VERSION 5.8 ;
BUSBITCHARS "[]" ;
DIVIDERCHAR "/" ;
UNITS
    DATABASE MICRONS 1000 ;
END UNITS

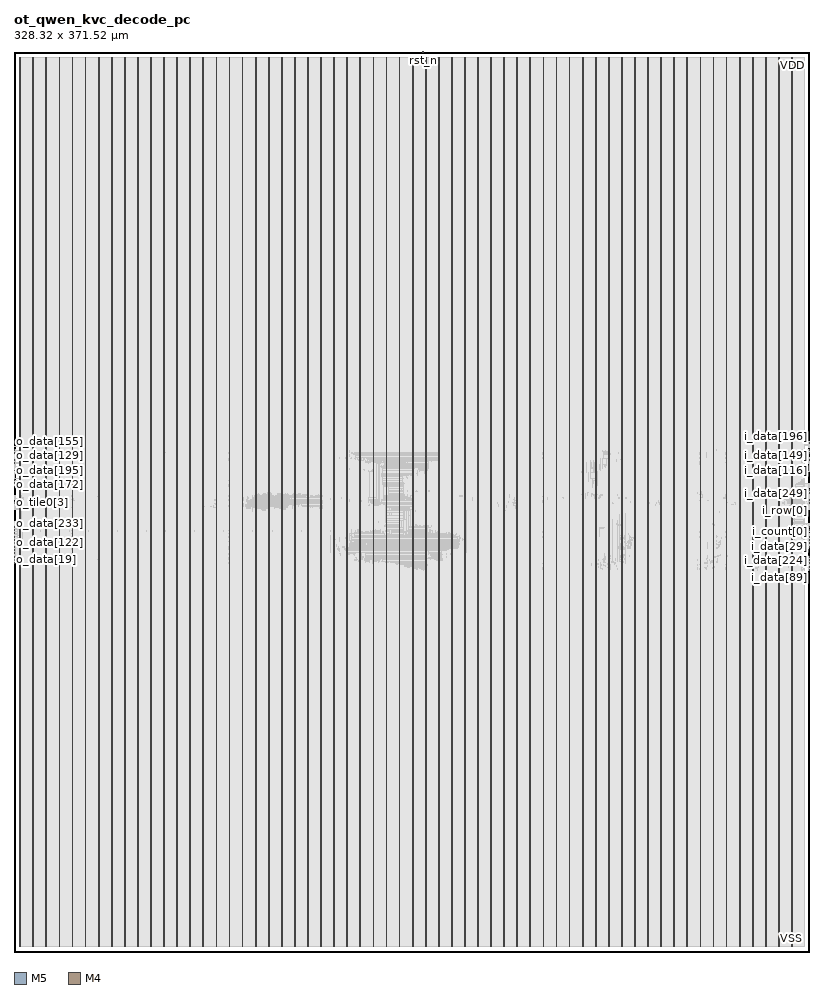
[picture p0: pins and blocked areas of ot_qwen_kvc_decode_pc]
MACRO ot_qwen_kvc_decode_pc
  FOREIGN ot_qwen_kvc_decode_pc 0 0 ;
  CLASS BLOCK ;
  SIZE 328.32 BY 371.52 ;
  PIN clk
    DIRECTION INPUT ;
    USE SIGNAL ;
    PORT
      LAYER M5 ;
        RECT  168.72 371.436 168.744 371.52 ;
    END
  END clk
  PIN fault
    DIRECTION OUTPUT ;
    USE SIGNAL ;
    PORT
      LAYER M5 ;
        RECT  168.816 371.436 168.84 371.52 ;
    END
  END fault
  PIN i_active
    DIRECTION INPUT ;
    USE SIGNAL ;
    PORT
      LAYER M4 ;
        RECT  328.236 173.52 328.32 173.544 ;
    END
  END i_active
  PIN i_count[0]
    DIRECTION INPUT ;
    USE SIGNAL ;
    PORT
      LAYER M4 ;
        RECT  328.236 173.616 328.32 173.64 ;
    END
  END i_count[0]
  PIN i_count[10]
    DIRECTION INPUT ;
    USE SIGNAL ;
    PORT
      LAYER M4 ;
        RECT  328.236 174.576 328.32 174.6 ;
    END
  END i_count[10]
  PIN i_count[1]
    DIRECTION INPUT ;
    USE SIGNAL ;
    PORT
      LAYER M4 ;
        RECT  328.236 173.712 328.32 173.736 ;
    END
  END i_count[1]
  PIN i_count[2]
    DIRECTION INPUT ;
    USE SIGNAL ;
    PORT
      LAYER M4 ;
        RECT  328.236 173.808 328.32 173.832 ;
    END
  END i_count[2]
  PIN i_count[3]
    DIRECTION INPUT ;
    USE SIGNAL ;
    PORT
      LAYER M4 ;
        RECT  328.236 173.904 328.32 173.928 ;
    END
  END i_count[3]
  PIN i_count[4]
    DIRECTION INPUT ;
    USE SIGNAL ;
    PORT
      LAYER M4 ;
        RECT  328.236 174 328.32 174.024 ;
    END
  END i_count[4]
  PIN i_count[5]
    DIRECTION INPUT ;
    USE SIGNAL ;
    PORT
      LAYER M4 ;
        RECT  328.236 174.096 328.32 174.12 ;
    END
  END i_count[5]
  PIN i_count[6]
    DIRECTION INPUT ;
    USE SIGNAL ;
    PORT
      LAYER M4 ;
        RECT  328.236 174.192 328.32 174.216 ;
    END
  END i_count[6]
  PIN i_count[7]
    DIRECTION INPUT ;
    USE SIGNAL ;
    PORT
      LAYER M4 ;
        RECT  328.236 174.288 328.32 174.312 ;
    END
  END i_count[7]
  PIN i_count[8]
    DIRECTION INPUT ;
    USE SIGNAL ;
    PORT
      LAYER M4 ;
        RECT  328.236 174.384 328.32 174.408 ;
    END
  END i_count[8]
  PIN i_count[9]
    DIRECTION INPUT ;
    USE SIGNAL ;
    PORT
      LAYER M4 ;
        RECT  328.236 174.48 328.32 174.504 ;
    END
  END i_count[9]
  PIN i_cr
    DIRECTION OUTPUT ;
    USE SIGNAL ;
    PORT
      LAYER M5 ;
        RECT  168.912 371.436 168.936 371.52 ;
    END
  END i_cr
  PIN i_data[0]
    DIRECTION INPUT ;
    USE SIGNAL ;
    PORT
      LAYER M4 ;
        RECT  328.236 174.672 328.32 174.696 ;
    END
  END i_data[0]
  PIN i_data[100]
    DIRECTION INPUT ;
    USE SIGNAL ;
    PORT
      LAYER M4 ;
        RECT  328.236 158.928 328.32 158.952 ;
    END
  END i_data[100]
  PIN i_data[101]
    DIRECTION INPUT ;
    USE SIGNAL ;
    PORT
      LAYER M4 ;
        RECT  328.236 159.024 328.32 159.048 ;
    END
  END i_data[101]
  PIN i_data[102]
    DIRECTION INPUT ;
    USE SIGNAL ;
    PORT
      LAYER M4 ;
        RECT  328.236 159.12 328.32 159.144 ;
    END
  END i_data[102]
  PIN i_data[103]
    DIRECTION INPUT ;
    USE SIGNAL ;
    PORT
      LAYER M4 ;
        RECT  328.236 159.216 328.32 159.24 ;
    END
  END i_data[103]
  PIN i_data[104]
    DIRECTION INPUT ;
    USE SIGNAL ;
    PORT
      LAYER M4 ;
        RECT  328.236 159.312 328.32 159.336 ;
    END
  END i_data[104]
  PIN i_data[105]
    DIRECTION INPUT ;
    USE SIGNAL ;
    PORT
      LAYER M4 ;
        RECT  328.236 159.408 328.32 159.432 ;
    END
  END i_data[105]
  PIN i_data[106]
    DIRECTION INPUT ;
    USE SIGNAL ;
    PORT
      LAYER M4 ;
        RECT  328.236 159.504 328.32 159.528 ;
    END
  END i_data[106]
  PIN i_data[107]
    DIRECTION INPUT ;
    USE SIGNAL ;
    PORT
      LAYER M4 ;
        RECT  328.236 159.6 328.32 159.624 ;
    END
  END i_data[107]
  PIN i_data[108]
    DIRECTION INPUT ;
    USE SIGNAL ;
    PORT
      LAYER M4 ;
        RECT  328.236 159.696 328.32 159.72 ;
    END
  END i_data[108]
  PIN i_data[109]
    DIRECTION INPUT ;
    USE SIGNAL ;
    PORT
      LAYER M4 ;
        RECT  328.236 159.792 328.32 159.816 ;
    END
  END i_data[109]
  PIN i_data[10]
    DIRECTION INPUT ;
    USE SIGNAL ;
    PORT
      LAYER M4 ;
        RECT  328.236 175.632 328.32 175.656 ;
    END
  END i_data[10]
  PIN i_data[110]
    DIRECTION INPUT ;
    USE SIGNAL ;
    PORT
      LAYER M4 ;
        RECT  328.236 159.888 328.32 159.912 ;
    END
  END i_data[110]
  PIN i_data[111]
    DIRECTION INPUT ;
    USE SIGNAL ;
    PORT
      LAYER M4 ;
        RECT  328.236 159.984 328.32 160.008 ;
    END
  END i_data[111]
  PIN i_data[112]
    DIRECTION INPUT ;
    USE SIGNAL ;
    PORT
      LAYER M4 ;
        RECT  328.236 160.08 328.32 160.104 ;
    END
  END i_data[112]
  PIN i_data[113]
    DIRECTION INPUT ;
    USE SIGNAL ;
    PORT
      LAYER M4 ;
        RECT  328.236 160.176 328.32 160.2 ;
    END
  END i_data[113]
  PIN i_data[114]
    DIRECTION INPUT ;
    USE SIGNAL ;
    PORT
      LAYER M4 ;
        RECT  328.236 160.272 328.32 160.296 ;
    END
  END i_data[114]
  PIN i_data[115]
    DIRECTION INPUT ;
    USE SIGNAL ;
    PORT
      LAYER M4 ;
        RECT  328.236 160.368 328.32 160.392 ;
    END
  END i_data[115]
  PIN i_data[116]
    DIRECTION INPUT ;
    USE SIGNAL ;
    PORT
      LAYER M4 ;
        RECT  328.236 201.936 328.32 201.96 ;
    END
  END i_data[116]
  PIN i_data[117]
    DIRECTION INPUT ;
    USE SIGNAL ;
    PORT
      LAYER M4 ;
        RECT  328.236 202.032 328.32 202.056 ;
    END
  END i_data[117]
  PIN i_data[118]
    DIRECTION INPUT ;
    USE SIGNAL ;
    PORT
      LAYER M4 ;
        RECT  328.236 202.128 328.32 202.152 ;
    END
  END i_data[118]
  PIN i_data[119]
    DIRECTION INPUT ;
    USE SIGNAL ;
    PORT
      LAYER M4 ;
        RECT  328.236 202.224 328.32 202.248 ;
    END
  END i_data[119]
  PIN i_data[11]
    DIRECTION INPUT ;
    USE SIGNAL ;
    PORT
      LAYER M4 ;
        RECT  328.236 175.728 328.32 175.752 ;
    END
  END i_data[11]
  PIN i_data[120]
    DIRECTION INPUT ;
    USE SIGNAL ;
    PORT
      LAYER M4 ;
        RECT  328.236 202.32 328.32 202.344 ;
    END
  END i_data[120]
  PIN i_data[121]
    DIRECTION INPUT ;
    USE SIGNAL ;
    PORT
      LAYER M4 ;
        RECT  328.236 202.416 328.32 202.44 ;
    END
  END i_data[121]
  PIN i_data[122]
    DIRECTION INPUT ;
    USE SIGNAL ;
    PORT
      LAYER M4 ;
        RECT  328.236 202.512 328.32 202.536 ;
    END
  END i_data[122]
  PIN i_data[123]
    DIRECTION INPUT ;
    USE SIGNAL ;
    PORT
      LAYER M4 ;
        RECT  328.236 202.608 328.32 202.632 ;
    END
  END i_data[123]
  PIN i_data[124]
    DIRECTION INPUT ;
    USE SIGNAL ;
    PORT
      LAYER M4 ;
        RECT  328.236 202.704 328.32 202.728 ;
    END
  END i_data[124]
  PIN i_data[125]
    DIRECTION INPUT ;
    USE SIGNAL ;
    PORT
      LAYER M4 ;
        RECT  328.236 202.8 328.32 202.824 ;
    END
  END i_data[125]
  PIN i_data[126]
    DIRECTION INPUT ;
    USE SIGNAL ;
    PORT
      LAYER M4 ;
        RECT  328.236 202.896 328.32 202.92 ;
    END
  END i_data[126]
  PIN i_data[127]
    DIRECTION INPUT ;
    USE SIGNAL ;
    PORT
      LAYER M4 ;
        RECT  328.236 202.992 328.32 203.016 ;
    END
  END i_data[127]
  PIN i_data[128]
    DIRECTION INPUT ;
    USE SIGNAL ;
    PORT
      LAYER M4 ;
        RECT  328.236 203.088 328.32 203.112 ;
    END
  END i_data[128]
  PIN i_data[129]
    DIRECTION INPUT ;
    USE SIGNAL ;
    PORT
      LAYER M4 ;
        RECT  328.236 203.184 328.32 203.208 ;
    END
  END i_data[129]
  PIN i_data[12]
    DIRECTION INPUT ;
    USE SIGNAL ;
    PORT
      LAYER M4 ;
        RECT  328.236 175.824 328.32 175.848 ;
    END
  END i_data[12]
  PIN i_data[130]
    DIRECTION INPUT ;
    USE SIGNAL ;
    PORT
      LAYER M4 ;
        RECT  328.236 203.28 328.32 203.304 ;
    END
  END i_data[130]
  PIN i_data[131]
    DIRECTION INPUT ;
    USE SIGNAL ;
    PORT
      LAYER M4 ;
        RECT  328.236 203.376 328.32 203.4 ;
    END
  END i_data[131]
  PIN i_data[132]
    DIRECTION INPUT ;
    USE SIGNAL ;
    PORT
      LAYER M4 ;
        RECT  328.236 203.472 328.32 203.496 ;
    END
  END i_data[132]
  PIN i_data[133]
    DIRECTION INPUT ;
    USE SIGNAL ;
    PORT
      LAYER M4 ;
        RECT  328.236 203.568 328.32 203.592 ;
    END
  END i_data[133]
  PIN i_data[134]
    DIRECTION INPUT ;
    USE SIGNAL ;
    PORT
      LAYER M4 ;
        RECT  328.236 203.664 328.32 203.688 ;
    END
  END i_data[134]
  PIN i_data[135]
    DIRECTION INPUT ;
    USE SIGNAL ;
    PORT
      LAYER M4 ;
        RECT  328.236 203.76 328.32 203.784 ;
    END
  END i_data[135]
  PIN i_data[136]
    DIRECTION INPUT ;
    USE SIGNAL ;
    PORT
      LAYER M4 ;
        RECT  328.236 203.856 328.32 203.88 ;
    END
  END i_data[136]
  PIN i_data[137]
    DIRECTION INPUT ;
    USE SIGNAL ;
    PORT
      LAYER M4 ;
        RECT  328.236 203.952 328.32 203.976 ;
    END
  END i_data[137]
  PIN i_data[138]
    DIRECTION INPUT ;
    USE SIGNAL ;
    PORT
      LAYER M4 ;
        RECT  328.236 204.048 328.32 204.072 ;
    END
  END i_data[138]
  PIN i_data[139]
    DIRECTION INPUT ;
    USE SIGNAL ;
    PORT
      LAYER M4 ;
        RECT  328.236 204.144 328.32 204.168 ;
    END
  END i_data[139]
  PIN i_data[13]
    DIRECTION INPUT ;
    USE SIGNAL ;
    PORT
      LAYER M4 ;
        RECT  328.236 175.92 328.32 175.944 ;
    END
  END i_data[13]
  PIN i_data[140]
    DIRECTION INPUT ;
    USE SIGNAL ;
    PORT
      LAYER M4 ;
        RECT  328.236 204.24 328.32 204.264 ;
    END
  END i_data[140]
  PIN i_data[141]
    DIRECTION INPUT ;
    USE SIGNAL ;
    PORT
      LAYER M4 ;
        RECT  328.236 204.336 328.32 204.36 ;
    END
  END i_data[141]
  PIN i_data[142]
    DIRECTION INPUT ;
    USE SIGNAL ;
    PORT
      LAYER M4 ;
        RECT  328.236 204.432 328.32 204.456 ;
    END
  END i_data[142]
  PIN i_data[143]
    DIRECTION INPUT ;
    USE SIGNAL ;
    PORT
      LAYER M4 ;
        RECT  328.236 204.528 328.32 204.552 ;
    END
  END i_data[143]
  PIN i_data[144]
    DIRECTION INPUT ;
    USE SIGNAL ;
    PORT
      LAYER M4 ;
        RECT  328.236 204.624 328.32 204.648 ;
    END
  END i_data[144]
  PIN i_data[145]
    DIRECTION INPUT ;
    USE SIGNAL ;
    PORT
      LAYER M4 ;
        RECT  328.236 204.72 328.32 204.744 ;
    END
  END i_data[145]
  PIN i_data[146]
    DIRECTION INPUT ;
    USE SIGNAL ;
    PORT
      LAYER M4 ;
        RECT  328.236 204.816 328.32 204.84 ;
    END
  END i_data[146]
  PIN i_data[147]
    DIRECTION INPUT ;
    USE SIGNAL ;
    PORT
      LAYER M4 ;
        RECT  328.236 204.912 328.32 204.936 ;
    END
  END i_data[147]
  PIN i_data[148]
    DIRECTION INPUT ;
    USE SIGNAL ;
    PORT
      LAYER M4 ;
        RECT  328.236 205.008 328.32 205.032 ;
    END
  END i_data[148]
  PIN i_data[149]
    DIRECTION INPUT ;
    USE SIGNAL ;
    PORT
      LAYER M4 ;
        RECT  328.236 205.104 328.32 205.128 ;
    END
  END i_data[149]
  PIN i_data[14]
    DIRECTION INPUT ;
    USE SIGNAL ;
    PORT
      LAYER M4 ;
        RECT  328.236 176.016 328.32 176.04 ;
    END
  END i_data[14]
  PIN i_data[150]
    DIRECTION INPUT ;
    USE SIGNAL ;
    PORT
      LAYER M4 ;
        RECT  328.236 205.2 328.32 205.224 ;
    END
  END i_data[150]
  PIN i_data[151]
    DIRECTION INPUT ;
    USE SIGNAL ;
    PORT
      LAYER M4 ;
        RECT  328.236 205.296 328.32 205.32 ;
    END
  END i_data[151]
  PIN i_data[152]
    DIRECTION INPUT ;
    USE SIGNAL ;
    PORT
      LAYER M4 ;
        RECT  328.236 205.392 328.32 205.416 ;
    END
  END i_data[152]
  PIN i_data[153]
    DIRECTION INPUT ;
    USE SIGNAL ;
    PORT
      LAYER M4 ;
        RECT  328.236 205.488 328.32 205.512 ;
    END
  END i_data[153]
  PIN i_data[154]
    DIRECTION INPUT ;
    USE SIGNAL ;
    PORT
      LAYER M4 ;
        RECT  328.236 205.584 328.32 205.608 ;
    END
  END i_data[154]
  PIN i_data[155]
    DIRECTION INPUT ;
    USE SIGNAL ;
    PORT
      LAYER M4 ;
        RECT  328.236 205.68 328.32 205.704 ;
    END
  END i_data[155]
  PIN i_data[156]
    DIRECTION INPUT ;
    USE SIGNAL ;
    PORT
      LAYER M4 ;
        RECT  328.236 205.776 328.32 205.8 ;
    END
  END i_data[156]
  PIN i_data[157]
    DIRECTION INPUT ;
    USE SIGNAL ;
    PORT
      LAYER M4 ;
        RECT  328.236 205.872 328.32 205.896 ;
    END
  END i_data[157]
  PIN i_data[158]
    DIRECTION INPUT ;
    USE SIGNAL ;
    PORT
      LAYER M4 ;
        RECT  328.236 205.968 328.32 205.992 ;
    END
  END i_data[158]
  PIN i_data[159]
    DIRECTION INPUT ;
    USE SIGNAL ;
    PORT
      LAYER M4 ;
        RECT  328.236 206.064 328.32 206.088 ;
    END
  END i_data[159]
  PIN i_data[15]
    DIRECTION INPUT ;
    USE SIGNAL ;
    PORT
      LAYER M4 ;
        RECT  328.236 176.112 328.32 176.136 ;
    END
  END i_data[15]
  PIN i_data[160]
    DIRECTION INPUT ;
    USE SIGNAL ;
    PORT
      LAYER M4 ;
        RECT  328.236 206.16 328.32 206.184 ;
    END
  END i_data[160]
  PIN i_data[161]
    DIRECTION INPUT ;
    USE SIGNAL ;
    PORT
      LAYER M4 ;
        RECT  328.236 206.256 328.32 206.28 ;
    END
  END i_data[161]
  PIN i_data[162]
    DIRECTION INPUT ;
    USE SIGNAL ;
    PORT
      LAYER M4 ;
        RECT  328.236 206.352 328.32 206.376 ;
    END
  END i_data[162]
  PIN i_data[163]
    DIRECTION INPUT ;
    USE SIGNAL ;
    PORT
      LAYER M4 ;
        RECT  328.236 206.448 328.32 206.472 ;
    END
  END i_data[163]
  PIN i_data[164]
    DIRECTION INPUT ;
    USE SIGNAL ;
    PORT
      LAYER M4 ;
        RECT  328.236 206.544 328.32 206.568 ;
    END
  END i_data[164]
  PIN i_data[165]
    DIRECTION INPUT ;
    USE SIGNAL ;
    PORT
      LAYER M4 ;
        RECT  328.236 206.64 328.32 206.664 ;
    END
  END i_data[165]
  PIN i_data[166]
    DIRECTION INPUT ;
    USE SIGNAL ;
    PORT
      LAYER M4 ;
        RECT  328.236 206.736 328.32 206.76 ;
    END
  END i_data[166]
  PIN i_data[167]
    DIRECTION INPUT ;
    USE SIGNAL ;
    PORT
      LAYER M4 ;
        RECT  328.236 206.832 328.32 206.856 ;
    END
  END i_data[167]
  PIN i_data[168]
    DIRECTION INPUT ;
    USE SIGNAL ;
    PORT
      LAYER M4 ;
        RECT  328.236 206.928 328.32 206.952 ;
    END
  END i_data[168]
  PIN i_data[169]
    DIRECTION INPUT ;
    USE SIGNAL ;
    PORT
      LAYER M4 ;
        RECT  328.236 207.024 328.32 207.048 ;
    END
  END i_data[169]
  PIN i_data[16]
    DIRECTION INPUT ;
    USE SIGNAL ;
    PORT
      LAYER M4 ;
        RECT  328.236 176.208 328.32 176.232 ;
    END
  END i_data[16]
  PIN i_data[170]
    DIRECTION INPUT ;
    USE SIGNAL ;
    PORT
      LAYER M4 ;
        RECT  328.236 207.12 328.32 207.144 ;
    END
  END i_data[170]
  PIN i_data[171]
    DIRECTION INPUT ;
    USE SIGNAL ;
    PORT
      LAYER M4 ;
        RECT  328.236 207.216 328.32 207.24 ;
    END
  END i_data[171]
  PIN i_data[172]
    DIRECTION INPUT ;
    USE SIGNAL ;
    PORT
      LAYER M4 ;
        RECT  328.236 207.312 328.32 207.336 ;
    END
  END i_data[172]
  PIN i_data[173]
    DIRECTION INPUT ;
    USE SIGNAL ;
    PORT
      LAYER M4 ;
        RECT  328.236 207.408 328.32 207.432 ;
    END
  END i_data[173]
  PIN i_data[174]
    DIRECTION INPUT ;
    USE SIGNAL ;
    PORT
      LAYER M4 ;
        RECT  328.236 207.504 328.32 207.528 ;
    END
  END i_data[174]
  PIN i_data[175]
    DIRECTION INPUT ;
    USE SIGNAL ;
    PORT
      LAYER M4 ;
        RECT  328.236 207.6 328.32 207.624 ;
    END
  END i_data[175]
  PIN i_data[176]
    DIRECTION INPUT ;
    USE SIGNAL ;
    PORT
      LAYER M4 ;
        RECT  328.236 207.696 328.32 207.72 ;
    END
  END i_data[176]
  PIN i_data[177]
    DIRECTION INPUT ;
    USE SIGNAL ;
    PORT
      LAYER M4 ;
        RECT  328.236 207.792 328.32 207.816 ;
    END
  END i_data[177]
  PIN i_data[178]
    DIRECTION INPUT ;
    USE SIGNAL ;
    PORT
      LAYER M4 ;
        RECT  328.236 207.888 328.32 207.912 ;
    END
  END i_data[178]
  PIN i_data[179]
    DIRECTION INPUT ;
    USE SIGNAL ;
    PORT
      LAYER M4 ;
        RECT  328.236 207.984 328.32 208.008 ;
    END
  END i_data[179]
  PIN i_data[17]
    DIRECTION INPUT ;
    USE SIGNAL ;
    PORT
      LAYER M4 ;
        RECT  328.236 176.304 328.32 176.328 ;
    END
  END i_data[17]
  PIN i_data[180]
    DIRECTION INPUT ;
    USE SIGNAL ;
    PORT
      LAYER M4 ;
        RECT  328.236 208.08 328.32 208.104 ;
    END
  END i_data[180]
  PIN i_data[181]
    DIRECTION INPUT ;
    USE SIGNAL ;
    PORT
      LAYER M4 ;
        RECT  328.236 208.176 328.32 208.2 ;
    END
  END i_data[181]
  PIN i_data[182]
    DIRECTION INPUT ;
    USE SIGNAL ;
    PORT
      LAYER M4 ;
        RECT  328.236 208.272 328.32 208.296 ;
    END
  END i_data[182]
  PIN i_data[183]
    DIRECTION INPUT ;
    USE SIGNAL ;
    PORT
      LAYER M4 ;
        RECT  328.236 208.368 328.32 208.392 ;
    END
  END i_data[183]
  PIN i_data[184]
    DIRECTION INPUT ;
    USE SIGNAL ;
    PORT
      LAYER M4 ;
        RECT  328.236 208.464 328.32 208.488 ;
    END
  END i_data[184]
  PIN i_data[185]
    DIRECTION INPUT ;
    USE SIGNAL ;
    PORT
      LAYER M4 ;
        RECT  328.236 208.56 328.32 208.584 ;
    END
  END i_data[185]
  PIN i_data[186]
    DIRECTION INPUT ;
    USE SIGNAL ;
    PORT
      LAYER M4 ;
        RECT  328.236 208.656 328.32 208.68 ;
    END
  END i_data[186]
  PIN i_data[187]
    DIRECTION INPUT ;
    USE SIGNAL ;
    PORT
      LAYER M4 ;
        RECT  328.236 208.752 328.32 208.776 ;
    END
  END i_data[187]
  PIN i_data[188]
    DIRECTION INPUT ;
    USE SIGNAL ;
    PORT
      LAYER M4 ;
        RECT  328.236 208.848 328.32 208.872 ;
    END
  END i_data[188]
  PIN i_data[189]
    DIRECTION INPUT ;
    USE SIGNAL ;
    PORT
      LAYER M4 ;
        RECT  328.236 208.944 328.32 208.968 ;
    END
  END i_data[189]
  PIN i_data[18]
    DIRECTION INPUT ;
    USE SIGNAL ;
    PORT
      LAYER M4 ;
        RECT  328.236 176.4 328.32 176.424 ;
    END
  END i_data[18]
  PIN i_data[190]
    DIRECTION INPUT ;
    USE SIGNAL ;
    PORT
      LAYER M4 ;
        RECT  328.236 209.04 328.32 209.064 ;
    END
  END i_data[190]
  PIN i_data[191]
    DIRECTION INPUT ;
    USE SIGNAL ;
    PORT
      LAYER M4 ;
        RECT  328.236 209.136 328.32 209.16 ;
    END
  END i_data[191]
  PIN i_data[192]
    DIRECTION INPUT ;
    USE SIGNAL ;
    PORT
      LAYER M4 ;
        RECT  328.236 209.232 328.32 209.256 ;
    END
  END i_data[192]
  PIN i_data[193]
    DIRECTION INPUT ;
    USE SIGNAL ;
    PORT
      LAYER M4 ;
        RECT  328.236 209.328 328.32 209.352 ;
    END
  END i_data[193]
  PIN i_data[194]
    DIRECTION INPUT ;
    USE SIGNAL ;
    PORT
      LAYER M4 ;
        RECT  328.236 209.424 328.32 209.448 ;
    END
  END i_data[194]
  PIN i_data[195]
    DIRECTION INPUT ;
    USE SIGNAL ;
    PORT
      LAYER M4 ;
        RECT  328.236 209.52 328.32 209.544 ;
    END
  END i_data[195]
  PIN i_data[196]
    DIRECTION INPUT ;
    USE SIGNAL ;
    PORT
      LAYER M4 ;
        RECT  328.236 209.616 328.32 209.64 ;
    END
  END i_data[196]
  PIN i_data[197]
    DIRECTION INPUT ;
    USE SIGNAL ;
    PORT
      LAYER M4 ;
        RECT  328.236 209.712 328.32 209.736 ;
    END
  END i_data[197]
  PIN i_data[198]
    DIRECTION INPUT ;
    USE SIGNAL ;
    PORT
      LAYER M4 ;
        RECT  328.236 209.808 328.32 209.832 ;
    END
  END i_data[198]
  PIN i_data[199]
    DIRECTION INPUT ;
    USE SIGNAL ;
    PORT
      LAYER M4 ;
        RECT  328.236 209.904 328.32 209.928 ;
    END
  END i_data[199]
  PIN i_data[19]
    DIRECTION INPUT ;
    USE SIGNAL ;
    PORT
      LAYER M4 ;
        RECT  328.236 176.496 328.32 176.52 ;
    END
  END i_data[19]
  PIN i_data[1]
    DIRECTION INPUT ;
    USE SIGNAL ;
    PORT
      LAYER M4 ;
        RECT  328.236 174.768 328.32 174.792 ;
    END
  END i_data[1]
  PIN i_data[200]
    DIRECTION INPUT ;
    USE SIGNAL ;
    PORT
      LAYER M4 ;
        RECT  328.236 210 328.32 210.024 ;
    END
  END i_data[200]
  PIN i_data[201]
    DIRECTION INPUT ;
    USE SIGNAL ;
    PORT
      LAYER M4 ;
        RECT  328.236 210.096 328.32 210.12 ;
    END
  END i_data[201]
  PIN i_data[202]
    DIRECTION INPUT ;
    USE SIGNAL ;
    PORT
      LAYER M4 ;
        RECT  328.236 210.192 328.32 210.216 ;
    END
  END i_data[202]
  PIN i_data[203]
    DIRECTION INPUT ;
    USE SIGNAL ;
    PORT
      LAYER M4 ;
        RECT  328.236 210.288 328.32 210.312 ;
    END
  END i_data[203]
  PIN i_data[204]
    DIRECTION INPUT ;
    USE SIGNAL ;
    PORT
      LAYER M4 ;
        RECT  328.236 210.384 328.32 210.408 ;
    END
  END i_data[204]
  PIN i_data[205]
    DIRECTION INPUT ;
    USE SIGNAL ;
    PORT
      LAYER M4 ;
        RECT  328.236 210.48 328.32 210.504 ;
    END
  END i_data[205]
  PIN i_data[206]
    DIRECTION INPUT ;
    USE SIGNAL ;
    PORT
      LAYER M4 ;
        RECT  328.236 210.576 328.32 210.6 ;
    END
  END i_data[206]
  PIN i_data[207]
    DIRECTION INPUT ;
    USE SIGNAL ;
    PORT
      LAYER M4 ;
        RECT  328.236 210.672 328.32 210.696 ;
    END
  END i_data[207]
  PIN i_data[208]
    DIRECTION INPUT ;
    USE SIGNAL ;
    PORT
      LAYER M4 ;
        RECT  328.236 210.768 328.32 210.792 ;
    END
  END i_data[208]
  PIN i_data[209]
    DIRECTION INPUT ;
    USE SIGNAL ;
    PORT
      LAYER M4 ;
        RECT  328.236 210.864 328.32 210.888 ;
    END
  END i_data[209]
  PIN i_data[20]
    DIRECTION INPUT ;
    USE SIGNAL ;
    PORT
      LAYER M4 ;
        RECT  328.236 166.608 328.32 166.632 ;
    END
  END i_data[20]
  PIN i_data[210]
    DIRECTION INPUT ;
    USE SIGNAL ;
    PORT
      LAYER M4 ;
        RECT  328.236 210.96 328.32 210.984 ;
    END
  END i_data[210]
  PIN i_data[211]
    DIRECTION INPUT ;
    USE SIGNAL ;
    PORT
      LAYER M4 ;
        RECT  328.236 211.056 328.32 211.08 ;
    END
  END i_data[211]
  PIN i_data[212]
    DIRECTION INPUT ;
    USE SIGNAL ;
    PORT
      LAYER M4 ;
        RECT  328.236 160.464 328.32 160.488 ;
    END
  END i_data[212]
  PIN i_data[213]
    DIRECTION INPUT ;
    USE SIGNAL ;
    PORT
      LAYER M4 ;
        RECT  328.236 160.56 328.32 160.584 ;
    END
  END i_data[213]
  PIN i_data[214]
    DIRECTION INPUT ;
    USE SIGNAL ;
    PORT
      LAYER M4 ;
        RECT  328.236 160.656 328.32 160.68 ;
    END
  END i_data[214]
  PIN i_data[215]
    DIRECTION INPUT ;
    USE SIGNAL ;
    PORT
      LAYER M4 ;
        RECT  328.236 160.752 328.32 160.776 ;
    END
  END i_data[215]
  PIN i_data[216]
    DIRECTION INPUT ;
    USE SIGNAL ;
    PORT
      LAYER M4 ;
        RECT  328.236 160.848 328.32 160.872 ;
    END
  END i_data[216]
  PIN i_data[217]
    DIRECTION INPUT ;
    USE SIGNAL ;
    PORT
      LAYER M4 ;
        RECT  328.236 160.944 328.32 160.968 ;
    END
  END i_data[217]
  PIN i_data[218]
    DIRECTION INPUT ;
    USE SIGNAL ;
    PORT
      LAYER M4 ;
        RECT  328.236 161.04 328.32 161.064 ;
    END
  END i_data[218]
  PIN i_data[219]
    DIRECTION INPUT ;
    USE SIGNAL ;
    PORT
      LAYER M4 ;
        RECT  328.236 161.136 328.32 161.16 ;
    END
  END i_data[219]
  PIN i_data[21]
    DIRECTION INPUT ;
    USE SIGNAL ;
    PORT
      LAYER M4 ;
        RECT  328.236 166.704 328.32 166.728 ;
    END
  END i_data[21]
  PIN i_data[220]
    DIRECTION INPUT ;
    USE SIGNAL ;
    PORT
      LAYER M4 ;
        RECT  328.236 161.232 328.32 161.256 ;
    END
  END i_data[220]
  PIN i_data[221]
    DIRECTION INPUT ;
    USE SIGNAL ;
    PORT
      LAYER M4 ;
        RECT  328.236 161.328 328.32 161.352 ;
    END
  END i_data[221]
  PIN i_data[222]
    DIRECTION INPUT ;
    USE SIGNAL ;
    PORT
      LAYER M4 ;
        RECT  328.236 161.424 328.32 161.448 ;
    END
  END i_data[222]
  PIN i_data[223]
    DIRECTION INPUT ;
    USE SIGNAL ;
    PORT
      LAYER M4 ;
        RECT  328.236 161.52 328.32 161.544 ;
    END
  END i_data[223]
  PIN i_data[224]
    DIRECTION INPUT ;
    USE SIGNAL ;
    PORT
      LAYER M4 ;
        RECT  328.236 161.616 328.32 161.64 ;
    END
  END i_data[224]
  PIN i_data[225]
    DIRECTION INPUT ;
    USE SIGNAL ;
    PORT
      LAYER M4 ;
        RECT  328.236 161.712 328.32 161.736 ;
    END
  END i_data[225]
  PIN i_data[226]
    DIRECTION INPUT ;
    USE SIGNAL ;
    PORT
      LAYER M4 ;
        RECT  328.236 161.808 328.32 161.832 ;
    END
  END i_data[226]
  PIN i_data[227]
    DIRECTION INPUT ;
    USE SIGNAL ;
    PORT
      LAYER M4 ;
        RECT  328.236 161.904 328.32 161.928 ;
    END
  END i_data[227]
  PIN i_data[228]
    DIRECTION INPUT ;
    USE SIGNAL ;
    PORT
      LAYER M4 ;
        RECT  328.236 162 328.32 162.024 ;
    END
  END i_data[228]
  PIN i_data[229]
    DIRECTION INPUT ;
    USE SIGNAL ;
    PORT
      LAYER M4 ;
        RECT  328.236 162.096 328.32 162.12 ;
    END
  END i_data[229]
  PIN i_data[22]
    DIRECTION INPUT ;
    USE SIGNAL ;
    PORT
      LAYER M4 ;
        RECT  328.236 166.8 328.32 166.824 ;
    END
  END i_data[22]
  PIN i_data[230]
    DIRECTION INPUT ;
    USE SIGNAL ;
    PORT
      LAYER M4 ;
        RECT  328.236 162.192 328.32 162.216 ;
    END
  END i_data[230]
  PIN i_data[231]
    DIRECTION INPUT ;
    USE SIGNAL ;
    PORT
      LAYER M4 ;
        RECT  328.236 162.288 328.32 162.312 ;
    END
  END i_data[231]
  PIN i_data[232]
    DIRECTION INPUT ;
    USE SIGNAL ;
    PORT
      LAYER M4 ;
        RECT  328.236 162.384 328.32 162.408 ;
    END
  END i_data[232]
  PIN i_data[233]
    DIRECTION INPUT ;
    USE SIGNAL ;
    PORT
      LAYER M4 ;
        RECT  328.236 162.48 328.32 162.504 ;
    END
  END i_data[233]
  PIN i_data[234]
    DIRECTION INPUT ;
    USE SIGNAL ;
    PORT
      LAYER M4 ;
        RECT  328.236 162.576 328.32 162.6 ;
    END
  END i_data[234]
  PIN i_data[235]
    DIRECTION INPUT ;
    USE SIGNAL ;
    PORT
      LAYER M4 ;
        RECT  328.236 162.672 328.32 162.696 ;
    END
  END i_data[235]
  PIN i_data[236]
    DIRECTION INPUT ;
    USE SIGNAL ;
    PORT
      LAYER M4 ;
        RECT  328.236 162.768 328.32 162.792 ;
    END
  END i_data[236]
  PIN i_data[237]
    DIRECTION INPUT ;
    USE SIGNAL ;
    PORT
      LAYER M4 ;
        RECT  328.236 162.864 328.32 162.888 ;
    END
  END i_data[237]
  PIN i_data[238]
    DIRECTION INPUT ;
    USE SIGNAL ;
    PORT
      LAYER M4 ;
        RECT  328.236 162.96 328.32 162.984 ;
    END
  END i_data[238]
  PIN i_data[239]
    DIRECTION INPUT ;
    USE SIGNAL ;
    PORT
      LAYER M4 ;
        RECT  328.236 163.056 328.32 163.08 ;
    END
  END i_data[239]
  PIN i_data[23]
    DIRECTION INPUT ;
    USE SIGNAL ;
    PORT
      LAYER M4 ;
        RECT  328.236 166.896 328.32 166.92 ;
    END
  END i_data[23]
  PIN i_data[240]
    DIRECTION INPUT ;
    USE SIGNAL ;
    PORT
      LAYER M4 ;
        RECT  328.236 163.152 328.32 163.176 ;
    END
  END i_data[240]
  PIN i_data[241]
    DIRECTION INPUT ;
    USE SIGNAL ;
    PORT
      LAYER M4 ;
        RECT  328.236 163.248 328.32 163.272 ;
    END
  END i_data[241]
  PIN i_data[242]
    DIRECTION INPUT ;
    USE SIGNAL ;
    PORT
      LAYER M4 ;
        RECT  328.236 163.344 328.32 163.368 ;
    END
  END i_data[242]
  PIN i_data[243]
    DIRECTION INPUT ;
    USE SIGNAL ;
    PORT
      LAYER M4 ;
        RECT  328.236 163.44 328.32 163.464 ;
    END
  END i_data[243]
  PIN i_data[244]
    DIRECTION INPUT ;
    USE SIGNAL ;
    PORT
      LAYER M4 ;
        RECT  328.236 188.88 328.32 188.904 ;
    END
  END i_data[244]
  PIN i_data[245]
    DIRECTION INPUT ;
    USE SIGNAL ;
    PORT
      LAYER M4 ;
        RECT  328.236 188.976 328.32 189 ;
    END
  END i_data[245]
  PIN i_data[246]
    DIRECTION INPUT ;
    USE SIGNAL ;
    PORT
      LAYER M4 ;
        RECT  328.236 189.072 328.32 189.096 ;
    END
  END i_data[246]
  PIN i_data[247]
    DIRECTION INPUT ;
    USE SIGNAL ;
    PORT
      LAYER M4 ;
        RECT  328.236 189.168 328.32 189.192 ;
    END
  END i_data[247]
  PIN i_data[248]
    DIRECTION INPUT ;
    USE SIGNAL ;
    PORT
      LAYER M4 ;
        RECT  328.236 189.264 328.32 189.288 ;
    END
  END i_data[248]
  PIN i_data[249]
    DIRECTION INPUT ;
    USE SIGNAL ;
    PORT
      LAYER M4 ;
        RECT  328.236 189.36 328.32 189.384 ;
    END
  END i_data[249]
  PIN i_data[24]
    DIRECTION INPUT ;
    USE SIGNAL ;
    PORT
      LAYER M4 ;
        RECT  328.236 166.992 328.32 167.016 ;
    END
  END i_data[24]
  PIN i_data[250]
    DIRECTION INPUT ;
    USE SIGNAL ;
    PORT
      LAYER M4 ;
        RECT  328.236 189.456 328.32 189.48 ;
    END
  END i_data[250]
  PIN i_data[251]
    DIRECTION INPUT ;
    USE SIGNAL ;
    PORT
      LAYER M4 ;
        RECT  328.236 189.552 328.32 189.576 ;
    END
  END i_data[251]
  PIN i_data[252]
    DIRECTION INPUT ;
    USE SIGNAL ;
    PORT
      LAYER M4 ;
        RECT  328.236 189.648 328.32 189.672 ;
    END
  END i_data[252]
  PIN i_data[253]
    DIRECTION INPUT ;
    USE SIGNAL ;
    PORT
      LAYER M4 ;
        RECT  328.236 189.744 328.32 189.768 ;
    END
  END i_data[253]
  PIN i_data[254]
    DIRECTION INPUT ;
    USE SIGNAL ;
    PORT
      LAYER M4 ;
        RECT  328.236 189.84 328.32 189.864 ;
    END
  END i_data[254]
  PIN i_data[255]
    DIRECTION INPUT ;
    USE SIGNAL ;
    PORT
      LAYER M4 ;
        RECT  328.236 189.936 328.32 189.96 ;
    END
  END i_data[255]
  PIN i_data[25]
    DIRECTION INPUT ;
    USE SIGNAL ;
    PORT
      LAYER M4 ;
        RECT  328.236 167.088 328.32 167.112 ;
    END
  END i_data[25]
  PIN i_data[26]
    DIRECTION INPUT ;
    USE SIGNAL ;
    PORT
      LAYER M4 ;
        RECT  328.236 167.184 328.32 167.208 ;
    END
  END i_data[26]
  PIN i_data[27]
    DIRECTION INPUT ;
    USE SIGNAL ;
    PORT
      LAYER M4 ;
        RECT  328.236 167.28 328.32 167.304 ;
    END
  END i_data[27]
  PIN i_data[28]
    DIRECTION INPUT ;
    USE SIGNAL ;
    PORT
      LAYER M4 ;
        RECT  328.236 167.376 328.32 167.4 ;
    END
  END i_data[28]
  PIN i_data[29]
    DIRECTION INPUT ;
    USE SIGNAL ;
    PORT
      LAYER M4 ;
        RECT  328.236 167.472 328.32 167.496 ;
    END
  END i_data[29]
  PIN i_data[2]
    DIRECTION INPUT ;
    USE SIGNAL ;
    PORT
      LAYER M4 ;
        RECT  328.236 174.864 328.32 174.888 ;
    END
  END i_data[2]
  PIN i_data[30]
    DIRECTION INPUT ;
    USE SIGNAL ;
    PORT
      LAYER M4 ;
        RECT  328.236 167.568 328.32 167.592 ;
    END
  END i_data[30]
  PIN i_data[31]
    DIRECTION INPUT ;
    USE SIGNAL ;
    PORT
      LAYER M4 ;
        RECT  328.236 167.664 328.32 167.688 ;
    END
  END i_data[31]
  PIN i_data[32]
    DIRECTION INPUT ;
    USE SIGNAL ;
    PORT
      LAYER M4 ;
        RECT  328.236 167.76 328.32 167.784 ;
    END
  END i_data[32]
  PIN i_data[33]
    DIRECTION INPUT ;
    USE SIGNAL ;
    PORT
      LAYER M4 ;
        RECT  328.236 167.856 328.32 167.88 ;
    END
  END i_data[33]
  PIN i_data[34]
    DIRECTION INPUT ;
    USE SIGNAL ;
    PORT
      LAYER M4 ;
        RECT  328.236 167.952 328.32 167.976 ;
    END
  END i_data[34]
  PIN i_data[35]
    DIRECTION INPUT ;
    USE SIGNAL ;
    PORT
      LAYER M4 ;
        RECT  328.236 168.048 328.32 168.072 ;
    END
  END i_data[35]
  PIN i_data[36]
    DIRECTION INPUT ;
    USE SIGNAL ;
    PORT
      LAYER M4 ;
        RECT  328.236 168.144 328.32 168.168 ;
    END
  END i_data[36]
  PIN i_data[37]
    DIRECTION INPUT ;
    USE SIGNAL ;
    PORT
      LAYER M4 ;
        RECT  328.236 168.24 328.32 168.264 ;
    END
  END i_data[37]
  PIN i_data[38]
    DIRECTION INPUT ;
    USE SIGNAL ;
    PORT
      LAYER M4 ;
        RECT  328.236 168.336 328.32 168.36 ;
    END
  END i_data[38]
  PIN i_data[39]
    DIRECTION INPUT ;
    USE SIGNAL ;
    PORT
      LAYER M4 ;
        RECT  328.236 168.432 328.32 168.456 ;
    END
  END i_data[39]
  PIN i_data[3]
    DIRECTION INPUT ;
    USE SIGNAL ;
    PORT
      LAYER M4 ;
        RECT  328.236 174.96 328.32 174.984 ;
    END
  END i_data[3]
  PIN i_data[40]
    DIRECTION INPUT ;
    USE SIGNAL ;
    PORT
      LAYER M4 ;
        RECT  328.236 168.528 328.32 168.552 ;
    END
  END i_data[40]
  PIN i_data[41]
    DIRECTION INPUT ;
    USE SIGNAL ;
    PORT
      LAYER M4 ;
        RECT  328.236 168.624 328.32 168.648 ;
    END
  END i_data[41]
  PIN i_data[42]
    DIRECTION INPUT ;
    USE SIGNAL ;
    PORT
      LAYER M4 ;
        RECT  328.236 168.72 328.32 168.744 ;
    END
  END i_data[42]
  PIN i_data[43]
    DIRECTION INPUT ;
    USE SIGNAL ;
    PORT
      LAYER M4 ;
        RECT  328.236 168.816 328.32 168.84 ;
    END
  END i_data[43]
  PIN i_data[44]
    DIRECTION INPUT ;
    USE SIGNAL ;
    PORT
      LAYER M4 ;
        RECT  328.236 168.912 328.32 168.936 ;
    END
  END i_data[44]
  PIN i_data[45]
    DIRECTION INPUT ;
    USE SIGNAL ;
    PORT
      LAYER M4 ;
        RECT  328.236 169.008 328.32 169.032 ;
    END
  END i_data[45]
  PIN i_data[46]
    DIRECTION INPUT ;
    USE SIGNAL ;
    PORT
      LAYER M4 ;
        RECT  328.236 169.104 328.32 169.128 ;
    END
  END i_data[46]
  PIN i_data[47]
    DIRECTION INPUT ;
    USE SIGNAL ;
    PORT
      LAYER M4 ;
        RECT  328.236 169.2 328.32 169.224 ;
    END
  END i_data[47]
  PIN i_data[48]
    DIRECTION INPUT ;
    USE SIGNAL ;
    PORT
      LAYER M4 ;
        RECT  328.236 169.296 328.32 169.32 ;
    END
  END i_data[48]
  PIN i_data[49]
    DIRECTION INPUT ;
    USE SIGNAL ;
    PORT
      LAYER M4 ;
        RECT  328.236 169.392 328.32 169.416 ;
    END
  END i_data[49]
  PIN i_data[4]
    DIRECTION INPUT ;
    USE SIGNAL ;
    PORT
      LAYER M4 ;
        RECT  328.236 175.056 328.32 175.08 ;
    END
  END i_data[4]
  PIN i_data[50]
    DIRECTION INPUT ;
    USE SIGNAL ;
    PORT
      LAYER M4 ;
        RECT  328.236 169.488 328.32 169.512 ;
    END
  END i_data[50]
  PIN i_data[51]
    DIRECTION INPUT ;
    USE SIGNAL ;
    PORT
      LAYER M4 ;
        RECT  328.236 169.584 328.32 169.608 ;
    END
  END i_data[51]
  PIN i_data[52]
    DIRECTION INPUT ;
    USE SIGNAL ;
    PORT
      LAYER M4 ;
        RECT  328.236 169.68 328.32 169.704 ;
    END
  END i_data[52]
  PIN i_data[53]
    DIRECTION INPUT ;
    USE SIGNAL ;
    PORT
      LAYER M4 ;
        RECT  328.236 169.776 328.32 169.8 ;
    END
  END i_data[53]
  PIN i_data[54]
    DIRECTION INPUT ;
    USE SIGNAL ;
    PORT
      LAYER M4 ;
        RECT  328.236 169.872 328.32 169.896 ;
    END
  END i_data[54]
  PIN i_data[55]
    DIRECTION INPUT ;
    USE SIGNAL ;
    PORT
      LAYER M4 ;
        RECT  328.236 169.968 328.32 169.992 ;
    END
  END i_data[55]
  PIN i_data[56]
    DIRECTION INPUT ;
    USE SIGNAL ;
    PORT
      LAYER M4 ;
        RECT  328.236 170.064 328.32 170.088 ;
    END
  END i_data[56]
  PIN i_data[57]
    DIRECTION INPUT ;
    USE SIGNAL ;
    PORT
      LAYER M4 ;
        RECT  328.236 170.16 328.32 170.184 ;
    END
  END i_data[57]
  PIN i_data[58]
    DIRECTION INPUT ;
    USE SIGNAL ;
    PORT
      LAYER M4 ;
        RECT  328.236 170.256 328.32 170.28 ;
    END
  END i_data[58]
  PIN i_data[59]
    DIRECTION INPUT ;
    USE SIGNAL ;
    PORT
      LAYER M4 ;
        RECT  328.236 170.352 328.32 170.376 ;
    END
  END i_data[59]
  PIN i_data[5]
    DIRECTION INPUT ;
    USE SIGNAL ;
    PORT
      LAYER M4 ;
        RECT  328.236 175.152 328.32 175.176 ;
    END
  END i_data[5]
  PIN i_data[60]
    DIRECTION INPUT ;
    USE SIGNAL ;
    PORT
      LAYER M4 ;
        RECT  328.236 170.448 328.32 170.472 ;
    END
  END i_data[60]
  PIN i_data[61]
    DIRECTION INPUT ;
    USE SIGNAL ;
    PORT
      LAYER M4 ;
        RECT  328.236 170.544 328.32 170.568 ;
    END
  END i_data[61]
  PIN i_data[62]
    DIRECTION INPUT ;
    USE SIGNAL ;
    PORT
      LAYER M4 ;
        RECT  328.236 170.64 328.32 170.664 ;
    END
  END i_data[62]
  PIN i_data[63]
    DIRECTION INPUT ;
    USE SIGNAL ;
    PORT
      LAYER M4 ;
        RECT  328.236 170.736 328.32 170.76 ;
    END
  END i_data[63]
  PIN i_data[64]
    DIRECTION INPUT ;
    USE SIGNAL ;
    PORT
      LAYER M4 ;
        RECT  328.236 170.832 328.32 170.856 ;
    END
  END i_data[64]
  PIN i_data[65]
    DIRECTION INPUT ;
    USE SIGNAL ;
    PORT
      LAYER M4 ;
        RECT  328.236 170.928 328.32 170.952 ;
    END
  END i_data[65]
  PIN i_data[66]
    DIRECTION INPUT ;
    USE SIGNAL ;
    PORT
      LAYER M4 ;
        RECT  328.236 171.024 328.32 171.048 ;
    END
  END i_data[66]
  PIN i_data[67]
    DIRECTION INPUT ;
    USE SIGNAL ;
    PORT
      LAYER M4 ;
        RECT  328.236 171.12 328.32 171.144 ;
    END
  END i_data[67]
  PIN i_data[68]
    DIRECTION INPUT ;
    USE SIGNAL ;
    PORT
      LAYER M4 ;
        RECT  328.236 171.216 328.32 171.24 ;
    END
  END i_data[68]
  PIN i_data[69]
    DIRECTION INPUT ;
    USE SIGNAL ;
    PORT
      LAYER M4 ;
        RECT  328.236 171.312 328.32 171.336 ;
    END
  END i_data[69]
  PIN i_data[6]
    DIRECTION INPUT ;
    USE SIGNAL ;
    PORT
      LAYER M4 ;
        RECT  328.236 175.248 328.32 175.272 ;
    END
  END i_data[6]
  PIN i_data[70]
    DIRECTION INPUT ;
    USE SIGNAL ;
    PORT
      LAYER M4 ;
        RECT  328.236 171.408 328.32 171.432 ;
    END
  END i_data[70]
  PIN i_data[71]
    DIRECTION INPUT ;
    USE SIGNAL ;
    PORT
      LAYER M4 ;
        RECT  328.236 171.504 328.32 171.528 ;
    END
  END i_data[71]
  PIN i_data[72]
    DIRECTION INPUT ;
    USE SIGNAL ;
    PORT
      LAYER M4 ;
        RECT  328.236 171.6 328.32 171.624 ;
    END
  END i_data[72]
  PIN i_data[73]
    DIRECTION INPUT ;
    USE SIGNAL ;
    PORT
      LAYER M4 ;
        RECT  328.236 171.696 328.32 171.72 ;
    END
  END i_data[73]
  PIN i_data[74]
    DIRECTION INPUT ;
    USE SIGNAL ;
    PORT
      LAYER M4 ;
        RECT  328.236 171.792 328.32 171.816 ;
    END
  END i_data[74]
  PIN i_data[75]
    DIRECTION INPUT ;
    USE SIGNAL ;
    PORT
      LAYER M4 ;
        RECT  328.236 171.888 328.32 171.912 ;
    END
  END i_data[75]
  PIN i_data[76]
    DIRECTION INPUT ;
    USE SIGNAL ;
    PORT
      LAYER M4 ;
        RECT  328.236 171.984 328.32 172.008 ;
    END
  END i_data[76]
  PIN i_data[77]
    DIRECTION INPUT ;
    USE SIGNAL ;
    PORT
      LAYER M4 ;
        RECT  328.236 172.08 328.32 172.104 ;
    END
  END i_data[77]
  PIN i_data[78]
    DIRECTION INPUT ;
    USE SIGNAL ;
    PORT
      LAYER M4 ;
        RECT  328.236 172.176 328.32 172.2 ;
    END
  END i_data[78]
  PIN i_data[79]
    DIRECTION INPUT ;
    USE SIGNAL ;
    PORT
      LAYER M4 ;
        RECT  328.236 172.272 328.32 172.296 ;
    END
  END i_data[79]
  PIN i_data[7]
    DIRECTION INPUT ;
    USE SIGNAL ;
    PORT
      LAYER M4 ;
        RECT  328.236 175.344 328.32 175.368 ;
    END
  END i_data[7]
  PIN i_data[80]
    DIRECTION INPUT ;
    USE SIGNAL ;
    PORT
      LAYER M4 ;
        RECT  328.236 172.368 328.32 172.392 ;
    END
  END i_data[80]
  PIN i_data[81]
    DIRECTION INPUT ;
    USE SIGNAL ;
    PORT
      LAYER M4 ;
        RECT  328.236 172.464 328.32 172.488 ;
    END
  END i_data[81]
  PIN i_data[82]
    DIRECTION INPUT ;
    USE SIGNAL ;
    PORT
      LAYER M4 ;
        RECT  328.236 172.56 328.32 172.584 ;
    END
  END i_data[82]
  PIN i_data[83]
    DIRECTION INPUT ;
    USE SIGNAL ;
    PORT
      LAYER M4 ;
        RECT  328.236 172.656 328.32 172.68 ;
    END
  END i_data[83]
  PIN i_data[84]
    DIRECTION INPUT ;
    USE SIGNAL ;
    PORT
      LAYER M4 ;
        RECT  328.236 157.392 328.32 157.416 ;
    END
  END i_data[84]
  PIN i_data[85]
    DIRECTION INPUT ;
    USE SIGNAL ;
    PORT
      LAYER M4 ;
        RECT  328.236 157.488 328.32 157.512 ;
    END
  END i_data[85]
  PIN i_data[86]
    DIRECTION INPUT ;
    USE SIGNAL ;
    PORT
      LAYER M4 ;
        RECT  328.236 157.584 328.32 157.608 ;
    END
  END i_data[86]
  PIN i_data[87]
    DIRECTION INPUT ;
    USE SIGNAL ;
    PORT
      LAYER M4 ;
        RECT  328.236 157.68 328.32 157.704 ;
    END
  END i_data[87]
  PIN i_data[88]
    DIRECTION INPUT ;
    USE SIGNAL ;
    PORT
      LAYER M4 ;
        RECT  328.236 157.776 328.32 157.8 ;
    END
  END i_data[88]
  PIN i_data[89]
    DIRECTION INPUT ;
    USE SIGNAL ;
    PORT
      LAYER M4 ;
        RECT  328.236 157.872 328.32 157.896 ;
    END
  END i_data[89]
  PIN i_data[8]
    DIRECTION INPUT ;
    USE SIGNAL ;
    PORT
      LAYER M4 ;
        RECT  328.236 175.44 328.32 175.464 ;
    END
  END i_data[8]
  PIN i_data[90]
    DIRECTION INPUT ;
    USE SIGNAL ;
    PORT
      LAYER M4 ;
        RECT  328.236 157.968 328.32 157.992 ;
    END
  END i_data[90]
  PIN i_data[91]
    DIRECTION INPUT ;
    USE SIGNAL ;
    PORT
      LAYER M4 ;
        RECT  328.236 158.064 328.32 158.088 ;
    END
  END i_data[91]
  PIN i_data[92]
    DIRECTION INPUT ;
    USE SIGNAL ;
    PORT
      LAYER M4 ;
        RECT  328.236 158.16 328.32 158.184 ;
    END
  END i_data[92]
  PIN i_data[93]
    DIRECTION INPUT ;
    USE SIGNAL ;
    PORT
      LAYER M4 ;
        RECT  328.236 158.256 328.32 158.28 ;
    END
  END i_data[93]
  PIN i_data[94]
    DIRECTION INPUT ;
    USE SIGNAL ;
    PORT
      LAYER M4 ;
        RECT  328.236 158.352 328.32 158.376 ;
    END
  END i_data[94]
  PIN i_data[95]
    DIRECTION INPUT ;
    USE SIGNAL ;
    PORT
      LAYER M4 ;
        RECT  328.236 158.448 328.32 158.472 ;
    END
  END i_data[95]
  PIN i_data[96]
    DIRECTION INPUT ;
    USE SIGNAL ;
    PORT
      LAYER M4 ;
        RECT  328.236 158.544 328.32 158.568 ;
    END
  END i_data[96]
  PIN i_data[97]
    DIRECTION INPUT ;
    USE SIGNAL ;
    PORT
      LAYER M4 ;
        RECT  328.236 158.64 328.32 158.664 ;
    END
  END i_data[97]
  PIN i_data[98]
    DIRECTION INPUT ;
    USE SIGNAL ;
    PORT
      LAYER M4 ;
        RECT  328.236 158.736 328.32 158.76 ;
    END
  END i_data[98]
  PIN i_data[99]
    DIRECTION INPUT ;
    USE SIGNAL ;
    PORT
      LAYER M4 ;
        RECT  328.236 158.832 328.32 158.856 ;
    END
  END i_data[99]
  PIN i_data[9]
    DIRECTION INPUT ;
    USE SIGNAL ;
    PORT
      LAYER M4 ;
        RECT  328.236 175.536 328.32 175.56 ;
    END
  END i_data[9]
  PIN i_done
    DIRECTION INPUT ;
    USE SIGNAL ;
    PORT
      LAYER M4 ;
        RECT  328.236 190.032 328.32 190.056 ;
    END
  END i_done
  PIN i_expected[0]
    DIRECTION INPUT ;
    USE SIGNAL ;
    PORT
      LAYER M4 ;
        RECT  328.236 190.128 328.32 190.152 ;
    END
  END i_expected[0]
  PIN i_expected[10]
    DIRECTION INPUT ;
    USE SIGNAL ;
    PORT
      LAYER M4 ;
        RECT  328.236 191.088 328.32 191.112 ;
    END
  END i_expected[10]
  PIN i_expected[11]
    DIRECTION INPUT ;
    USE SIGNAL ;
    PORT
      LAYER M4 ;
        RECT  328.236 191.184 328.32 191.208 ;
    END
  END i_expected[11]
  PIN i_expected[12]
    DIRECTION INPUT ;
    USE SIGNAL ;
    PORT
      LAYER M4 ;
        RECT  328.236 191.28 328.32 191.304 ;
    END
  END i_expected[12]
  PIN i_expected[13]
    DIRECTION INPUT ;
    USE SIGNAL ;
    PORT
      LAYER M4 ;
        RECT  328.236 191.376 328.32 191.4 ;
    END
  END i_expected[13]
  PIN i_expected[14]
    DIRECTION INPUT ;
    USE SIGNAL ;
    PORT
      LAYER M4 ;
        RECT  328.236 191.472 328.32 191.496 ;
    END
  END i_expected[14]
  PIN i_expected[15]
    DIRECTION INPUT ;
    USE SIGNAL ;
    PORT
      LAYER M4 ;
        RECT  328.236 191.568 328.32 191.592 ;
    END
  END i_expected[15]
  PIN i_expected[16]
    DIRECTION INPUT ;
    USE SIGNAL ;
    PORT
      LAYER M4 ;
        RECT  328.236 191.664 328.32 191.688 ;
    END
  END i_expected[16]
  PIN i_expected[1]
    DIRECTION INPUT ;
    USE SIGNAL ;
    PORT
      LAYER M4 ;
        RECT  328.236 190.224 328.32 190.248 ;
    END
  END i_expected[1]
  PIN i_expected[2]
    DIRECTION INPUT ;
    USE SIGNAL ;
    PORT
      LAYER M4 ;
        RECT  328.236 190.32 328.32 190.344 ;
    END
  END i_expected[2]
  PIN i_expected[3]
    DIRECTION INPUT ;
    USE SIGNAL ;
    PORT
      LAYER M4 ;
        RECT  328.236 190.416 328.32 190.44 ;
    END
  END i_expected[3]
  PIN i_expected[4]
    DIRECTION INPUT ;
    USE SIGNAL ;
    PORT
      LAYER M4 ;
        RECT  328.236 190.512 328.32 190.536 ;
    END
  END i_expected[4]
  PIN i_expected[5]
    DIRECTION INPUT ;
    USE SIGNAL ;
    PORT
      LAYER M4 ;
        RECT  328.236 190.608 328.32 190.632 ;
    END
  END i_expected[5]
  PIN i_expected[6]
    DIRECTION INPUT ;
    USE SIGNAL ;
    PORT
      LAYER M4 ;
        RECT  328.236 190.704 328.32 190.728 ;
    END
  END i_expected[6]
  PIN i_expected[7]
    DIRECTION INPUT ;
    USE SIGNAL ;
    PORT
      LAYER M4 ;
        RECT  328.236 190.8 328.32 190.824 ;
    END
  END i_expected[7]
  PIN i_expected[8]
    DIRECTION INPUT ;
    USE SIGNAL ;
    PORT
      LAYER M4 ;
        RECT  328.236 190.896 328.32 190.92 ;
    END
  END i_expected[8]
  PIN i_expected[9]
    DIRECTION INPUT ;
    USE SIGNAL ;
    PORT
      LAYER M4 ;
        RECT  328.236 190.992 328.32 191.016 ;
    END
  END i_expected[9]
  PIN i_layer[0]
    DIRECTION INPUT ;
    USE SIGNAL ;
    PORT
      LAYER M4 ;
        RECT  328.236 191.76 328.32 191.784 ;
    END
  END i_layer[0]
  PIN i_layer[1]
    DIRECTION INPUT ;
    USE SIGNAL ;
    PORT
      LAYER M4 ;
        RECT  328.236 191.856 328.32 191.88 ;
    END
  END i_layer[1]
  PIN i_layer[2]
    DIRECTION INPUT ;
    USE SIGNAL ;
    PORT
      LAYER M4 ;
        RECT  328.236 182.736 328.32 182.76 ;
    END
  END i_layer[2]
  PIN i_layer[3]
    DIRECTION INPUT ;
    USE SIGNAL ;
    PORT
      LAYER M4 ;
        RECT  328.236 182.832 328.32 182.856 ;
    END
  END i_layer[3]
  PIN i_layer[4]
    DIRECTION INPUT ;
    USE SIGNAL ;
    PORT
      LAYER M4 ;
        RECT  328.236 182.928 328.32 182.952 ;
    END
  END i_layer[4]
  PIN i_layer[5]
    DIRECTION INPUT ;
    USE SIGNAL ;
    PORT
      LAYER M4 ;
        RECT  328.236 183.024 328.32 183.048 ;
    END
  END i_layer[5]
  PIN i_layer[6]
    DIRECTION INPUT ;
    USE SIGNAL ;
    PORT
      LAYER M4 ;
        RECT  328.236 183.12 328.32 183.144 ;
    END
  END i_layer[6]
  PIN i_layer[7]
    DIRECTION INPUT ;
    USE SIGNAL ;
    PORT
      LAYER M4 ;
        RECT  328.236 183.216 328.32 183.24 ;
    END
  END i_layer[7]
  PIN i_limit[0]
    DIRECTION INPUT ;
    USE SIGNAL ;
    PORT
      LAYER M4 ;
        RECT  328.236 183.312 328.32 183.336 ;
    END
  END i_limit[0]
  PIN i_limit[10]
    DIRECTION INPUT ;
    USE SIGNAL ;
    PORT
      LAYER M4 ;
        RECT  328.236 184.272 328.32 184.296 ;
    END
  END i_limit[10]
  PIN i_limit[1]
    DIRECTION INPUT ;
    USE SIGNAL ;
    PORT
      LAYER M4 ;
        RECT  328.236 183.408 328.32 183.432 ;
    END
  END i_limit[1]
  PIN i_limit[2]
    DIRECTION INPUT ;
    USE SIGNAL ;
    PORT
      LAYER M4 ;
        RECT  328.236 183.504 328.32 183.528 ;
    END
  END i_limit[2]
  PIN i_limit[3]
    DIRECTION INPUT ;
    USE SIGNAL ;
    PORT
      LAYER M4 ;
        RECT  328.236 183.6 328.32 183.624 ;
    END
  END i_limit[3]
  PIN i_limit[4]
    DIRECTION INPUT ;
    USE SIGNAL ;
    PORT
      LAYER M4 ;
        RECT  328.236 183.696 328.32 183.72 ;
    END
  END i_limit[4]
  PIN i_limit[5]
    DIRECTION INPUT ;
    USE SIGNAL ;
    PORT
      LAYER M4 ;
        RECT  328.236 183.792 328.32 183.816 ;
    END
  END i_limit[5]
  PIN i_limit[6]
    DIRECTION INPUT ;
    USE SIGNAL ;
    PORT
      LAYER M4 ;
        RECT  328.236 183.888 328.32 183.912 ;
    END
  END i_limit[6]
  PIN i_limit[7]
    DIRECTION INPUT ;
    USE SIGNAL ;
    PORT
      LAYER M4 ;
        RECT  328.236 183.984 328.32 184.008 ;
    END
  END i_limit[7]
  PIN i_limit[8]
    DIRECTION INPUT ;
    USE SIGNAL ;
    PORT
      LAYER M4 ;
        RECT  328.236 184.08 328.32 184.104 ;
    END
  END i_limit[8]
  PIN i_limit[9]
    DIRECTION INPUT ;
    USE SIGNAL ;
    PORT
      LAYER M4 ;
        RECT  328.236 184.176 328.32 184.2 ;
    END
  END i_limit[9]
  PIN i_pos[0]
    DIRECTION INPUT ;
    USE SIGNAL ;
    PORT
      LAYER M4 ;
        RECT  328.236 184.368 328.32 184.392 ;
    END
  END i_pos[0]
  PIN i_pos[10]
    DIRECTION INPUT ;
    USE SIGNAL ;
    PORT
      LAYER M4 ;
        RECT  328.236 185.328 328.32 185.352 ;
    END
  END i_pos[10]
  PIN i_pos[11]
    DIRECTION INPUT ;
    USE SIGNAL ;
    PORT
      LAYER M4 ;
        RECT  328.236 185.424 328.32 185.448 ;
    END
  END i_pos[11]
  PIN i_pos[12]
    DIRECTION INPUT ;
    USE SIGNAL ;
    PORT
      LAYER M4 ;
        RECT  328.236 185.52 328.32 185.544 ;
    END
  END i_pos[12]
  PIN i_pos[1]
    DIRECTION INPUT ;
    USE SIGNAL ;
    PORT
      LAYER M4 ;
        RECT  328.236 184.464 328.32 184.488 ;
    END
  END i_pos[1]
  PIN i_pos[2]
    DIRECTION INPUT ;
    USE SIGNAL ;
    PORT
      LAYER M4 ;
        RECT  328.236 184.56 328.32 184.584 ;
    END
  END i_pos[2]
  PIN i_pos[3]
    DIRECTION INPUT ;
    USE SIGNAL ;
    PORT
      LAYER M4 ;
        RECT  328.236 184.656 328.32 184.68 ;
    END
  END i_pos[3]
  PIN i_pos[4]
    DIRECTION INPUT ;
    USE SIGNAL ;
    PORT
      LAYER M4 ;
        RECT  328.236 184.752 328.32 184.776 ;
    END
  END i_pos[4]
  PIN i_pos[5]
    DIRECTION INPUT ;
    USE SIGNAL ;
    PORT
      LAYER M4 ;
        RECT  328.236 184.848 328.32 184.872 ;
    END
  END i_pos[5]
  PIN i_pos[6]
    DIRECTION INPUT ;
    USE SIGNAL ;
    PORT
      LAYER M4 ;
        RECT  328.236 184.944 328.32 184.968 ;
    END
  END i_pos[6]
  PIN i_pos[7]
    DIRECTION INPUT ;
    USE SIGNAL ;
    PORT
      LAYER M4 ;
        RECT  328.236 185.04 328.32 185.064 ;
    END
  END i_pos[7]
  PIN i_pos[8]
    DIRECTION INPUT ;
    USE SIGNAL ;
    PORT
      LAYER M4 ;
        RECT  328.236 185.136 328.32 185.16 ;
    END
  END i_pos[8]
  PIN i_pos[9]
    DIRECTION INPUT ;
    USE SIGNAL ;
    PORT
      LAYER M4 ;
        RECT  328.236 185.232 328.32 185.256 ;
    END
  END i_pos[9]
  PIN i_row[0]
    DIRECTION INPUT ;
    USE SIGNAL ;
    PORT
      LAYER M4 ;
        RECT  328.236 185.616 328.32 185.64 ;
    END
  END i_row[0]
  PIN i_row[1]
    DIRECTION INPUT ;
    USE SIGNAL ;
    PORT
      LAYER M4 ;
        RECT  328.236 185.712 328.32 185.736 ;
    END
  END i_row[1]
  PIN i_row[2]
    DIRECTION INPUT ;
    USE SIGNAL ;
    PORT
      LAYER M4 ;
        RECT  328.236 185.808 328.32 185.832 ;
    END
  END i_row[2]
  PIN i_row[3]
    DIRECTION INPUT ;
    USE SIGNAL ;
    PORT
      LAYER M4 ;
        RECT  328.236 185.904 328.32 185.928 ;
    END
  END i_row[3]
  PIN i_row[4]
    DIRECTION INPUT ;
    USE SIGNAL ;
    PORT
      LAYER M4 ;
        RECT  328.236 186 328.32 186.024 ;
    END
  END i_row[4]
  PIN i_row[5]
    DIRECTION INPUT ;
    USE SIGNAL ;
    PORT
      LAYER M4 ;
        RECT  328.236 186.096 328.32 186.12 ;
    END
  END i_row[5]
  PIN i_row[6]
    DIRECTION INPUT ;
    USE SIGNAL ;
    PORT
      LAYER M4 ;
        RECT  328.236 186.192 328.32 186.216 ;
    END
  END i_row[6]
  PIN i_row[7]
    DIRECTION INPUT ;
    USE SIGNAL ;
    PORT
      LAYER M4 ;
        RECT  328.236 186.288 328.32 186.312 ;
    END
  END i_row[7]
  PIN i_sec[0]
    DIRECTION INPUT ;
    USE SIGNAL ;
    PORT
      LAYER M4 ;
        RECT  328.236 186.384 328.32 186.408 ;
    END
  END i_sec[0]
  PIN i_sec[10]
    DIRECTION INPUT ;
    USE SIGNAL ;
    PORT
      LAYER M4 ;
        RECT  328.236 187.344 328.32 187.368 ;
    END
  END i_sec[10]
  PIN i_sec[11]
    DIRECTION INPUT ;
    USE SIGNAL ;
    PORT
      LAYER M4 ;
        RECT  328.236 187.44 328.32 187.464 ;
    END
  END i_sec[11]
  PIN i_sec[12]
    DIRECTION INPUT ;
    USE SIGNAL ;
    PORT
      LAYER M4 ;
        RECT  328.236 187.536 328.32 187.56 ;
    END
  END i_sec[12]
  PIN i_sec[13]
    DIRECTION INPUT ;
    USE SIGNAL ;
    PORT
      LAYER M4 ;
        RECT  328.236 187.632 328.32 187.656 ;
    END
  END i_sec[13]
  PIN i_sec[14]
    DIRECTION INPUT ;
    USE SIGNAL ;
    PORT
      LAYER M4 ;
        RECT  328.236 187.728 328.32 187.752 ;
    END
  END i_sec[14]
  PIN i_sec[15]
    DIRECTION INPUT ;
    USE SIGNAL ;
    PORT
      LAYER M4 ;
        RECT  328.236 187.824 328.32 187.848 ;
    END
  END i_sec[15]
  PIN i_sec[16]
    DIRECTION INPUT ;
    USE SIGNAL ;
    PORT
      LAYER M4 ;
        RECT  328.236 187.92 328.32 187.944 ;
    END
  END i_sec[16]
  PIN i_sec[1]
    DIRECTION INPUT ;
    USE SIGNAL ;
    PORT
      LAYER M4 ;
        RECT  328.236 186.48 328.32 186.504 ;
    END
  END i_sec[1]
  PIN i_sec[2]
    DIRECTION INPUT ;
    USE SIGNAL ;
    PORT
      LAYER M4 ;
        RECT  328.236 186.576 328.32 186.6 ;
    END
  END i_sec[2]
  PIN i_sec[3]
    DIRECTION INPUT ;
    USE SIGNAL ;
    PORT
      LAYER M4 ;
        RECT  328.236 186.672 328.32 186.696 ;
    END
  END i_sec[3]
  PIN i_sec[4]
    DIRECTION INPUT ;
    USE SIGNAL ;
    PORT
      LAYER M4 ;
        RECT  328.236 186.768 328.32 186.792 ;
    END
  END i_sec[4]
  PIN i_sec[5]
    DIRECTION INPUT ;
    USE SIGNAL ;
    PORT
      LAYER M4 ;
        RECT  328.236 186.864 328.32 186.888 ;
    END
  END i_sec[5]
  PIN i_sec[6]
    DIRECTION INPUT ;
    USE SIGNAL ;
    PORT
      LAYER M4 ;
        RECT  328.236 186.96 328.32 186.984 ;
    END
  END i_sec[6]
  PIN i_sec[7]
    DIRECTION INPUT ;
    USE SIGNAL ;
    PORT
      LAYER M4 ;
        RECT  328.236 187.056 328.32 187.08 ;
    END
  END i_sec[7]
  PIN i_sec[8]
    DIRECTION INPUT ;
    USE SIGNAL ;
    PORT
      LAYER M4 ;
        RECT  328.236 187.152 328.32 187.176 ;
    END
  END i_sec[8]
  PIN i_sec[9]
    DIRECTION INPUT ;
    USE SIGNAL ;
    PORT
      LAYER M4 ;
        RECT  328.236 187.248 328.32 187.272 ;
    END
  END i_sec[9]
  PIN i_v
    DIRECTION INPUT ;
    USE SIGNAL ;
    PORT
      LAYER M4 ;
        RECT  328.236 188.016 328.32 188.04 ;
    END
  END i_v
  PIN o_bad
    DIRECTION OUTPUT ;
    USE SIGNAL ;
    PORT
      LAYER M4 ;
        RECT  0 163.44 0.084 163.464 ;
    END
  END o_bad
  PIN o_cr
    DIRECTION INPUT ;
    USE SIGNAL ;
    PORT
      LAYER M5 ;
        RECT  169.008 371.436 169.032 371.52 ;
    END
  END o_cr
  PIN o_data[0]
    DIRECTION OUTPUT ;
    USE SIGNAL ;
    PORT
      LAYER M4 ;
        RECT  0 163.536 0.084 163.56 ;
    END
  END o_data[0]
  PIN o_data[100]
    DIRECTION OUTPUT ;
    USE SIGNAL ;
    PORT
      LAYER M4 ;
        RECT  0 166.992 0.084 167.016 ;
    END
  END o_data[100]
  PIN o_data[101]
    DIRECTION OUTPUT ;
    USE SIGNAL ;
    PORT
      LAYER M4 ;
        RECT  0 167.088 0.084 167.112 ;
    END
  END o_data[101]
  PIN o_data[102]
    DIRECTION OUTPUT ;
    USE SIGNAL ;
    PORT
      LAYER M4 ;
        RECT  0 167.184 0.084 167.208 ;
    END
  END o_data[102]
  PIN o_data[103]
    DIRECTION OUTPUT ;
    USE SIGNAL ;
    PORT
      LAYER M4 ;
        RECT  0 167.28 0.084 167.304 ;
    END
  END o_data[103]
  PIN o_data[104]
    DIRECTION OUTPUT ;
    USE SIGNAL ;
    PORT
      LAYER M4 ;
        RECT  0 167.376 0.084 167.4 ;
    END
  END o_data[104]
  PIN o_data[105]
    DIRECTION OUTPUT ;
    USE SIGNAL ;
    PORT
      LAYER M4 ;
        RECT  0 167.472 0.084 167.496 ;
    END
  END o_data[105]
  PIN o_data[106]
    DIRECTION OUTPUT ;
    USE SIGNAL ;
    PORT
      LAYER M4 ;
        RECT  0 167.568 0.084 167.592 ;
    END
  END o_data[106]
  PIN o_data[107]
    DIRECTION OUTPUT ;
    USE SIGNAL ;
    PORT
      LAYER M4 ;
        RECT  0 167.664 0.084 167.688 ;
    END
  END o_data[107]
  PIN o_data[108]
    DIRECTION OUTPUT ;
    USE SIGNAL ;
    PORT
      LAYER M4 ;
        RECT  0 167.76 0.084 167.784 ;
    END
  END o_data[108]
  PIN o_data[109]
    DIRECTION OUTPUT ;
    USE SIGNAL ;
    PORT
      LAYER M4 ;
        RECT  0 167.856 0.084 167.88 ;
    END
  END o_data[109]
  PIN o_data[10]
    DIRECTION OUTPUT ;
    USE SIGNAL ;
    PORT
      LAYER M4 ;
        RECT  0 164.496 0.084 164.52 ;
    END
  END o_data[10]
  PIN o_data[110]
    DIRECTION OUTPUT ;
    USE SIGNAL ;
    PORT
      LAYER M4 ;
        RECT  0 167.952 0.084 167.976 ;
    END
  END o_data[110]
  PIN o_data[111]
    DIRECTION OUTPUT ;
    USE SIGNAL ;
    PORT
      LAYER M4 ;
        RECT  0 168.048 0.084 168.072 ;
    END
  END o_data[111]
  PIN o_data[112]
    DIRECTION OUTPUT ;
    USE SIGNAL ;
    PORT
      LAYER M4 ;
        RECT  0 168.144 0.084 168.168 ;
    END
  END o_data[112]
  PIN o_data[113]
    DIRECTION OUTPUT ;
    USE SIGNAL ;
    PORT
      LAYER M4 ;
        RECT  0 168.24 0.084 168.264 ;
    END
  END o_data[113]
  PIN o_data[114]
    DIRECTION OUTPUT ;
    USE SIGNAL ;
    PORT
      LAYER M4 ;
        RECT  0 168.336 0.084 168.36 ;
    END
  END o_data[114]
  PIN o_data[115]
    DIRECTION OUTPUT ;
    USE SIGNAL ;
    PORT
      LAYER M4 ;
        RECT  0 168.432 0.084 168.456 ;
    END
  END o_data[115]
  PIN o_data[116]
    DIRECTION OUTPUT ;
    USE SIGNAL ;
    PORT
      LAYER M4 ;
        RECT  0 168.528 0.084 168.552 ;
    END
  END o_data[116]
  PIN o_data[117]
    DIRECTION OUTPUT ;
    USE SIGNAL ;
    PORT
      LAYER M4 ;
        RECT  0 168.624 0.084 168.648 ;
    END
  END o_data[117]
  PIN o_data[118]
    DIRECTION OUTPUT ;
    USE SIGNAL ;
    PORT
      LAYER M4 ;
        RECT  0 168.72 0.084 168.744 ;
    END
  END o_data[118]
  PIN o_data[119]
    DIRECTION OUTPUT ;
    USE SIGNAL ;
    PORT
      LAYER M4 ;
        RECT  0 168.816 0.084 168.84 ;
    END
  END o_data[119]
  PIN o_data[11]
    DIRECTION OUTPUT ;
    USE SIGNAL ;
    PORT
      LAYER M4 ;
        RECT  0 164.592 0.084 164.616 ;
    END
  END o_data[11]
  PIN o_data[120]
    DIRECTION OUTPUT ;
    USE SIGNAL ;
    PORT
      LAYER M4 ;
        RECT  0 168.912 0.084 168.936 ;
    END
  END o_data[120]
  PIN o_data[121]
    DIRECTION OUTPUT ;
    USE SIGNAL ;
    PORT
      LAYER M4 ;
        RECT  0 169.008 0.084 169.032 ;
    END
  END o_data[121]
  PIN o_data[122]
    DIRECTION OUTPUT ;
    USE SIGNAL ;
    PORT
      LAYER M4 ;
        RECT  0 169.104 0.084 169.128 ;
    END
  END o_data[122]
  PIN o_data[123]
    DIRECTION OUTPUT ;
    USE SIGNAL ;
    PORT
      LAYER M4 ;
        RECT  0 169.2 0.084 169.224 ;
    END
  END o_data[123]
  PIN o_data[124]
    DIRECTION OUTPUT ;
    USE SIGNAL ;
    PORT
      LAYER M4 ;
        RECT  0 169.296 0.084 169.32 ;
    END
  END o_data[124]
  PIN o_data[125]
    DIRECTION OUTPUT ;
    USE SIGNAL ;
    PORT
      LAYER M4 ;
        RECT  0 169.392 0.084 169.416 ;
    END
  END o_data[125]
  PIN o_data[126]
    DIRECTION OUTPUT ;
    USE SIGNAL ;
    PORT
      LAYER M4 ;
        RECT  0 169.488 0.084 169.512 ;
    END
  END o_data[126]
  PIN o_data[127]
    DIRECTION OUTPUT ;
    USE SIGNAL ;
    PORT
      LAYER M4 ;
        RECT  0 204.912 0.084 204.936 ;
    END
  END o_data[127]
  PIN o_data[128]
    DIRECTION OUTPUT ;
    USE SIGNAL ;
    PORT
      LAYER M4 ;
        RECT  0 205.008 0.084 205.032 ;
    END
  END o_data[128]
  PIN o_data[129]
    DIRECTION OUTPUT ;
    USE SIGNAL ;
    PORT
      LAYER M4 ;
        RECT  0 205.104 0.084 205.128 ;
    END
  END o_data[129]
  PIN o_data[12]
    DIRECTION OUTPUT ;
    USE SIGNAL ;
    PORT
      LAYER M4 ;
        RECT  0 164.688 0.084 164.712 ;
    END
  END o_data[12]
  PIN o_data[130]
    DIRECTION OUTPUT ;
    USE SIGNAL ;
    PORT
      LAYER M4 ;
        RECT  0 205.2 0.084 205.224 ;
    END
  END o_data[130]
  PIN o_data[131]
    DIRECTION OUTPUT ;
    USE SIGNAL ;
    PORT
      LAYER M4 ;
        RECT  0 205.296 0.084 205.32 ;
    END
  END o_data[131]
  PIN o_data[132]
    DIRECTION OUTPUT ;
    USE SIGNAL ;
    PORT
      LAYER M4 ;
        RECT  0 205.392 0.084 205.416 ;
    END
  END o_data[132]
  PIN o_data[133]
    DIRECTION OUTPUT ;
    USE SIGNAL ;
    PORT
      LAYER M4 ;
        RECT  0 205.488 0.084 205.512 ;
    END
  END o_data[133]
  PIN o_data[134]
    DIRECTION OUTPUT ;
    USE SIGNAL ;
    PORT
      LAYER M4 ;
        RECT  0 205.584 0.084 205.608 ;
    END
  END o_data[134]
  PIN o_data[135]
    DIRECTION OUTPUT ;
    USE SIGNAL ;
    PORT
      LAYER M4 ;
        RECT  0 205.68 0.084 205.704 ;
    END
  END o_data[135]
  PIN o_data[136]
    DIRECTION OUTPUT ;
    USE SIGNAL ;
    PORT
      LAYER M4 ;
        RECT  0 205.776 0.084 205.8 ;
    END
  END o_data[136]
  PIN o_data[137]
    DIRECTION OUTPUT ;
    USE SIGNAL ;
    PORT
      LAYER M4 ;
        RECT  0 205.872 0.084 205.896 ;
    END
  END o_data[137]
  PIN o_data[138]
    DIRECTION OUTPUT ;
    USE SIGNAL ;
    PORT
      LAYER M4 ;
        RECT  0 205.968 0.084 205.992 ;
    END
  END o_data[138]
  PIN o_data[139]
    DIRECTION OUTPUT ;
    USE SIGNAL ;
    PORT
      LAYER M4 ;
        RECT  0 206.064 0.084 206.088 ;
    END
  END o_data[139]
  PIN o_data[13]
    DIRECTION OUTPUT ;
    USE SIGNAL ;
    PORT
      LAYER M4 ;
        RECT  0 164.784 0.084 164.808 ;
    END
  END o_data[13]
  PIN o_data[140]
    DIRECTION OUTPUT ;
    USE SIGNAL ;
    PORT
      LAYER M4 ;
        RECT  0 206.16 0.084 206.184 ;
    END
  END o_data[140]
  PIN o_data[141]
    DIRECTION OUTPUT ;
    USE SIGNAL ;
    PORT
      LAYER M4 ;
        RECT  0 206.256 0.084 206.28 ;
    END
  END o_data[141]
  PIN o_data[142]
    DIRECTION OUTPUT ;
    USE SIGNAL ;
    PORT
      LAYER M4 ;
        RECT  0 206.352 0.084 206.376 ;
    END
  END o_data[142]
  PIN o_data[143]
    DIRECTION OUTPUT ;
    USE SIGNAL ;
    PORT
      LAYER M4 ;
        RECT  0 206.448 0.084 206.472 ;
    END
  END o_data[143]
  PIN o_data[144]
    DIRECTION OUTPUT ;
    USE SIGNAL ;
    PORT
      LAYER M4 ;
        RECT  0 206.544 0.084 206.568 ;
    END
  END o_data[144]
  PIN o_data[145]
    DIRECTION OUTPUT ;
    USE SIGNAL ;
    PORT
      LAYER M4 ;
        RECT  0 206.64 0.084 206.664 ;
    END
  END o_data[145]
  PIN o_data[146]
    DIRECTION OUTPUT ;
    USE SIGNAL ;
    PORT
      LAYER M4 ;
        RECT  0 206.736 0.084 206.76 ;
    END
  END o_data[146]
  PIN o_data[147]
    DIRECTION OUTPUT ;
    USE SIGNAL ;
    PORT
      LAYER M4 ;
        RECT  0 206.832 0.084 206.856 ;
    END
  END o_data[147]
  PIN o_data[148]
    DIRECTION OUTPUT ;
    USE SIGNAL ;
    PORT
      LAYER M4 ;
        RECT  0 206.928 0.084 206.952 ;
    END
  END o_data[148]
  PIN o_data[149]
    DIRECTION OUTPUT ;
    USE SIGNAL ;
    PORT
      LAYER M4 ;
        RECT  0 207.024 0.084 207.048 ;
    END
  END o_data[149]
  PIN o_data[14]
    DIRECTION OUTPUT ;
    USE SIGNAL ;
    PORT
      LAYER M4 ;
        RECT  0 164.88 0.084 164.904 ;
    END
  END o_data[14]
  PIN o_data[150]
    DIRECTION OUTPUT ;
    USE SIGNAL ;
    PORT
      LAYER M4 ;
        RECT  0 207.12 0.084 207.144 ;
    END
  END o_data[150]
  PIN o_data[151]
    DIRECTION OUTPUT ;
    USE SIGNAL ;
    PORT
      LAYER M4 ;
        RECT  0 207.216 0.084 207.24 ;
    END
  END o_data[151]
  PIN o_data[152]
    DIRECTION OUTPUT ;
    USE SIGNAL ;
    PORT
      LAYER M4 ;
        RECT  0 207.312 0.084 207.336 ;
    END
  END o_data[152]
  PIN o_data[153]
    DIRECTION OUTPUT ;
    USE SIGNAL ;
    PORT
      LAYER M4 ;
        RECT  0 207.408 0.084 207.432 ;
    END
  END o_data[153]
  PIN o_data[154]
    DIRECTION OUTPUT ;
    USE SIGNAL ;
    PORT
      LAYER M4 ;
        RECT  0 207.504 0.084 207.528 ;
    END
  END o_data[154]
  PIN o_data[155]
    DIRECTION OUTPUT ;
    USE SIGNAL ;
    PORT
      LAYER M4 ;
        RECT  0 207.6 0.084 207.624 ;
    END
  END o_data[155]
  PIN o_data[156]
    DIRECTION OUTPUT ;
    USE SIGNAL ;
    PORT
      LAYER M4 ;
        RECT  0 207.696 0.084 207.72 ;
    END
  END o_data[156]
  PIN o_data[157]
    DIRECTION OUTPUT ;
    USE SIGNAL ;
    PORT
      LAYER M4 ;
        RECT  0 207.792 0.084 207.816 ;
    END
  END o_data[157]
  PIN o_data[158]
    DIRECTION OUTPUT ;
    USE SIGNAL ;
    PORT
      LAYER M4 ;
        RECT  0 207.888 0.084 207.912 ;
    END
  END o_data[158]
  PIN o_data[159]
    DIRECTION OUTPUT ;
    USE SIGNAL ;
    PORT
      LAYER M4 ;
        RECT  0 191.856 0.084 191.88 ;
    END
  END o_data[159]
  PIN o_data[15]
    DIRECTION OUTPUT ;
    USE SIGNAL ;
    PORT
      LAYER M4 ;
        RECT  0 164.976 0.084 165 ;
    END
  END o_data[15]
  PIN o_data[160]
    DIRECTION OUTPUT ;
    USE SIGNAL ;
    PORT
      LAYER M4 ;
        RECT  0 191.952 0.084 191.976 ;
    END
  END o_data[160]
  PIN o_data[161]
    DIRECTION OUTPUT ;
    USE SIGNAL ;
    PORT
      LAYER M4 ;
        RECT  0 192.048 0.084 192.072 ;
    END
  END o_data[161]
  PIN o_data[162]
    DIRECTION OUTPUT ;
    USE SIGNAL ;
    PORT
      LAYER M4 ;
        RECT  0 192.144 0.084 192.168 ;
    END
  END o_data[162]
  PIN o_data[163]
    DIRECTION OUTPUT ;
    USE SIGNAL ;
    PORT
      LAYER M4 ;
        RECT  0 192.24 0.084 192.264 ;
    END
  END o_data[163]
  PIN o_data[164]
    DIRECTION OUTPUT ;
    USE SIGNAL ;
    PORT
      LAYER M4 ;
        RECT  0 192.336 0.084 192.36 ;
    END
  END o_data[164]
  PIN o_data[165]
    DIRECTION OUTPUT ;
    USE SIGNAL ;
    PORT
      LAYER M4 ;
        RECT  0 192.432 0.084 192.456 ;
    END
  END o_data[165]
  PIN o_data[166]
    DIRECTION OUTPUT ;
    USE SIGNAL ;
    PORT
      LAYER M4 ;
        RECT  0 192.528 0.084 192.552 ;
    END
  END o_data[166]
  PIN o_data[167]
    DIRECTION OUTPUT ;
    USE SIGNAL ;
    PORT
      LAYER M4 ;
        RECT  0 192.624 0.084 192.648 ;
    END
  END o_data[167]
  PIN o_data[168]
    DIRECTION OUTPUT ;
    USE SIGNAL ;
    PORT
      LAYER M4 ;
        RECT  0 192.72 0.084 192.744 ;
    END
  END o_data[168]
  PIN o_data[169]
    DIRECTION OUTPUT ;
    USE SIGNAL ;
    PORT
      LAYER M4 ;
        RECT  0 192.816 0.084 192.84 ;
    END
  END o_data[169]
  PIN o_data[16]
    DIRECTION OUTPUT ;
    USE SIGNAL ;
    PORT
      LAYER M4 ;
        RECT  0 165.072 0.084 165.096 ;
    END
  END o_data[16]
  PIN o_data[170]
    DIRECTION OUTPUT ;
    USE SIGNAL ;
    PORT
      LAYER M4 ;
        RECT  0 192.912 0.084 192.936 ;
    END
  END o_data[170]
  PIN o_data[171]
    DIRECTION OUTPUT ;
    USE SIGNAL ;
    PORT
      LAYER M4 ;
        RECT  0 193.008 0.084 193.032 ;
    END
  END o_data[171]
  PIN o_data[172]
    DIRECTION OUTPUT ;
    USE SIGNAL ;
    PORT
      LAYER M4 ;
        RECT  0 193.104 0.084 193.128 ;
    END
  END o_data[172]
  PIN o_data[173]
    DIRECTION OUTPUT ;
    USE SIGNAL ;
    PORT
      LAYER M4 ;
        RECT  0 193.2 0.084 193.224 ;
    END
  END o_data[173]
  PIN o_data[174]
    DIRECTION OUTPUT ;
    USE SIGNAL ;
    PORT
      LAYER M4 ;
        RECT  0 193.296 0.084 193.32 ;
    END
  END o_data[174]
  PIN o_data[175]
    DIRECTION OUTPUT ;
    USE SIGNAL ;
    PORT
      LAYER M4 ;
        RECT  0 193.392 0.084 193.416 ;
    END
  END o_data[175]
  PIN o_data[176]
    DIRECTION OUTPUT ;
    USE SIGNAL ;
    PORT
      LAYER M4 ;
        RECT  0 193.488 0.084 193.512 ;
    END
  END o_data[176]
  PIN o_data[177]
    DIRECTION OUTPUT ;
    USE SIGNAL ;
    PORT
      LAYER M4 ;
        RECT  0 193.584 0.084 193.608 ;
    END
  END o_data[177]
  PIN o_data[178]
    DIRECTION OUTPUT ;
    USE SIGNAL ;
    PORT
      LAYER M4 ;
        RECT  0 193.68 0.084 193.704 ;
    END
  END o_data[178]
  PIN o_data[179]
    DIRECTION OUTPUT ;
    USE SIGNAL ;
    PORT
      LAYER M4 ;
        RECT  0 193.776 0.084 193.8 ;
    END
  END o_data[179]
  PIN o_data[17]
    DIRECTION OUTPUT ;
    USE SIGNAL ;
    PORT
      LAYER M4 ;
        RECT  0 165.168 0.084 165.192 ;
    END
  END o_data[17]
  PIN o_data[180]
    DIRECTION OUTPUT ;
    USE SIGNAL ;
    PORT
      LAYER M4 ;
        RECT  0 193.872 0.084 193.896 ;
    END
  END o_data[180]
  PIN o_data[181]
    DIRECTION OUTPUT ;
    USE SIGNAL ;
    PORT
      LAYER M4 ;
        RECT  0 193.968 0.084 193.992 ;
    END
  END o_data[181]
  PIN o_data[182]
    DIRECTION OUTPUT ;
    USE SIGNAL ;
    PORT
      LAYER M4 ;
        RECT  0 194.064 0.084 194.088 ;
    END
  END o_data[182]
  PIN o_data[183]
    DIRECTION OUTPUT ;
    USE SIGNAL ;
    PORT
      LAYER M4 ;
        RECT  0 194.16 0.084 194.184 ;
    END
  END o_data[183]
  PIN o_data[184]
    DIRECTION OUTPUT ;
    USE SIGNAL ;
    PORT
      LAYER M4 ;
        RECT  0 194.256 0.084 194.28 ;
    END
  END o_data[184]
  PIN o_data[185]
    DIRECTION OUTPUT ;
    USE SIGNAL ;
    PORT
      LAYER M4 ;
        RECT  0 194.352 0.084 194.376 ;
    END
  END o_data[185]
  PIN o_data[186]
    DIRECTION OUTPUT ;
    USE SIGNAL ;
    PORT
      LAYER M4 ;
        RECT  0 194.448 0.084 194.472 ;
    END
  END o_data[186]
  PIN o_data[187]
    DIRECTION OUTPUT ;
    USE SIGNAL ;
    PORT
      LAYER M4 ;
        RECT  0 194.544 0.084 194.568 ;
    END
  END o_data[187]
  PIN o_data[188]
    DIRECTION OUTPUT ;
    USE SIGNAL ;
    PORT
      LAYER M4 ;
        RECT  0 194.64 0.084 194.664 ;
    END
  END o_data[188]
  PIN o_data[189]
    DIRECTION OUTPUT ;
    USE SIGNAL ;
    PORT
      LAYER M4 ;
        RECT  0 194.736 0.084 194.76 ;
    END
  END o_data[189]
  PIN o_data[18]
    DIRECTION OUTPUT ;
    USE SIGNAL ;
    PORT
      LAYER M4 ;
        RECT  0 165.264 0.084 165.288 ;
    END
  END o_data[18]
  PIN o_data[190]
    DIRECTION OUTPUT ;
    USE SIGNAL ;
    PORT
      LAYER M4 ;
        RECT  0 194.832 0.084 194.856 ;
    END
  END o_data[190]
  PIN o_data[191]
    DIRECTION OUTPUT ;
    USE SIGNAL ;
    PORT
      LAYER M4 ;
        RECT  0 201.84 0.084 201.864 ;
    END
  END o_data[191]
  PIN o_data[192]
    DIRECTION OUTPUT ;
    USE SIGNAL ;
    PORT
      LAYER M4 ;
        RECT  0 201.936 0.084 201.96 ;
    END
  END o_data[192]
  PIN o_data[193]
    DIRECTION OUTPUT ;
    USE SIGNAL ;
    PORT
      LAYER M4 ;
        RECT  0 202.032 0.084 202.056 ;
    END
  END o_data[193]
  PIN o_data[194]
    DIRECTION OUTPUT ;
    USE SIGNAL ;
    PORT
      LAYER M4 ;
        RECT  0 202.128 0.084 202.152 ;
    END
  END o_data[194]
  PIN o_data[195]
    DIRECTION OUTPUT ;
    USE SIGNAL ;
    PORT
      LAYER M4 ;
        RECT  0 202.224 0.084 202.248 ;
    END
  END o_data[195]
  PIN o_data[196]
    DIRECTION OUTPUT ;
    USE SIGNAL ;
    PORT
      LAYER M4 ;
        RECT  0 202.32 0.084 202.344 ;
    END
  END o_data[196]
  PIN o_data[197]
    DIRECTION OUTPUT ;
    USE SIGNAL ;
    PORT
      LAYER M4 ;
        RECT  0 202.416 0.084 202.44 ;
    END
  END o_data[197]
  PIN o_data[198]
    DIRECTION OUTPUT ;
    USE SIGNAL ;
    PORT
      LAYER M4 ;
        RECT  0 202.512 0.084 202.536 ;
    END
  END o_data[198]
  PIN o_data[199]
    DIRECTION OUTPUT ;
    USE SIGNAL ;
    PORT
      LAYER M4 ;
        RECT  0 202.608 0.084 202.632 ;
    END
  END o_data[199]
  PIN o_data[19]
    DIRECTION OUTPUT ;
    USE SIGNAL ;
    PORT
      LAYER M4 ;
        RECT  0 165.36 0.084 165.384 ;
    END
  END o_data[19]
  PIN o_data[1]
    DIRECTION OUTPUT ;
    USE SIGNAL ;
    PORT
      LAYER M4 ;
        RECT  0 163.632 0.084 163.656 ;
    END
  END o_data[1]
  PIN o_data[200]
    DIRECTION OUTPUT ;
    USE SIGNAL ;
    PORT
      LAYER M4 ;
        RECT  0 202.704 0.084 202.728 ;
    END
  END o_data[200]
  PIN o_data[201]
    DIRECTION OUTPUT ;
    USE SIGNAL ;
    PORT
      LAYER M4 ;
        RECT  0 202.8 0.084 202.824 ;
    END
  END o_data[201]
  PIN o_data[202]
    DIRECTION OUTPUT ;
    USE SIGNAL ;
    PORT
      LAYER M4 ;
        RECT  0 202.896 0.084 202.92 ;
    END
  END o_data[202]
  PIN o_data[203]
    DIRECTION OUTPUT ;
    USE SIGNAL ;
    PORT
      LAYER M4 ;
        RECT  0 202.992 0.084 203.016 ;
    END
  END o_data[203]
  PIN o_data[204]
    DIRECTION OUTPUT ;
    USE SIGNAL ;
    PORT
      LAYER M4 ;
        RECT  0 203.088 0.084 203.112 ;
    END
  END o_data[204]
  PIN o_data[205]
    DIRECTION OUTPUT ;
    USE SIGNAL ;
    PORT
      LAYER M4 ;
        RECT  0 203.184 0.084 203.208 ;
    END
  END o_data[205]
  PIN o_data[206]
    DIRECTION OUTPUT ;
    USE SIGNAL ;
    PORT
      LAYER M4 ;
        RECT  0 203.28 0.084 203.304 ;
    END
  END o_data[206]
  PIN o_data[207]
    DIRECTION OUTPUT ;
    USE SIGNAL ;
    PORT
      LAYER M4 ;
        RECT  0 203.376 0.084 203.4 ;
    END
  END o_data[207]
  PIN o_data[208]
    DIRECTION OUTPUT ;
    USE SIGNAL ;
    PORT
      LAYER M4 ;
        RECT  0 203.472 0.084 203.496 ;
    END
  END o_data[208]
  PIN o_data[209]
    DIRECTION OUTPUT ;
    USE SIGNAL ;
    PORT
      LAYER M4 ;
        RECT  0 203.568 0.084 203.592 ;
    END
  END o_data[209]
  PIN o_data[20]
    DIRECTION OUTPUT ;
    USE SIGNAL ;
    PORT
      LAYER M4 ;
        RECT  0 165.456 0.084 165.48 ;
    END
  END o_data[20]
  PIN o_data[210]
    DIRECTION OUTPUT ;
    USE SIGNAL ;
    PORT
      LAYER M4 ;
        RECT  0 203.664 0.084 203.688 ;
    END
  END o_data[210]
  PIN o_data[211]
    DIRECTION OUTPUT ;
    USE SIGNAL ;
    PORT
      LAYER M4 ;
        RECT  0 203.76 0.084 203.784 ;
    END
  END o_data[211]
  PIN o_data[212]
    DIRECTION OUTPUT ;
    USE SIGNAL ;
    PORT
      LAYER M4 ;
        RECT  0 203.856 0.084 203.88 ;
    END
  END o_data[212]
  PIN o_data[213]
    DIRECTION OUTPUT ;
    USE SIGNAL ;
    PORT
      LAYER M4 ;
        RECT  0 203.952 0.084 203.976 ;
    END
  END o_data[213]
  PIN o_data[214]
    DIRECTION OUTPUT ;
    USE SIGNAL ;
    PORT
      LAYER M4 ;
        RECT  0 204.048 0.084 204.072 ;
    END
  END o_data[214]
  PIN o_data[215]
    DIRECTION OUTPUT ;
    USE SIGNAL ;
    PORT
      LAYER M4 ;
        RECT  0 204.144 0.084 204.168 ;
    END
  END o_data[215]
  PIN o_data[216]
    DIRECTION OUTPUT ;
    USE SIGNAL ;
    PORT
      LAYER M4 ;
        RECT  0 204.24 0.084 204.264 ;
    END
  END o_data[216]
  PIN o_data[217]
    DIRECTION OUTPUT ;
    USE SIGNAL ;
    PORT
      LAYER M4 ;
        RECT  0 204.336 0.084 204.36 ;
    END
  END o_data[217]
  PIN o_data[218]
    DIRECTION OUTPUT ;
    USE SIGNAL ;
    PORT
      LAYER M4 ;
        RECT  0 204.432 0.084 204.456 ;
    END
  END o_data[218]
  PIN o_data[219]
    DIRECTION OUTPUT ;
    USE SIGNAL ;
    PORT
      LAYER M4 ;
        RECT  0 204.528 0.084 204.552 ;
    END
  END o_data[219]
  PIN o_data[21]
    DIRECTION OUTPUT ;
    USE SIGNAL ;
    PORT
      LAYER M4 ;
        RECT  0 165.552 0.084 165.576 ;
    END
  END o_data[21]
  PIN o_data[220]
    DIRECTION OUTPUT ;
    USE SIGNAL ;
    PORT
      LAYER M4 ;
        RECT  0 204.624 0.084 204.648 ;
    END
  END o_data[220]
  PIN o_data[221]
    DIRECTION OUTPUT ;
    USE SIGNAL ;
    PORT
      LAYER M4 ;
        RECT  0 204.72 0.084 204.744 ;
    END
  END o_data[221]
  PIN o_data[222]
    DIRECTION OUTPUT ;
    USE SIGNAL ;
    PORT
      LAYER M4 ;
        RECT  0 204.816 0.084 204.84 ;
    END
  END o_data[222]
  PIN o_data[223]
    DIRECTION OUTPUT ;
    USE SIGNAL ;
    PORT
      LAYER M4 ;
        RECT  0 172.656 0.084 172.68 ;
    END
  END o_data[223]
  PIN o_data[224]
    DIRECTION OUTPUT ;
    USE SIGNAL ;
    PORT
      LAYER M4 ;
        RECT  0 172.752 0.084 172.776 ;
    END
  END o_data[224]
  PIN o_data[225]
    DIRECTION OUTPUT ;
    USE SIGNAL ;
    PORT
      LAYER M4 ;
        RECT  0 172.848 0.084 172.872 ;
    END
  END o_data[225]
  PIN o_data[226]
    DIRECTION OUTPUT ;
    USE SIGNAL ;
    PORT
      LAYER M4 ;
        RECT  0 172.944 0.084 172.968 ;
    END
  END o_data[226]
  PIN o_data[227]
    DIRECTION OUTPUT ;
    USE SIGNAL ;
    PORT
      LAYER M4 ;
        RECT  0 173.04 0.084 173.064 ;
    END
  END o_data[227]
  PIN o_data[228]
    DIRECTION OUTPUT ;
    USE SIGNAL ;
    PORT
      LAYER M4 ;
        RECT  0 173.136 0.084 173.16 ;
    END
  END o_data[228]
  PIN o_data[229]
    DIRECTION OUTPUT ;
    USE SIGNAL ;
    PORT
      LAYER M4 ;
        RECT  0 173.232 0.084 173.256 ;
    END
  END o_data[229]
  PIN o_data[22]
    DIRECTION OUTPUT ;
    USE SIGNAL ;
    PORT
      LAYER M4 ;
        RECT  0 165.648 0.084 165.672 ;
    END
  END o_data[22]
  PIN o_data[230]
    DIRECTION OUTPUT ;
    USE SIGNAL ;
    PORT
      LAYER M4 ;
        RECT  0 173.328 0.084 173.352 ;
    END
  END o_data[230]
  PIN o_data[231]
    DIRECTION OUTPUT ;
    USE SIGNAL ;
    PORT
      LAYER M4 ;
        RECT  0 173.424 0.084 173.448 ;
    END
  END o_data[231]
  PIN o_data[232]
    DIRECTION OUTPUT ;
    USE SIGNAL ;
    PORT
      LAYER M4 ;
        RECT  0 173.52 0.084 173.544 ;
    END
  END o_data[232]
  PIN o_data[233]
    DIRECTION OUTPUT ;
    USE SIGNAL ;
    PORT
      LAYER M4 ;
        RECT  0 173.616 0.084 173.64 ;
    END
  END o_data[233]
  PIN o_data[234]
    DIRECTION OUTPUT ;
    USE SIGNAL ;
    PORT
      LAYER M4 ;
        RECT  0 173.712 0.084 173.736 ;
    END
  END o_data[234]
  PIN o_data[235]
    DIRECTION OUTPUT ;
    USE SIGNAL ;
    PORT
      LAYER M4 ;
        RECT  0 173.808 0.084 173.832 ;
    END
  END o_data[235]
  PIN o_data[236]
    DIRECTION OUTPUT ;
    USE SIGNAL ;
    PORT
      LAYER M4 ;
        RECT  0 173.904 0.084 173.928 ;
    END
  END o_data[236]
  PIN o_data[237]
    DIRECTION OUTPUT ;
    USE SIGNAL ;
    PORT
      LAYER M4 ;
        RECT  0 174 0.084 174.024 ;
    END
  END o_data[237]
  PIN o_data[238]
    DIRECTION OUTPUT ;
    USE SIGNAL ;
    PORT
      LAYER M4 ;
        RECT  0 174.096 0.084 174.12 ;
    END
  END o_data[238]
  PIN o_data[239]
    DIRECTION OUTPUT ;
    USE SIGNAL ;
    PORT
      LAYER M4 ;
        RECT  0 174.192 0.084 174.216 ;
    END
  END o_data[239]
  PIN o_data[23]
    DIRECTION OUTPUT ;
    USE SIGNAL ;
    PORT
      LAYER M4 ;
        RECT  0 165.744 0.084 165.768 ;
    END
  END o_data[23]
  PIN o_data[240]
    DIRECTION OUTPUT ;
    USE SIGNAL ;
    PORT
      LAYER M4 ;
        RECT  0 174.288 0.084 174.312 ;
    END
  END o_data[240]
  PIN o_data[241]
    DIRECTION OUTPUT ;
    USE SIGNAL ;
    PORT
      LAYER M4 ;
        RECT  0 174.384 0.084 174.408 ;
    END
  END o_data[241]
  PIN o_data[242]
    DIRECTION OUTPUT ;
    USE SIGNAL ;
    PORT
      LAYER M4 ;
        RECT  0 174.48 0.084 174.504 ;
    END
  END o_data[242]
  PIN o_data[243]
    DIRECTION OUTPUT ;
    USE SIGNAL ;
    PORT
      LAYER M4 ;
        RECT  0 174.576 0.084 174.6 ;
    END
  END o_data[243]
  PIN o_data[244]
    DIRECTION OUTPUT ;
    USE SIGNAL ;
    PORT
      LAYER M4 ;
        RECT  0 174.672 0.084 174.696 ;
    END
  END o_data[244]
  PIN o_data[245]
    DIRECTION OUTPUT ;
    USE SIGNAL ;
    PORT
      LAYER M4 ;
        RECT  0 174.768 0.084 174.792 ;
    END
  END o_data[245]
  PIN o_data[246]
    DIRECTION OUTPUT ;
    USE SIGNAL ;
    PORT
      LAYER M4 ;
        RECT  0 174.864 0.084 174.888 ;
    END
  END o_data[246]
  PIN o_data[247]
    DIRECTION OUTPUT ;
    USE SIGNAL ;
    PORT
      LAYER M4 ;
        RECT  0 174.96 0.084 174.984 ;
    END
  END o_data[247]
  PIN o_data[248]
    DIRECTION OUTPUT ;
    USE SIGNAL ;
    PORT
      LAYER M4 ;
        RECT  0 175.056 0.084 175.08 ;
    END
  END o_data[248]
  PIN o_data[249]
    DIRECTION OUTPUT ;
    USE SIGNAL ;
    PORT
      LAYER M4 ;
        RECT  0 175.152 0.084 175.176 ;
    END
  END o_data[249]
  PIN o_data[24]
    DIRECTION OUTPUT ;
    USE SIGNAL ;
    PORT
      LAYER M4 ;
        RECT  0 165.84 0.084 165.864 ;
    END
  END o_data[24]
  PIN o_data[250]
    DIRECTION OUTPUT ;
    USE SIGNAL ;
    PORT
      LAYER M4 ;
        RECT  0 175.248 0.084 175.272 ;
    END
  END o_data[250]
  PIN o_data[251]
    DIRECTION OUTPUT ;
    USE SIGNAL ;
    PORT
      LAYER M4 ;
        RECT  0 175.344 0.084 175.368 ;
    END
  END o_data[251]
  PIN o_data[252]
    DIRECTION OUTPUT ;
    USE SIGNAL ;
    PORT
      LAYER M4 ;
        RECT  0 175.44 0.084 175.464 ;
    END
  END o_data[252]
  PIN o_data[253]
    DIRECTION OUTPUT ;
    USE SIGNAL ;
    PORT
      LAYER M4 ;
        RECT  0 175.536 0.084 175.56 ;
    END
  END o_data[253]
  PIN o_data[254]
    DIRECTION OUTPUT ;
    USE SIGNAL ;
    PORT
      LAYER M4 ;
        RECT  0 175.632 0.084 175.656 ;
    END
  END o_data[254]
  PIN o_data[255]
    DIRECTION OUTPUT ;
    USE SIGNAL ;
    PORT
      LAYER M4 ;
        RECT  0 182.64 0.084 182.664 ;
    END
  END o_data[255]
  PIN o_data[25]
    DIRECTION OUTPUT ;
    USE SIGNAL ;
    PORT
      LAYER M4 ;
        RECT  0 165.936 0.084 165.96 ;
    END
  END o_data[25]
  PIN o_data[26]
    DIRECTION OUTPUT ;
    USE SIGNAL ;
    PORT
      LAYER M4 ;
        RECT  0 166.032 0.084 166.056 ;
    END
  END o_data[26]
  PIN o_data[27]
    DIRECTION OUTPUT ;
    USE SIGNAL ;
    PORT
      LAYER M4 ;
        RECT  0 166.128 0.084 166.152 ;
    END
  END o_data[27]
  PIN o_data[28]
    DIRECTION OUTPUT ;
    USE SIGNAL ;
    PORT
      LAYER M4 ;
        RECT  0 166.224 0.084 166.248 ;
    END
  END o_data[28]
  PIN o_data[29]
    DIRECTION OUTPUT ;
    USE SIGNAL ;
    PORT
      LAYER M4 ;
        RECT  0 166.32 0.084 166.344 ;
    END
  END o_data[29]
  PIN o_data[2]
    DIRECTION OUTPUT ;
    USE SIGNAL ;
    PORT
      LAYER M4 ;
        RECT  0 163.728 0.084 163.752 ;
    END
  END o_data[2]
  PIN o_data[30]
    DIRECTION OUTPUT ;
    USE SIGNAL ;
    PORT
      LAYER M4 ;
        RECT  0 166.416 0.084 166.44 ;
    END
  END o_data[30]
  PIN o_data[31]
    DIRECTION OUTPUT ;
    USE SIGNAL ;
    PORT
      LAYER M4 ;
        RECT  0 169.584 0.084 169.608 ;
    END
  END o_data[31]
  PIN o_data[32]
    DIRECTION OUTPUT ;
    USE SIGNAL ;
    PORT
      LAYER M4 ;
        RECT  0 169.68 0.084 169.704 ;
    END
  END o_data[32]
  PIN o_data[33]
    DIRECTION OUTPUT ;
    USE SIGNAL ;
    PORT
      LAYER M4 ;
        RECT  0 169.776 0.084 169.8 ;
    END
  END o_data[33]
  PIN o_data[34]
    DIRECTION OUTPUT ;
    USE SIGNAL ;
    PORT
      LAYER M4 ;
        RECT  0 169.872 0.084 169.896 ;
    END
  END o_data[34]
  PIN o_data[35]
    DIRECTION OUTPUT ;
    USE SIGNAL ;
    PORT
      LAYER M4 ;
        RECT  0 169.968 0.084 169.992 ;
    END
  END o_data[35]
  PIN o_data[36]
    DIRECTION OUTPUT ;
    USE SIGNAL ;
    PORT
      LAYER M4 ;
        RECT  0 170.064 0.084 170.088 ;
    END
  END o_data[36]
  PIN o_data[37]
    DIRECTION OUTPUT ;
    USE SIGNAL ;
    PORT
      LAYER M4 ;
        RECT  0 170.16 0.084 170.184 ;
    END
  END o_data[37]
  PIN o_data[38]
    DIRECTION OUTPUT ;
    USE SIGNAL ;
    PORT
      LAYER M4 ;
        RECT  0 170.256 0.084 170.28 ;
    END
  END o_data[38]
  PIN o_data[39]
    DIRECTION OUTPUT ;
    USE SIGNAL ;
    PORT
      LAYER M4 ;
        RECT  0 170.352 0.084 170.376 ;
    END
  END o_data[39]
  PIN o_data[3]
    DIRECTION OUTPUT ;
    USE SIGNAL ;
    PORT
      LAYER M4 ;
        RECT  0 163.824 0.084 163.848 ;
    END
  END o_data[3]
  PIN o_data[40]
    DIRECTION OUTPUT ;
    USE SIGNAL ;
    PORT
      LAYER M4 ;
        RECT  0 170.448 0.084 170.472 ;
    END
  END o_data[40]
  PIN o_data[41]
    DIRECTION OUTPUT ;
    USE SIGNAL ;
    PORT
      LAYER M4 ;
        RECT  0 170.544 0.084 170.568 ;
    END
  END o_data[41]
  PIN o_data[42]
    DIRECTION OUTPUT ;
    USE SIGNAL ;
    PORT
      LAYER M4 ;
        RECT  0 170.64 0.084 170.664 ;
    END
  END o_data[42]
  PIN o_data[43]
    DIRECTION OUTPUT ;
    USE SIGNAL ;
    PORT
      LAYER M4 ;
        RECT  0 170.736 0.084 170.76 ;
    END
  END o_data[43]
  PIN o_data[44]
    DIRECTION OUTPUT ;
    USE SIGNAL ;
    PORT
      LAYER M4 ;
        RECT  0 170.832 0.084 170.856 ;
    END
  END o_data[44]
  PIN o_data[45]
    DIRECTION OUTPUT ;
    USE SIGNAL ;
    PORT
      LAYER M4 ;
        RECT  0 170.928 0.084 170.952 ;
    END
  END o_data[45]
  PIN o_data[46]
    DIRECTION OUTPUT ;
    USE SIGNAL ;
    PORT
      LAYER M4 ;
        RECT  0 171.024 0.084 171.048 ;
    END
  END o_data[46]
  PIN o_data[47]
    DIRECTION OUTPUT ;
    USE SIGNAL ;
    PORT
      LAYER M4 ;
        RECT  0 171.12 0.084 171.144 ;
    END
  END o_data[47]
  PIN o_data[48]
    DIRECTION OUTPUT ;
    USE SIGNAL ;
    PORT
      LAYER M4 ;
        RECT  0 171.216 0.084 171.24 ;
    END
  END o_data[48]
  PIN o_data[49]
    DIRECTION OUTPUT ;
    USE SIGNAL ;
    PORT
      LAYER M4 ;
        RECT  0 171.312 0.084 171.336 ;
    END
  END o_data[49]
  PIN o_data[4]
    DIRECTION OUTPUT ;
    USE SIGNAL ;
    PORT
      LAYER M4 ;
        RECT  0 163.92 0.084 163.944 ;
    END
  END o_data[4]
  PIN o_data[50]
    DIRECTION OUTPUT ;
    USE SIGNAL ;
    PORT
      LAYER M4 ;
        RECT  0 171.408 0.084 171.432 ;
    END
  END o_data[50]
  PIN o_data[51]
    DIRECTION OUTPUT ;
    USE SIGNAL ;
    PORT
      LAYER M4 ;
        RECT  0 171.504 0.084 171.528 ;
    END
  END o_data[51]
  PIN o_data[52]
    DIRECTION OUTPUT ;
    USE SIGNAL ;
    PORT
      LAYER M4 ;
        RECT  0 171.6 0.084 171.624 ;
    END
  END o_data[52]
  PIN o_data[53]
    DIRECTION OUTPUT ;
    USE SIGNAL ;
    PORT
      LAYER M4 ;
        RECT  0 171.696 0.084 171.72 ;
    END
  END o_data[53]
  PIN o_data[54]
    DIRECTION OUTPUT ;
    USE SIGNAL ;
    PORT
      LAYER M4 ;
        RECT  0 171.792 0.084 171.816 ;
    END
  END o_data[54]
  PIN o_data[55]
    DIRECTION OUTPUT ;
    USE SIGNAL ;
    PORT
      LAYER M4 ;
        RECT  0 171.888 0.084 171.912 ;
    END
  END o_data[55]
  PIN o_data[56]
    DIRECTION OUTPUT ;
    USE SIGNAL ;
    PORT
      LAYER M4 ;
        RECT  0 171.984 0.084 172.008 ;
    END
  END o_data[56]
  PIN o_data[57]
    DIRECTION OUTPUT ;
    USE SIGNAL ;
    PORT
      LAYER M4 ;
        RECT  0 172.08 0.084 172.104 ;
    END
  END o_data[57]
  PIN o_data[58]
    DIRECTION OUTPUT ;
    USE SIGNAL ;
    PORT
      LAYER M4 ;
        RECT  0 172.176 0.084 172.2 ;
    END
  END o_data[58]
  PIN o_data[59]
    DIRECTION OUTPUT ;
    USE SIGNAL ;
    PORT
      LAYER M4 ;
        RECT  0 172.272 0.084 172.296 ;
    END
  END o_data[59]
  PIN o_data[5]
    DIRECTION OUTPUT ;
    USE SIGNAL ;
    PORT
      LAYER M4 ;
        RECT  0 164.016 0.084 164.04 ;
    END
  END o_data[5]
  PIN o_data[60]
    DIRECTION OUTPUT ;
    USE SIGNAL ;
    PORT
      LAYER M4 ;
        RECT  0 172.368 0.084 172.392 ;
    END
  END o_data[60]
  PIN o_data[61]
    DIRECTION OUTPUT ;
    USE SIGNAL ;
    PORT
      LAYER M4 ;
        RECT  0 172.464 0.084 172.488 ;
    END
  END o_data[61]
  PIN o_data[62]
    DIRECTION OUTPUT ;
    USE SIGNAL ;
    PORT
      LAYER M4 ;
        RECT  0 172.56 0.084 172.584 ;
    END
  END o_data[62]
  PIN o_data[63]
    DIRECTION OUTPUT ;
    USE SIGNAL ;
    PORT
      LAYER M4 ;
        RECT  0 160.368 0.084 160.392 ;
    END
  END o_data[63]
  PIN o_data[64]
    DIRECTION OUTPUT ;
    USE SIGNAL ;
    PORT
      LAYER M4 ;
        RECT  0 160.464 0.084 160.488 ;
    END
  END o_data[64]
  PIN o_data[65]
    DIRECTION OUTPUT ;
    USE SIGNAL ;
    PORT
      LAYER M4 ;
        RECT  0 160.56 0.084 160.584 ;
    END
  END o_data[65]
  PIN o_data[66]
    DIRECTION OUTPUT ;
    USE SIGNAL ;
    PORT
      LAYER M4 ;
        RECT  0 160.656 0.084 160.68 ;
    END
  END o_data[66]
  PIN o_data[67]
    DIRECTION OUTPUT ;
    USE SIGNAL ;
    PORT
      LAYER M4 ;
        RECT  0 160.752 0.084 160.776 ;
    END
  END o_data[67]
  PIN o_data[68]
    DIRECTION OUTPUT ;
    USE SIGNAL ;
    PORT
      LAYER M4 ;
        RECT  0 160.848 0.084 160.872 ;
    END
  END o_data[68]
  PIN o_data[69]
    DIRECTION OUTPUT ;
    USE SIGNAL ;
    PORT
      LAYER M4 ;
        RECT  0 160.944 0.084 160.968 ;
    END
  END o_data[69]
  PIN o_data[6]
    DIRECTION OUTPUT ;
    USE SIGNAL ;
    PORT
      LAYER M4 ;
        RECT  0 164.112 0.084 164.136 ;
    END
  END o_data[6]
  PIN o_data[70]
    DIRECTION OUTPUT ;
    USE SIGNAL ;
    PORT
      LAYER M4 ;
        RECT  0 161.04 0.084 161.064 ;
    END
  END o_data[70]
  PIN o_data[71]
    DIRECTION OUTPUT ;
    USE SIGNAL ;
    PORT
      LAYER M4 ;
        RECT  0 161.136 0.084 161.16 ;
    END
  END o_data[71]
  PIN o_data[72]
    DIRECTION OUTPUT ;
    USE SIGNAL ;
    PORT
      LAYER M4 ;
        RECT  0 161.232 0.084 161.256 ;
    END
  END o_data[72]
  PIN o_data[73]
    DIRECTION OUTPUT ;
    USE SIGNAL ;
    PORT
      LAYER M4 ;
        RECT  0 161.328 0.084 161.352 ;
    END
  END o_data[73]
  PIN o_data[74]
    DIRECTION OUTPUT ;
    USE SIGNAL ;
    PORT
      LAYER M4 ;
        RECT  0 161.424 0.084 161.448 ;
    END
  END o_data[74]
  PIN o_data[75]
    DIRECTION OUTPUT ;
    USE SIGNAL ;
    PORT
      LAYER M4 ;
        RECT  0 161.52 0.084 161.544 ;
    END
  END o_data[75]
  PIN o_data[76]
    DIRECTION OUTPUT ;
    USE SIGNAL ;
    PORT
      LAYER M4 ;
        RECT  0 161.616 0.084 161.64 ;
    END
  END o_data[76]
  PIN o_data[77]
    DIRECTION OUTPUT ;
    USE SIGNAL ;
    PORT
      LAYER M4 ;
        RECT  0 161.712 0.084 161.736 ;
    END
  END o_data[77]
  PIN o_data[78]
    DIRECTION OUTPUT ;
    USE SIGNAL ;
    PORT
      LAYER M4 ;
        RECT  0 161.808 0.084 161.832 ;
    END
  END o_data[78]
  PIN o_data[79]
    DIRECTION OUTPUT ;
    USE SIGNAL ;
    PORT
      LAYER M4 ;
        RECT  0 161.904 0.084 161.928 ;
    END
  END o_data[79]
  PIN o_data[7]
    DIRECTION OUTPUT ;
    USE SIGNAL ;
    PORT
      LAYER M4 ;
        RECT  0 164.208 0.084 164.232 ;
    END
  END o_data[7]
  PIN o_data[80]
    DIRECTION OUTPUT ;
    USE SIGNAL ;
    PORT
      LAYER M4 ;
        RECT  0 162 0.084 162.024 ;
    END
  END o_data[80]
  PIN o_data[81]
    DIRECTION OUTPUT ;
    USE SIGNAL ;
    PORT
      LAYER M4 ;
        RECT  0 162.096 0.084 162.12 ;
    END
  END o_data[81]
  PIN o_data[82]
    DIRECTION OUTPUT ;
    USE SIGNAL ;
    PORT
      LAYER M4 ;
        RECT  0 162.192 0.084 162.216 ;
    END
  END o_data[82]
  PIN o_data[83]
    DIRECTION OUTPUT ;
    USE SIGNAL ;
    PORT
      LAYER M4 ;
        RECT  0 162.288 0.084 162.312 ;
    END
  END o_data[83]
  PIN o_data[84]
    DIRECTION OUTPUT ;
    USE SIGNAL ;
    PORT
      LAYER M4 ;
        RECT  0 162.384 0.084 162.408 ;
    END
  END o_data[84]
  PIN o_data[85]
    DIRECTION OUTPUT ;
    USE SIGNAL ;
    PORT
      LAYER M4 ;
        RECT  0 162.48 0.084 162.504 ;
    END
  END o_data[85]
  PIN o_data[86]
    DIRECTION OUTPUT ;
    USE SIGNAL ;
    PORT
      LAYER M4 ;
        RECT  0 162.576 0.084 162.6 ;
    END
  END o_data[86]
  PIN o_data[87]
    DIRECTION OUTPUT ;
    USE SIGNAL ;
    PORT
      LAYER M4 ;
        RECT  0 162.672 0.084 162.696 ;
    END
  END o_data[87]
  PIN o_data[88]
    DIRECTION OUTPUT ;
    USE SIGNAL ;
    PORT
      LAYER M4 ;
        RECT  0 162.768 0.084 162.792 ;
    END
  END o_data[88]
  PIN o_data[89]
    DIRECTION OUTPUT ;
    USE SIGNAL ;
    PORT
      LAYER M4 ;
        RECT  0 162.864 0.084 162.888 ;
    END
  END o_data[89]
  PIN o_data[8]
    DIRECTION OUTPUT ;
    USE SIGNAL ;
    PORT
      LAYER M4 ;
        RECT  0 164.304 0.084 164.328 ;
    END
  END o_data[8]
  PIN o_data[90]
    DIRECTION OUTPUT ;
    USE SIGNAL ;
    PORT
      LAYER M4 ;
        RECT  0 162.96 0.084 162.984 ;
    END
  END o_data[90]
  PIN o_data[91]
    DIRECTION OUTPUT ;
    USE SIGNAL ;
    PORT
      LAYER M4 ;
        RECT  0 163.056 0.084 163.08 ;
    END
  END o_data[91]
  PIN o_data[92]
    DIRECTION OUTPUT ;
    USE SIGNAL ;
    PORT
      LAYER M4 ;
        RECT  0 163.152 0.084 163.176 ;
    END
  END o_data[92]
  PIN o_data[93]
    DIRECTION OUTPUT ;
    USE SIGNAL ;
    PORT
      LAYER M4 ;
        RECT  0 163.248 0.084 163.272 ;
    END
  END o_data[93]
  PIN o_data[94]
    DIRECTION OUTPUT ;
    USE SIGNAL ;
    PORT
      LAYER M4 ;
        RECT  0 163.344 0.084 163.368 ;
    END
  END o_data[94]
  PIN o_data[95]
    DIRECTION OUTPUT ;
    USE SIGNAL ;
    PORT
      LAYER M4 ;
        RECT  0 166.512 0.084 166.536 ;
    END
  END o_data[95]
  PIN o_data[96]
    DIRECTION OUTPUT ;
    USE SIGNAL ;
    PORT
      LAYER M4 ;
        RECT  0 166.608 0.084 166.632 ;
    END
  END o_data[96]
  PIN o_data[97]
    DIRECTION OUTPUT ;
    USE SIGNAL ;
    PORT
      LAYER M4 ;
        RECT  0 166.704 0.084 166.728 ;
    END
  END o_data[97]
  PIN o_data[98]
    DIRECTION OUTPUT ;
    USE SIGNAL ;
    PORT
      LAYER M4 ;
        RECT  0 166.8 0.084 166.824 ;
    END
  END o_data[98]
  PIN o_data[99]
    DIRECTION OUTPUT ;
    USE SIGNAL ;
    PORT
      LAYER M4 ;
        RECT  0 166.896 0.084 166.92 ;
    END
  END o_data[99]
  PIN o_data[9]
    DIRECTION OUTPUT ;
    USE SIGNAL ;
    PORT
      LAYER M4 ;
        RECT  0 164.4 0.084 164.424 ;
    END
  END o_data[9]
  PIN o_drop
    DIRECTION OUTPUT ;
    USE SIGNAL ;
    PORT
      LAYER M4 ;
        RECT  0 182.736 0.084 182.76 ;
    END
  END o_drop
  PIN o_isk
    DIRECTION OUTPUT ;
    USE SIGNAL ;
    PORT
      LAYER M4 ;
        RECT  0 182.832 0.084 182.856 ;
    END
  END o_isk
  PIN o_loc0[0]
    DIRECTION OUTPUT ;
    USE SIGNAL ;
    PORT
      LAYER M4 ;
        RECT  0 182.928 0.084 182.952 ;
    END
  END o_loc0[0]
  PIN o_loc0[1]
    DIRECTION OUTPUT ;
    USE SIGNAL ;
    PORT
      LAYER M4 ;
        RECT  0 183.024 0.084 183.048 ;
    END
  END o_loc0[1]
  PIN o_loc0[2]
    DIRECTION OUTPUT ;
    USE SIGNAL ;
    PORT
      LAYER M4 ;
        RECT  0 183.12 0.084 183.144 ;
    END
  END o_loc0[2]
  PIN o_loc0[3]
    DIRECTION OUTPUT ;
    USE SIGNAL ;
    PORT
      LAYER M4 ;
        RECT  0 183.216 0.084 183.24 ;
    END
  END o_loc0[3]
  PIN o_loc0[4]
    DIRECTION OUTPUT ;
    USE SIGNAL ;
    PORT
      LAYER M4 ;
        RECT  0 183.312 0.084 183.336 ;
    END
  END o_loc0[4]
  PIN o_loc0[5]
    DIRECTION OUTPUT ;
    USE SIGNAL ;
    PORT
      LAYER M4 ;
        RECT  0 183.408 0.084 183.432 ;
    END
  END o_loc0[5]
  PIN o_loc0[6]
    DIRECTION OUTPUT ;
    USE SIGNAL ;
    PORT
      LAYER M4 ;
        RECT  0 183.504 0.084 183.528 ;
    END
  END o_loc0[6]
  PIN o_loc1[0]
    DIRECTION OUTPUT ;
    USE SIGNAL ;
    PORT
      LAYER M4 ;
        RECT  0 183.6 0.084 183.624 ;
    END
  END o_loc1[0]
  PIN o_loc1[1]
    DIRECTION OUTPUT ;
    USE SIGNAL ;
    PORT
      LAYER M4 ;
        RECT  0 183.696 0.084 183.72 ;
    END
  END o_loc1[1]
  PIN o_loc1[2]
    DIRECTION OUTPUT ;
    USE SIGNAL ;
    PORT
      LAYER M4 ;
        RECT  0 183.792 0.084 183.816 ;
    END
  END o_loc1[2]
  PIN o_loc1[3]
    DIRECTION OUTPUT ;
    USE SIGNAL ;
    PORT
      LAYER M4 ;
        RECT  0 183.888 0.084 183.912 ;
    END
  END o_loc1[3]
  PIN o_loc1[4]
    DIRECTION OUTPUT ;
    USE SIGNAL ;
    PORT
      LAYER M4 ;
        RECT  0 183.984 0.084 184.008 ;
    END
  END o_loc1[4]
  PIN o_loc1[5]
    DIRECTION OUTPUT ;
    USE SIGNAL ;
    PORT
      LAYER M4 ;
        RECT  0 184.08 0.084 184.104 ;
    END
  END o_loc1[5]
  PIN o_loc1[6]
    DIRECTION OUTPUT ;
    USE SIGNAL ;
    PORT
      LAYER M4 ;
        RECT  0 184.176 0.084 184.2 ;
    END
  END o_loc1[6]
  PIN o_n[0]
    DIRECTION OUTPUT ;
    USE SIGNAL ;
    PORT
      LAYER M4 ;
        RECT  0 184.272 0.084 184.296 ;
    END
  END o_n[0]
  PIN o_n[1]
    DIRECTION OUTPUT ;
    USE SIGNAL ;
    PORT
      LAYER M4 ;
        RECT  0 184.368 0.084 184.392 ;
    END
  END o_n[1]
  PIN o_sel0[0]
    DIRECTION OUTPUT ;
    USE SIGNAL ;
    PORT
      LAYER M4 ;
        RECT  0 184.464 0.084 184.488 ;
    END
  END o_sel0[0]
  PIN o_sel0[1]
    DIRECTION OUTPUT ;
    USE SIGNAL ;
    PORT
      LAYER M4 ;
        RECT  0 184.56 0.084 184.584 ;
    END
  END o_sel0[1]
  PIN o_sel1[0]
    DIRECTION OUTPUT ;
    USE SIGNAL ;
    PORT
      LAYER M4 ;
        RECT  0 184.656 0.084 184.68 ;
    END
  END o_sel1[0]
  PIN o_sel1[1]
    DIRECTION OUTPUT ;
    USE SIGNAL ;
    PORT
      LAYER M4 ;
        RECT  0 184.752 0.084 184.776 ;
    END
  END o_sel1[1]
  PIN o_tail
    DIRECTION OUTPUT ;
    USE SIGNAL ;
    PORT
      LAYER M4 ;
        RECT  0 184.848 0.084 184.872 ;
    END
  END o_tail
  PIN o_tail_lanes[0]
    DIRECTION OUTPUT ;
    USE SIGNAL ;
    PORT
      LAYER M4 ;
        RECT  0 184.944 0.084 184.968 ;
    END
  END o_tail_lanes[0]
  PIN o_tail_lanes[1]
    DIRECTION OUTPUT ;
    USE SIGNAL ;
    PORT
      LAYER M4 ;
        RECT  0 185.04 0.084 185.064 ;
    END
  END o_tail_lanes[1]
  PIN o_tail_lanes[2]
    DIRECTION OUTPUT ;
    USE SIGNAL ;
    PORT
      LAYER M4 ;
        RECT  0 185.136 0.084 185.16 ;
    END
  END o_tail_lanes[2]
  PIN o_tail_lanes[3]
    DIRECTION OUTPUT ;
    USE SIGNAL ;
    PORT
      LAYER M4 ;
        RECT  0 185.232 0.084 185.256 ;
    END
  END o_tail_lanes[3]
  PIN o_tile0[0]
    DIRECTION OUTPUT ;
    USE SIGNAL ;
    PORT
      LAYER M4 ;
        RECT  0 185.328 0.084 185.352 ;
    END
  END o_tile0[0]
  PIN o_tile0[10]
    DIRECTION OUTPUT ;
    USE SIGNAL ;
    PORT
      LAYER M4 ;
        RECT  0 187.536 0.084 187.56 ;
    END
  END o_tile0[10]
  PIN o_tile0[1]
    DIRECTION OUTPUT ;
    USE SIGNAL ;
    PORT
      LAYER M4 ;
        RECT  0 185.424 0.084 185.448 ;
    END
  END o_tile0[1]
  PIN o_tile0[2]
    DIRECTION OUTPUT ;
    USE SIGNAL ;
    PORT
      LAYER M4 ;
        RECT  0 185.52 0.084 185.544 ;
    END
  END o_tile0[2]
  PIN o_tile0[3]
    DIRECTION OUTPUT ;
    USE SIGNAL ;
    PORT
      LAYER M4 ;
        RECT  0 185.616 0.084 185.64 ;
    END
  END o_tile0[3]
  PIN o_tile0[4]
    DIRECTION OUTPUT ;
    USE SIGNAL ;
    PORT
      LAYER M4 ;
        RECT  0 186.96 0.084 186.984 ;
    END
  END o_tile0[4]
  PIN o_tile0[5]
    DIRECTION OUTPUT ;
    USE SIGNAL ;
    PORT
      LAYER M4 ;
        RECT  0 187.056 0.084 187.08 ;
    END
  END o_tile0[5]
  PIN o_tile0[6]
    DIRECTION OUTPUT ;
    USE SIGNAL ;
    PORT
      LAYER M4 ;
        RECT  0 187.152 0.084 187.176 ;
    END
  END o_tile0[6]
  PIN o_tile0[7]
    DIRECTION OUTPUT ;
    USE SIGNAL ;
    PORT
      LAYER M4 ;
        RECT  0 187.248 0.084 187.272 ;
    END
  END o_tile0[7]
  PIN o_tile0[8]
    DIRECTION OUTPUT ;
    USE SIGNAL ;
    PORT
      LAYER M4 ;
        RECT  0 187.344 0.084 187.368 ;
    END
  END o_tile0[8]
  PIN o_tile0[9]
    DIRECTION OUTPUT ;
    USE SIGNAL ;
    PORT
      LAYER M4 ;
        RECT  0 187.44 0.084 187.464 ;
    END
  END o_tile0[9]
  PIN o_tile1[0]
    DIRECTION OUTPUT ;
    USE SIGNAL ;
    PORT
      LAYER M4 ;
        RECT  0 187.632 0.084 187.656 ;
    END
  END o_tile1[0]
  PIN o_tile1[10]
    DIRECTION OUTPUT ;
    USE SIGNAL ;
    PORT
      LAYER M4 ;
        RECT  0 188.592 0.084 188.616 ;
    END
  END o_tile1[10]
  PIN o_tile1[1]
    DIRECTION OUTPUT ;
    USE SIGNAL ;
    PORT
      LAYER M4 ;
        RECT  0 187.728 0.084 187.752 ;
    END
  END o_tile1[1]
  PIN o_tile1[2]
    DIRECTION OUTPUT ;
    USE SIGNAL ;
    PORT
      LAYER M4 ;
        RECT  0 187.824 0.084 187.848 ;
    END
  END o_tile1[2]
  PIN o_tile1[3]
    DIRECTION OUTPUT ;
    USE SIGNAL ;
    PORT
      LAYER M4 ;
        RECT  0 187.92 0.084 187.944 ;
    END
  END o_tile1[3]
  PIN o_tile1[4]
    DIRECTION OUTPUT ;
    USE SIGNAL ;
    PORT
      LAYER M4 ;
        RECT  0 188.016 0.084 188.04 ;
    END
  END o_tile1[4]
  PIN o_tile1[5]
    DIRECTION OUTPUT ;
    USE SIGNAL ;
    PORT
      LAYER M4 ;
        RECT  0 188.112 0.084 188.136 ;
    END
  END o_tile1[5]
  PIN o_tile1[6]
    DIRECTION OUTPUT ;
    USE SIGNAL ;
    PORT
      LAYER M4 ;
        RECT  0 188.208 0.084 188.232 ;
    END
  END o_tile1[6]
  PIN o_tile1[7]
    DIRECTION OUTPUT ;
    USE SIGNAL ;
    PORT
      LAYER M4 ;
        RECT  0 188.304 0.084 188.328 ;
    END
  END o_tile1[7]
  PIN o_tile1[8]
    DIRECTION OUTPUT ;
    USE SIGNAL ;
    PORT
      LAYER M4 ;
        RECT  0 188.4 0.084 188.424 ;
    END
  END o_tile1[8]
  PIN o_tile1[9]
    DIRECTION OUTPUT ;
    USE SIGNAL ;
    PORT
      LAYER M4 ;
        RECT  0 188.496 0.084 188.52 ;
    END
  END o_tile1[9]
  PIN o_v
    DIRECTION OUTPUT ;
    USE SIGNAL ;
    PORT
      LAYER M4 ;
        RECT  0 188.688 0.084 188.712 ;
    END
  END o_v
  PIN rst_n
    DIRECTION INPUT ;
    USE SIGNAL ;
    PORT
      LAYER M5 ;
        RECT  169.104 371.436 169.128 371.52 ;
    END
  END rst_n
  PIN VDD
    DIRECTION INOUT ;
    USE POWER ;
    PORT
      LAYER M5 ;
        RECT  321.192 2.151 321.312 369.369 ;
        RECT  315.792 2.151 315.912 369.369 ;
        RECT  310.392 2.151 310.512 369.369 ;
        RECT  304.992 2.151 305.112 369.369 ;
        RECT  299.592 2.151 299.712 369.369 ;
        RECT  294.192 2.151 294.312 369.369 ;
        RECT  288.792 2.151 288.912 369.369 ;
        RECT  283.392 2.151 283.512 369.369 ;
        RECT  277.992 2.151 278.112 369.369 ;
        RECT  272.592 2.151 272.712 369.369 ;
        RECT  267.192 2.151 267.312 369.369 ;
        RECT  261.792 2.151 261.912 369.369 ;
        RECT  256.392 2.151 256.512 369.369 ;
        RECT  250.992 2.151 251.112 369.369 ;
        RECT  245.592 2.151 245.712 369.369 ;
        RECT  240.192 2.151 240.312 369.369 ;
        RECT  234.792 2.151 234.912 369.369 ;
        RECT  229.392 2.151 229.512 369.369 ;
        RECT  223.992 2.151 224.112 369.369 ;
        RECT  218.592 2.151 218.712 369.369 ;
        RECT  213.192 2.151 213.312 369.369 ;
        RECT  207.792 2.151 207.912 369.369 ;
        RECT  202.392 2.151 202.512 369.369 ;
        RECT  196.992 2.151 197.112 369.369 ;
        RECT  191.592 2.151 191.712 369.369 ;
        RECT  186.192 2.151 186.312 369.369 ;
        RECT  180.792 2.151 180.912 369.369 ;
        RECT  175.392 2.151 175.512 369.369 ;
        RECT  169.992 2.151 170.112 369.369 ;
        RECT  164.592 2.151 164.712 369.369 ;
        RECT  159.192 2.151 159.312 369.369 ;
        RECT  153.792 2.151 153.912 369.369 ;
        RECT  148.392 2.151 148.512 369.369 ;
        RECT  142.992 2.151 143.112 369.369 ;
        RECT  137.592 2.151 137.712 369.369 ;
        RECT  132.192 2.151 132.312 369.369 ;
        RECT  126.792 2.151 126.912 369.369 ;
        RECT  121.392 2.151 121.512 369.369 ;
        RECT  115.992 2.151 116.112 369.369 ;
        RECT  110.592 2.151 110.712 369.369 ;
        RECT  105.192 2.151 105.312 369.369 ;
        RECT  99.792 2.151 99.912 369.369 ;
        RECT  94.392 2.151 94.512 369.369 ;
        RECT  88.992 2.151 89.112 369.369 ;
        RECT  83.592 2.151 83.712 369.369 ;
        RECT  78.192 2.151 78.312 369.369 ;
        RECT  72.792 2.151 72.912 369.369 ;
        RECT  67.392 2.151 67.512 369.369 ;
        RECT  61.992 2.151 62.112 369.369 ;
        RECT  56.592 2.151 56.712 369.369 ;
        RECT  51.192 2.151 51.312 369.369 ;
        RECT  45.792 2.151 45.912 369.369 ;
        RECT  40.392 2.151 40.512 369.369 ;
        RECT  34.992 2.151 35.112 369.369 ;
        RECT  29.592 2.151 29.712 369.369 ;
        RECT  24.192 2.151 24.312 369.369 ;
        RECT  18.792 2.151 18.912 369.369 ;
        RECT  13.392 2.151 13.512 369.369 ;
        RECT  7.992 2.151 8.112 369.369 ;
        RECT  2.592 2.151 2.712 369.369 ;
    END
  END VDD
  PIN VSS
    DIRECTION INOUT ;
    USE GROUND ;
    PORT
      LAYER M5 ;
        RECT  321 2.137 321.12 369.383 ;
        RECT  315.6 2.137 315.72 369.383 ;
        RECT  310.2 2.137 310.32 369.383 ;
        RECT  304.8 2.137 304.92 369.383 ;
        RECT  299.4 2.137 299.52 369.383 ;
        RECT  294 2.137 294.12 369.383 ;
        RECT  288.6 2.137 288.72 369.383 ;
        RECT  283.2 2.137 283.32 369.383 ;
        RECT  277.8 2.137 277.92 369.383 ;
        RECT  272.4 2.137 272.52 369.383 ;
        RECT  267 2.137 267.12 369.383 ;
        RECT  261.6 2.137 261.72 369.383 ;
        RECT  256.2 2.137 256.32 369.383 ;
        RECT  250.8 2.137 250.92 369.383 ;
        RECT  245.4 2.137 245.52 369.383 ;
        RECT  240 2.137 240.12 369.383 ;
        RECT  234.6 2.137 234.72 369.383 ;
        RECT  229.2 2.137 229.32 369.383 ;
        RECT  223.8 2.137 223.92 369.383 ;
        RECT  218.4 2.137 218.52 369.383 ;
        RECT  213 2.137 213.12 369.383 ;
        RECT  207.6 2.137 207.72 369.383 ;
        RECT  202.2 2.137 202.32 369.383 ;
        RECT  196.8 2.137 196.92 369.383 ;
        RECT  191.4 2.137 191.52 369.383 ;
        RECT  186 2.137 186.12 369.383 ;
        RECT  180.6 2.137 180.72 369.383 ;
        RECT  175.2 2.137 175.32 369.383 ;
        RECT  169.8 2.137 169.92 369.383 ;
        RECT  164.4 2.137 164.52 369.383 ;
        RECT  159 2.137 159.12 369.383 ;
        RECT  153.6 2.137 153.72 369.383 ;
        RECT  148.2 2.137 148.32 369.383 ;
        RECT  142.8 2.137 142.92 369.383 ;
        RECT  137.4 2.137 137.52 369.383 ;
        RECT  132 2.137 132.12 369.383 ;
        RECT  126.6 2.137 126.72 369.383 ;
        RECT  121.2 2.137 121.32 369.383 ;
        RECT  115.8 2.137 115.92 369.383 ;
        RECT  110.4 2.137 110.52 369.383 ;
        RECT  105 2.137 105.12 369.383 ;
        RECT  99.6 2.137 99.72 369.383 ;
        RECT  94.2 2.137 94.32 369.383 ;
        RECT  88.8 2.137 88.92 369.383 ;
        RECT  83.4 2.137 83.52 369.383 ;
        RECT  78 2.137 78.12 369.383 ;
        RECT  72.6 2.137 72.72 369.383 ;
        RECT  67.2 2.137 67.32 369.383 ;
        RECT  61.8 2.137 61.92 369.383 ;
        RECT  56.4 2.137 56.52 369.383 ;
        RECT  51 2.137 51.12 369.383 ;
        RECT  45.6 2.137 45.72 369.383 ;
        RECT  40.2 2.137 40.32 369.383 ;
        RECT  34.8 2.137 34.92 369.383 ;
        RECT  29.4 2.137 29.52 369.383 ;
        RECT  24 2.137 24.12 369.383 ;
        RECT  18.6 2.137 18.72 369.383 ;
        RECT  13.2 2.137 13.32 369.383 ;
        RECT  7.8 2.137 7.92 369.383 ;
        RECT  2.4 2.137 2.52 369.383 ;
    END
  END VSS
  OBS
    LAYER RVTN ;
     RECT  2.16 2.16 326.16 2.295 ;
     RECT  2.16 2.565 326.16 2.835 ;
     RECT  2.16 3.105 326.16 3.375 ;
     RECT  2.16 3.645 326.16 3.915 ;
     RECT  2.16 4.185 326.16 4.455 ;
     RECT  2.16 4.725 326.16 4.995 ;
     RECT  2.16 5.265 326.16 5.535 ;
     RECT  2.16 5.805 326.16 6.075 ;
     RECT  2.16 6.345 326.16 6.615 ;
     RECT  2.16 6.885 326.16 7.155 ;
     RECT  2.16 7.425 326.16 7.695 ;
     RECT  2.16 7.965 326.16 8.235 ;
     RECT  2.16 8.505 326.16 8.775 ;
     RECT  2.16 9.045 326.16 9.315 ;
     RECT  2.16 9.585 326.16 9.855 ;
     RECT  2.16 10.125 326.16 10.395 ;
     RECT  2.16 10.665 326.16 10.935 ;
     RECT  2.16 11.205 326.16 11.475 ;
     RECT  2.16 11.745 326.16 12.015 ;
     RECT  2.16 12.285 326.16 12.555 ;
     RECT  2.16 12.825 326.16 13.095 ;
     RECT  2.16 13.365 326.16 13.635 ;
     RECT  2.16 13.905 326.16 14.175 ;
     RECT  2.16 14.445 326.16 14.715 ;
     RECT  2.16 14.985 326.16 15.255 ;
     RECT  2.16 15.525 326.16 15.795 ;
     RECT  2.16 16.065 326.16 16.335 ;
     RECT  2.16 16.605 326.16 16.875 ;
     RECT  2.16 17.145 326.16 17.415 ;
     RECT  2.16 17.685 326.16 17.955 ;
     RECT  2.16 18.225 326.16 18.495 ;
     RECT  2.16 18.765 326.16 19.035 ;
     RECT  2.16 19.305 326.16 19.575 ;
     RECT  2.16 19.845 326.16 20.115 ;
     RECT  2.16 20.385 326.16 20.655 ;
     RECT  2.16 20.925 326.16 21.195 ;
     RECT  2.16 21.465 326.16 21.735 ;
     RECT  2.16 22.005 326.16 22.275 ;
     RECT  2.16 22.545 326.16 22.815 ;
     RECT  2.16 23.085 326.16 23.355 ;
     RECT  2.16 23.625 326.16 23.895 ;
     RECT  2.16 24.165 326.16 24.435 ;
     RECT  2.16 24.705 326.16 24.975 ;
     RECT  2.16 25.245 326.16 25.515 ;
     RECT  2.16 25.785 326.16 26.055 ;
     RECT  2.16 26.325 326.16 26.595 ;
     RECT  2.16 26.865 326.16 27.135 ;
     RECT  2.16 27.405 326.16 27.675 ;
     RECT  2.16 27.945 326.16 28.215 ;
     RECT  2.16 28.485 326.16 28.755 ;
     RECT  2.16 29.025 326.16 29.295 ;
     RECT  2.16 29.565 326.16 29.835 ;
     RECT  2.16 30.105 326.16 30.375 ;
     RECT  2.16 30.645 326.16 30.915 ;
     RECT  2.16 31.185 326.16 31.455 ;
     RECT  2.16 31.725 326.16 31.995 ;
     RECT  2.16 32.265 326.16 32.535 ;
     RECT  2.16 32.805 326.16 33.075 ;
     RECT  2.16 33.345 326.16 33.615 ;
     RECT  2.16 33.885 326.16 34.155 ;
     RECT  2.16 34.425 326.16 34.695 ;
     RECT  2.16 34.965 326.16 35.235 ;
     RECT  2.16 35.505 326.16 35.775 ;
     RECT  2.16 36.045 326.16 36.315 ;
     RECT  2.16 36.585 326.16 36.855 ;
     RECT  2.16 37.125 326.16 37.395 ;
     RECT  2.16 37.665 326.16 37.935 ;
     RECT  2.16 38.205 326.16 38.475 ;
     RECT  2.16 38.745 326.16 39.015 ;
     RECT  2.16 39.285 326.16 39.555 ;
     RECT  2.16 39.825 326.16 40.095 ;
     RECT  2.16 40.365 326.16 40.635 ;
     RECT  2.16 40.905 326.16 41.175 ;
     RECT  2.16 41.445 326.16 41.715 ;
     RECT  2.16 41.985 326.16 42.255 ;
     RECT  2.16 42.525 326.16 42.795 ;
     RECT  2.16 43.065 326.16 43.335 ;
     RECT  2.16 43.605 326.16 43.875 ;
     RECT  2.16 44.145 326.16 44.415 ;
     RECT  2.16 44.685 326.16 44.955 ;
     RECT  2.16 45.225 326.16 45.495 ;
     RECT  2.16 45.765 326.16 46.035 ;
     RECT  2.16 46.305 326.16 46.575 ;
     RECT  2.16 46.845 326.16 47.115 ;
     RECT  2.16 47.385 326.16 47.655 ;
     RECT  2.16 47.925 326.16 48.195 ;
     RECT  2.16 48.465 326.16 48.735 ;
     RECT  2.16 49.005 326.16 49.275 ;
     RECT  2.16 49.545 326.16 49.815 ;
     RECT  2.16 50.085 326.16 50.355 ;
     RECT  2.16 50.625 326.16 50.895 ;
     RECT  2.16 51.165 326.16 51.435 ;
     RECT  2.16 51.705 326.16 51.975 ;
     RECT  2.16 52.245 326.16 52.515 ;
     RECT  2.16 52.785 326.16 53.055 ;
     RECT  2.16 53.325 326.16 53.595 ;
     RECT  2.16 53.865 326.16 54.135 ;
     RECT  2.16 54.405 326.16 54.675 ;
     RECT  2.16 54.945 326.16 55.215 ;
     RECT  2.16 55.485 326.16 55.755 ;
     RECT  2.16 56.025 326.16 56.295 ;
     RECT  2.16 56.565 326.16 56.835 ;
     RECT  2.16 57.105 326.16 57.375 ;
     RECT  2.16 57.645 326.16 57.915 ;
     RECT  2.16 58.185 326.16 58.455 ;
     RECT  2.16 58.725 326.16 58.995 ;
     RECT  2.16 59.265 326.16 59.535 ;
     RECT  2.16 59.805 326.16 60.075 ;
     RECT  2.16 60.345 326.16 60.615 ;
     RECT  2.16 60.885 326.16 61.155 ;
     RECT  2.16 61.425 326.16 61.695 ;
     RECT  2.16 61.965 326.16 62.235 ;
     RECT  2.16 62.505 326.16 62.775 ;
     RECT  2.16 63.045 326.16 63.315 ;
     RECT  2.16 63.585 326.16 63.855 ;
     RECT  2.16 64.125 326.16 64.395 ;
     RECT  2.16 64.665 326.16 64.935 ;
     RECT  2.16 65.205 326.16 65.475 ;
     RECT  2.16 65.745 326.16 66.015 ;
     RECT  2.16 66.285 326.16 66.555 ;
     RECT  2.16 66.825 326.16 67.095 ;
     RECT  2.16 67.365 326.16 67.635 ;
     RECT  2.16 67.905 326.16 68.175 ;
     RECT  2.16 68.445 326.16 68.715 ;
     RECT  2.16 68.985 326.16 69.255 ;
     RECT  2.16 69.525 326.16 69.795 ;
     RECT  2.16 70.065 326.16 70.335 ;
     RECT  2.16 70.605 326.16 70.875 ;
     RECT  2.16 71.145 326.16 71.415 ;
     RECT  2.16 71.685 326.16 71.955 ;
     RECT  2.16 72.225 326.16 72.495 ;
     RECT  2.16 72.765 326.16 73.035 ;
     RECT  2.16 73.305 326.16 73.575 ;
     RECT  2.16 73.845 326.16 74.115 ;
     RECT  2.16 74.385 326.16 74.655 ;
     RECT  2.16 74.925 326.16 75.195 ;
     RECT  2.16 75.465 326.16 75.735 ;
     RECT  2.16 76.005 326.16 76.275 ;
     RECT  2.16 76.545 326.16 76.815 ;
     RECT  2.16 77.085 326.16 77.355 ;
     RECT  2.16 77.625 326.16 77.895 ;
     RECT  2.16 78.165 326.16 78.435 ;
     RECT  2.16 78.705 326.16 78.975 ;
     RECT  2.16 79.245 326.16 79.515 ;
     RECT  2.16 79.785 326.16 80.055 ;
     RECT  2.16 80.325 326.16 80.595 ;
     RECT  2.16 80.865 326.16 81.135 ;
     RECT  2.16 81.405 326.16 81.675 ;
     RECT  2.16 81.945 326.16 82.215 ;
     RECT  2.16 82.485 326.16 82.755 ;
     RECT  2.16 83.025 326.16 83.295 ;
     RECT  2.16 83.565 326.16 83.835 ;
     RECT  2.16 84.105 326.16 84.375 ;
     RECT  2.16 84.645 326.16 84.915 ;
     RECT  2.16 85.185 326.16 85.455 ;
     RECT  2.16 85.725 326.16 85.995 ;
     RECT  2.16 86.265 326.16 86.535 ;
     RECT  2.16 86.805 326.16 87.075 ;
     RECT  2.16 87.345 326.16 87.615 ;
     RECT  2.16 87.885 326.16 88.155 ;
     RECT  2.16 88.425 326.16 88.695 ;
     RECT  2.16 88.965 326.16 89.235 ;
     RECT  2.16 89.505 326.16 89.775 ;
     RECT  2.16 90.045 326.16 90.315 ;
     RECT  2.16 90.585 326.16 90.855 ;
     RECT  2.16 91.125 326.16 91.395 ;
     RECT  2.16 91.665 326.16 91.935 ;
     RECT  2.16 92.205 326.16 92.475 ;
     RECT  2.16 92.745 326.16 93.015 ;
     RECT  2.16 93.285 326.16 93.555 ;
     RECT  2.16 93.825 326.16 94.095 ;
     RECT  2.16 94.365 326.16 94.635 ;
     RECT  2.16 94.905 326.16 95.175 ;
     RECT  2.16 95.445 326.16 95.715 ;
     RECT  2.16 95.985 326.16 96.255 ;
     RECT  2.16 96.525 326.16 96.795 ;
     RECT  2.16 97.065 326.16 97.335 ;
     RECT  2.16 97.605 326.16 97.875 ;
     RECT  2.16 98.145 326.16 98.415 ;
     RECT  2.16 98.685 326.16 98.955 ;
     RECT  2.16 99.225 326.16 99.495 ;
     RECT  2.16 99.765 326.16 100.035 ;
     RECT  2.16 100.305 326.16 100.575 ;
     RECT  2.16 100.845 326.16 101.115 ;
     RECT  2.16 101.385 326.16 101.655 ;
     RECT  2.16 101.925 326.16 102.195 ;
     RECT  2.16 102.465 326.16 102.735 ;
     RECT  2.16 103.005 326.16 103.275 ;
     RECT  2.16 103.545 326.16 103.815 ;
     RECT  2.16 104.085 326.16 104.355 ;
     RECT  2.16 104.625 326.16 104.895 ;
     RECT  2.16 105.165 326.16 105.435 ;
     RECT  2.16 105.705 326.16 105.975 ;
     RECT  2.16 106.245 326.16 106.515 ;
     RECT  2.16 106.785 326.16 107.055 ;
     RECT  2.16 107.325 326.16 107.595 ;
     RECT  2.16 107.865 326.16 108.135 ;
     RECT  2.16 108.405 326.16 108.675 ;
     RECT  2.16 108.945 326.16 109.215 ;
     RECT  2.16 109.485 326.16 109.755 ;
     RECT  2.16 110.025 326.16 110.295 ;
     RECT  2.16 110.565 326.16 110.835 ;
     RECT  2.16 111.105 326.16 111.375 ;
     RECT  2.16 111.645 326.16 111.915 ;
     RECT  2.16 112.185 326.16 112.455 ;
     RECT  2.16 112.725 326.16 112.995 ;
     RECT  2.16 113.265 326.16 113.535 ;
     RECT  2.16 113.805 326.16 114.075 ;
     RECT  2.16 114.345 326.16 114.615 ;
     RECT  2.16 114.885 326.16 115.155 ;
     RECT  2.16 115.425 326.16 115.695 ;
     RECT  2.16 115.965 326.16 116.235 ;
     RECT  2.16 116.505 326.16 116.775 ;
     RECT  2.16 117.045 326.16 117.315 ;
     RECT  2.16 117.585 326.16 117.855 ;
     RECT  2.16 118.125 326.16 118.395 ;
     RECT  2.16 118.665 326.16 118.935 ;
     RECT  2.16 119.205 326.16 119.475 ;
     RECT  2.16 119.745 326.16 120.015 ;
     RECT  2.16 120.285 326.16 120.555 ;
     RECT  2.16 120.825 326.16 121.095 ;
     RECT  2.16 121.365 326.16 121.635 ;
     RECT  2.16 121.905 326.16 122.175 ;
     RECT  2.16 122.445 326.16 122.715 ;
     RECT  2.16 122.985 326.16 123.255 ;
     RECT  2.16 123.525 326.16 123.795 ;
     RECT  2.16 124.065 326.16 124.335 ;
     RECT  2.16 124.605 326.16 124.875 ;
     RECT  2.16 125.145 326.16 125.415 ;
     RECT  2.16 125.685 326.16 125.955 ;
     RECT  2.16 126.225 326.16 126.495 ;
     RECT  2.16 126.765 326.16 127.035 ;
     RECT  2.16 127.305 326.16 127.575 ;
     RECT  2.16 127.845 326.16 128.115 ;
     RECT  2.16 128.385 326.16 128.655 ;
     RECT  2.16 128.925 326.16 129.195 ;
     RECT  2.16 129.465 326.16 129.735 ;
     RECT  2.16 130.005 326.16 130.275 ;
     RECT  2.16 130.545 326.16 130.815 ;
     RECT  2.16 131.085 326.16 131.355 ;
     RECT  2.16 131.625 326.16 131.895 ;
     RECT  2.16 132.165 326.16 132.435 ;
     RECT  2.16 132.705 326.16 132.975 ;
     RECT  2.16 133.245 326.16 133.515 ;
     RECT  2.16 133.785 326.16 134.055 ;
     RECT  2.16 134.325 326.16 134.595 ;
     RECT  2.16 134.865 326.16 135.135 ;
     RECT  2.16 135.405 326.16 135.675 ;
     RECT  2.16 135.945 326.16 136.215 ;
     RECT  2.16 136.485 326.16 136.755 ;
     RECT  2.16 137.025 326.16 137.295 ;
     RECT  2.16 137.565 326.16 137.835 ;
     RECT  2.16 138.105 326.16 138.375 ;
     RECT  2.16 138.645 326.16 138.915 ;
     RECT  2.16 139.185 326.16 139.455 ;
     RECT  2.16 139.725 326.16 139.995 ;
     RECT  2.16 140.265 326.16 140.535 ;
     RECT  2.16 140.805 326.16 141.075 ;
     RECT  2.16 141.345 326.16 141.615 ;
     RECT  2.16 141.885 326.16 142.155 ;
     RECT  2.16 142.425 326.16 142.695 ;
     RECT  2.16 142.965 326.16 143.235 ;
     RECT  2.16 143.505 326.16 143.775 ;
     RECT  2.16 144.045 326.16 144.315 ;
     RECT  2.16 144.585 326.16 144.855 ;
     RECT  2.16 145.125 326.16 145.395 ;
     RECT  2.16 145.665 326.16 145.935 ;
     RECT  2.16 146.205 326.16 146.475 ;
     RECT  2.16 146.745 326.16 147.015 ;
     RECT  2.16 147.285 326.16 147.555 ;
     RECT  2.16 147.825 326.16 148.095 ;
     RECT  2.16 148.365 326.16 148.635 ;
     RECT  2.16 148.905 326.16 149.175 ;
     RECT  2.16 149.445 326.16 149.715 ;
     RECT  2.16 149.985 326.16 150.255 ;
     RECT  2.16 150.525 326.16 150.795 ;
     RECT  2.16 151.065 326.16 151.335 ;
     RECT  2.16 151.605 326.16 151.875 ;
     RECT  2.16 152.145 326.16 152.415 ;
     RECT  2.16 152.685 326.16 152.955 ;
     RECT  2.16 153.225 326.16 153.495 ;
     RECT  2.16 153.765 326.16 154.035 ;
     RECT  2.16 154.305 326.16 154.575 ;
     RECT  2.16 154.845 326.16 155.115 ;
     RECT  2.16 155.385 326.16 155.655 ;
     RECT  2.16 155.925 326.16 156.195 ;
     RECT  2.16 156.465 326.16 156.735 ;
     RECT  2.16 157.005 326.16 157.275 ;
     RECT  2.16 157.545 326.16 157.815 ;
     RECT  2.16 158.085 326.16 158.355 ;
     RECT  2.16 158.625 326.16 158.895 ;
     RECT  2.16 159.165 326.16 159.435 ;
     RECT  2.16 159.705 326.16 159.975 ;
     RECT  2.16 160.245 326.16 160.515 ;
     RECT  2.16 160.785 326.16 161.055 ;
     RECT  2.16 161.325 326.16 161.595 ;
     RECT  2.16 161.865 326.16 162.135 ;
     RECT  2.16 162.405 326.16 162.675 ;
     RECT  2.16 162.945 326.16 163.215 ;
     RECT  2.16 163.485 326.16 163.755 ;
     RECT  2.16 164.025 326.16 164.295 ;
     RECT  2.16 164.565 326.16 164.835 ;
     RECT  2.16 165.105 326.16 165.375 ;
     RECT  2.16 165.645 326.16 165.915 ;
     RECT  2.16 166.185 326.16 166.455 ;
     RECT  2.16 166.725 326.16 166.995 ;
     RECT  2.16 167.265 326.16 167.535 ;
     RECT  2.16 167.805 326.16 168.075 ;
     RECT  2.16 168.345 326.16 168.615 ;
     RECT  2.16 168.885 326.16 169.155 ;
     RECT  2.16 169.425 326.16 169.695 ;
     RECT  2.16 169.965 326.16 170.235 ;
     RECT  2.16 170.505 326.16 170.775 ;
     RECT  2.16 171.045 326.16 171.315 ;
     RECT  2.16 171.585 326.16 171.855 ;
     RECT  2.16 172.125 326.16 172.395 ;
     RECT  2.16 172.665 326.16 172.935 ;
     RECT  2.16 173.205 326.16 173.475 ;
     RECT  2.16 173.745 326.16 174.015 ;
     RECT  2.16 174.285 326.16 174.555 ;
     RECT  2.16 174.825 326.16 175.095 ;
     RECT  2.16 175.365 326.16 175.635 ;
     RECT  2.16 175.905 326.16 176.175 ;
     RECT  2.16 176.445 326.16 176.715 ;
     RECT  2.16 176.985 326.16 177.255 ;
     RECT  2.16 177.525 326.16 177.795 ;
     RECT  2.16 178.065 326.16 178.335 ;
     RECT  2.16 178.605 326.16 178.875 ;
     RECT  2.16 179.145 326.16 179.415 ;
     RECT  2.16 179.685 326.16 179.955 ;
     RECT  2.16 180.225 326.16 180.495 ;
     RECT  2.16 180.765 326.16 181.035 ;
     RECT  2.16 181.305 326.16 181.575 ;
     RECT  2.16 181.845 326.16 182.115 ;
     RECT  2.16 182.385 326.16 182.655 ;
     RECT  2.16 182.925 326.16 183.195 ;
     RECT  2.16 183.465 326.16 183.735 ;
     RECT  2.16 184.005 326.16 184.275 ;
     RECT  2.16 184.545 326.16 184.815 ;
     RECT  2.16 185.085 326.16 185.355 ;
     RECT  2.16 185.625 326.16 185.895 ;
     RECT  2.16 186.165 326.16 186.435 ;
     RECT  2.16 186.705 326.16 186.975 ;
     RECT  2.16 187.245 326.16 187.515 ;
     RECT  2.16 187.785 326.16 188.055 ;
     RECT  2.16 188.325 326.16 188.595 ;
     RECT  2.16 188.865 326.16 189.135 ;
     RECT  2.16 189.405 326.16 189.675 ;
     RECT  2.16 189.945 326.16 190.215 ;
     RECT  2.16 190.485 326.16 190.755 ;
     RECT  2.16 191.025 326.16 191.295 ;
     RECT  2.16 191.565 326.16 191.835 ;
     RECT  2.16 192.105 326.16 192.375 ;
     RECT  2.16 192.645 326.16 192.915 ;
     RECT  2.16 193.185 326.16 193.455 ;
     RECT  2.16 193.725 326.16 193.995 ;
     RECT  2.16 194.265 326.16 194.535 ;
     RECT  2.16 194.805 326.16 195.075 ;
     RECT  2.16 195.345 326.16 195.615 ;
     RECT  2.16 195.885 326.16 196.155 ;
     RECT  2.16 196.425 326.16 196.695 ;
     RECT  2.16 196.965 326.16 197.235 ;
     RECT  2.16 197.505 326.16 197.775 ;
     RECT  2.16 198.045 326.16 198.315 ;
     RECT  2.16 198.585 326.16 198.855 ;
     RECT  2.16 199.125 326.16 199.395 ;
     RECT  2.16 199.665 326.16 199.935 ;
     RECT  2.16 200.205 326.16 200.475 ;
     RECT  2.16 200.745 326.16 201.015 ;
     RECT  2.16 201.285 326.16 201.555 ;
     RECT  2.16 201.825 326.16 202.095 ;
     RECT  2.16 202.365 326.16 202.635 ;
     RECT  2.16 202.905 326.16 203.175 ;
     RECT  2.16 203.445 326.16 203.715 ;
     RECT  2.16 203.985 326.16 204.255 ;
     RECT  2.16 204.525 326.16 204.795 ;
     RECT  2.16 205.065 326.16 205.335 ;
     RECT  2.16 205.605 326.16 205.875 ;
     RECT  2.16 206.145 326.16 206.415 ;
     RECT  2.16 206.685 326.16 206.955 ;
     RECT  2.16 207.225 326.16 207.495 ;
     RECT  2.16 207.765 326.16 208.035 ;
     RECT  2.16 208.305 326.16 208.575 ;
     RECT  2.16 208.845 326.16 209.115 ;
     RECT  2.16 209.385 326.16 209.655 ;
     RECT  2.16 209.925 326.16 210.195 ;
     RECT  2.16 210.465 326.16 210.735 ;
     RECT  2.16 211.005 326.16 211.275 ;
     RECT  2.16 211.545 326.16 211.815 ;
     RECT  2.16 212.085 326.16 212.355 ;
     RECT  2.16 212.625 326.16 212.895 ;
     RECT  2.16 213.165 326.16 213.435 ;
     RECT  2.16 213.705 326.16 213.975 ;
     RECT  2.16 214.245 326.16 214.515 ;
     RECT  2.16 214.785 326.16 215.055 ;
     RECT  2.16 215.325 326.16 215.595 ;
     RECT  2.16 215.865 326.16 216.135 ;
     RECT  2.16 216.405 326.16 216.675 ;
     RECT  2.16 216.945 326.16 217.215 ;
     RECT  2.16 217.485 326.16 217.755 ;
     RECT  2.16 218.025 326.16 218.295 ;
     RECT  2.16 218.565 326.16 218.835 ;
     RECT  2.16 219.105 326.16 219.375 ;
     RECT  2.16 219.645 326.16 219.915 ;
     RECT  2.16 220.185 326.16 220.455 ;
     RECT  2.16 220.725 326.16 220.995 ;
     RECT  2.16 221.265 326.16 221.535 ;
     RECT  2.16 221.805 326.16 222.075 ;
     RECT  2.16 222.345 326.16 222.615 ;
     RECT  2.16 222.885 326.16 223.155 ;
     RECT  2.16 223.425 326.16 223.695 ;
     RECT  2.16 223.965 326.16 224.235 ;
     RECT  2.16 224.505 326.16 224.775 ;
     RECT  2.16 225.045 326.16 225.315 ;
     RECT  2.16 225.585 326.16 225.855 ;
     RECT  2.16 226.125 326.16 226.395 ;
     RECT  2.16 226.665 326.16 226.935 ;
     RECT  2.16 227.205 326.16 227.475 ;
     RECT  2.16 227.745 326.16 228.015 ;
     RECT  2.16 228.285 326.16 228.555 ;
     RECT  2.16 228.825 326.16 229.095 ;
     RECT  2.16 229.365 326.16 229.635 ;
     RECT  2.16 229.905 326.16 230.175 ;
     RECT  2.16 230.445 326.16 230.715 ;
     RECT  2.16 230.985 326.16 231.255 ;
     RECT  2.16 231.525 326.16 231.795 ;
     RECT  2.16 232.065 326.16 232.335 ;
     RECT  2.16 232.605 326.16 232.875 ;
     RECT  2.16 233.145 326.16 233.415 ;
     RECT  2.16 233.685 326.16 233.955 ;
     RECT  2.16 234.225 326.16 234.495 ;
     RECT  2.16 234.765 326.16 235.035 ;
     RECT  2.16 235.305 326.16 235.575 ;
     RECT  2.16 235.845 326.16 236.115 ;
     RECT  2.16 236.385 326.16 236.655 ;
     RECT  2.16 236.925 326.16 237.195 ;
     RECT  2.16 237.465 326.16 237.735 ;
     RECT  2.16 238.005 326.16 238.275 ;
     RECT  2.16 238.545 326.16 238.815 ;
     RECT  2.16 239.085 326.16 239.355 ;
     RECT  2.16 239.625 326.16 239.895 ;
     RECT  2.16 240.165 326.16 240.435 ;
     RECT  2.16 240.705 326.16 240.975 ;
     RECT  2.16 241.245 326.16 241.515 ;
     RECT  2.16 241.785 326.16 242.055 ;
     RECT  2.16 242.325 326.16 242.595 ;
     RECT  2.16 242.865 326.16 243.135 ;
     RECT  2.16 243.405 326.16 243.675 ;
     RECT  2.16 243.945 326.16 244.215 ;
     RECT  2.16 244.485 326.16 244.755 ;
     RECT  2.16 245.025 326.16 245.295 ;
     RECT  2.16 245.565 326.16 245.835 ;
     RECT  2.16 246.105 326.16 246.375 ;
     RECT  2.16 246.645 326.16 246.915 ;
     RECT  2.16 247.185 326.16 247.455 ;
     RECT  2.16 247.725 326.16 247.995 ;
     RECT  2.16 248.265 326.16 248.535 ;
     RECT  2.16 248.805 326.16 249.075 ;
     RECT  2.16 249.345 326.16 249.615 ;
     RECT  2.16 249.885 326.16 250.155 ;
     RECT  2.16 250.425 326.16 250.695 ;
     RECT  2.16 250.965 326.16 251.235 ;
     RECT  2.16 251.505 326.16 251.775 ;
     RECT  2.16 252.045 326.16 252.315 ;
     RECT  2.16 252.585 326.16 252.855 ;
     RECT  2.16 253.125 326.16 253.395 ;
     RECT  2.16 253.665 326.16 253.935 ;
     RECT  2.16 254.205 326.16 254.475 ;
     RECT  2.16 254.745 326.16 255.015 ;
     RECT  2.16 255.285 326.16 255.555 ;
     RECT  2.16 255.825 326.16 256.095 ;
     RECT  2.16 256.365 326.16 256.635 ;
     RECT  2.16 256.905 326.16 257.175 ;
     RECT  2.16 257.445 326.16 257.715 ;
     RECT  2.16 257.985 326.16 258.255 ;
     RECT  2.16 258.525 326.16 258.795 ;
     RECT  2.16 259.065 326.16 259.335 ;
     RECT  2.16 259.605 326.16 259.875 ;
     RECT  2.16 260.145 326.16 260.415 ;
     RECT  2.16 260.685 326.16 260.955 ;
     RECT  2.16 261.225 326.16 261.495 ;
     RECT  2.16 261.765 326.16 262.035 ;
     RECT  2.16 262.305 326.16 262.575 ;
     RECT  2.16 262.845 326.16 263.115 ;
     RECT  2.16 263.385 326.16 263.655 ;
     RECT  2.16 263.925 326.16 264.195 ;
     RECT  2.16 264.465 326.16 264.735 ;
     RECT  2.16 265.005 326.16 265.275 ;
     RECT  2.16 265.545 326.16 265.815 ;
     RECT  2.16 266.085 326.16 266.355 ;
     RECT  2.16 266.625 326.16 266.895 ;
     RECT  2.16 267.165 326.16 267.435 ;
     RECT  2.16 267.705 326.16 267.975 ;
     RECT  2.16 268.245 326.16 268.515 ;
     RECT  2.16 268.785 326.16 269.055 ;
     RECT  2.16 269.325 326.16 269.595 ;
     RECT  2.16 269.865 326.16 270.135 ;
     RECT  2.16 270.405 326.16 270.675 ;
     RECT  2.16 270.945 326.16 271.215 ;
     RECT  2.16 271.485 326.16 271.755 ;
     RECT  2.16 272.025 326.16 272.295 ;
     RECT  2.16 272.565 326.16 272.835 ;
     RECT  2.16 273.105 326.16 273.375 ;
     RECT  2.16 273.645 326.16 273.915 ;
     RECT  2.16 274.185 326.16 274.455 ;
     RECT  2.16 274.725 326.16 274.995 ;
     RECT  2.16 275.265 326.16 275.535 ;
     RECT  2.16 275.805 326.16 276.075 ;
     RECT  2.16 276.345 326.16 276.615 ;
     RECT  2.16 276.885 326.16 277.155 ;
     RECT  2.16 277.425 326.16 277.695 ;
     RECT  2.16 277.965 326.16 278.235 ;
     RECT  2.16 278.505 326.16 278.775 ;
     RECT  2.16 279.045 326.16 279.315 ;
     RECT  2.16 279.585 326.16 279.855 ;
     RECT  2.16 280.125 326.16 280.395 ;
     RECT  2.16 280.665 326.16 280.935 ;
     RECT  2.16 281.205 326.16 281.475 ;
     RECT  2.16 281.745 326.16 282.015 ;
     RECT  2.16 282.285 326.16 282.555 ;
     RECT  2.16 282.825 326.16 283.095 ;
     RECT  2.16 283.365 326.16 283.635 ;
     RECT  2.16 283.905 326.16 284.175 ;
     RECT  2.16 284.445 326.16 284.715 ;
     RECT  2.16 284.985 326.16 285.255 ;
     RECT  2.16 285.525 326.16 285.795 ;
     RECT  2.16 286.065 326.16 286.335 ;
     RECT  2.16 286.605 326.16 286.875 ;
     RECT  2.16 287.145 326.16 287.415 ;
     RECT  2.16 287.685 326.16 287.955 ;
     RECT  2.16 288.225 326.16 288.495 ;
     RECT  2.16 288.765 326.16 289.035 ;
     RECT  2.16 289.305 326.16 289.575 ;
     RECT  2.16 289.845 326.16 290.115 ;
     RECT  2.16 290.385 326.16 290.655 ;
     RECT  2.16 290.925 326.16 291.195 ;
     RECT  2.16 291.465 326.16 291.735 ;
     RECT  2.16 292.005 326.16 292.275 ;
     RECT  2.16 292.545 326.16 292.815 ;
     RECT  2.16 293.085 326.16 293.355 ;
     RECT  2.16 293.625 326.16 293.895 ;
     RECT  2.16 294.165 326.16 294.435 ;
     RECT  2.16 294.705 326.16 294.975 ;
     RECT  2.16 295.245 326.16 295.515 ;
     RECT  2.16 295.785 326.16 296.055 ;
     RECT  2.16 296.325 326.16 296.595 ;
     RECT  2.16 296.865 326.16 297.135 ;
     RECT  2.16 297.405 326.16 297.675 ;
     RECT  2.16 297.945 326.16 298.215 ;
     RECT  2.16 298.485 326.16 298.755 ;
     RECT  2.16 299.025 326.16 299.295 ;
     RECT  2.16 299.565 326.16 299.835 ;
     RECT  2.16 300.105 326.16 300.375 ;
     RECT  2.16 300.645 326.16 300.915 ;
     RECT  2.16 301.185 326.16 301.455 ;
     RECT  2.16 301.725 326.16 301.995 ;
     RECT  2.16 302.265 326.16 302.535 ;
     RECT  2.16 302.805 326.16 303.075 ;
     RECT  2.16 303.345 326.16 303.615 ;
     RECT  2.16 303.885 326.16 304.155 ;
     RECT  2.16 304.425 326.16 304.695 ;
     RECT  2.16 304.965 326.16 305.235 ;
     RECT  2.16 305.505 326.16 305.775 ;
     RECT  2.16 306.045 326.16 306.315 ;
     RECT  2.16 306.585 326.16 306.855 ;
     RECT  2.16 307.125 326.16 307.395 ;
     RECT  2.16 307.665 326.16 307.935 ;
     RECT  2.16 308.205 326.16 308.475 ;
     RECT  2.16 308.745 326.16 309.015 ;
     RECT  2.16 309.285 326.16 309.555 ;
     RECT  2.16 309.825 326.16 310.095 ;
     RECT  2.16 310.365 326.16 310.635 ;
     RECT  2.16 310.905 326.16 311.175 ;
     RECT  2.16 311.445 326.16 311.715 ;
     RECT  2.16 311.985 326.16 312.255 ;
     RECT  2.16 312.525 326.16 312.795 ;
     RECT  2.16 313.065 326.16 313.335 ;
     RECT  2.16 313.605 326.16 313.875 ;
     RECT  2.16 314.145 326.16 314.415 ;
     RECT  2.16 314.685 326.16 314.955 ;
     RECT  2.16 315.225 326.16 315.495 ;
     RECT  2.16 315.765 326.16 316.035 ;
     RECT  2.16 316.305 326.16 316.575 ;
     RECT  2.16 316.845 326.16 317.115 ;
     RECT  2.16 317.385 326.16 317.655 ;
     RECT  2.16 317.925 326.16 318.195 ;
     RECT  2.16 318.465 326.16 318.735 ;
     RECT  2.16 319.005 326.16 319.275 ;
     RECT  2.16 319.545 326.16 319.815 ;
     RECT  2.16 320.085 326.16 320.355 ;
     RECT  2.16 320.625 326.16 320.895 ;
     RECT  2.16 321.165 326.16 321.435 ;
     RECT  2.16 321.705 326.16 321.975 ;
     RECT  2.16 322.245 326.16 322.515 ;
     RECT  2.16 322.785 326.16 323.055 ;
     RECT  2.16 323.325 326.16 323.595 ;
     RECT  2.16 323.865 326.16 324.135 ;
     RECT  2.16 324.405 326.16 324.675 ;
     RECT  2.16 324.945 326.16 325.215 ;
     RECT  2.16 325.485 326.16 325.755 ;
     RECT  2.16 326.025 326.16 326.295 ;
     RECT  2.16 326.565 326.16 326.835 ;
     RECT  2.16 327.105 326.16 327.375 ;
     RECT  2.16 327.645 326.16 327.915 ;
     RECT  2.16 328.185 326.16 328.455 ;
     RECT  2.16 328.725 326.16 328.995 ;
     RECT  2.16 329.265 326.16 329.535 ;
     RECT  2.16 329.805 326.16 330.075 ;
     RECT  2.16 330.345 326.16 330.615 ;
     RECT  2.16 330.885 326.16 331.155 ;
     RECT  2.16 331.425 326.16 331.695 ;
     RECT  2.16 331.965 326.16 332.235 ;
     RECT  2.16 332.505 326.16 332.775 ;
     RECT  2.16 333.045 326.16 333.315 ;
     RECT  2.16 333.585 326.16 333.855 ;
     RECT  2.16 334.125 326.16 334.395 ;
     RECT  2.16 334.665 326.16 334.935 ;
     RECT  2.16 335.205 326.16 335.475 ;
     RECT  2.16 335.745 326.16 336.015 ;
     RECT  2.16 336.285 326.16 336.555 ;
     RECT  2.16 336.825 326.16 337.095 ;
     RECT  2.16 337.365 326.16 337.635 ;
     RECT  2.16 337.905 326.16 338.175 ;
     RECT  2.16 338.445 326.16 338.715 ;
     RECT  2.16 338.985 326.16 339.255 ;
     RECT  2.16 339.525 326.16 339.795 ;
     RECT  2.16 340.065 326.16 340.335 ;
     RECT  2.16 340.605 326.16 340.875 ;
     RECT  2.16 341.145 326.16 341.415 ;
     RECT  2.16 341.685 326.16 341.955 ;
     RECT  2.16 342.225 326.16 342.495 ;
     RECT  2.16 342.765 326.16 343.035 ;
     RECT  2.16 343.305 326.16 343.575 ;
     RECT  2.16 343.845 326.16 344.115 ;
     RECT  2.16 344.385 326.16 344.655 ;
     RECT  2.16 344.925 326.16 345.195 ;
     RECT  2.16 345.465 326.16 345.735 ;
     RECT  2.16 346.005 326.16 346.275 ;
     RECT  2.16 346.545 326.16 346.815 ;
     RECT  2.16 347.085 326.16 347.355 ;
     RECT  2.16 347.625 326.16 347.895 ;
     RECT  2.16 348.165 326.16 348.435 ;
     RECT  2.16 348.705 326.16 348.975 ;
     RECT  2.16 349.245 326.16 349.515 ;
     RECT  2.16 349.785 326.16 350.055 ;
     RECT  2.16 350.325 326.16 350.595 ;
     RECT  2.16 350.865 326.16 351.135 ;
     RECT  2.16 351.405 326.16 351.675 ;
     RECT  2.16 351.945 326.16 352.215 ;
     RECT  2.16 352.485 326.16 352.755 ;
     RECT  2.16 353.025 326.16 353.295 ;
     RECT  2.16 353.565 326.16 353.835 ;
     RECT  2.16 354.105 326.16 354.375 ;
     RECT  2.16 354.645 326.16 354.915 ;
     RECT  2.16 355.185 326.16 355.455 ;
     RECT  2.16 355.725 326.16 355.995 ;
     RECT  2.16 356.265 326.16 356.535 ;
     RECT  2.16 356.805 326.16 357.075 ;
     RECT  2.16 357.345 326.16 357.615 ;
     RECT  2.16 357.885 326.16 358.155 ;
     RECT  2.16 358.425 326.16 358.695 ;
     RECT  2.16 358.965 326.16 359.235 ;
     RECT  2.16 359.505 326.16 359.775 ;
     RECT  2.16 360.045 326.16 360.315 ;
     RECT  2.16 360.585 326.16 360.855 ;
     RECT  2.16 361.125 326.16 361.395 ;
     RECT  2.16 361.665 326.16 361.935 ;
     RECT  2.16 362.205 326.16 362.475 ;
     RECT  2.16 362.745 326.16 363.015 ;
     RECT  2.16 363.285 326.16 363.555 ;
     RECT  2.16 363.825 326.16 364.095 ;
     RECT  2.16 364.365 326.16 364.635 ;
     RECT  2.16 364.905 326.16 365.175 ;
     RECT  2.16 365.445 326.16 365.715 ;
     RECT  2.16 365.985 326.16 366.255 ;
     RECT  2.16 366.525 326.16 366.795 ;
     RECT  2.16 367.065 326.16 367.335 ;
     RECT  2.16 367.605 326.16 367.875 ;
     RECT  2.16 368.145 326.16 368.415 ;
     RECT  2.16 368.685 326.16 368.955 ;
     RECT  2.16 369.225 326.16 369.36 ;
    LAYER RVTP ;
     RECT  2.16 2.295 326.16 2.565 ;
     RECT  2.16 2.835 326.16 3.105 ;
     RECT  2.16 3.375 326.16 3.645 ;
     RECT  2.16 3.915 326.16 4.185 ;
     RECT  2.16 4.455 326.16 4.725 ;
     RECT  2.16 4.995 326.16 5.265 ;
     RECT  2.16 5.535 326.16 5.805 ;
     RECT  2.16 6.075 326.16 6.345 ;
     RECT  2.16 6.615 326.16 6.885 ;
     RECT  2.16 7.155 326.16 7.425 ;
     RECT  2.16 7.695 326.16 7.965 ;
     RECT  2.16 8.235 326.16 8.505 ;
     RECT  2.16 8.775 326.16 9.045 ;
     RECT  2.16 9.315 326.16 9.585 ;
     RECT  2.16 9.855 326.16 10.125 ;
     RECT  2.16 10.395 326.16 10.665 ;
     RECT  2.16 10.935 326.16 11.205 ;
     RECT  2.16 11.475 326.16 11.745 ;
     RECT  2.16 12.015 326.16 12.285 ;
     RECT  2.16 12.555 326.16 12.825 ;
     RECT  2.16 13.095 326.16 13.365 ;
     RECT  2.16 13.635 326.16 13.905 ;
     RECT  2.16 14.175 326.16 14.445 ;
     RECT  2.16 14.715 326.16 14.985 ;
     RECT  2.16 15.255 326.16 15.525 ;
     RECT  2.16 15.795 326.16 16.065 ;
     RECT  2.16 16.335 326.16 16.605 ;
     RECT  2.16 16.875 326.16 17.145 ;
     RECT  2.16 17.415 326.16 17.685 ;
     RECT  2.16 17.955 326.16 18.225 ;
     RECT  2.16 18.495 326.16 18.765 ;
     RECT  2.16 19.035 326.16 19.305 ;
     RECT  2.16 19.575 326.16 19.845 ;
     RECT  2.16 20.115 326.16 20.385 ;
     RECT  2.16 20.655 326.16 20.925 ;
     RECT  2.16 21.195 326.16 21.465 ;
     RECT  2.16 21.735 326.16 22.005 ;
     RECT  2.16 22.275 326.16 22.545 ;
     RECT  2.16 22.815 326.16 23.085 ;
     RECT  2.16 23.355 326.16 23.625 ;
     RECT  2.16 23.895 326.16 24.165 ;
     RECT  2.16 24.435 326.16 24.705 ;
     RECT  2.16 24.975 326.16 25.245 ;
     RECT  2.16 25.515 326.16 25.785 ;
     RECT  2.16 26.055 326.16 26.325 ;
     RECT  2.16 26.595 326.16 26.865 ;
     RECT  2.16 27.135 326.16 27.405 ;
     RECT  2.16 27.675 326.16 27.945 ;
     RECT  2.16 28.215 326.16 28.485 ;
     RECT  2.16 28.755 326.16 29.025 ;
     RECT  2.16 29.295 326.16 29.565 ;
     RECT  2.16 29.835 326.16 30.105 ;
     RECT  2.16 30.375 326.16 30.645 ;
     RECT  2.16 30.915 326.16 31.185 ;
     RECT  2.16 31.455 326.16 31.725 ;
     RECT  2.16 31.995 326.16 32.265 ;
     RECT  2.16 32.535 326.16 32.805 ;
     RECT  2.16 33.075 326.16 33.345 ;
     RECT  2.16 33.615 326.16 33.885 ;
     RECT  2.16 34.155 326.16 34.425 ;
     RECT  2.16 34.695 326.16 34.965 ;
     RECT  2.16 35.235 326.16 35.505 ;
     RECT  2.16 35.775 326.16 36.045 ;
     RECT  2.16 36.315 326.16 36.585 ;
     RECT  2.16 36.855 326.16 37.125 ;
     RECT  2.16 37.395 326.16 37.665 ;
     RECT  2.16 37.935 326.16 38.205 ;
     RECT  2.16 38.475 326.16 38.745 ;
     RECT  2.16 39.015 326.16 39.285 ;
     RECT  2.16 39.555 326.16 39.825 ;
     RECT  2.16 40.095 326.16 40.365 ;
     RECT  2.16 40.635 326.16 40.905 ;
     RECT  2.16 41.175 326.16 41.445 ;
     RECT  2.16 41.715 326.16 41.985 ;
     RECT  2.16 42.255 326.16 42.525 ;
     RECT  2.16 42.795 326.16 43.065 ;
     RECT  2.16 43.335 326.16 43.605 ;
     RECT  2.16 43.875 326.16 44.145 ;
     RECT  2.16 44.415 326.16 44.685 ;
     RECT  2.16 44.955 326.16 45.225 ;
     RECT  2.16 45.495 326.16 45.765 ;
     RECT  2.16 46.035 326.16 46.305 ;
     RECT  2.16 46.575 326.16 46.845 ;
     RECT  2.16 47.115 326.16 47.385 ;
     RECT  2.16 47.655 326.16 47.925 ;
     RECT  2.16 48.195 326.16 48.465 ;
     RECT  2.16 48.735 326.16 49.005 ;
     RECT  2.16 49.275 326.16 49.545 ;
     RECT  2.16 49.815 326.16 50.085 ;
     RECT  2.16 50.355 326.16 50.625 ;
     RECT  2.16 50.895 326.16 51.165 ;
     RECT  2.16 51.435 326.16 51.705 ;
     RECT  2.16 51.975 326.16 52.245 ;
     RECT  2.16 52.515 326.16 52.785 ;
     RECT  2.16 53.055 326.16 53.325 ;
     RECT  2.16 53.595 326.16 53.865 ;
     RECT  2.16 54.135 326.16 54.405 ;
     RECT  2.16 54.675 326.16 54.945 ;
     RECT  2.16 55.215 326.16 55.485 ;
     RECT  2.16 55.755 326.16 56.025 ;
     RECT  2.16 56.295 326.16 56.565 ;
     RECT  2.16 56.835 326.16 57.105 ;
     RECT  2.16 57.375 326.16 57.645 ;
     RECT  2.16 57.915 326.16 58.185 ;
     RECT  2.16 58.455 326.16 58.725 ;
     RECT  2.16 58.995 326.16 59.265 ;
     RECT  2.16 59.535 326.16 59.805 ;
     RECT  2.16 60.075 326.16 60.345 ;
     RECT  2.16 60.615 326.16 60.885 ;
     RECT  2.16 61.155 326.16 61.425 ;
     RECT  2.16 61.695 326.16 61.965 ;
     RECT  2.16 62.235 326.16 62.505 ;
     RECT  2.16 62.775 326.16 63.045 ;
     RECT  2.16 63.315 326.16 63.585 ;
     RECT  2.16 63.855 326.16 64.125 ;
     RECT  2.16 64.395 326.16 64.665 ;
     RECT  2.16 64.935 326.16 65.205 ;
     RECT  2.16 65.475 326.16 65.745 ;
     RECT  2.16 66.015 326.16 66.285 ;
     RECT  2.16 66.555 326.16 66.825 ;
     RECT  2.16 67.095 326.16 67.365 ;
     RECT  2.16 67.635 326.16 67.905 ;
     RECT  2.16 68.175 326.16 68.445 ;
     RECT  2.16 68.715 326.16 68.985 ;
     RECT  2.16 69.255 326.16 69.525 ;
     RECT  2.16 69.795 326.16 70.065 ;
     RECT  2.16 70.335 326.16 70.605 ;
     RECT  2.16 70.875 326.16 71.145 ;
     RECT  2.16 71.415 326.16 71.685 ;
     RECT  2.16 71.955 326.16 72.225 ;
     RECT  2.16 72.495 326.16 72.765 ;
     RECT  2.16 73.035 326.16 73.305 ;
     RECT  2.16 73.575 326.16 73.845 ;
     RECT  2.16 74.115 326.16 74.385 ;
     RECT  2.16 74.655 326.16 74.925 ;
     RECT  2.16 75.195 326.16 75.465 ;
     RECT  2.16 75.735 326.16 76.005 ;
     RECT  2.16 76.275 326.16 76.545 ;
     RECT  2.16 76.815 326.16 77.085 ;
     RECT  2.16 77.355 326.16 77.625 ;
     RECT  2.16 77.895 326.16 78.165 ;
     RECT  2.16 78.435 326.16 78.705 ;
     RECT  2.16 78.975 326.16 79.245 ;
     RECT  2.16 79.515 326.16 79.785 ;
     RECT  2.16 80.055 326.16 80.325 ;
     RECT  2.16 80.595 326.16 80.865 ;
     RECT  2.16 81.135 326.16 81.405 ;
     RECT  2.16 81.675 326.16 81.945 ;
     RECT  2.16 82.215 326.16 82.485 ;
     RECT  2.16 82.755 326.16 83.025 ;
     RECT  2.16 83.295 326.16 83.565 ;
     RECT  2.16 83.835 326.16 84.105 ;
     RECT  2.16 84.375 326.16 84.645 ;
     RECT  2.16 84.915 326.16 85.185 ;
     RECT  2.16 85.455 326.16 85.725 ;
     RECT  2.16 85.995 326.16 86.265 ;
     RECT  2.16 86.535 326.16 86.805 ;
     RECT  2.16 87.075 326.16 87.345 ;
     RECT  2.16 87.615 326.16 87.885 ;
     RECT  2.16 88.155 326.16 88.425 ;
     RECT  2.16 88.695 326.16 88.965 ;
     RECT  2.16 89.235 326.16 89.505 ;
     RECT  2.16 89.775 326.16 90.045 ;
     RECT  2.16 90.315 326.16 90.585 ;
     RECT  2.16 90.855 326.16 91.125 ;
     RECT  2.16 91.395 326.16 91.665 ;
     RECT  2.16 91.935 326.16 92.205 ;
     RECT  2.16 92.475 326.16 92.745 ;
     RECT  2.16 93.015 326.16 93.285 ;
     RECT  2.16 93.555 326.16 93.825 ;
     RECT  2.16 94.095 326.16 94.365 ;
     RECT  2.16 94.635 326.16 94.905 ;
     RECT  2.16 95.175 326.16 95.445 ;
     RECT  2.16 95.715 326.16 95.985 ;
     RECT  2.16 96.255 326.16 96.525 ;
     RECT  2.16 96.795 326.16 97.065 ;
     RECT  2.16 97.335 326.16 97.605 ;
     RECT  2.16 97.875 326.16 98.145 ;
     RECT  2.16 98.415 326.16 98.685 ;
     RECT  2.16 98.955 326.16 99.225 ;
     RECT  2.16 99.495 326.16 99.765 ;
     RECT  2.16 100.035 326.16 100.305 ;
     RECT  2.16 100.575 326.16 100.845 ;
     RECT  2.16 101.115 326.16 101.385 ;
     RECT  2.16 101.655 326.16 101.925 ;
     RECT  2.16 102.195 326.16 102.465 ;
     RECT  2.16 102.735 326.16 103.005 ;
     RECT  2.16 103.275 326.16 103.545 ;
     RECT  2.16 103.815 326.16 104.085 ;
     RECT  2.16 104.355 326.16 104.625 ;
     RECT  2.16 104.895 326.16 105.165 ;
     RECT  2.16 105.435 326.16 105.705 ;
     RECT  2.16 105.975 326.16 106.245 ;
     RECT  2.16 106.515 326.16 106.785 ;
     RECT  2.16 107.055 326.16 107.325 ;
     RECT  2.16 107.595 326.16 107.865 ;
     RECT  2.16 108.135 326.16 108.405 ;
     RECT  2.16 108.675 326.16 108.945 ;
     RECT  2.16 109.215 326.16 109.485 ;
     RECT  2.16 109.755 326.16 110.025 ;
     RECT  2.16 110.295 326.16 110.565 ;
     RECT  2.16 110.835 326.16 111.105 ;
     RECT  2.16 111.375 326.16 111.645 ;
     RECT  2.16 111.915 326.16 112.185 ;
     RECT  2.16 112.455 326.16 112.725 ;
     RECT  2.16 112.995 326.16 113.265 ;
     RECT  2.16 113.535 326.16 113.805 ;
     RECT  2.16 114.075 326.16 114.345 ;
     RECT  2.16 114.615 326.16 114.885 ;
     RECT  2.16 115.155 326.16 115.425 ;
     RECT  2.16 115.695 326.16 115.965 ;
     RECT  2.16 116.235 326.16 116.505 ;
     RECT  2.16 116.775 326.16 117.045 ;
     RECT  2.16 117.315 326.16 117.585 ;
     RECT  2.16 117.855 326.16 118.125 ;
     RECT  2.16 118.395 326.16 118.665 ;
     RECT  2.16 118.935 326.16 119.205 ;
     RECT  2.16 119.475 326.16 119.745 ;
     RECT  2.16 120.015 326.16 120.285 ;
     RECT  2.16 120.555 326.16 120.825 ;
     RECT  2.16 121.095 326.16 121.365 ;
     RECT  2.16 121.635 326.16 121.905 ;
     RECT  2.16 122.175 326.16 122.445 ;
     RECT  2.16 122.715 326.16 122.985 ;
     RECT  2.16 123.255 326.16 123.525 ;
     RECT  2.16 123.795 326.16 124.065 ;
     RECT  2.16 124.335 326.16 124.605 ;
     RECT  2.16 124.875 326.16 125.145 ;
     RECT  2.16 125.415 326.16 125.685 ;
     RECT  2.16 125.955 326.16 126.225 ;
     RECT  2.16 126.495 326.16 126.765 ;
     RECT  2.16 127.035 326.16 127.305 ;
     RECT  2.16 127.575 326.16 127.845 ;
     RECT  2.16 128.115 326.16 128.385 ;
     RECT  2.16 128.655 326.16 128.925 ;
     RECT  2.16 129.195 326.16 129.465 ;
     RECT  2.16 129.735 326.16 130.005 ;
     RECT  2.16 130.275 326.16 130.545 ;
     RECT  2.16 130.815 326.16 131.085 ;
     RECT  2.16 131.355 326.16 131.625 ;
     RECT  2.16 131.895 326.16 132.165 ;
     RECT  2.16 132.435 326.16 132.705 ;
     RECT  2.16 132.975 326.16 133.245 ;
     RECT  2.16 133.515 326.16 133.785 ;
     RECT  2.16 134.055 326.16 134.325 ;
     RECT  2.16 134.595 326.16 134.865 ;
     RECT  2.16 135.135 326.16 135.405 ;
     RECT  2.16 135.675 326.16 135.945 ;
     RECT  2.16 136.215 326.16 136.485 ;
     RECT  2.16 136.755 326.16 137.025 ;
     RECT  2.16 137.295 326.16 137.565 ;
     RECT  2.16 137.835 326.16 138.105 ;
     RECT  2.16 138.375 326.16 138.645 ;
     RECT  2.16 138.915 326.16 139.185 ;
     RECT  2.16 139.455 326.16 139.725 ;
     RECT  2.16 139.995 326.16 140.265 ;
     RECT  2.16 140.535 326.16 140.805 ;
     RECT  2.16 141.075 326.16 141.345 ;
     RECT  2.16 141.615 326.16 141.885 ;
     RECT  2.16 142.155 326.16 142.425 ;
     RECT  2.16 142.695 326.16 142.965 ;
     RECT  2.16 143.235 326.16 143.505 ;
     RECT  2.16 143.775 326.16 144.045 ;
     RECT  2.16 144.315 326.16 144.585 ;
     RECT  2.16 144.855 326.16 145.125 ;
     RECT  2.16 145.395 326.16 145.665 ;
     RECT  2.16 145.935 326.16 146.205 ;
     RECT  2.16 146.475 326.16 146.745 ;
     RECT  2.16 147.015 326.16 147.285 ;
     RECT  2.16 147.555 326.16 147.825 ;
     RECT  2.16 148.095 326.16 148.365 ;
     RECT  2.16 148.635 326.16 148.905 ;
     RECT  2.16 149.175 326.16 149.445 ;
     RECT  2.16 149.715 326.16 149.985 ;
     RECT  2.16 150.255 326.16 150.525 ;
     RECT  2.16 150.795 326.16 151.065 ;
     RECT  2.16 151.335 326.16 151.605 ;
     RECT  2.16 151.875 326.16 152.145 ;
     RECT  2.16 152.415 326.16 152.685 ;
     RECT  2.16 152.955 326.16 153.225 ;
     RECT  2.16 153.495 326.16 153.765 ;
     RECT  2.16 154.035 326.16 154.305 ;
     RECT  2.16 154.575 326.16 154.845 ;
     RECT  2.16 155.115 326.16 155.385 ;
     RECT  2.16 155.655 326.16 155.925 ;
     RECT  2.16 156.195 326.16 156.465 ;
     RECT  2.16 156.735 326.16 157.005 ;
     RECT  2.16 157.275 326.16 157.545 ;
     RECT  2.16 157.815 326.16 158.085 ;
     RECT  2.16 158.355 326.16 158.625 ;
     RECT  2.16 158.895 326.16 159.165 ;
     RECT  2.16 159.435 326.16 159.705 ;
     RECT  2.16 159.975 326.16 160.245 ;
     RECT  2.16 160.515 326.16 160.785 ;
     RECT  2.16 161.055 326.16 161.325 ;
     RECT  2.16 161.595 326.16 161.865 ;
     RECT  2.16 162.135 326.16 162.405 ;
     RECT  2.16 162.675 326.16 162.945 ;
     RECT  2.16 163.215 326.16 163.485 ;
     RECT  2.16 163.755 326.16 164.025 ;
     RECT  2.16 164.295 326.16 164.565 ;
     RECT  2.16 164.835 326.16 165.105 ;
     RECT  2.16 165.375 326.16 165.645 ;
     RECT  2.16 165.915 326.16 166.185 ;
     RECT  2.16 166.455 326.16 166.725 ;
     RECT  2.16 166.995 326.16 167.265 ;
     RECT  2.16 167.535 326.16 167.805 ;
     RECT  2.16 168.075 326.16 168.345 ;
     RECT  2.16 168.615 326.16 168.885 ;
     RECT  2.16 169.155 326.16 169.425 ;
     RECT  2.16 169.695 326.16 169.965 ;
     RECT  2.16 170.235 326.16 170.505 ;
     RECT  2.16 170.775 326.16 171.045 ;
     RECT  2.16 171.315 326.16 171.585 ;
     RECT  2.16 171.855 326.16 172.125 ;
     RECT  2.16 172.395 326.16 172.665 ;
     RECT  2.16 172.935 326.16 173.205 ;
     RECT  2.16 173.475 326.16 173.745 ;
     RECT  2.16 174.015 326.16 174.285 ;
     RECT  2.16 174.555 326.16 174.825 ;
     RECT  2.16 175.095 326.16 175.365 ;
     RECT  2.16 175.635 326.16 175.905 ;
     RECT  2.16 176.175 326.16 176.445 ;
     RECT  2.16 176.715 326.16 176.985 ;
     RECT  2.16 177.255 326.16 177.525 ;
     RECT  2.16 177.795 326.16 178.065 ;
     RECT  2.16 178.335 326.16 178.605 ;
     RECT  2.16 178.875 326.16 179.145 ;
     RECT  2.16 179.415 326.16 179.685 ;
     RECT  2.16 179.955 326.16 180.225 ;
     RECT  2.16 180.495 326.16 180.765 ;
     RECT  2.16 181.035 326.16 181.305 ;
     RECT  2.16 181.575 326.16 181.845 ;
     RECT  2.16 182.115 326.16 182.385 ;
     RECT  2.16 182.655 326.16 182.925 ;
     RECT  2.16 183.195 326.16 183.465 ;
     RECT  2.16 183.735 326.16 184.005 ;
     RECT  2.16 184.275 326.16 184.545 ;
     RECT  2.16 184.815 326.16 185.085 ;
     RECT  2.16 185.355 326.16 185.625 ;
     RECT  2.16 185.895 326.16 186.165 ;
     RECT  2.16 186.435 326.16 186.705 ;
     RECT  2.16 186.975 326.16 187.245 ;
     RECT  2.16 187.515 326.16 187.785 ;
     RECT  2.16 188.055 326.16 188.325 ;
     RECT  2.16 188.595 326.16 188.865 ;
     RECT  2.16 189.135 326.16 189.405 ;
     RECT  2.16 189.675 326.16 189.945 ;
     RECT  2.16 190.215 326.16 190.485 ;
     RECT  2.16 190.755 326.16 191.025 ;
     RECT  2.16 191.295 326.16 191.565 ;
     RECT  2.16 191.835 326.16 192.105 ;
     RECT  2.16 192.375 326.16 192.645 ;
     RECT  2.16 192.915 326.16 193.185 ;
     RECT  2.16 193.455 326.16 193.725 ;
     RECT  2.16 193.995 326.16 194.265 ;
     RECT  2.16 194.535 326.16 194.805 ;
     RECT  2.16 195.075 326.16 195.345 ;
     RECT  2.16 195.615 326.16 195.885 ;
     RECT  2.16 196.155 326.16 196.425 ;
     RECT  2.16 196.695 326.16 196.965 ;
     RECT  2.16 197.235 326.16 197.505 ;
     RECT  2.16 197.775 326.16 198.045 ;
     RECT  2.16 198.315 326.16 198.585 ;
     RECT  2.16 198.855 326.16 199.125 ;
     RECT  2.16 199.395 326.16 199.665 ;
     RECT  2.16 199.935 326.16 200.205 ;
     RECT  2.16 200.475 326.16 200.745 ;
     RECT  2.16 201.015 326.16 201.285 ;
     RECT  2.16 201.555 326.16 201.825 ;
     RECT  2.16 202.095 326.16 202.365 ;
     RECT  2.16 202.635 326.16 202.905 ;
     RECT  2.16 203.175 326.16 203.445 ;
     RECT  2.16 203.715 326.16 203.985 ;
     RECT  2.16 204.255 326.16 204.525 ;
     RECT  2.16 204.795 326.16 205.065 ;
     RECT  2.16 205.335 326.16 205.605 ;
     RECT  2.16 205.875 326.16 206.145 ;
     RECT  2.16 206.415 326.16 206.685 ;
     RECT  2.16 206.955 326.16 207.225 ;
     RECT  2.16 207.495 326.16 207.765 ;
     RECT  2.16 208.035 326.16 208.305 ;
     RECT  2.16 208.575 326.16 208.845 ;
     RECT  2.16 209.115 326.16 209.385 ;
     RECT  2.16 209.655 326.16 209.925 ;
     RECT  2.16 210.195 326.16 210.465 ;
     RECT  2.16 210.735 326.16 211.005 ;
     RECT  2.16 211.275 326.16 211.545 ;
     RECT  2.16 211.815 326.16 212.085 ;
     RECT  2.16 212.355 326.16 212.625 ;
     RECT  2.16 212.895 326.16 213.165 ;
     RECT  2.16 213.435 326.16 213.705 ;
     RECT  2.16 213.975 326.16 214.245 ;
     RECT  2.16 214.515 326.16 214.785 ;
     RECT  2.16 215.055 326.16 215.325 ;
     RECT  2.16 215.595 326.16 215.865 ;
     RECT  2.16 216.135 326.16 216.405 ;
     RECT  2.16 216.675 326.16 216.945 ;
     RECT  2.16 217.215 326.16 217.485 ;
     RECT  2.16 217.755 326.16 218.025 ;
     RECT  2.16 218.295 326.16 218.565 ;
     RECT  2.16 218.835 326.16 219.105 ;
     RECT  2.16 219.375 326.16 219.645 ;
     RECT  2.16 219.915 326.16 220.185 ;
     RECT  2.16 220.455 326.16 220.725 ;
     RECT  2.16 220.995 326.16 221.265 ;
     RECT  2.16 221.535 326.16 221.805 ;
     RECT  2.16 222.075 326.16 222.345 ;
     RECT  2.16 222.615 326.16 222.885 ;
     RECT  2.16 223.155 326.16 223.425 ;
     RECT  2.16 223.695 326.16 223.965 ;
     RECT  2.16 224.235 326.16 224.505 ;
     RECT  2.16 224.775 326.16 225.045 ;
     RECT  2.16 225.315 326.16 225.585 ;
     RECT  2.16 225.855 326.16 226.125 ;
     RECT  2.16 226.395 326.16 226.665 ;
     RECT  2.16 226.935 326.16 227.205 ;
     RECT  2.16 227.475 326.16 227.745 ;
     RECT  2.16 228.015 326.16 228.285 ;
     RECT  2.16 228.555 326.16 228.825 ;
     RECT  2.16 229.095 326.16 229.365 ;
     RECT  2.16 229.635 326.16 229.905 ;
     RECT  2.16 230.175 326.16 230.445 ;
     RECT  2.16 230.715 326.16 230.985 ;
     RECT  2.16 231.255 326.16 231.525 ;
     RECT  2.16 231.795 326.16 232.065 ;
     RECT  2.16 232.335 326.16 232.605 ;
     RECT  2.16 232.875 326.16 233.145 ;
     RECT  2.16 233.415 326.16 233.685 ;
     RECT  2.16 233.955 326.16 234.225 ;
     RECT  2.16 234.495 326.16 234.765 ;
     RECT  2.16 235.035 326.16 235.305 ;
     RECT  2.16 235.575 326.16 235.845 ;
     RECT  2.16 236.115 326.16 236.385 ;
     RECT  2.16 236.655 326.16 236.925 ;
     RECT  2.16 237.195 326.16 237.465 ;
     RECT  2.16 237.735 326.16 238.005 ;
     RECT  2.16 238.275 326.16 238.545 ;
     RECT  2.16 238.815 326.16 239.085 ;
     RECT  2.16 239.355 326.16 239.625 ;
     RECT  2.16 239.895 326.16 240.165 ;
     RECT  2.16 240.435 326.16 240.705 ;
     RECT  2.16 240.975 326.16 241.245 ;
     RECT  2.16 241.515 326.16 241.785 ;
     RECT  2.16 242.055 326.16 242.325 ;
     RECT  2.16 242.595 326.16 242.865 ;
     RECT  2.16 243.135 326.16 243.405 ;
     RECT  2.16 243.675 326.16 243.945 ;
     RECT  2.16 244.215 326.16 244.485 ;
     RECT  2.16 244.755 326.16 245.025 ;
     RECT  2.16 245.295 326.16 245.565 ;
     RECT  2.16 245.835 326.16 246.105 ;
     RECT  2.16 246.375 326.16 246.645 ;
     RECT  2.16 246.915 326.16 247.185 ;
     RECT  2.16 247.455 326.16 247.725 ;
     RECT  2.16 247.995 326.16 248.265 ;
     RECT  2.16 248.535 326.16 248.805 ;
     RECT  2.16 249.075 326.16 249.345 ;
     RECT  2.16 249.615 326.16 249.885 ;
     RECT  2.16 250.155 326.16 250.425 ;
     RECT  2.16 250.695 326.16 250.965 ;
     RECT  2.16 251.235 326.16 251.505 ;
     RECT  2.16 251.775 326.16 252.045 ;
     RECT  2.16 252.315 326.16 252.585 ;
     RECT  2.16 252.855 326.16 253.125 ;
     RECT  2.16 253.395 326.16 253.665 ;
     RECT  2.16 253.935 326.16 254.205 ;
     RECT  2.16 254.475 326.16 254.745 ;
     RECT  2.16 255.015 326.16 255.285 ;
     RECT  2.16 255.555 326.16 255.825 ;
     RECT  2.16 256.095 326.16 256.365 ;
     RECT  2.16 256.635 326.16 256.905 ;
     RECT  2.16 257.175 326.16 257.445 ;
     RECT  2.16 257.715 326.16 257.985 ;
     RECT  2.16 258.255 326.16 258.525 ;
     RECT  2.16 258.795 326.16 259.065 ;
     RECT  2.16 259.335 326.16 259.605 ;
     RECT  2.16 259.875 326.16 260.145 ;
     RECT  2.16 260.415 326.16 260.685 ;
     RECT  2.16 260.955 326.16 261.225 ;
     RECT  2.16 261.495 326.16 261.765 ;
     RECT  2.16 262.035 326.16 262.305 ;
     RECT  2.16 262.575 326.16 262.845 ;
     RECT  2.16 263.115 326.16 263.385 ;
     RECT  2.16 263.655 326.16 263.925 ;
     RECT  2.16 264.195 326.16 264.465 ;
     RECT  2.16 264.735 326.16 265.005 ;
     RECT  2.16 265.275 326.16 265.545 ;
     RECT  2.16 265.815 326.16 266.085 ;
     RECT  2.16 266.355 326.16 266.625 ;
     RECT  2.16 266.895 326.16 267.165 ;
     RECT  2.16 267.435 326.16 267.705 ;
     RECT  2.16 267.975 326.16 268.245 ;
     RECT  2.16 268.515 326.16 268.785 ;
     RECT  2.16 269.055 326.16 269.325 ;
     RECT  2.16 269.595 326.16 269.865 ;
     RECT  2.16 270.135 326.16 270.405 ;
     RECT  2.16 270.675 326.16 270.945 ;
     RECT  2.16 271.215 326.16 271.485 ;
     RECT  2.16 271.755 326.16 272.025 ;
     RECT  2.16 272.295 326.16 272.565 ;
     RECT  2.16 272.835 326.16 273.105 ;
     RECT  2.16 273.375 326.16 273.645 ;
     RECT  2.16 273.915 326.16 274.185 ;
     RECT  2.16 274.455 326.16 274.725 ;
     RECT  2.16 274.995 326.16 275.265 ;
     RECT  2.16 275.535 326.16 275.805 ;
     RECT  2.16 276.075 326.16 276.345 ;
     RECT  2.16 276.615 326.16 276.885 ;
     RECT  2.16 277.155 326.16 277.425 ;
     RECT  2.16 277.695 326.16 277.965 ;
     RECT  2.16 278.235 326.16 278.505 ;
     RECT  2.16 278.775 326.16 279.045 ;
     RECT  2.16 279.315 326.16 279.585 ;
     RECT  2.16 279.855 326.16 280.125 ;
     RECT  2.16 280.395 326.16 280.665 ;
     RECT  2.16 280.935 326.16 281.205 ;
     RECT  2.16 281.475 326.16 281.745 ;
     RECT  2.16 282.015 326.16 282.285 ;
     RECT  2.16 282.555 326.16 282.825 ;
     RECT  2.16 283.095 326.16 283.365 ;
     RECT  2.16 283.635 326.16 283.905 ;
     RECT  2.16 284.175 326.16 284.445 ;
     RECT  2.16 284.715 326.16 284.985 ;
     RECT  2.16 285.255 326.16 285.525 ;
     RECT  2.16 285.795 326.16 286.065 ;
     RECT  2.16 286.335 326.16 286.605 ;
     RECT  2.16 286.875 326.16 287.145 ;
     RECT  2.16 287.415 326.16 287.685 ;
     RECT  2.16 287.955 326.16 288.225 ;
     RECT  2.16 288.495 326.16 288.765 ;
     RECT  2.16 289.035 326.16 289.305 ;
     RECT  2.16 289.575 326.16 289.845 ;
     RECT  2.16 290.115 326.16 290.385 ;
     RECT  2.16 290.655 326.16 290.925 ;
     RECT  2.16 291.195 326.16 291.465 ;
     RECT  2.16 291.735 326.16 292.005 ;
     RECT  2.16 292.275 326.16 292.545 ;
     RECT  2.16 292.815 326.16 293.085 ;
     RECT  2.16 293.355 326.16 293.625 ;
     RECT  2.16 293.895 326.16 294.165 ;
     RECT  2.16 294.435 326.16 294.705 ;
     RECT  2.16 294.975 326.16 295.245 ;
     RECT  2.16 295.515 326.16 295.785 ;
     RECT  2.16 296.055 326.16 296.325 ;
     RECT  2.16 296.595 326.16 296.865 ;
     RECT  2.16 297.135 326.16 297.405 ;
     RECT  2.16 297.675 326.16 297.945 ;
     RECT  2.16 298.215 326.16 298.485 ;
     RECT  2.16 298.755 326.16 299.025 ;
     RECT  2.16 299.295 326.16 299.565 ;
     RECT  2.16 299.835 326.16 300.105 ;
     RECT  2.16 300.375 326.16 300.645 ;
     RECT  2.16 300.915 326.16 301.185 ;
     RECT  2.16 301.455 326.16 301.725 ;
     RECT  2.16 301.995 326.16 302.265 ;
     RECT  2.16 302.535 326.16 302.805 ;
     RECT  2.16 303.075 326.16 303.345 ;
     RECT  2.16 303.615 326.16 303.885 ;
     RECT  2.16 304.155 326.16 304.425 ;
     RECT  2.16 304.695 326.16 304.965 ;
     RECT  2.16 305.235 326.16 305.505 ;
     RECT  2.16 305.775 326.16 306.045 ;
     RECT  2.16 306.315 326.16 306.585 ;
     RECT  2.16 306.855 326.16 307.125 ;
     RECT  2.16 307.395 326.16 307.665 ;
     RECT  2.16 307.935 326.16 308.205 ;
     RECT  2.16 308.475 326.16 308.745 ;
     RECT  2.16 309.015 326.16 309.285 ;
     RECT  2.16 309.555 326.16 309.825 ;
     RECT  2.16 310.095 326.16 310.365 ;
     RECT  2.16 310.635 326.16 310.905 ;
     RECT  2.16 311.175 326.16 311.445 ;
     RECT  2.16 311.715 326.16 311.985 ;
     RECT  2.16 312.255 326.16 312.525 ;
     RECT  2.16 312.795 326.16 313.065 ;
     RECT  2.16 313.335 326.16 313.605 ;
     RECT  2.16 313.875 326.16 314.145 ;
     RECT  2.16 314.415 326.16 314.685 ;
     RECT  2.16 314.955 326.16 315.225 ;
     RECT  2.16 315.495 326.16 315.765 ;
     RECT  2.16 316.035 326.16 316.305 ;
     RECT  2.16 316.575 326.16 316.845 ;
     RECT  2.16 317.115 326.16 317.385 ;
     RECT  2.16 317.655 326.16 317.925 ;
     RECT  2.16 318.195 326.16 318.465 ;
     RECT  2.16 318.735 326.16 319.005 ;
     RECT  2.16 319.275 326.16 319.545 ;
     RECT  2.16 319.815 326.16 320.085 ;
     RECT  2.16 320.355 326.16 320.625 ;
     RECT  2.16 320.895 326.16 321.165 ;
     RECT  2.16 321.435 326.16 321.705 ;
     RECT  2.16 321.975 326.16 322.245 ;
     RECT  2.16 322.515 326.16 322.785 ;
     RECT  2.16 323.055 326.16 323.325 ;
     RECT  2.16 323.595 326.16 323.865 ;
     RECT  2.16 324.135 326.16 324.405 ;
     RECT  2.16 324.675 326.16 324.945 ;
     RECT  2.16 325.215 326.16 325.485 ;
     RECT  2.16 325.755 326.16 326.025 ;
     RECT  2.16 326.295 326.16 326.565 ;
     RECT  2.16 326.835 326.16 327.105 ;
     RECT  2.16 327.375 326.16 327.645 ;
     RECT  2.16 327.915 326.16 328.185 ;
     RECT  2.16 328.455 326.16 328.725 ;
     RECT  2.16 328.995 326.16 329.265 ;
     RECT  2.16 329.535 326.16 329.805 ;
     RECT  2.16 330.075 326.16 330.345 ;
     RECT  2.16 330.615 326.16 330.885 ;
     RECT  2.16 331.155 326.16 331.425 ;
     RECT  2.16 331.695 326.16 331.965 ;
     RECT  2.16 332.235 326.16 332.505 ;
     RECT  2.16 332.775 326.16 333.045 ;
     RECT  2.16 333.315 326.16 333.585 ;
     RECT  2.16 333.855 326.16 334.125 ;
     RECT  2.16 334.395 326.16 334.665 ;
     RECT  2.16 334.935 326.16 335.205 ;
     RECT  2.16 335.475 326.16 335.745 ;
     RECT  2.16 336.015 326.16 336.285 ;
     RECT  2.16 336.555 326.16 336.825 ;
     RECT  2.16 337.095 326.16 337.365 ;
     RECT  2.16 337.635 326.16 337.905 ;
     RECT  2.16 338.175 326.16 338.445 ;
     RECT  2.16 338.715 326.16 338.985 ;
     RECT  2.16 339.255 326.16 339.525 ;
     RECT  2.16 339.795 326.16 340.065 ;
     RECT  2.16 340.335 326.16 340.605 ;
     RECT  2.16 340.875 326.16 341.145 ;
     RECT  2.16 341.415 326.16 341.685 ;
     RECT  2.16 341.955 326.16 342.225 ;
     RECT  2.16 342.495 326.16 342.765 ;
     RECT  2.16 343.035 326.16 343.305 ;
     RECT  2.16 343.575 326.16 343.845 ;
     RECT  2.16 344.115 326.16 344.385 ;
     RECT  2.16 344.655 326.16 344.925 ;
     RECT  2.16 345.195 326.16 345.465 ;
     RECT  2.16 345.735 326.16 346.005 ;
     RECT  2.16 346.275 326.16 346.545 ;
     RECT  2.16 346.815 326.16 347.085 ;
     RECT  2.16 347.355 326.16 347.625 ;
     RECT  2.16 347.895 326.16 348.165 ;
     RECT  2.16 348.435 326.16 348.705 ;
     RECT  2.16 348.975 326.16 349.245 ;
     RECT  2.16 349.515 326.16 349.785 ;
     RECT  2.16 350.055 326.16 350.325 ;
     RECT  2.16 350.595 326.16 350.865 ;
     RECT  2.16 351.135 326.16 351.405 ;
     RECT  2.16 351.675 326.16 351.945 ;
     RECT  2.16 352.215 326.16 352.485 ;
     RECT  2.16 352.755 326.16 353.025 ;
     RECT  2.16 353.295 326.16 353.565 ;
     RECT  2.16 353.835 326.16 354.105 ;
     RECT  2.16 354.375 326.16 354.645 ;
     RECT  2.16 354.915 326.16 355.185 ;
     RECT  2.16 355.455 326.16 355.725 ;
     RECT  2.16 355.995 326.16 356.265 ;
     RECT  2.16 356.535 326.16 356.805 ;
     RECT  2.16 357.075 326.16 357.345 ;
     RECT  2.16 357.615 326.16 357.885 ;
     RECT  2.16 358.155 326.16 358.425 ;
     RECT  2.16 358.695 326.16 358.965 ;
     RECT  2.16 359.235 326.16 359.505 ;
     RECT  2.16 359.775 326.16 360.045 ;
     RECT  2.16 360.315 326.16 360.585 ;
     RECT  2.16 360.855 326.16 361.125 ;
     RECT  2.16 361.395 326.16 361.665 ;
     RECT  2.16 361.935 326.16 362.205 ;
     RECT  2.16 362.475 326.16 362.745 ;
     RECT  2.16 363.015 326.16 363.285 ;
     RECT  2.16 363.555 326.16 363.825 ;
     RECT  2.16 364.095 326.16 364.365 ;
     RECT  2.16 364.635 326.16 364.905 ;
     RECT  2.16 365.175 326.16 365.445 ;
     RECT  2.16 365.715 326.16 365.985 ;
     RECT  2.16 366.255 326.16 366.525 ;
     RECT  2.16 366.795 326.16 367.065 ;
     RECT  2.16 367.335 326.16 367.605 ;
     RECT  2.16 367.875 326.16 368.145 ;
     RECT  2.16 368.415 326.16 368.685 ;
     RECT  2.16 368.955 326.16 369.225 ;
    LAYER M1 ;
     RECT  2.16 2.151 326.16 369.369 ;
    LAYER M2 ;
     RECT  0.031 199.296 0.067 199.314 ;
     RECT  0.031 203.454 0.103 203.472 ;
     RECT  0.067 204.606 0.103 204.624 ;
     RECT  0.103 161.136 0.139 162.234 ;
     RECT  0.103 162.99 0.139 163.008 ;
     RECT  0.103 164.268 0.139 164.286 ;
     RECT  0.103 193.266 0.139 194.526 ;
     RECT  0.139 162.99 0.175 164.286 ;
     RECT  0.103 165.078 0.175 165.096 ;
     RECT  0.103 173.682 0.203 175.932 ;
     RECT  0.103 185.292 0.203 185.31 ;
     RECT  0.103 202.374 0.203 203.472 ;
     RECT  0.139 193.23 0.211 194.562 ;
     RECT  0.067 199.296 0.211 199.854 ;
     RECT  0.103 170.442 0.247 171.414 ;
     RECT  0.247 170.406 0.275 171.414 ;
     RECT  0.175 183.978 0.275 183.996 ;
     RECT  0.031 176.688 0.283 177.354 ;
     RECT  0.211 192.546 0.311 194.562 ;
     RECT  0.211 199.296 0.319 200.16 ;
     RECT  0.203 203.22 0.347 203.472 ;
     RECT  0.319 199.296 0.355 200.232 ;
     RECT  0.211 166.968 0.391 166.986 ;
     RECT  0.103 168.048 0.391 168.714 ;
     RECT  0.347 203.346 0.391 203.472 ;
     RECT  0.175 162.99 0.427 165.096 ;
     RECT  0.103 204.606 0.427 205.866 ;
     RECT  0.103 172.296 0.463 172.764 ;
     RECT  0.203 173.682 0.463 174.204 ;
     RECT  0.391 203.346 0.463 203.859 ;
     RECT  0.427 204.606 0.463 205.902 ;
     RECT  0.427 206.766 0.463 206.784 ;
     RECT  0.427 162.99 0.499 165.474 ;
     RECT  0.275 170.406 0.499 170.964 ;
     RECT  0.427 201.456 0.499 201.474 ;
     RECT  0.391 166.968 0.527 168.714 ;
     RECT  0.139 160.866 0.535 162.234 ;
     RECT  0.499 162.99 0.535 165.906 ;
     RECT  0.527 166.968 0.535 167.562 ;
     RECT  0.527 168.696 0.535 168.714 ;
     RECT  0.499 169.866 0.535 170.964 ;
     RECT  0.463 172.296 0.535 174.204 ;
     RECT  0.103 182.736 0.535 182.754 ;
     RECT  0.499 186.444 0.535 186.462 ;
     RECT  0.463 187.254 0.535 187.272 ;
     RECT  0.463 203.346 0.535 206.784 ;
     RECT  0.203 175.14 0.823 175.932 ;
     RECT  0.283 176.688 0.823 177.714 ;
     RECT  0.535 171.9 1.399 174.204 ;
     RECT  0.823 175.14 1.399 177.714 ;
     RECT  0.535 160.596 2.16 167.562 ;
     RECT  0.535 168.696 2.16 170.964 ;
     RECT  1.399 171.9 2.16 177.714 ;
     RECT  0.535 182.664 2.16 183.186 ;
     RECT  0.499 184.356 2.16 184.644 ;
     RECT  0.535 185.976 2.16 186.462 ;
     RECT  0.535 187.254 2.16 187.308 ;
     RECT  0.311 192.726 2.16 194.562 ;
     RECT  0.103 195.426 2.16 195.444 ;
     RECT  0.175 198.126 2.16 198.144 ;
     RECT  0.355 199.296 2.16 200.394 ;
     RECT  0.499 201.456 2.16 201.924 ;
     RECT  0.535 203.346 2.16 206.91 ;
     RECT  0.103 208.512 2.16 208.53 ;
     RECT  2.16 2.151 326.16 369.369 ;
     RECT  326.16 205.686 326.615 207.252 ;
     RECT  326.16 188.532 326.651 191.088 ;
     RECT  326.16 174.06 327.155 176.814 ;
     RECT  327.155 175.068 327.191 176.814 ;
     RECT  326.615 205.956 327.191 207.252 ;
     RECT  327.191 175.104 327.227 176.814 ;
     RECT  326.16 203.184 327.227 204.048 ;
     RECT  326.16 210.438 327.731 211.104 ;
     RECT  326.16 166.464 327.767 172.692 ;
     RECT  327.155 174.06 327.767 174.078 ;
     RECT  327.227 175.104 327.767 175.194 ;
     RECT  326.16 182.628 327.767 182.88 ;
     RECT  327.767 166.662 327.803 172.692 ;
     RECT  327.767 175.104 327.803 175.122 ;
     RECT  327.767 182.628 327.803 182.646 ;
     RECT  326.16 209.016 327.883 209.682 ;
     RECT  326.16 158.904 327.919 163.44 ;
     RECT  326.16 191.844 328.091 193.482 ;
     RECT  327.919 157.86 328.099 157.878 ;
     RECT  326.651 188.532 328.127 190.476 ;
     RECT  328.091 191.844 328.127 193.212 ;
     RECT  328.027 201.906 328.127 202.428 ;
     RECT  328.099 157.518 328.135 157.878 ;
     RECT  327.919 158.67 328.135 163.44 ;
     RECT  327.227 176.22 328.135 176.814 ;
     RECT  327.227 203.184 328.135 204.012 ;
     RECT  327.191 206.388 328.135 207.252 ;
     RECT  327.883 208.35 328.135 209.682 ;
     RECT  327.731 210.438 328.135 210.798 ;
     RECT  326.16 183.744 328.163 187.002 ;
     RECT  328.127 191.844 328.163 192.204 ;
     RECT  328.127 201.906 328.163 201.924 ;
     RECT  328.135 205.812 328.163 207.252 ;
     RECT  328.135 157.518 328.199 163.44 ;
     RECT  328.163 183.744 328.199 185.652 ;
     RECT  326.16 187.758 328.199 187.776 ;
     RECT  328.163 192.186 328.199 192.204 ;
     RECT  328.199 157.986 328.235 159.93 ;
     RECT  328.199 160.686 328.235 160.974 ;
     RECT  328.199 161.838 328.235 163.359 ;
     RECT  327.803 166.968 328.235 172.692 ;
     RECT  328.135 175.986 328.235 176.814 ;
     RECT  328.199 183.744 328.235 183.762 ;
     RECT  328.199 184.554 328.235 185.652 ;
     RECT  328.163 186.48 328.235 187.002 ;
     RECT  328.127 188.532 328.235 188.964 ;
     RECT  328.127 189.756 328.235 190.476 ;
     RECT  328.127 193.194 328.235 193.212 ;
     RECT  328.135 202.68 328.235 204.012 ;
     RECT  328.163 205.812 328.235 206.406 ;
     RECT  328.163 207.234 328.235 207.252 ;
     RECT  328.135 208.35 328.235 210.798 ;
     RECT  326.16 198.252 328.307 198.27 ;
     RECT  328.235 202.806 328.307 202.824 ;
    LAYER M3 ;
     RECT  2.415 2.143 2.505 2.413 ;
     RECT  7.815 2.143 7.905 2.413 ;
     RECT  13.215 2.143 13.305 2.413 ;
     RECT  18.615 2.143 18.705 2.413 ;
     RECT  24.015 2.143 24.105 2.413 ;
     RECT  29.415 2.143 29.505 2.413 ;
     RECT  34.815 2.143 34.905 2.413 ;
     RECT  40.215 2.143 40.305 2.413 ;
     RECT  45.615 2.143 45.705 2.413 ;
     RECT  51.015 2.143 51.105 2.413 ;
     RECT  56.415 2.143 56.505 2.413 ;
     RECT  61.815 2.143 61.905 2.413 ;
     RECT  67.215 2.143 67.305 2.413 ;
     RECT  72.615 2.143 72.705 2.413 ;
     RECT  78.015 2.143 78.105 2.413 ;
     RECT  83.415 2.143 83.505 2.413 ;
     RECT  88.815 2.143 88.905 2.413 ;
     RECT  94.215 2.143 94.305 2.413 ;
     RECT  99.615 2.143 99.705 2.413 ;
     RECT  105.015 2.143 105.105 2.413 ;
     RECT  110.415 2.143 110.505 2.413 ;
     RECT  115.815 2.143 115.905 2.413 ;
     RECT  121.215 2.143 121.305 2.413 ;
     RECT  126.615 2.143 126.705 2.413 ;
     RECT  132.015 2.143 132.105 2.413 ;
     RECT  137.415 2.143 137.505 2.413 ;
     RECT  142.815 2.143 142.905 2.413 ;
     RECT  148.215 2.143 148.305 2.413 ;
     RECT  153.615 2.143 153.705 2.413 ;
     RECT  159.015 2.143 159.105 2.413 ;
     RECT  164.415 2.143 164.505 2.413 ;
     RECT  169.815 2.143 169.905 2.413 ;
     RECT  175.215 2.143 175.305 2.413 ;
     RECT  180.615 2.143 180.705 2.413 ;
     RECT  186.015 2.143 186.105 2.413 ;
     RECT  191.415 2.143 191.505 2.413 ;
     RECT  196.815 2.143 196.905 2.413 ;
     RECT  202.215 2.143 202.305 2.413 ;
     RECT  207.615 2.143 207.705 2.413 ;
     RECT  213.015 2.143 213.105 2.413 ;
     RECT  218.415 2.143 218.505 2.413 ;
     RECT  223.815 2.143 223.905 2.413 ;
     RECT  229.215 2.143 229.305 2.413 ;
     RECT  234.615 2.143 234.705 2.413 ;
     RECT  240.015 2.143 240.105 2.413 ;
     RECT  245.415 2.143 245.505 2.413 ;
     RECT  250.815 2.143 250.905 2.413 ;
     RECT  256.215 2.143 256.305 2.413 ;
     RECT  261.615 2.143 261.705 2.413 ;
     RECT  267.015 2.143 267.105 2.413 ;
     RECT  272.415 2.143 272.505 2.413 ;
     RECT  277.815 2.143 277.905 2.413 ;
     RECT  283.215 2.143 283.305 2.413 ;
     RECT  288.615 2.143 288.705 2.413 ;
     RECT  294.015 2.143 294.105 2.413 ;
     RECT  299.415 2.143 299.505 2.413 ;
     RECT  304.815 2.143 304.905 2.413 ;
     RECT  310.215 2.143 310.305 2.413 ;
     RECT  315.615 2.143 315.705 2.413 ;
     RECT  321.015 2.143 321.105 2.413 ;
     RECT  328.14 157.387 328.158 157.483 ;
     RECT  324.9 157.441 324.918 157.531 ;
     RECT  328.032 157.483 328.194 157.579 ;
     RECT  168.948 157.585 168.966 157.621 ;
     RECT  324.9 157.531 325.458 157.621 ;
     RECT  175.215 2.413 175.497 157.711 ;
     RECT  186.015 2.413 186.297 157.711 ;
     RECT  196.815 2.413 197.097 157.711 ;
     RECT  207.615 2.413 207.897 157.711 ;
     RECT  218.415 2.413 218.697 157.711 ;
     RECT  229.215 2.413 229.497 157.711 ;
     RECT  240.015 2.413 240.297 157.711 ;
     RECT  250.815 2.413 251.097 157.711 ;
     RECT  261.615 2.413 261.897 157.711 ;
     RECT  272.415 2.413 272.697 157.711 ;
     RECT  283.215 2.413 283.497 157.711 ;
     RECT  294.015 2.413 294.297 157.711 ;
     RECT  304.815 2.413 305.097 157.711 ;
     RECT  315.615 2.413 315.897 157.711 ;
     RECT  169.815 2.413 170.097 157.723 ;
     RECT  324.9 157.621 325.494 157.739 ;
     RECT  168.948 157.621 169.038 157.771 ;
     RECT  168.84 157.771 169.038 157.855 ;
     RECT  169.815 157.723 170.442 157.855 ;
     RECT  327.924 157.579 328.194 157.883 ;
     RECT  327.996 157.883 328.194 157.963 ;
     RECT  325.188 157.739 325.494 157.981 ;
     RECT  245.415 2.413 245.697 158.059 ;
     RECT  166.464 158.017 166.482 158.089 ;
     RECT  164.415 2.413 164.697 158.161 ;
     RECT  168.228 157.855 170.442 158.161 ;
     RECT  242.856 158.059 242.874 158.161 ;
     RECT  249.084 157.867 249.102 158.161 ;
     RECT  285.696 158.059 285.714 158.251 ;
     RECT  175.104 157.711 175.497 158.285 ;
     RECT  250.704 157.711 251.097 158.285 ;
     RECT  261.504 157.711 261.897 158.285 ;
     RECT  272.304 157.711 272.697 158.285 ;
     RECT  283.104 157.711 283.497 158.285 ;
     RECT  242.28 158.161 242.874 158.287 ;
     RECT  307.008 157.579 307.026 158.299 ;
     RECT  249.084 158.161 249.21 158.315 ;
     RECT  310.215 2.413 310.497 158.323 ;
     RECT  242.1 158.287 242.946 158.333 ;
     RECT  288.615 2.413 288.897 158.347 ;
     RECT  324.288 158.155 324.306 158.351 ;
     RECT  164.415 158.161 164.754 158.359 ;
     RECT  238.284 158.287 238.302 158.387 ;
     RECT  242.244 158.333 242.946 158.387 ;
     RECT  164.415 158.359 165.15 158.395 ;
     RECT  167.58 158.161 170.442 158.395 ;
     RECT  310.068 158.323 310.497 158.423 ;
     RECT  164.415 158.395 165.438 158.431 ;
     RECT  166.356 158.089 166.554 158.431 ;
     RECT  306.54 158.299 307.026 158.431 ;
     RECT  285.336 158.251 285.714 158.521 ;
     RECT  306.108 158.431 307.026 158.521 ;
     RECT  306.108 158.521 307.17 158.549 ;
     RECT  325.188 157.981 326.034 158.549 ;
     RECT  164.415 158.431 166.554 158.557 ;
     RECT  284.904 158.521 285.822 158.557 ;
     RECT  241.2 158.521 241.218 158.573 ;
     RECT  284.904 158.557 285.894 158.573 ;
     RECT  306.54 158.549 307.17 158.585 ;
     RECT  325.188 158.549 325.818 158.585 ;
     RECT  162.252 158.557 162.27 158.593 ;
     RECT  163.044 158.557 163.062 158.593 ;
     RECT  285.804 158.573 285.894 158.621 ;
     RECT  282.168 158.059 282.186 158.657 ;
     RECT  285.876 158.621 285.894 158.657 ;
     RECT  327.996 157.963 328.23 158.665 ;
     RECT  245.415 158.059 246.222 158.683 ;
     RECT  288.504 158.347 288.897 158.683 ;
     RECT  162.252 158.593 163.062 158.701 ;
     RECT  164.415 158.557 166.626 158.701 ;
     RECT  167.364 158.395 170.442 158.701 ;
     RECT  185.904 157.711 186.297 158.729 ;
     RECT  196.704 157.711 197.097 158.729 ;
     RECT  207.504 157.711 207.897 158.729 ;
     RECT  218.304 157.711 218.697 158.729 ;
     RECT  229.104 157.711 229.497 158.729 ;
     RECT  239.904 157.711 240.297 158.729 ;
     RECT  245.124 158.683 246.222 158.729 ;
     RECT  248.832 158.683 248.85 158.729 ;
     RECT  293.904 157.711 294.297 158.729 ;
     RECT  304.704 157.711 305.097 158.729 ;
     RECT  315.504 157.711 315.897 158.729 ;
     RECT  325.188 158.585 325.494 158.731 ;
     RECT  245.415 158.729 246.222 158.791 ;
     RECT  319.536 158.635 319.554 158.819 ;
     RECT  324.9 158.731 325.494 158.819 ;
     RECT  288.504 158.683 288.99 158.855 ;
     RECT  325.332 158.819 325.494 158.909 ;
     RECT  162.252 158.701 163.386 158.971 ;
     RECT  241.38 158.701 241.398 158.999 ;
     RECT  319.86 158.923 319.878 158.999 ;
     RECT  162.252 158.971 163.602 159.097 ;
     RECT  164.415 158.701 170.478 159.097 ;
     RECT  327.924 158.665 328.23 159.115 ;
     RECT  161.172 159.019 161.19 159.133 ;
     RECT  162.108 159.097 170.478 159.133 ;
     RECT  288.615 158.855 288.99 159.161 ;
     RECT  243.072 159.163 243.09 159.197 ;
     RECT  274.176 159.067 274.194 159.197 ;
     RECT  327.708 159.115 328.23 159.211 ;
     RECT  326.592 158.923 326.61 159.269 ;
     RECT  244.188 159.331 244.206 159.355 ;
     RECT  286.236 159.331 286.254 159.367 ;
     RECT  286.236 159.367 286.326 159.389 ;
     RECT  243.936 159.355 244.206 159.395 ;
     RECT  244.188 159.395 244.206 159.431 ;
     RECT  248.544 159.061 248.67 159.437 ;
     RECT  245.415 158.791 246.258 159.439 ;
     RECT  282.24 159.367 282.258 159.439 ;
     RECT  286.308 159.389 286.326 159.439 ;
     RECT  306.216 159.403 306.45 159.439 ;
     RECT  307.224 159.241 307.242 159.439 ;
     RECT  322.128 159.367 322.146 159.439 ;
     RECT  282.168 159.439 282.258 159.467 ;
     RECT  286.308 159.439 286.398 159.467 ;
     RECT  325.332 158.909 325.35 159.467 ;
     RECT  306.108 159.439 306.45 159.499 ;
     RECT  307.224 159.439 307.602 159.499 ;
     RECT  244.26 159.439 244.278 159.539 ;
     RECT  282.168 159.467 282.222 159.539 ;
     RECT  286.38 159.467 286.398 159.539 ;
     RECT  306.108 159.499 307.602 159.539 ;
     RECT  161.172 159.133 170.478 159.601 ;
     RECT  242.244 158.387 242.262 159.601 ;
     RECT  242.244 159.601 242.478 159.637 ;
     RECT  306.432 159.539 306.882 159.665 ;
     RECT  242.208 159.637 242.478 159.677 ;
     RECT  285.372 159.601 285.39 159.677 ;
     RECT  324.828 159.595 325.206 159.701 ;
     RECT  161.172 159.601 170.514 159.745 ;
     RECT  161.172 159.745 170.586 159.781 ;
     RECT  243.396 159.511 243.414 159.809 ;
     RECT  302.148 159.673 302.166 159.809 ;
     RECT  306.612 159.665 306.882 159.809 ;
     RECT  250.815 158.285 251.097 159.871 ;
     RECT  261.615 158.285 261.897 159.871 ;
     RECT  272.415 158.285 272.697 159.871 ;
     RECT  283.215 158.285 283.497 159.871 ;
     RECT  294.015 158.729 294.297 159.871 ;
     RECT  304.815 158.729 305.097 159.871 ;
     RECT  315.615 158.729 315.897 159.871 ;
     RECT  286.56 159.781 286.578 159.907 ;
     RECT  250.704 159.871 251.097 159.917 ;
     RECT  261.504 159.871 261.897 159.917 ;
     RECT  272.304 159.871 272.697 159.917 ;
     RECT  283.104 159.871 283.497 159.917 ;
     RECT  293.904 159.871 294.297 159.917 ;
     RECT  304.704 159.871 305.097 159.917 ;
     RECT  315.504 159.871 315.897 159.917 ;
     RECT  242.244 159.677 242.478 159.971 ;
     RECT  306.612 159.809 306.63 159.971 ;
     RECT  323.46 159.781 323.478 159.971 ;
     RECT  327.672 159.211 328.23 159.971 ;
     RECT  160.344 159.781 170.586 159.979 ;
     RECT  240.015 158.729 240.297 159.979 ;
     RECT  160.272 159.979 170.586 160.007 ;
     RECT  282.204 159.539 282.222 160.007 ;
     RECT  286.56 159.907 286.758 160.007 ;
     RECT  290.052 159.781 290.07 160.007 ;
     RECT  245.415 159.439 246.33 160.027 ;
     RECT  322.056 159.439 322.146 160.043 ;
     RECT  159.015 2.413 159.297 160.051 ;
     RECT  160.272 160.007 170.442 160.051 ;
     RECT  244.8 160.027 246.33 160.079 ;
     RECT  284.616 159.979 284.634 160.079 ;
     RECT  286.56 160.007 286.686 160.079 ;
     RECT  158.076 160.051 158.094 160.141 ;
     RECT  244.8 160.079 245.697 160.169 ;
     RECT  324.828 159.701 324.99 160.171 ;
     RECT  158.076 160.141 158.202 160.249 ;
     RECT  157.572 160.249 158.202 160.285 ;
     RECT  159.015 160.051 170.442 160.285 ;
     RECT  13.215 2.413 13.497 160.315 ;
     RECT  24.015 2.413 24.297 160.315 ;
     RECT  34.815 2.413 35.097 160.315 ;
     RECT  45.615 2.413 45.897 160.315 ;
     RECT  56.415 2.413 56.697 160.315 ;
     RECT  67.215 2.413 67.497 160.315 ;
     RECT  78.015 2.413 78.297 160.315 ;
     RECT  88.815 2.413 89.097 160.315 ;
     RECT  99.615 2.413 99.897 160.315 ;
     RECT  110.415 2.413 110.697 160.315 ;
     RECT  121.215 2.413 121.497 160.315 ;
     RECT  132.015 2.413 132.297 160.315 ;
     RECT  142.815 2.413 143.097 160.315 ;
     RECT  148.215 2.413 148.497 160.315 ;
     RECT  175.215 158.285 175.497 160.315 ;
     RECT  186.015 158.729 186.297 160.315 ;
     RECT  196.815 158.729 197.097 160.315 ;
     RECT  207.615 158.729 207.897 160.315 ;
     RECT  218.415 158.729 218.697 160.315 ;
     RECT  229.215 158.729 229.497 160.315 ;
     RECT  2.415 2.413 2.697 160.321 ;
     RECT  157.572 160.285 170.442 160.321 ;
     RECT  157.536 160.321 170.442 160.349 ;
     RECT  182.412 160.249 182.43 160.349 ;
     RECT  194.364 160.249 194.382 160.349 ;
     RECT  206.352 160.249 206.37 160.349 ;
     RECT  214.344 160.249 214.362 160.349 ;
     RECT  226.296 160.249 226.314 160.349 ;
     RECT  324.288 160.171 324.99 160.349 ;
     RECT  238.284 159.673 238.302 160.411 ;
     RECT  240.015 159.979 240.678 160.411 ;
     RECT  241.416 159.883 241.434 160.411 ;
     RECT  248.004 159.931 248.022 160.411 ;
     RECT  285.804 160.267 285.822 160.411 ;
     RECT  240.015 160.411 241.434 160.439 ;
     RECT  175.104 160.315 175.497 160.445 ;
     RECT  185.904 160.315 186.297 160.445 ;
     RECT  196.704 160.315 197.097 160.445 ;
     RECT  207.504 160.315 207.897 160.445 ;
     RECT  218.304 160.315 218.697 160.445 ;
     RECT  229.104 160.315 229.497 160.445 ;
     RECT  310.215 158.423 310.497 160.447 ;
     RECT  324.288 160.349 324.306 160.475 ;
     RECT  238.284 160.411 238.374 160.493 ;
     RECT  285.012 160.411 285.822 160.519 ;
     RECT  238.356 160.493 238.374 160.541 ;
     RECT  241.128 160.439 241.146 160.541 ;
     RECT  0.108 160.459 0.126 160.555 ;
     RECT  157.536 160.349 170.334 160.555 ;
     RECT  248.004 160.411 248.13 160.583 ;
     RECT  309.996 160.447 310.497 160.583 ;
     RECT  0.108 160.555 0.162 160.591 ;
     RECT  153.615 2.413 153.897 160.603 ;
     RECT  157.392 160.555 170.334 160.603 ;
     RECT  153.615 160.603 154.494 160.699 ;
     RECT  155.664 160.591 155.682 160.699 ;
     RECT  156.744 160.603 170.334 160.699 ;
     RECT  242.172 160.459 242.19 160.699 ;
     RECT  241.992 160.699 242.19 160.709 ;
     RECT  252.252 160.555 252.27 160.709 ;
     RECT  285.012 160.519 286.254 160.709 ;
     RECT  302.148 160.555 302.166 160.709 ;
     RECT  310.068 160.583 310.497 160.709 ;
     RECT  147.996 160.315 148.497 160.717 ;
     RECT  155.664 160.699 170.334 160.717 ;
     RECT  285.012 160.709 286.182 160.733 ;
     RECT  241.992 160.709 242.01 160.745 ;
     RECT  0.108 160.591 0.558 160.781 ;
     RECT  326.592 160.363 326.61 160.781 ;
     RECT  243.324 160.681 243.342 160.825 ;
     RECT  327.744 159.971 328.23 160.843 ;
     RECT  285.012 160.733 285.03 160.853 ;
     RECT  285.804 160.733 286.182 160.853 ;
     RECT  287.424 160.459 287.442 160.853 ;
     RECT  2.304 160.321 2.697 160.877 ;
     RECT  13.104 160.315 13.497 160.877 ;
     RECT  23.904 160.315 24.297 160.877 ;
     RECT  34.704 160.315 35.097 160.877 ;
     RECT  45.504 160.315 45.897 160.877 ;
     RECT  56.304 160.315 56.697 160.877 ;
     RECT  67.104 160.315 67.497 160.877 ;
     RECT  77.904 160.315 78.297 160.877 ;
     RECT  88.704 160.315 89.097 160.877 ;
     RECT  99.504 160.315 99.897 160.877 ;
     RECT  110.304 160.315 110.697 160.877 ;
     RECT  121.104 160.315 121.497 160.877 ;
     RECT  131.904 160.315 132.297 160.877 ;
     RECT  247.428 160.861 247.446 160.951 ;
     RECT  250.815 159.917 251.097 160.951 ;
     RECT  287.604 160.861 287.622 160.951 ;
     RECT  288.615 159.161 288.897 160.951 ;
     RECT  243.324 160.825 244.026 160.979 ;
     RECT  290.124 160.951 290.142 160.987 ;
     RECT  0.108 160.781 0.306 161.021 ;
     RECT  153.324 160.699 154.494 161.023 ;
     RECT  290.124 160.987 290.214 161.051 ;
     RECT  153.324 161.023 154.746 161.059 ;
     RECT  250.815 160.951 251.406 161.069 ;
     RECT  327.168 160.843 328.23 161.069 ;
     RECT  246.708 160.951 247.446 161.087 ;
     RECT  146.628 160.861 146.646 161.095 ;
     RECT  152.748 161.059 154.746 161.095 ;
     RECT  155.556 160.717 170.334 161.095 ;
     RECT  290.196 161.051 290.214 161.123 ;
     RECT  151.884 161.095 154.746 161.131 ;
     RECT  155.484 161.095 170.334 161.131 ;
     RECT  250.815 161.069 251.097 161.131 ;
     RECT  325.188 160.591 325.206 161.131 ;
     RECT  249.804 161.131 251.097 161.165 ;
     RECT  324.9 161.131 325.206 161.165 ;
     RECT  252.396 160.861 252.45 161.221 ;
     RECT  247.176 161.087 247.446 161.249 ;
     RECT  249.804 161.165 250.002 161.249 ;
     RECT  147.888 160.717 148.497 161.257 ;
     RECT  327.168 161.069 327.186 161.285 ;
     RECT  147.888 161.257 148.626 161.293 ;
     RECT  149.472 161.095 149.49 161.293 ;
     RECT  151.884 161.131 170.334 161.309 ;
     RECT  152.028 161.309 170.334 161.321 ;
     RECT  145.188 160.987 145.206 161.323 ;
     RECT  142.704 160.315 143.097 161.329 ;
     RECT  150.48 160.843 150.498 161.329 ;
     RECT  287.604 160.951 288.897 161.357 ;
     RECT  146.412 161.095 146.646 161.365 ;
     RECT  150.48 161.329 150.678 161.365 ;
     RECT  252.396 161.221 252.486 161.393 ;
     RECT  290.232 161.227 290.25 161.393 ;
     RECT  144.936 161.323 145.206 161.401 ;
     RECT  146.412 161.365 146.754 161.401 ;
     RECT  247.176 161.249 247.266 161.405 ;
     RECT  288 161.357 288.897 161.405 ;
     RECT  147.888 161.293 149.49 161.467 ;
     RECT  147.888 161.467 149.562 161.515 ;
     RECT  150.48 161.365 151.074 161.515 ;
     RECT  0.108 161.021 0.234 161.519 ;
     RECT  286.164 160.853 286.182 161.519 ;
     RECT  290.412 161.401 290.43 161.519 ;
     RECT  144.936 161.401 146.754 161.563 ;
     RECT  175.215 160.445 175.497 161.563 ;
     RECT  144.612 161.563 146.754 161.611 ;
     RECT  144.612 161.611 146.826 161.671 ;
     RECT  176.796 161.563 176.814 161.671 ;
     RECT  282.168 161.599 282.186 161.671 ;
     RECT  176.724 161.671 176.814 161.699 ;
     RECT  282.168 161.671 282.258 161.699 ;
     RECT  322.056 161.527 322.074 161.699 ;
     RECT  142.164 161.329 143.097 161.789 ;
     RECT  144.576 161.671 146.826 161.789 ;
     RECT  174.492 161.563 175.497 161.797 ;
     RECT  176.724 161.699 176.742 161.797 ;
     RECT  140.76 161.671 140.778 161.803 ;
     RECT  241.236 161.671 241.254 161.825 ;
     RECT  282.24 161.699 282.258 161.825 ;
     RECT  287.136 161.599 287.226 161.825 ;
     RECT  325.44 161.323 325.458 161.825 ;
     RECT  140.76 161.803 141.282 161.905 ;
     RECT  147.888 161.515 151.074 161.941 ;
     RECT  140.76 161.905 141.606 161.969 ;
     RECT  2.415 160.877 2.697 161.995 ;
     RECT  13.215 160.877 13.497 162.031 ;
     RECT  24.015 160.877 24.297 162.031 ;
     RECT  34.815 160.877 35.097 162.031 ;
     RECT  45.615 160.877 45.897 162.031 ;
     RECT  56.415 160.877 56.697 162.031 ;
     RECT  67.215 160.877 67.497 162.031 ;
     RECT  78.015 160.877 78.297 162.031 ;
     RECT  88.815 160.877 89.097 162.031 ;
     RECT  99.615 160.877 99.897 162.031 ;
     RECT  110.415 160.877 110.697 162.031 ;
     RECT  121.215 160.877 121.497 162.031 ;
     RECT  132.015 160.877 132.297 162.031 ;
     RECT  144.684 161.789 146.826 162.031 ;
     RECT  147.564 161.941 151.074 162.031 ;
     RECT  141.264 161.969 141.606 162.059 ;
     RECT  34.632 162.031 35.097 162.077 ;
     RECT  248.148 161.611 248.166 162.095 ;
     RECT  307.008 161.803 307.026 162.095 ;
     RECT  142.56 161.789 143.097 162.139 ;
     RECT  243.324 160.979 243.666 162.139 ;
     RECT  306.108 162.031 306.126 162.167 ;
     RECT  243.072 162.139 243.666 162.173 ;
     RECT  144.684 162.031 151.074 162.175 ;
     RECT  174.492 161.797 176.742 162.175 ;
     RECT  285.696 162.031 285.822 162.203 ;
     RECT  152.172 161.321 170.334 162.211 ;
     RECT  173.628 161.851 173.646 162.211 ;
     RECT  174.456 162.175 176.742 162.211 ;
     RECT  243.252 162.173 243.666 162.211 ;
     RECT  245.415 160.169 245.697 162.211 ;
     RECT  249.876 161.249 250.002 162.211 ;
     RECT  250.815 161.165 251.097 162.211 ;
     RECT  252.396 161.393 252.45 162.211 ;
     RECT  248.292 162.187 248.31 162.239 ;
     RECT  285.804 162.203 285.822 162.239 ;
     RECT  328.176 161.069 328.23 162.283 ;
     RECT  142.56 162.139 143.658 162.301 ;
     RECT  171.936 162.211 171.954 162.301 ;
     RECT  245.415 162.211 245.754 162.301 ;
     RECT  252.18 162.211 252.45 162.329 ;
     RECT  327.708 162.283 328.23 162.329 ;
     RECT  290.268 162.187 290.286 162.337 ;
     RECT  319.86 162.091 319.878 162.337 ;
     RECT  0.108 161.519 0.198 162.373 ;
     RECT  144.684 162.175 151.434 162.401 ;
     RECT  243.252 162.211 244.026 162.401 ;
     RECT  152.172 162.211 170.406 162.409 ;
     RECT  319.536 162.337 319.95 162.413 ;
     RECT  327.744 162.329 328.23 162.413 ;
     RECT  152.172 162.409 171.09 162.437 ;
     RECT  242.244 162.301 242.262 162.437 ;
     RECT  245.415 162.301 246.402 162.437 ;
     RECT  286.164 162.337 286.218 162.437 ;
     RECT  290.268 162.337 290.466 162.437 ;
     RECT  318.132 162.337 318.15 162.437 ;
     RECT  319.932 162.413 319.95 162.437 ;
     RECT  144.972 162.401 151.434 162.445 ;
     RECT  152.172 162.437 170.097 162.445 ;
     RECT  170.928 162.437 171.09 162.445 ;
     RECT  171.936 162.301 172.494 162.445 ;
     RECT  324.18 161.941 324.198 162.475 ;
     RECT  170.928 162.445 172.746 162.481 ;
     RECT  173.628 162.211 176.742 162.481 ;
     RECT  243.324 162.401 244.026 162.509 ;
     RECT  323.928 162.475 324.198 162.509 ;
     RECT  141.264 162.059 141.282 162.599 ;
     RECT  170.928 162.481 176.742 162.599 ;
     RECT  2.304 161.995 2.697 162.605 ;
     RECT  323.928 162.509 324.126 162.605 ;
     RECT  290.268 162.437 290.286 162.635 ;
     RECT  323.928 162.605 323.946 162.635 ;
     RECT  142.56 162.301 143.91 162.667 ;
     RECT  252.252 162.329 252.45 162.707 ;
     RECT  325.476 162.619 325.494 162.763 ;
     RECT  325.44 162.763 325.494 162.811 ;
     RECT  141.12 162.715 141.21 162.869 ;
     RECT  144.972 162.445 170.097 162.869 ;
     RECT  171.072 162.599 176.67 162.869 ;
     RECT  324.9 162.811 325.494 162.869 ;
     RECT  142.524 162.667 143.91 162.877 ;
     RECT  171.9 162.869 176.67 162.893 ;
     RECT  249.876 162.211 251.097 162.913 ;
     RECT  288.615 161.405 288.897 162.955 ;
     RECT  141.192 162.869 141.21 162.977 ;
     RECT  142.416 162.877 143.91 162.977 ;
     RECT  142.704 162.977 143.91 163.021 ;
     RECT  13.104 162.031 13.497 163.049 ;
     RECT  23.904 162.031 24.297 163.049 ;
     RECT  34.704 162.077 35.097 163.049 ;
     RECT  45.504 162.031 45.897 163.049 ;
     RECT  56.304 162.031 56.697 163.049 ;
     RECT  67.104 162.031 67.497 163.049 ;
     RECT  77.904 162.031 78.297 163.049 ;
     RECT  88.704 162.031 89.097 163.049 ;
     RECT  99.504 162.031 99.897 163.049 ;
     RECT  110.304 162.031 110.697 163.049 ;
     RECT  121.104 162.031 121.497 163.049 ;
     RECT  131.904 162.031 132.297 163.049 ;
     RECT  142.704 163.021 144.234 163.049 ;
     RECT  0.108 162.373 0.558 163.085 ;
     RECT  325.44 162.869 325.494 163.111 ;
     RECT  142.815 163.049 144.234 163.139 ;
     RECT  325.44 163.111 325.53 163.139 ;
     RECT  325.512 163.139 325.53 163.181 ;
     RECT  245.415 162.437 245.79 163.183 ;
     RECT  172.188 162.893 176.67 163.211 ;
     RECT  178.38 163.021 178.398 163.211 ;
     RECT  145.008 162.869 170.097 163.219 ;
     RECT  328.14 162.413 328.23 163.219 ;
     RECT  322.056 162.877 322.074 163.247 ;
     RECT  327.744 163.219 328.23 163.277 ;
     RECT  254.196 163.147 254.214 163.283 ;
     RECT  145.008 163.219 170.154 163.319 ;
     RECT  243.648 162.509 244.026 163.319 ;
     RECT  328.14 163.277 328.23 163.373 ;
     RECT  2.415 162.605 2.697 163.381 ;
     RECT  249.876 162.913 251.406 163.381 ;
     RECT  294.015 159.917 294.297 163.387 ;
     RECT  288.615 162.955 289.602 163.417 ;
     RECT  2.415 163.381 2.79 163.421 ;
     RECT  328.14 163.373 328.194 163.421 ;
     RECT  2.415 163.421 2.697 163.435 ;
     RECT  288.615 163.417 290.25 163.435 ;
     RECT  288.615 163.435 290.826 163.445 ;
     RECT  328.176 163.421 328.194 163.445 ;
     RECT  286.164 162.437 286.182 163.453 ;
     RECT  145.008 163.319 170.097 163.481 ;
     RECT  290.232 163.445 290.826 163.483 ;
     RECT  286.164 163.453 286.218 163.517 ;
     RECT  290.232 163.483 291.33 163.517 ;
     RECT  294.015 163.387 294.39 163.517 ;
     RECT  254.124 163.453 254.142 163.553 ;
     RECT  245.415 163.183 246.33 163.589 ;
     RECT  286.2 163.517 286.218 163.589 ;
     RECT  249.876 163.381 251.586 163.651 ;
     RECT  252.396 162.707 252.45 163.651 ;
     RECT  290.808 163.517 291.33 163.715 ;
     RECT  253.296 163.651 253.314 163.823 ;
     RECT  172.188 163.211 176.562 163.831 ;
     RECT  249.876 163.651 252.45 163.859 ;
     RECT  142.815 163.139 143.586 163.949 ;
     RECT  291.492 163.831 291.51 163.985 ;
     RECT  134.712 163.819 134.73 163.997 ;
     RECT  137.415 2.413 137.697 164.065 ;
     RECT  138.528 163.957 138.546 164.065 ;
     RECT  140.436 163.831 140.454 164.065 ;
     RECT  142.815 163.949 143.37 164.065 ;
     RECT  171.9 163.831 176.562 164.101 ;
     RECT  140.436 164.065 140.634 164.107 ;
     RECT  2.376 163.435 2.697 164.191 ;
     RECT  13.215 163.049 13.497 164.191 ;
     RECT  24.015 163.049 24.297 164.191 ;
     RECT  34.815 163.049 35.097 164.191 ;
     RECT  45.615 163.049 45.897 164.191 ;
     RECT  56.415 163.049 56.697 164.191 ;
     RECT  67.215 163.049 67.497 164.191 ;
     RECT  78.015 163.049 78.297 164.191 ;
     RECT  88.815 163.049 89.097 164.191 ;
     RECT  99.615 163.049 99.897 164.191 ;
     RECT  110.415 163.049 110.697 164.191 ;
     RECT  121.215 163.049 121.497 164.191 ;
     RECT  132.015 163.049 132.297 164.191 ;
     RECT  180.615 2.413 180.897 164.191 ;
     RECT  253.656 164.101 253.674 164.219 ;
     RECT  0.108 163.085 0.162 164.291 ;
     RECT  171.792 164.101 176.886 164.291 ;
     RECT  250.815 163.859 252.45 164.291 ;
     RECT  134.64 164.203 134.658 164.299 ;
     RECT  137.415 164.065 138.546 164.299 ;
     RECT  171.036 164.263 171.054 164.299 ;
     RECT  171.792 164.291 176.562 164.299 ;
     RECT  134.532 164.299 134.658 164.333 ;
     RECT  140.22 164.107 140.634 164.335 ;
     RECT  180.288 164.191 180.897 164.363 ;
     RECT  142.776 164.065 143.37 164.371 ;
     RECT  0.144 164.291 0.162 164.395 ;
     RECT  142.74 164.371 143.37 164.491 ;
     RECT  134.532 164.333 134.55 164.525 ;
     RECT  145.08 163.481 170.097 164.533 ;
     RECT  178.38 164.263 178.398 164.597 ;
     RECT  137.415 164.299 138.942 164.605 ;
     RECT  140.04 164.335 140.742 164.605 ;
     RECT  137.415 164.605 140.742 164.641 ;
     RECT  13.104 164.191 13.497 164.669 ;
     RECT  23.904 164.191 24.297 164.669 ;
     RECT  34.704 164.191 35.097 164.669 ;
     RECT  45.504 164.191 45.897 164.669 ;
     RECT  56.304 164.191 56.697 164.669 ;
     RECT  67.104 164.191 67.497 164.669 ;
     RECT  77.904 164.191 78.297 164.669 ;
     RECT  88.704 164.191 89.097 164.669 ;
     RECT  99.504 164.191 99.897 164.669 ;
     RECT  110.304 164.191 110.697 164.669 ;
     RECT  121.104 164.191 121.497 164.669 ;
     RECT  131.904 164.191 132.297 164.669 ;
     RECT  243.648 163.319 243.666 164.669 ;
     RECT  2.304 164.191 2.697 164.717 ;
     RECT  142.524 164.491 143.37 164.767 ;
     RECT  171.036 164.299 176.562 164.767 ;
     RECT  0.144 164.395 0.234 164.803 ;
     RECT  170.928 164.767 176.562 164.813 ;
     RECT  142.416 164.767 143.442 164.827 ;
     RECT  144.936 164.533 170.097 164.839 ;
     RECT  142.416 164.827 143.658 164.911 ;
     RECT  144.828 164.839 170.097 164.911 ;
     RECT  142.416 164.911 143.694 164.923 ;
     RECT  144.828 164.911 170.154 165.001 ;
     RECT  186.015 160.445 186.297 165.001 ;
     RECT  252.396 164.291 252.45 165.029 ;
     RECT  144.792 165.001 170.154 165.037 ;
     RECT  137.415 164.641 140.994 165.067 ;
     RECT  141.948 164.923 143.694 165.067 ;
     RECT  171 164.813 176.562 165.067 ;
     RECT  0.144 164.803 0.414 165.073 ;
     RECT  137.415 165.067 143.694 165.073 ;
     RECT  144.468 165.037 170.154 165.073 ;
     RECT  180.396 164.363 180.897 165.101 ;
     RECT  0.108 165.073 0.414 165.109 ;
     RECT  0.108 165.109 0.522 165.181 ;
     RECT  0.108 165.181 0.558 165.197 ;
     RECT  0.216 165.197 0.558 165.293 ;
     RECT  130.824 164.779 130.842 165.299 ;
     RECT  0.396 165.293 0.558 165.379 ;
     RECT  0.396 165.379 0.63 165.437 ;
     RECT  137.124 165.073 170.154 165.541 ;
     RECT  171 165.067 176.634 165.541 ;
     RECT  137.124 165.541 176.634 165.721 ;
     RECT  178.272 165.643 178.29 165.721 ;
     RECT  0.396 165.437 0.594 165.749 ;
     RECT  137.124 165.721 177.174 165.919 ;
     RECT  178.272 165.721 178.47 165.919 ;
     RECT  133.776 165.685 133.794 165.955 ;
     RECT  2.376 164.717 2.697 165.979 ;
     RECT  250.815 164.291 251.097 165.991 ;
     RECT  252.396 165.029 252.414 165.991 ;
     RECT  2.376 165.979 2.79 166.019 ;
     RECT  134.532 165.451 134.55 166.019 ;
     RECT  137.016 165.919 178.47 166.123 ;
     RECT  133.524 165.955 133.794 166.171 ;
     RECT  136.98 166.123 178.47 166.219 ;
     RECT  136.62 166.219 178.47 166.261 ;
     RECT  2.376 166.019 2.697 166.315 ;
     RECT  13.215 164.669 13.497 166.351 ;
     RECT  24.015 164.669 24.297 166.351 ;
     RECT  34.815 164.669 35.097 166.351 ;
     RECT  45.615 164.669 45.897 166.351 ;
     RECT  56.415 164.669 56.697 166.351 ;
     RECT  67.215 164.669 67.497 166.351 ;
     RECT  78.015 164.669 78.297 166.351 ;
     RECT  88.815 164.669 89.097 166.351 ;
     RECT  99.615 164.669 99.897 166.351 ;
     RECT  110.415 164.669 110.697 166.351 ;
     RECT  121.215 164.669 121.497 166.351 ;
     RECT  132.015 164.669 132.297 166.351 ;
     RECT  136.62 166.261 178.758 166.351 ;
     RECT  249.876 163.859 249.894 166.351 ;
     RECT  250.815 165.991 252.414 166.351 ;
     RECT  133.524 166.171 134.514 166.379 ;
     RECT  131.904 166.351 132.297 166.397 ;
     RECT  136.62 166.351 179.226 166.411 ;
     RECT  136.62 166.411 179.622 166.415 ;
     RECT  133.776 166.379 134.514 166.451 ;
     RECT  180.615 165.101 180.897 166.459 ;
     RECT  249.12 161.401 249.138 166.495 ;
     RECT  249.876 166.351 252.522 166.495 ;
     RECT  133.776 166.451 134.226 166.649 ;
     RECT  182.988 166.459 183.006 166.657 ;
     RECT  253.728 166.531 253.746 166.657 ;
     RECT  290.124 166.621 290.142 166.657 ;
     RECT  327.744 166.459 327.762 166.657 ;
     RECT  180.432 166.459 181.602 166.693 ;
     RECT  182.484 166.657 183.006 166.693 ;
     RECT  130.716 165.415 130.734 166.699 ;
     RECT  133.776 166.649 134.118 166.721 ;
     RECT  137.415 166.415 179.622 166.729 ;
     RECT  180.432 166.693 183.006 166.729 ;
     RECT  133.956 166.721 134.118 166.733 ;
     RECT  0.396 165.749 0.558 166.747 ;
     RECT  249.12 166.495 252.522 166.757 ;
     RECT  290.124 166.657 290.25 166.757 ;
     RECT  327.744 166.657 327.798 166.795 ;
     RECT  136.476 166.531 136.494 166.801 ;
     RECT  249.12 166.757 252.45 166.829 ;
     RECT  253.368 166.657 254.322 166.829 ;
     RECT  136.224 166.801 136.494 166.919 ;
     RECT  137.415 166.729 183.006 166.919 ;
     RECT  138.42 166.919 183.006 166.927 ;
     RECT  290.196 166.757 290.25 166.955 ;
     RECT  136.224 166.919 136.242 166.963 ;
     RECT  0.216 166.747 0.558 167.021 ;
     RECT  138.42 166.927 183.51 167.117 ;
     RECT  249.12 166.829 251.55 167.189 ;
     RECT  134.1 166.733 134.118 167.213 ;
     RECT  135.648 166.963 136.242 167.225 ;
     RECT  130.536 166.699 130.734 167.261 ;
     RECT  135.648 167.225 135.738 167.261 ;
     RECT  138.564 167.117 183.51 167.275 ;
     RECT  290.988 166.987 291.006 167.275 ;
     RECT  132.015 166.397 132.297 167.323 ;
     RECT  138.564 167.275 183.546 167.333 ;
     RECT  135.072 167.269 135.09 167.341 ;
     RECT  253.404 166.829 254.322 167.341 ;
     RECT  13.104 166.351 13.497 167.369 ;
     RECT  23.904 166.351 24.297 167.369 ;
     RECT  34.704 166.351 35.097 167.369 ;
     RECT  45.504 166.351 45.897 167.369 ;
     RECT  56.304 166.351 56.697 167.369 ;
     RECT  67.104 166.351 67.497 167.369 ;
     RECT  77.904 166.351 78.297 167.369 ;
     RECT  88.704 166.351 89.097 167.369 ;
     RECT  99.504 166.351 99.897 167.369 ;
     RECT  110.304 166.351 110.697 167.369 ;
     RECT  121.104 166.351 121.497 167.369 ;
     RECT  131.904 167.323 132.297 167.369 ;
     RECT  135 167.341 135.09 167.369 ;
     RECT  325.476 167.179 325.494 167.371 ;
     RECT  2.304 166.315 2.697 167.405 ;
     RECT  133.128 167.305 133.146 167.459 ;
     RECT  249.876 167.189 251.55 167.459 ;
     RECT  324.9 167.371 325.494 167.459 ;
     RECT  286.164 166.765 286.182 167.467 ;
     RECT  290.88 167.275 291.006 167.467 ;
     RECT  135 167.369 135.018 167.501 ;
     RECT  253.404 167.341 254.358 167.567 ;
     RECT  286.164 167.467 286.254 167.567 ;
     RECT  322.128 167.467 322.146 167.567 ;
     RECT  0.396 167.021 0.558 167.597 ;
     RECT  252.324 166.829 252.45 167.611 ;
     RECT  253.404 167.567 253.854 167.611 ;
     RECT  249.876 167.459 251.334 167.639 ;
     RECT  327.744 166.795 328.23 167.693 ;
     RECT  252.324 167.611 253.854 167.729 ;
     RECT  253.404 167.729 253.854 167.741 ;
     RECT  328.176 167.693 328.23 167.801 ;
     RECT  249.876 167.639 251.298 167.873 ;
     RECT  254.628 167.809 254.79 167.881 ;
     RECT  138.564 167.333 183.51 167.909 ;
     RECT  0.396 167.597 0.522 168.029 ;
     RECT  145.836 167.909 183.51 168.035 ;
     RECT  249.876 167.873 251.262 168.035 ;
     RECT  0.396 168.029 0.414 168.043 ;
     RECT  290.88 167.467 291.15 168.043 ;
     RECT  326.592 167.755 326.61 168.071 ;
     RECT  0.108 168.043 0.414 168.077 ;
     RECT  290.376 168.043 291.15 168.151 ;
     RECT  137.415 166.919 137.697 168.241 ;
     RECT  290.376 168.151 291.69 168.269 ;
     RECT  324.9 167.459 324.918 168.269 ;
     RECT  133.236 167.503 133.254 168.305 ;
     RECT  290.376 168.269 291.474 168.305 ;
     RECT  145.908 168.035 183.51 168.313 ;
     RECT  137.376 168.241 137.697 168.317 ;
     RECT  138.564 167.909 145.098 168.317 ;
     RECT  253.476 167.741 253.854 168.341 ;
     RECT  132.015 167.369 132.297 168.379 ;
     RECT  145.908 168.313 183.762 168.379 ;
     RECT  294.015 163.517 294.297 168.379 ;
     RECT  132.015 168.379 132.318 168.449 ;
     RECT  145.908 168.379 183.834 168.449 ;
     RECT  304.815 159.917 305.097 168.511 ;
     RECT  315.615 159.917 315.897 168.511 ;
     RECT  145.908 168.449 183.618 168.539 ;
     RECT  249.876 168.035 251.097 168.539 ;
     RECT  253.512 168.341 253.854 168.547 ;
     RECT  254.628 167.881 254.934 168.547 ;
     RECT  328.212 167.801 328.23 168.547 ;
     RECT  304.704 168.511 305.097 168.557 ;
     RECT  315.504 168.511 315.897 168.557 ;
     RECT  138.564 168.317 144.99 168.571 ;
     RECT  290.124 168.379 290.142 168.653 ;
     RECT  294.015 168.379 294.318 168.653 ;
     RECT  253.512 168.547 254.934 168.683 ;
     RECT  252.324 167.729 252.342 168.691 ;
     RECT  138.528 168.571 144.99 168.701 ;
     RECT  138.564 168.701 144.99 168.719 ;
     RECT  327.744 168.547 328.23 168.749 ;
     RECT  145.908 168.539 183.546 168.781 ;
     RECT  252.324 168.691 252.774 168.809 ;
     RECT  325.44 168.331 325.458 168.811 ;
     RECT  286.164 167.567 286.218 168.817 ;
     RECT  0.108 168.077 0.234 168.907 ;
     RECT  254.268 168.683 254.79 168.953 ;
     RECT  0.108 168.907 0.846 169.003 ;
     RECT  325.44 168.811 325.494 169.051 ;
     RECT  138.744 168.719 144.99 169.079 ;
     RECT  286.164 168.817 286.254 169.079 ;
     RECT  324.9 169.051 325.494 169.079 ;
     RECT  324.9 169.079 324.918 169.085 ;
     RECT  291.456 168.305 291.474 169.087 ;
     RECT  258.228 169.087 258.246 169.187 ;
     RECT  286.164 169.079 286.182 169.187 ;
     RECT  290.772 169.087 291.474 169.187 ;
     RECT  322.128 169.087 322.146 169.187 ;
     RECT  253.512 168.683 253.53 169.195 ;
     RECT  252.324 168.809 252.342 169.231 ;
     RECT  140.364 169.079 144.99 169.243 ;
     RECT  145.764 168.781 183.546 169.243 ;
     RECT  140.364 169.243 183.546 169.339 ;
     RECT  251.964 169.231 252.342 169.349 ;
     RECT  291.06 169.187 291.474 169.373 ;
     RECT  253.296 169.195 253.53 169.385 ;
     RECT  2.376 167.405 2.697 169.483 ;
     RECT  13.215 167.369 13.497 169.483 ;
     RECT  24.015 167.369 24.297 169.483 ;
     RECT  34.815 167.369 35.097 169.483 ;
     RECT  45.615 167.369 45.897 169.483 ;
     RECT  56.415 167.369 56.697 169.483 ;
     RECT  67.215 167.369 67.497 169.483 ;
     RECT  78.015 167.369 78.297 169.483 ;
     RECT  88.815 167.369 89.097 169.483 ;
     RECT  99.615 167.369 99.897 169.483 ;
     RECT  110.415 167.369 110.697 169.483 ;
     RECT  121.215 167.369 121.497 169.483 ;
     RECT  132.015 168.449 132.297 169.483 ;
     RECT  254.268 168.953 254.286 169.501 ;
     RECT  2.304 169.483 2.697 169.529 ;
     RECT  13.104 169.483 13.497 169.529 ;
     RECT  23.904 169.483 24.297 169.529 ;
     RECT  34.704 169.483 35.097 169.529 ;
     RECT  45.504 169.483 45.897 169.529 ;
     RECT  56.304 169.483 56.697 169.529 ;
     RECT  67.104 169.483 67.497 169.529 ;
     RECT  77.904 169.483 78.297 169.529 ;
     RECT  88.704 169.483 89.097 169.529 ;
     RECT  99.504 169.483 99.897 169.529 ;
     RECT  110.304 169.483 110.697 169.529 ;
     RECT  121.104 169.483 121.497 169.529 ;
     RECT  131.904 169.483 132.297 169.529 ;
     RECT  294.015 168.653 294.297 169.591 ;
     RECT  250.815 168.539 251.097 169.627 ;
     RECT  134.532 169.483 134.55 169.661 ;
     RECT  328.068 168.749 328.23 169.663 ;
     RECT  253.62 169.501 254.286 169.699 ;
     RECT  327.744 169.663 328.23 169.709 ;
     RECT  253.62 169.699 254.718 169.723 ;
     RECT  253.62 169.723 254.934 169.763 ;
     RECT  290.124 169.591 290.142 169.763 ;
     RECT  293.976 169.591 294.297 169.763 ;
     RECT  137.415 168.317 137.697 169.771 ;
     RECT  291.456 169.373 291.474 169.799 ;
     RECT  138.744 169.079 139.374 169.861 ;
     RECT  140.364 169.339 183.726 169.861 ;
     RECT  254.232 169.763 254.934 169.861 ;
     RECT  256.215 2.413 256.497 169.897 ;
     RECT  138.744 169.861 183.726 169.915 ;
     RECT  138.564 169.915 183.726 169.933 ;
     RECT  138.528 169.933 183.726 169.969 ;
     RECT  138.528 169.969 183.762 169.997 ;
     RECT  137.415 169.771 137.754 170.033 ;
     RECT  134.172 170.041 134.19 170.159 ;
     RECT  254.232 169.861 255.114 170.159 ;
     RECT  258.228 170.131 258.246 170.167 ;
     RECT  254.232 170.159 254.934 170.195 ;
     RECT  185.004 170.005 185.022 170.203 ;
     RECT  258.228 170.167 258.318 170.231 ;
     RECT  185.004 170.203 185.094 170.239 ;
     RECT  185.004 170.239 185.238 170.251 ;
     RECT  186.015 165.001 186.678 170.251 ;
     RECT  2.376 169.529 2.697 170.299 ;
     RECT  139.356 169.997 183.762 170.299 ;
     RECT  258.3 170.231 258.318 170.303 ;
     RECT  132.015 169.529 132.297 170.311 ;
     RECT  2.376 170.299 2.79 170.339 ;
     RECT  139.356 170.299 184.014 170.429 ;
     RECT  249.876 168.539 249.894 170.437 ;
     RECT  250.812 169.627 251.097 170.437 ;
     RECT  132.015 170.311 132.858 170.465 ;
     RECT  185.004 170.251 186.678 170.465 ;
     RECT  252.324 169.349 252.342 170.473 ;
     RECT  325.944 170.395 325.962 170.473 ;
     RECT  328.14 169.709 328.23 170.509 ;
     RECT  325.8 170.473 325.962 170.539 ;
     RECT  252.18 170.473 252.342 170.545 ;
     RECT  325.476 170.539 325.962 170.545 ;
     RECT  185.004 170.465 185.022 170.573 ;
     RECT  256.176 169.897 256.497 170.581 ;
     RECT  325.476 170.545 326.646 170.671 ;
     RECT  183.816 170.429 184.014 170.699 ;
     RECT  291.6 170.509 291.618 170.699 ;
     RECT  322.128 170.437 322.146 170.707 ;
     RECT  138.528 169.997 138.618 170.717 ;
     RECT  183.996 170.699 184.014 170.779 ;
     RECT  249.876 170.437 251.097 170.779 ;
     RECT  252.144 170.545 252.342 170.779 ;
     RECT  255.852 170.581 256.497 170.815 ;
     RECT  327.78 170.509 328.23 170.815 ;
     RECT  322.056 170.707 322.146 170.843 ;
     RECT  137.415 170.033 137.697 170.851 ;
     RECT  254.232 170.195 254.754 170.941 ;
     RECT  255.708 170.815 256.497 170.941 ;
     RECT  134.532 170.743 134.55 170.969 ;
     RECT  136.98 170.851 137.754 170.969 ;
     RECT  324.9 170.671 326.646 171.005 ;
     RECT  291.996 170.827 292.014 171.041 ;
     RECT  254.232 170.941 256.497 171.077 ;
     RECT  249.876 170.779 252.342 171.085 ;
     RECT  254.232 171.077 255.006 171.113 ;
     RECT  13.215 169.529 13.497 171.115 ;
     RECT  24.015 169.529 24.297 171.115 ;
     RECT  34.815 169.529 35.097 171.115 ;
     RECT  45.615 169.529 45.897 171.115 ;
     RECT  56.415 169.529 56.697 171.115 ;
     RECT  67.215 169.529 67.497 171.115 ;
     RECT  78.015 169.529 78.297 171.115 ;
     RECT  88.815 169.529 89.097 171.115 ;
     RECT  99.615 169.529 99.897 171.115 ;
     RECT  110.415 169.529 110.697 171.115 ;
     RECT  121.215 169.529 121.497 171.115 ;
     RECT  132.015 170.465 132.297 171.115 ;
     RECT  183.996 170.779 184.518 171.149 ;
     RECT  323.784 170.941 323.802 171.149 ;
     RECT  2.376 170.339 2.697 171.211 ;
     RECT  186.015 170.465 186.678 171.211 ;
     RECT  196.815 160.445 197.097 171.211 ;
     RECT  207.615 160.445 207.897 171.211 ;
     RECT  218.415 160.445 218.697 171.211 ;
     RECT  229.215 160.445 229.497 171.211 ;
     RECT  240.015 160.439 240.297 171.211 ;
     RECT  261.615 159.917 261.897 171.211 ;
     RECT  272.415 159.917 272.697 171.211 ;
     RECT  283.215 159.917 283.497 171.211 ;
     RECT  294.015 169.763 294.297 171.211 ;
     RECT  304.815 168.557 305.097 171.211 ;
     RECT  315.615 168.557 315.897 171.211 ;
     RECT  139.356 170.429 183.078 171.239 ;
     RECT  249.876 171.085 252.522 171.239 ;
     RECT  326.628 171.005 326.646 171.245 ;
     RECT  322.128 170.843 322.146 171.347 ;
     RECT  290.124 171.049 290.142 171.355 ;
     RECT  140.688 171.239 183.078 171.391 ;
     RECT  139.356 171.239 139.662 171.419 ;
     RECT  140.688 171.391 183.258 171.419 ;
     RECT  254.232 171.113 254.322 171.419 ;
     RECT  286.164 171.319 286.182 171.419 ;
     RECT  0.108 169.003 1.422 171.437 ;
     RECT  183.24 171.419 183.258 171.481 ;
     RECT  183.996 171.149 184.014 171.481 ;
     RECT  324.9 171.005 325.566 171.481 ;
     RECT  251.964 171.239 252.522 171.509 ;
     RECT  327.744 170.815 328.23 171.533 ;
     RECT  324.756 171.481 325.566 171.547 ;
     RECT  183.24 171.481 184.014 171.581 ;
     RECT  290.124 171.355 290.25 171.653 ;
     RECT  185.904 171.211 186.678 171.677 ;
     RECT  196.704 171.211 197.097 171.677 ;
     RECT  207.504 171.211 207.897 171.677 ;
     RECT  218.304 171.211 218.697 171.677 ;
     RECT  229.104 171.211 229.497 171.677 ;
     RECT  239.904 171.211 240.297 171.677 ;
     RECT  13.104 171.115 13.497 171.689 ;
     RECT  23.904 171.115 24.297 171.689 ;
     RECT  34.704 171.115 35.097 171.689 ;
     RECT  45.504 171.115 45.897 171.689 ;
     RECT  56.304 171.115 56.697 171.689 ;
     RECT  67.104 171.115 67.497 171.689 ;
     RECT  77.904 171.115 78.297 171.689 ;
     RECT  88.704 171.115 89.097 171.689 ;
     RECT  99.504 171.115 99.897 171.689 ;
     RECT  110.304 171.115 110.697 171.689 ;
     RECT  121.104 171.115 121.497 171.689 ;
     RECT  131.904 171.115 132.297 171.689 ;
     RECT  261.504 171.211 261.897 171.689 ;
     RECT  272.304 171.211 272.697 171.689 ;
     RECT  283.104 171.211 283.497 171.689 ;
     RECT  293.904 171.211 294.297 171.689 ;
     RECT  304.704 171.211 305.097 171.689 ;
     RECT  315.504 171.211 315.897 171.689 ;
     RECT  2.304 171.211 2.697 171.725 ;
     RECT  130.716 167.261 130.734 171.779 ;
     RECT  249.876 171.239 251.097 171.779 ;
     RECT  251.964 171.509 252.378 171.779 ;
     RECT  183.996 171.581 184.014 171.815 ;
     RECT  251.964 171.779 252.342 171.887 ;
     RECT  258.192 171.787 258.21 171.887 ;
     RECT  254.232 171.419 254.25 171.931 ;
     RECT  328.032 171.533 328.23 172.013 ;
     RECT  2.376 171.725 2.697 172.021 ;
     RECT  254.16 171.931 254.25 172.049 ;
     RECT  290.124 171.653 290.142 172.049 ;
     RECT  324.612 171.547 325.566 172.057 ;
     RECT  2.376 172.021 2.79 172.061 ;
     RECT  140.688 171.419 182.43 172.085 ;
     RECT  254.16 172.049 254.178 172.085 ;
     RECT  140.688 172.085 152.802 172.093 ;
     RECT  153.576 172.085 182.43 172.109 ;
     RECT  161.64 172.109 182.43 172.121 ;
     RECT  138.528 170.717 138.546 172.123 ;
     RECT  139.356 171.419 139.374 172.123 ;
     RECT  324.576 172.057 325.566 172.129 ;
     RECT  182.412 172.121 182.43 172.219 ;
     RECT  0.144 171.437 1.422 172.267 ;
     RECT  161.64 172.121 181.35 172.319 ;
     RECT  182.412 172.219 182.466 172.363 ;
     RECT  153.576 172.109 160.902 172.391 ;
     RECT  179.424 172.319 181.35 172.445 ;
     RECT  182.412 172.363 182.538 172.463 ;
     RECT  324.576 172.129 325.962 172.471 ;
     RECT  153.576 172.391 160.686 172.499 ;
     RECT  182.484 172.463 182.538 172.499 ;
     RECT  138.528 172.123 139.374 172.561 ;
     RECT  140.58 172.093 152.802 172.561 ;
     RECT  162.684 172.319 178.434 172.589 ;
     RECT  253.8 172.471 253.818 172.589 ;
     RECT  324.396 172.471 325.962 172.597 ;
     RECT  138.528 172.561 152.802 172.625 ;
     RECT  177.228 172.589 178.434 172.625 ;
     RECT  138.528 172.625 152.406 172.661 ;
     RECT  177.264 172.625 178.434 172.661 ;
     RECT  182.484 172.499 182.502 172.661 ;
     RECT  286.164 172.561 286.182 172.661 ;
     RECT  138.672 172.661 139.374 172.685 ;
     RECT  162.684 172.589 176.346 172.697 ;
     RECT  328.212 172.013 328.23 172.697 ;
     RECT  324.36 172.597 325.962 172.747 ;
     RECT  0.108 172.267 1.422 172.781 ;
     RECT  2.376 172.061 2.697 172.831 ;
     RECT  13.215 171.689 13.497 172.831 ;
     RECT  24.015 171.689 24.297 172.831 ;
     RECT  34.815 171.689 35.097 172.831 ;
     RECT  45.615 171.689 45.897 172.831 ;
     RECT  56.415 171.689 56.697 172.831 ;
     RECT  67.215 171.689 67.497 172.831 ;
     RECT  78.015 171.689 78.297 172.831 ;
     RECT  88.815 171.689 89.097 172.831 ;
     RECT  99.615 171.689 99.897 172.831 ;
     RECT  110.415 171.689 110.697 172.831 ;
     RECT  121.215 171.689 121.497 172.831 ;
     RECT  132.015 171.689 132.297 172.831 ;
     RECT  140.58 172.661 152.406 172.859 ;
     RECT  153.576 172.499 154.818 172.859 ;
     RECT  162.684 172.697 175.806 172.859 ;
     RECT  177.804 172.661 178.434 172.859 ;
     RECT  179.424 172.445 181.134 172.859 ;
     RECT  2.304 172.831 2.697 172.877 ;
     RECT  13.104 172.831 13.497 172.877 ;
     RECT  23.904 172.831 24.297 172.877 ;
     RECT  34.704 172.831 35.097 172.877 ;
     RECT  45.504 172.831 45.897 172.877 ;
     RECT  56.304 172.831 56.697 172.877 ;
     RECT  67.104 172.831 67.497 172.877 ;
     RECT  77.904 172.831 78.297 172.877 ;
     RECT  88.704 172.831 89.097 172.877 ;
     RECT  99.504 172.831 99.897 172.877 ;
     RECT  110.304 172.831 110.697 172.877 ;
     RECT  121.104 172.831 121.497 172.877 ;
     RECT  131.904 172.831 132.297 172.877 ;
     RECT  140.58 172.859 151.326 172.895 ;
     RECT  172.728 172.859 173.07 172.895 ;
     RECT  178.416 172.859 178.434 173.003 ;
     RECT  180.54 172.859 181.134 173.003 ;
     RECT  155.772 172.499 160.686 173.039 ;
     RECT  179.424 172.859 179.766 173.039 ;
     RECT  179.424 173.039 179.442 173.129 ;
     RECT  180.615 173.003 181.134 173.129 ;
     RECT  140.652 172.895 151.326 173.165 ;
     RECT  173.808 172.859 175.806 173.165 ;
     RECT  161.64 172.319 161.946 173.173 ;
     RECT  152.1 172.859 152.406 173.201 ;
     RECT  162.684 172.859 171.99 173.213 ;
     RECT  174.78 173.165 175.806 173.213 ;
     RECT  324.36 172.747 326.034 173.227 ;
     RECT  140.652 173.165 144.342 173.237 ;
     RECT  155.844 173.039 160.686 173.245 ;
     RECT  161.568 173.173 161.946 173.245 ;
     RECT  140.652 173.237 141.066 173.261 ;
     RECT  141.912 173.237 144.342 173.273 ;
     RECT  145.188 173.165 151.326 173.273 ;
     RECT  186.015 171.677 186.678 173.371 ;
     RECT  196.815 171.677 197.097 173.371 ;
     RECT  207.615 171.677 207.897 173.371 ;
     RECT  218.415 171.677 218.697 173.371 ;
     RECT  229.215 171.677 229.497 173.371 ;
     RECT  240.015 171.677 240.297 173.371 ;
     RECT  250.815 171.779 251.097 173.371 ;
     RECT  261.615 171.689 261.897 173.371 ;
     RECT  272.415 171.689 272.697 173.371 ;
     RECT  283.215 171.689 283.497 173.371 ;
     RECT  294.015 171.689 294.297 173.371 ;
     RECT  304.815 171.689 305.097 173.371 ;
     RECT  315.615 171.689 315.897 173.371 ;
     RECT  324.072 173.227 326.034 173.371 ;
     RECT  152.1 173.201 152.37 173.399 ;
     RECT  155.844 173.245 161.946 173.399 ;
     RECT  185.904 173.371 186.678 173.405 ;
     RECT  196.704 173.371 197.097 173.405 ;
     RECT  207.504 173.371 207.897 173.405 ;
     RECT  218.304 173.371 218.697 173.405 ;
     RECT  229.104 173.371 229.497 173.405 ;
     RECT  239.904 173.371 240.297 173.405 ;
     RECT  250.704 173.371 251.097 173.405 ;
     RECT  261.504 173.371 261.897 173.405 ;
     RECT  272.304 173.371 272.697 173.405 ;
     RECT  283.104 173.371 283.497 173.405 ;
     RECT  293.904 173.371 294.297 173.405 ;
     RECT  304.704 173.371 305.097 173.405 ;
     RECT  315.504 173.371 315.897 173.405 ;
     RECT  328.14 173.371 328.158 173.419 ;
     RECT  141.912 173.273 144.018 173.435 ;
     RECT  145.188 173.273 146.43 173.471 ;
     RECT  328.14 173.419 328.23 173.549 ;
     RECT  323.892 173.371 326.034 173.551 ;
     RECT  141.912 173.435 143.586 173.579 ;
     RECT  174.78 173.213 175.497 173.579 ;
     RECT  323.604 173.551 326.034 173.597 ;
     RECT  145.188 173.471 145.998 173.669 ;
     RECT  147.276 173.273 151.326 173.669 ;
     RECT  155.844 173.399 161.046 173.669 ;
     RECT  0.144 172.781 1.422 173.677 ;
     RECT  161.928 173.399 161.946 173.677 ;
     RECT  162.684 173.213 170.838 173.677 ;
     RECT  152.1 173.399 152.226 173.705 ;
     RECT  145.188 173.669 145.746 173.741 ;
     RECT  152.208 173.705 152.226 173.741 ;
     RECT  2.376 172.877 2.697 173.749 ;
     RECT  61.815 2.413 62.097 173.749 ;
     RECT  153.615 172.859 154.818 173.749 ;
     RECT  145.188 173.741 145.206 173.777 ;
     RECT  13.215 172.877 13.497 173.803 ;
     RECT  24.015 172.877 24.297 173.803 ;
     RECT  34.815 172.877 35.097 173.803 ;
     RECT  45.615 172.877 45.897 173.803 ;
     RECT  56.415 172.877 56.697 173.803 ;
     RECT  67.215 172.877 67.497 173.803 ;
     RECT  78.015 172.877 78.297 173.803 ;
     RECT  88.815 172.877 89.097 173.803 ;
     RECT  99.615 172.877 99.897 173.803 ;
     RECT  110.415 172.877 110.697 173.803 ;
     RECT  121.215 172.877 121.497 173.803 ;
     RECT  132.015 172.877 132.297 173.803 ;
     RECT  141.912 173.579 143.097 173.837 ;
     RECT  323.604 173.597 325.854 173.837 ;
     RECT  2.268 173.749 2.862 173.849 ;
     RECT  10.836 173.749 10.854 173.849 ;
     RECT  13.104 173.803 13.497 173.849 ;
     RECT  22.824 173.749 22.842 173.849 ;
     RECT  23.904 173.803 24.297 173.849 ;
     RECT  30.78 173.749 30.798 173.849 ;
     RECT  34.704 173.803 35.097 173.849 ;
     RECT  42.768 173.749 42.786 173.849 ;
     RECT  45.504 173.803 45.897 173.849 ;
     RECT  54.72 173.749 54.738 173.849 ;
     RECT  56.304 173.803 56.697 173.849 ;
     RECT  61.815 173.749 62.73 173.849 ;
     RECT  67.104 173.803 67.497 173.849 ;
     RECT  74.664 173.749 74.682 173.849 ;
     RECT  77.904 173.803 78.297 173.849 ;
     RECT  86.652 173.749 86.67 173.849 ;
     RECT  88.704 173.803 89.097 173.849 ;
     RECT  98.604 173.749 98.622 173.849 ;
     RECT  99.504 173.803 99.897 173.849 ;
     RECT  106.596 173.749 106.614 173.849 ;
     RECT  110.304 173.803 110.697 173.849 ;
     RECT  118.584 173.749 118.602 173.849 ;
     RECT  121.104 173.803 121.497 173.849 ;
     RECT  130.536 173.749 130.554 173.849 ;
     RECT  131.904 173.803 132.297 173.849 ;
     RECT  147.276 173.669 147.294 173.849 ;
     RECT  148.176 173.669 151.326 173.849 ;
     RECT  155.844 173.669 160.686 173.939 ;
     RECT  172.728 172.895 172.746 173.939 ;
     RECT  171.612 173.213 171.99 173.947 ;
     RECT  171.612 173.947 172.674 173.981 ;
     RECT  173.808 173.165 173.826 174.011 ;
     RECT  148.215 173.849 151.326 174.029 ;
     RECT  161.928 173.677 170.838 174.047 ;
     RECT  328.14 173.549 328.158 174.055 ;
     RECT  148.215 174.029 150.354 174.083 ;
     RECT  151.308 174.029 151.326 174.083 ;
     RECT  141.048 173.261 141.066 174.119 ;
     RECT  148.215 174.083 149.418 174.119 ;
     RECT  153.324 173.749 154.818 174.119 ;
     RECT  149.4 174.119 149.418 174.209 ;
     RECT  171.612 173.981 171.99 174.245 ;
     RECT  155.844 173.939 160.614 174.253 ;
     RECT  141.912 173.837 142.038 174.281 ;
     RECT  322.056 174.091 322.074 174.317 ;
     RECT  327.744 174.055 328.158 174.317 ;
     RECT  0.108 173.677 1.422 174.325 ;
     RECT  2.268 173.849 2.697 174.325 ;
     RECT  151.38 174.091 151.398 174.365 ;
     RECT  139.356 172.685 139.374 174.389 ;
     RECT  142.02 174.281 142.038 174.389 ;
     RECT  171.612 174.245 171.63 174.389 ;
     RECT  162.684 174.047 170.838 174.413 ;
     RECT  153.615 174.119 154.818 174.451 ;
     RECT  155.556 174.253 160.614 174.451 ;
     RECT  327.132 174.475 327.186 174.551 ;
     RECT  0.108 174.325 2.697 174.595 ;
     RECT  0.108 174.595 2.79 174.605 ;
     RECT  323.748 173.837 325.854 174.631 ;
     RECT  2.376 174.605 2.79 174.653 ;
     RECT  0.108 174.605 1.422 174.659 ;
     RECT  242.928 174.811 242.946 174.901 ;
     RECT  242.748 174.901 242.946 174.991 ;
     RECT  241.704 171.661 241.722 175.027 ;
     RECT  242.748 174.991 243.45 175.027 ;
     RECT  323.388 174.631 325.926 175.027 ;
     RECT  162.9 174.413 170.838 175.051 ;
     RECT  241.704 175.027 243.45 175.055 ;
     RECT  242.244 175.055 243.45 175.063 ;
     RECT  242.244 175.063 243.558 175.091 ;
     RECT  327.168 174.551 327.186 175.091 ;
     RECT  328.14 174.317 328.158 175.099 ;
     RECT  162.9 175.051 171.234 175.135 ;
     RECT  243.54 175.091 243.558 175.163 ;
     RECT  162.9 175.135 171.594 175.171 ;
     RECT  242.244 175.091 242.262 175.199 ;
     RECT  323.388 175.027 325.998 175.243 ;
     RECT  2.376 174.653 2.697 175.289 ;
     RECT  162.9 175.171 171.954 175.289 ;
     RECT  323.388 175.243 326.034 175.289 ;
     RECT  285.84 175.171 285.858 175.325 ;
     RECT  153.615 174.451 160.614 175.361 ;
     RECT  171.936 175.289 171.954 175.361 ;
     RECT  319.86 175.261 319.878 175.373 ;
     RECT  327.204 175.099 328.158 175.373 ;
     RECT  282.168 175.063 282.186 175.397 ;
     RECT  323.388 175.289 325.998 175.397 ;
     RECT  2.415 175.289 2.697 175.441 ;
     RECT  3.672 170.437 3.69 175.441 ;
     RECT  153.615 175.361 159.297 175.441 ;
     RECT  322.236 174.991 322.254 175.441 ;
     RECT  323.388 175.397 325.962 175.441 ;
     RECT  2.415 175.441 3.69 175.469 ;
     RECT  162.9 175.289 171.126 175.469 ;
     RECT  165.816 175.469 171.126 175.559 ;
     RECT  322.236 175.441 325.962 175.559 ;
     RECT  167.256 175.559 171.126 175.565 ;
     RECT  162.9 175.469 164.697 175.595 ;
     RECT  153.144 175.441 159.297 175.675 ;
     RECT  322.236 175.559 325.926 175.675 ;
     RECT  167.256 175.565 171.018 175.709 ;
     RECT  319.536 175.441 319.554 175.801 ;
     RECT  167.256 175.709 168.066 175.829 ;
     RECT  172.188 175.531 172.314 175.829 ;
     RECT  322.092 175.675 325.926 175.865 ;
     RECT  322.092 175.865 325.89 175.867 ;
     RECT  167.256 175.829 167.922 175.901 ;
     RECT  319.428 175.801 319.554 175.901 ;
     RECT  249.876 171.779 249.894 175.915 ;
     RECT  250.815 173.405 251.097 175.915 ;
     RECT  0.108 174.659 0.846 175.937 ;
     RECT  167.256 175.901 167.274 175.937 ;
     RECT  327.204 175.373 327.222 175.949 ;
     RECT  172.188 175.829 172.206 175.973 ;
     RECT  328.14 175.373 328.158 175.981 ;
     RECT  165.816 175.559 166.482 176.009 ;
     RECT  318.06 175.873 318.078 176.009 ;
     RECT  153 175.675 159.297 176.099 ;
     RECT  169.092 175.709 171.018 176.099 ;
     RECT  249.12 167.189 249.138 176.155 ;
     RECT  249.876 175.915 251.097 176.155 ;
     RECT  169.092 176.099 170.91 176.189 ;
     RECT  288.615 163.445 288.897 176.215 ;
     RECT  328.14 175.981 328.23 176.299 ;
     RECT  249.12 176.155 251.097 176.341 ;
     RECT  153.468 176.099 159.297 176.369 ;
     RECT  248.832 176.341 251.097 176.369 ;
     RECT  169.815 176.189 170.19 176.381 ;
     RECT  165.816 176.009 166.158 176.405 ;
     RECT  288.615 176.215 289.314 176.405 ;
     RECT  248.832 176.369 249.894 176.429 ;
     RECT  328.032 176.299 328.23 176.429 ;
     RECT  248.832 176.429 249.138 176.485 ;
     RECT  288.615 176.405 288.897 176.491 ;
     RECT  165.816 176.405 165.834 176.549 ;
     RECT  288.504 176.491 288.897 176.611 ;
     RECT  0.144 175.937 0.846 176.639 ;
     RECT  0.144 176.639 0.306 176.683 ;
     RECT  321.015 2.413 321.297 176.755 ;
     RECT  322.056 175.867 325.89 176.755 ;
     RECT  248.688 176.485 249.138 176.783 ;
     RECT  288.432 176.611 288.897 176.783 ;
     RECT  328.212 176.429 328.23 176.819 ;
     RECT  245.415 163.589 245.754 176.981 ;
     RECT  321.015 176.755 325.89 177.061 ;
     RECT  321.015 177.061 325.962 177.251 ;
     RECT  0.036 176.683 0.306 177.359 ;
     RECT  153.576 176.369 159.297 177.451 ;
     RECT  150.552 177.331 150.57 177.691 ;
     RECT  0.288 177.359 0.306 177.719 ;
     RECT  150.48 177.691 150.57 177.719 ;
     RECT  150.48 177.719 150.498 177.791 ;
     RECT  322.272 177.251 325.962 177.799 ;
     RECT  153.396 177.451 159.297 178.105 ;
     RECT  160.092 175.361 160.614 178.105 ;
     RECT  249.12 176.783 249.138 178.133 ;
     RECT  321.015 177.251 321.297 178.363 ;
     RECT  322.272 177.799 326.034 178.363 ;
     RECT  321.015 178.363 326.034 178.375 ;
     RECT  321.015 178.375 326.07 178.403 ;
     RECT  322.128 178.403 326.07 178.411 ;
     RECT  161.928 174.047 161.946 178.681 ;
     RECT  247.176 161.405 247.194 178.709 ;
     RECT  153.396 178.105 160.614 178.943 ;
     RECT  321.015 178.403 321.297 179.689 ;
     RECT  321.015 179.689 321.39 179.761 ;
     RECT  322.128 178.411 326.142 179.761 ;
     RECT  153.54 178.943 160.614 179.987 ;
     RECT  321.015 179.761 326.142 180.077 ;
     RECT  321.015 180.077 321.39 180.125 ;
     RECT  155.7 179.987 160.614 180.149 ;
     RECT  162.9 175.595 163.53 180.391 ;
     RECT  249.876 176.429 249.894 180.419 ;
     RECT  322.236 180.077 326.142 180.841 ;
     RECT  252.324 171.887 252.342 180.995 ;
     RECT  322.2 180.841 326.142 181.111 ;
     RECT  321.015 180.125 321.297 181.195 ;
     RECT  322.056 181.111 326.142 181.195 ;
     RECT  153.54 179.987 154.854 181.237 ;
     RECT  155.88 180.149 160.614 181.237 ;
     RECT  2.415 175.469 3.222 181.679 ;
     RECT  81.684 181.651 81.702 181.769 ;
     RECT  165.636 181.723 165.654 181.771 ;
     RECT  291.348 181.381 291.366 181.777 ;
     RECT  291.276 181.777 291.366 181.805 ;
     RECT  82.656 181.741 82.674 181.841 ;
     RECT  165.636 181.771 165.87 181.949 ;
     RECT  291.276 181.805 291.294 181.949 ;
     RECT  161.388 178.681 161.946 182.119 ;
     RECT  165.636 181.949 165.654 182.189 ;
     RECT  153.504 181.237 160.614 182.191 ;
     RECT  161.352 182.119 161.946 182.191 ;
     RECT  186.015 173.405 186.678 182.219 ;
     RECT  202.215 2.413 202.497 182.281 ;
     RECT  102.6 182.191 102.618 182.317 ;
     RECT  103.68 182.191 103.698 182.317 ;
     RECT  153.504 182.191 161.946 182.317 ;
     RECT  162.684 180.391 163.53 182.317 ;
     RECT  202.215 182.281 203.022 182.333 ;
     RECT  153.504 182.317 163.53 182.345 ;
     RECT  102.564 182.317 103.698 182.347 ;
     RECT  202.215 182.333 202.698 182.381 ;
     RECT  110.415 173.849 110.697 182.461 ;
     RECT  207.615 173.405 207.897 182.539 ;
     RECT  209.808 182.461 209.826 182.621 ;
     RECT  328.212 182.587 328.23 182.623 ;
     RECT  155.88 182.345 163.53 182.635 ;
     RECT  164.415 175.595 164.697 182.635 ;
     RECT  110.415 182.461 111.222 182.659 ;
     RECT  112.212 182.461 112.23 182.659 ;
     RECT  0.54 182.659 0.558 182.683 ;
     RECT  102.528 182.347 103.698 182.695 ;
     RECT  0.18 182.683 0.558 182.731 ;
     RECT  2.415 181.679 2.697 182.731 ;
     RECT  3.636 182.659 3.654 182.731 ;
     RECT  110.415 182.659 112.23 182.731 ;
     RECT  0.108 182.731 0.558 182.765 ;
     RECT  102.348 182.695 103.698 182.821 ;
     RECT  327.78 182.623 328.23 182.857 ;
     RECT  81.792 182.821 81.81 182.861 ;
     RECT  155.88 182.635 164.697 182.861 ;
     RECT  155.88 182.861 163.458 182.885 ;
     RECT  2.415 182.731 3.654 182.921 ;
     RECT  102.348 182.821 103.806 182.929 ;
     RECT  110.415 182.731 112.266 182.929 ;
     RECT  156.024 182.885 163.458 182.957 ;
     RECT  327.744 182.857 328.23 182.957 ;
     RECT  99.615 173.849 99.897 182.971 ;
     RECT  98.28 181.741 98.298 183.001 ;
     RECT  101.16 182.923 101.178 183.001 ;
     RECT  101.916 182.929 103.806 183.001 ;
     RECT  105.015 2.413 105.297 183.091 ;
     RECT  110.232 182.929 112.266 183.091 ;
     RECT  98.28 183.001 98.622 183.119 ;
     RECT  126.615 2.413 126.897 183.127 ;
     RECT  96.624 182.929 96.642 183.163 ;
     RECT  101.16 183.001 103.806 183.163 ;
     RECT  81.612 182.929 81.63 183.197 ;
     RECT  96.624 183.163 97.074 183.199 ;
     RECT  99.615 182.971 100.062 183.199 ;
     RECT  101.16 183.163 104.202 183.199 ;
     RECT  126.504 183.127 126.897 183.199 ;
     RECT  105.015 183.091 105.462 183.211 ;
     RECT  99.615 183.199 100.17 183.235 ;
     RECT  100.98 183.199 104.202 183.235 ;
     RECT  110.016 183.091 112.266 183.235 ;
     RECT  126.432 183.199 126.897 183.235 ;
     RECT  327.78 182.957 328.23 183.245 ;
     RECT  164.376 182.861 164.697 183.263 ;
     RECT  96.624 183.199 97.83 183.271 ;
     RECT  99.576 183.235 104.202 183.271 ;
     RECT  104.94 183.211 105.462 183.271 ;
     RECT  126.432 183.235 127.35 183.271 ;
     RECT  207.504 182.539 207.897 183.271 ;
     RECT  0.144 182.765 0.558 183.341 ;
     RECT  83.415 2.413 83.697 183.361 ;
     RECT  2.415 182.921 3.582 183.389 ;
     RECT  95.94 183.271 97.83 183.389 ;
     RECT  126.216 183.271 127.35 183.389 ;
     RECT  2.415 183.389 3.51 183.397 ;
     RECT  107.388 183.271 107.406 183.397 ;
     RECT  109.404 183.235 112.266 183.397 ;
     RECT  126.216 183.389 127.314 183.397 ;
     RECT  2.34 183.397 3.51 183.403 ;
     RECT  108.252 183.397 108.27 183.433 ;
     RECT  109.404 183.397 112.59 183.433 ;
     RECT  2.304 183.403 3.51 183.437 ;
     RECT  108.252 183.433 108.306 183.451 ;
     RECT  109.404 183.433 112.77 183.451 ;
     RECT  321.015 181.195 326.142 183.461 ;
     RECT  122.328 183.361 122.346 183.505 ;
     RECT  82.764 183.361 83.697 183.533 ;
     RECT  107.388 183.397 107.514 183.541 ;
     RECT  108.252 183.451 112.77 183.541 ;
     RECT  126.072 183.397 127.314 183.541 ;
     RECT  2.304 183.437 3.186 183.595 ;
     RECT  13.215 173.849 13.497 183.631 ;
     RECT  24.015 173.849 24.297 183.631 ;
     RECT  34.815 173.849 35.097 183.631 ;
     RECT  45.615 173.849 45.897 183.631 ;
     RECT  56.415 173.849 56.697 183.631 ;
     RECT  67.215 173.849 67.497 183.631 ;
     RECT  78.015 173.849 78.297 183.631 ;
     RECT  2.268 183.595 3.186 183.677 ;
     RECT  13.104 183.631 13.497 183.677 ;
     RECT  23.904 183.631 24.297 183.677 ;
     RECT  34.704 183.631 35.097 183.677 ;
     RECT  45.504 183.631 45.897 183.677 ;
     RECT  56.304 183.631 56.697 183.677 ;
     RECT  67.104 183.631 67.497 183.677 ;
     RECT  77.904 183.631 78.297 183.677 ;
     RECT  0.18 183.341 0.558 183.691 ;
     RECT  98.604 183.119 98.622 183.691 ;
     RECT  99.576 183.271 105.498 183.691 ;
     RECT  153.504 182.345 155.07 183.691 ;
     RECT  156.132 182.957 163.458 183.691 ;
     RECT  98.604 183.691 105.498 183.703 ;
     RECT  106.56 183.703 106.578 183.739 ;
     RECT  107.388 183.541 113.094 183.739 ;
     RECT  121.215 173.849 121.497 183.739 ;
     RECT  122.292 183.505 122.346 183.739 ;
     RECT  98.604 183.703 105.606 183.775 ;
     RECT  106.56 183.739 113.094 183.775 ;
     RECT  121.215 183.739 122.346 183.775 ;
     RECT  123.3 183.541 123.318 183.775 ;
     RECT  124.092 183.739 124.11 183.775 ;
     RECT  125.928 183.541 127.314 183.775 ;
     RECT  78.015 183.677 78.297 183.787 ;
     RECT  83.415 183.533 83.697 183.787 ;
     RECT  120.276 183.775 120.294 183.811 ;
     RECT  121.215 183.775 122.382 183.811 ;
     RECT  123.156 183.775 124.11 183.811 ;
     RECT  125.028 183.775 127.314 183.811 ;
     RECT  321.015 183.461 325.89 183.811 ;
     RECT  0.18 183.691 0.666 183.821 ;
     RECT  94.215 2.413 94.497 183.883 ;
     RECT  81.504 183.739 81.522 183.901 ;
     RECT  95.796 183.469 95.814 183.901 ;
     RECT  119.952 183.811 122.382 183.901 ;
     RECT  81.144 183.901 81.522 183.929 ;
     RECT  82.332 183.643 82.35 183.929 ;
     RECT  119.232 183.901 122.382 183.931 ;
     RECT  123.156 183.811 127.314 183.931 ;
     RECT  119.232 183.931 127.314 183.973 ;
     RECT  78.015 183.787 78.678 184.013 ;
     RECT  81.144 183.929 81.162 184.013 ;
     RECT  83.415 183.787 83.754 184.013 ;
     RECT  95.508 183.901 95.814 184.045 ;
     RECT  98.604 183.775 113.094 184.045 ;
     RECT  153.504 183.691 163.458 184.045 ;
     RECT  164.415 183.263 164.697 184.045 ;
     RECT  88.815 173.849 89.097 184.075 ;
     RECT  96.588 183.389 97.83 184.075 ;
     RECT  98.568 184.045 113.094 184.075 ;
     RECT  82.152 184.075 82.17 184.109 ;
     RECT  119.016 183.973 127.314 184.109 ;
     RECT  203.436 183.541 203.454 184.199 ;
     RECT  2.268 183.677 2.754 184.205 ;
     RECT  88.704 184.075 89.097 184.205 ;
     RECT  206.928 183.271 207.897 184.207 ;
     RECT  0.18 183.821 0.558 184.219 ;
     RECT  119.016 184.109 126.99 184.235 ;
     RECT  96.588 184.075 113.094 184.243 ;
     RECT  119.016 184.235 126.954 184.243 ;
     RECT  86.616 184.171 86.634 184.301 ;
     RECT  206.316 184.207 207.897 184.307 ;
     RECT  114.984 182.893 115.002 184.315 ;
     RECT  148.215 174.119 148.497 184.315 ;
     RECT  150.444 184.279 150.462 184.315 ;
     RECT  320.544 183.811 325.89 184.315 ;
     RECT  95.472 184.045 95.814 184.351 ;
     RECT  96.588 184.243 113.418 184.351 ;
     RECT  114.984 184.315 115.038 184.351 ;
     RECT  146.484 184.279 146.502 184.351 ;
     RECT  200.088 184.081 200.106 184.351 ;
     RECT  320.508 184.315 325.89 184.351 ;
     RECT  328.032 183.245 328.23 184.351 ;
     RECT  146.484 184.351 146.574 184.379 ;
     RECT  201.204 184.267 201.222 184.379 ;
     RECT  114.948 184.351 115.038 184.441 ;
     RECT  115.815 2.413 116.097 184.441 ;
     RECT  200.088 184.351 200.142 184.469 ;
     RECT  264.816 184.243 264.834 184.469 ;
     RECT  265.896 184.207 265.914 184.469 ;
     RECT  320.328 184.351 325.89 184.469 ;
     RECT  148.215 184.315 149.202 184.477 ;
     RECT  150.336 184.315 150.462 184.477 ;
     RECT  114.948 184.441 116.097 184.549 ;
     RECT  148.215 184.477 150.462 184.549 ;
     RECT  2.304 184.205 2.754 184.585 ;
     RECT  3.492 184.351 3.51 184.585 ;
     RECT  114.768 184.549 116.298 184.585 ;
     RECT  152.64 184.555 152.658 184.585 ;
     RECT  153.504 184.045 164.697 184.585 ;
     RECT  320.472 184.469 325.89 184.585 ;
     RECT  95.4 184.351 113.418 184.613 ;
     RECT  114.372 184.585 116.298 184.621 ;
     RECT  200.088 184.469 200.106 184.621 ;
     RECT  95.796 184.613 113.418 184.649 ;
     RECT  146.556 184.379 146.574 184.649 ;
     RECT  199.836 184.621 200.106 184.649 ;
     RECT  264.636 184.477 264.654 184.649 ;
     RECT  296.82 184.555 296.838 184.651 ;
     RECT  299.415 2.413 299.697 184.651 ;
     RECT  304.815 173.405 305.097 184.651 ;
     RECT  310.215 160.709 310.497 184.651 ;
     RECT  315.615 173.405 315.897 184.651 ;
     RECT  96.372 184.649 113.418 184.711 ;
     RECT  114.3 184.621 116.298 184.711 ;
     RECT  2.304 184.585 3.51 184.739 ;
     RECT  299.304 184.651 299.697 184.739 ;
     RECT  304.704 184.651 305.097 184.739 ;
     RECT  310.104 184.651 310.497 184.739 ;
     RECT  315.504 184.651 315.897 184.739 ;
     RECT  83.415 184.013 83.697 184.747 ;
     RECT  296.208 184.651 296.838 184.775 ;
     RECT  0.144 184.219 0.558 184.781 ;
     RECT  199.836 184.649 199.854 184.781 ;
     RECT  264.204 184.711 264.222 184.781 ;
     RECT  96.372 184.711 116.298 184.783 ;
     RECT  117.54 184.081 117.558 184.783 ;
     RECT  96.372 184.783 116.802 184.819 ;
     RECT  117.54 184.783 117.666 184.819 ;
     RECT  151.344 184.747 151.362 184.819 ;
     RECT  267.015 2.413 267.297 184.819 ;
     RECT  266.508 184.819 267.297 184.843 ;
     RECT  318.096 184.711 318.114 184.843 ;
     RECT  327.744 184.351 328.23 184.843 ;
     RECT  148.215 184.549 150.498 184.855 ;
     RECT  151.344 184.819 151.434 184.855 ;
     RECT  96.372 184.819 117.738 184.891 ;
     RECT  265.464 184.819 265.554 184.919 ;
     RECT  0.144 184.781 0.522 184.973 ;
     RECT  327.636 184.843 328.23 184.973 ;
     RECT  261.615 173.405 261.897 185.017 ;
     RECT  96.372 184.891 117.81 185.035 ;
     RECT  266.508 184.843 267.39 185.045 ;
     RECT  2.415 184.739 3.51 185.069 ;
     RECT  3.42 185.069 3.51 185.081 ;
     RECT  205.056 184.981 205.074 185.081 ;
     RECT  94.215 183.883 94.662 185.083 ;
     RECT  210.312 184.987 210.33 185.117 ;
     RECT  148.215 184.855 151.434 185.125 ;
     RECT  297.936 184.891 297.954 185.131 ;
     RECT  83.232 184.747 83.697 185.161 ;
     RECT  94.215 185.083 94.734 185.213 ;
     RECT  148.176 185.125 151.434 185.227 ;
     RECT  152.64 184.585 164.697 185.227 ;
     RECT  96.372 185.035 117.882 185.251 ;
     RECT  118.836 184.243 126.954 185.251 ;
     RECT  148.176 185.227 164.697 185.251 ;
     RECT  206.352 184.307 207.897 185.251 ;
     RECT  82.764 185.161 83.697 185.261 ;
     RECT  327.708 184.973 328.23 185.261 ;
     RECT  0.144 184.973 0.198 185.287 ;
     RECT  118.836 185.251 127.35 185.287 ;
     RECT  247.392 185.275 247.41 185.287 ;
     RECT  297.684 185.131 297.954 185.287 ;
     RECT  319.32 185.227 319.338 185.287 ;
     RECT  320.472 184.585 326.034 185.287 ;
     RECT  247.14 185.287 247.41 185.315 ;
     RECT  265.212 185.251 265.374 185.315 ;
     RECT  96.372 185.251 118.062 185.323 ;
     RECT  118.836 185.287 127.422 185.323 ;
     RECT  202.215 182.381 202.497 185.323 ;
     RECT  261.615 185.017 262.242 185.323 ;
     RECT  318.06 184.843 318.114 185.323 ;
     RECT  202.14 185.323 202.497 185.357 ;
     RECT  265.356 185.315 265.374 185.357 ;
     RECT  206.316 185.251 207.897 185.359 ;
     RECT  317.376 185.323 318.114 185.395 ;
     RECT  3.96 185.161 3.978 185.405 ;
     RECT  205.74 185.359 207.897 185.405 ;
     RECT  96.372 185.323 127.458 185.431 ;
     RECT  147.456 185.251 164.697 185.431 ;
     RECT  294.015 173.405 294.297 185.431 ;
     RECT  297.684 185.287 297.99 185.431 ;
     RECT  319.32 185.287 326.034 185.431 ;
     RECT  198.432 185.359 198.45 185.459 ;
     RECT  199.512 185.323 199.53 185.459 ;
     RECT  203.436 185.359 203.454 185.459 ;
     RECT  204.624 185.371 204.642 185.459 ;
     RECT  261.615 185.323 262.314 185.459 ;
     RECT  297.504 185.431 297.99 185.459 ;
     RECT  0.108 185.287 0.198 185.549 ;
     RECT  82.44 185.371 82.458 185.549 ;
     RECT  147.312 185.431 164.697 185.549 ;
     RECT  214.38 185.431 214.398 185.549 ;
     RECT  294.015 185.431 294.354 185.549 ;
     RECT  297.504 185.459 297.522 185.549 ;
     RECT  204.3 185.521 204.318 185.557 ;
     RECT  317.376 185.395 318.15 185.585 ;
     RECT  0.18 185.549 0.198 185.597 ;
     RECT  203.976 185.557 204.318 185.597 ;
     RECT  218.415 173.405 218.697 185.611 ;
     RECT  147.312 185.549 151.038 185.621 ;
     RECT  247.14 185.315 247.158 185.621 ;
     RECT  218.232 185.611 218.697 185.657 ;
     RECT  261.615 185.459 262.242 185.657 ;
     RECT  318.06 185.585 318.15 185.657 ;
     RECT  82.26 185.659 82.278 185.693 ;
     RECT  327.996 185.261 328.23 185.693 ;
     RECT  222.264 185.431 222.282 185.729 ;
     RECT  266.184 185.431 266.274 185.729 ;
     RECT  328.068 185.693 328.23 185.741 ;
     RECT  254.556 185.395 254.574 185.819 ;
     RECT  318.06 185.657 318.078 185.819 ;
     RECT  319.212 185.431 326.034 185.819 ;
     RECT  147.312 185.621 150.714 185.837 ;
     RECT  96.336 185.431 127.458 185.851 ;
     RECT  204.048 185.597 204.318 185.855 ;
     RECT  96.3 185.851 127.458 185.899 ;
     RECT  96.3 185.899 127.53 185.933 ;
     RECT  204.3 185.855 204.318 185.999 ;
     RECT  142.815 173.837 143.097 186.091 ;
     RECT  96.3 185.933 127.35 186.097 ;
     RECT  267.015 185.045 267.39 186.125 ;
     RECT  328.104 185.741 328.23 186.173 ;
     RECT  138.528 186.091 138.546 186.187 ;
     RECT  266.184 185.729 266.202 186.197 ;
     RECT  95.94 186.097 127.35 186.221 ;
     RECT  142.815 186.091 143.442 186.221 ;
     RECT  206.46 185.405 207.897 186.221 ;
     RECT  24.015 183.677 24.297 186.241 ;
     RECT  95.94 186.221 127.242 186.269 ;
     RECT  286.164 186.241 286.506 186.317 ;
     RECT  88.815 184.205 89.097 186.331 ;
     RECT  132.015 173.849 132.297 186.331 ;
     RECT  175.215 173.579 175.497 186.331 ;
     RECT  186.015 182.219 186.297 186.331 ;
     RECT  196.815 173.405 197.097 186.331 ;
     RECT  229.215 173.405 229.497 186.331 ;
     RECT  240.015 173.405 240.297 186.331 ;
     RECT  250.815 176.369 251.097 186.331 ;
     RECT  261.615 185.657 261.897 186.331 ;
     RECT  272.415 173.405 272.697 186.331 ;
     RECT  283.215 173.405 283.497 186.331 ;
     RECT  24.015 186.241 25.002 186.359 ;
     RECT  86.616 186.187 86.634 186.365 ;
     RECT  138.528 186.187 138.654 186.365 ;
     RECT  207.504 186.221 207.897 186.365 ;
     RECT  218.304 185.657 218.697 186.365 ;
     RECT  229.104 186.331 229.497 186.365 ;
     RECT  239.904 186.331 240.297 186.365 ;
     RECT  250.704 186.331 251.097 186.365 ;
     RECT  261.504 186.331 261.897 186.365 ;
     RECT  272.304 186.331 272.697 186.365 ;
     RECT  283.104 186.331 283.497 186.365 ;
     RECT  286.488 186.317 286.506 186.365 ;
     RECT  151.776 185.549 164.697 186.395 ;
     RECT  327.168 185.803 327.186 186.403 ;
     RECT  83.415 185.261 83.697 186.427 ;
     RECT  0.54 185.971 0.558 186.439 ;
     RECT  94.215 185.213 94.497 186.439 ;
     RECT  327.096 186.403 327.186 186.461 ;
     RECT  319.212 185.819 325.962 186.475 ;
     RECT  95.94 186.269 126.897 186.503 ;
     RECT  146.484 185.431 146.502 186.511 ;
     RECT  147.312 185.837 150.678 186.511 ;
     RECT  151.776 186.395 161.046 186.511 ;
     RECT  151.704 186.511 161.046 186.557 ;
     RECT  82.764 186.427 83.697 186.629 ;
     RECT  97.452 186.503 126.897 186.629 ;
     RECT  206.46 186.221 206.478 186.637 ;
     RECT  83.232 186.629 83.697 186.653 ;
     RECT  96.156 186.503 96.318 186.653 ;
     RECT  97.668 186.629 126.897 186.665 ;
     RECT  319.068 186.475 325.962 186.665 ;
     RECT  318.06 186.637 318.078 186.673 ;
     RECT  151.776 186.557 161.046 186.701 ;
     RECT  203.472 186.601 203.49 186.701 ;
     RECT  327.168 186.461 327.186 186.701 ;
     RECT  161.856 186.395 164.697 186.709 ;
     RECT  169.815 176.381 170.097 186.709 ;
     RECT  206.316 186.637 206.478 186.737 ;
     RECT  318.06 186.673 318.15 186.745 ;
     RECT  319.068 186.665 325.818 186.745 ;
     RECT  13.215 183.677 13.497 186.763 ;
     RECT  24.015 186.359 24.57 186.763 ;
     RECT  34.815 183.677 35.097 186.763 ;
     RECT  45.615 183.677 45.897 186.763 ;
     RECT  56.415 183.677 56.697 186.763 ;
     RECT  67.215 183.677 67.497 186.763 ;
     RECT  78.015 184.013 78.297 186.763 ;
     RECT  142.815 186.221 143.097 186.763 ;
     RECT  98.388 186.665 126.897 186.773 ;
     RECT  3.744 186.619 3.762 186.781 ;
     RECT  299.415 184.739 299.697 186.781 ;
     RECT  198.36 186.667 198.378 186.797 ;
     RECT  13.104 186.763 13.497 186.809 ;
     RECT  23.904 186.763 24.57 186.809 ;
     RECT  34.704 186.763 35.097 186.809 ;
     RECT  45.504 186.763 45.897 186.809 ;
     RECT  56.304 186.763 56.697 186.809 ;
     RECT  67.104 186.763 67.497 186.809 ;
     RECT  77.904 186.763 78.297 186.809 ;
     RECT  88.704 186.331 89.097 186.809 ;
     RECT  131.904 186.331 132.297 186.809 ;
     RECT  138.528 186.365 138.546 186.809 ;
     RECT  142.704 186.763 143.097 186.809 ;
     RECT  146.484 186.511 150.678 186.809 ;
     RECT  152.424 186.701 161.046 186.809 ;
     RECT  161.856 186.709 164.754 186.809 ;
     RECT  169.815 186.709 170.442 186.809 ;
     RECT  175.104 186.331 175.497 186.809 ;
     RECT  182.412 186.709 182.43 186.809 ;
     RECT  185.904 186.331 186.297 186.809 ;
     RECT  194.364 186.709 194.382 186.809 ;
     RECT  196.704 186.331 197.097 186.809 ;
     RECT  152.46 186.809 161.046 186.899 ;
     RECT  251.964 186.619 251.982 186.899 ;
     RECT  0.504 186.439 0.558 186.907 ;
     RECT  24.015 186.809 24.57 186.935 ;
     RECT  317.016 186.871 317.25 186.941 ;
     RECT  328.176 186.173 328.23 186.943 ;
     RECT  317.232 186.941 317.25 186.971 ;
     RECT  327.996 186.943 328.23 187.037 ;
     RECT  299.304 186.781 299.697 187.043 ;
     RECT  315.615 184.739 315.897 187.051 ;
     RECT  24.015 186.935 24.498 187.079 ;
     RECT  206.46 186.737 206.478 187.141 ;
     RECT  96.3 186.653 96.318 187.169 ;
     RECT  98.388 186.773 113.598 187.169 ;
     RECT  206.46 187.141 206.802 187.169 ;
     RECT  130.536 186.709 130.554 187.177 ;
     RECT  0.144 186.907 0.558 187.181 ;
     RECT  152.496 186.899 161.046 187.195 ;
     RECT  161.856 186.809 164.697 187.195 ;
     RECT  239.976 186.365 240.297 187.213 ;
     RECT  2.415 185.069 2.697 187.243 ;
     RECT  135.252 187.177 135.27 187.243 ;
     RECT  3.744 186.781 3.87 187.249 ;
     RECT  130.536 187.177 130.59 187.249 ;
     RECT  294.015 185.549 294.297 187.249 ;
     RECT  130.536 187.249 130.662 187.277 ;
     RECT  135.108 187.243 135.27 187.277 ;
     RECT  150.48 186.809 150.678 187.277 ;
     RECT  220.032 186.979 220.05 187.285 ;
     RECT  241.56 187.213 241.578 187.285 ;
     RECT  152.496 187.195 164.697 187.313 ;
     RECT  2.304 187.243 2.697 187.321 ;
     RECT  3.744 187.249 3.942 187.321 ;
     RECT  135.108 187.277 135.198 187.321 ;
     RECT  249.804 187.249 249.822 187.321 ;
     RECT  293.364 187.249 294.297 187.321 ;
     RECT  318.06 186.745 325.818 187.321 ;
     RECT  130.644 187.277 130.662 187.349 ;
     RECT  135.036 187.321 135.198 187.349 ;
     RECT  252.468 187.249 252.486 187.411 ;
     RECT  2.304 187.321 3.942 187.439 ;
     RECT  94.215 186.439 94.662 187.439 ;
     RECT  96.408 187.321 96.786 187.439 ;
     RECT  146.484 186.809 149.742 187.439 ;
     RECT  220.032 187.285 220.158 187.439 ;
     RECT  241.236 187.285 241.578 187.439 ;
     RECT  249.516 187.321 249.822 187.439 ;
     RECT  252.468 187.411 252.81 187.439 ;
     RECT  292.68 187.321 294.297 187.439 ;
     RECT  315.615 187.051 316.494 187.439 ;
     RECT  146.484 187.439 148.497 187.469 ;
     RECT  149.22 187.439 149.742 187.469 ;
     RECT  252.792 187.439 252.81 187.469 ;
     RECT  220.032 187.439 220.05 187.475 ;
     RECT  315.615 187.439 316.386 187.475 ;
     RECT  318.024 187.321 325.818 187.483 ;
     RECT  3.852 187.439 3.942 187.511 ;
     RECT  96.408 187.439 96.498 187.511 ;
     RECT  135.036 187.349 135.054 187.511 ;
     RECT  292.536 187.483 292.554 187.517 ;
     RECT  318.024 187.483 326.034 187.517 ;
     RECT  114.408 186.773 126.897 187.519 ;
     RECT  98.604 187.169 113.598 187.583 ;
     RECT  189.252 186.511 189.27 187.583 ;
     RECT  226.764 187.321 226.782 187.591 ;
     RECT  280.764 187.555 280.782 187.591 ;
     RECT  206.784 187.169 206.802 187.619 ;
     RECT  0.324 187.181 0.558 187.661 ;
     RECT  152.496 187.313 163.134 187.661 ;
     RECT  150.66 187.277 150.678 187.675 ;
     RECT  193.68 187.555 193.698 187.709 ;
     RECT  226.44 187.591 226.782 187.709 ;
     RECT  277.815 2.413 278.097 187.717 ;
     RECT  280.764 187.591 280.926 187.717 ;
     RECT  99.36 187.583 113.598 187.723 ;
     RECT  114.408 187.519 126.954 187.723 ;
     RECT  96.408 187.511 96.462 187.745 ;
     RECT  280.764 187.717 280.998 187.745 ;
     RECT  283.215 186.365 283.497 187.753 ;
     RECT  99.36 187.723 126.954 187.781 ;
     RECT  213.015 2.413 213.297 187.789 ;
     RECT  222.3 187.717 222.318 187.817 ;
     RECT  226.836 187.717 226.854 187.817 ;
     RECT  238.392 187.717 238.41 187.817 ;
     RECT  277.815 187.717 278.226 187.817 ;
     RECT  280.98 187.745 280.998 187.817 ;
     RECT  218.415 186.365 218.697 187.861 ;
     RECT  96.444 187.745 96.462 187.889 ;
     RECT  13.215 186.809 13.497 187.951 ;
     RECT  24.015 187.079 24.297 187.951 ;
     RECT  34.815 186.809 35.097 187.951 ;
     RECT  45.615 186.809 45.897 187.951 ;
     RECT  56.415 186.809 56.697 187.951 ;
     RECT  67.215 186.809 67.497 187.951 ;
     RECT  78.015 186.809 78.297 187.951 ;
     RECT  204.552 187.771 204.57 187.951 ;
     RECT  212.832 187.789 213.297 187.951 ;
     RECT  88.815 186.809 89.097 187.963 ;
     RECT  34.632 187.951 35.097 187.997 ;
     RECT  150.66 187.675 151.038 187.997 ;
     RECT  318.024 187.517 325.962 188.011 ;
     RECT  218.016 187.861 218.697 188.015 ;
     RECT  212.76 187.951 213.297 188.045 ;
     RECT  204.48 187.951 204.642 188.051 ;
     RECT  210.348 187.951 210.366 188.051 ;
     RECT  212.904 188.045 213.297 188.051 ;
     RECT  122.58 187.781 126.954 188.087 ;
     RECT  218.232 188.015 218.697 188.087 ;
     RECT  99.36 187.781 120.474 188.093 ;
     RECT  123.876 188.087 126.954 188.093 ;
     RECT  184.644 188.059 184.662 188.095 ;
     RECT  0.324 187.661 0.522 188.107 ;
     RECT  124.164 188.093 126.954 188.123 ;
     RECT  152.496 187.661 162.45 188.123 ;
     RECT  124.38 188.123 126.954 188.131 ;
     RECT  184.644 188.095 185.202 188.131 ;
     RECT  87.372 187.861 87.39 188.159 ;
     RECT  99.36 188.093 107.118 188.159 ;
     RECT  242.244 187.753 242.262 188.221 ;
     RECT  0.144 188.107 0.522 188.237 ;
     RECT  107.928 188.093 120.474 188.249 ;
     RECT  184.068 188.131 185.202 188.249 ;
     RECT  293.796 187.439 294.297 188.249 ;
     RECT  99.36 188.159 107.046 188.285 ;
     RECT  108.576 188.249 120.474 188.285 ;
     RECT  183.888 188.251 183.906 188.285 ;
     RECT  184.644 188.249 184.878 188.285 ;
     RECT  124.38 188.131 127.314 188.321 ;
     RECT  122.58 188.087 123.102 188.357 ;
     RECT  290.124 188.257 290.142 188.357 ;
     RECT  107.028 188.285 107.046 188.393 ;
     RECT  163.872 187.313 164.697 188.393 ;
     RECT  2.304 187.439 3.006 188.395 ;
     RECT  239.652 187.213 240.297 188.401 ;
     RECT  241.524 188.221 242.262 188.401 ;
     RECT  2.268 188.395 3.006 188.429 ;
     RECT  317.448 188.011 325.962 188.429 ;
     RECT  162.432 188.123 162.45 188.491 ;
     RECT  238.32 187.825 238.338 188.491 ;
     RECT  310.215 184.739 310.497 188.491 ;
     RECT  2.304 188.429 3.006 188.519 ;
     RECT  99.36 188.285 106.29 188.519 ;
     RECT  113.976 188.285 120.474 188.519 ;
     RECT  121.215 187.781 121.59 188.519 ;
     RECT  123.084 188.357 123.102 188.519 ;
     RECT  162.432 188.491 162.594 188.519 ;
     RECT  182.412 188.401 182.43 188.519 ;
     RECT  184.86 188.285 184.878 188.519 ;
     RECT  237.096 188.401 237.114 188.519 ;
     RECT  249.336 188.401 249.354 188.519 ;
     RECT  307.404 187.519 307.422 188.519 ;
     RECT  13.104 187.951 13.497 188.525 ;
     RECT  23.904 187.951 24.297 188.525 ;
     RECT  34.704 187.997 35.097 188.525 ;
     RECT  45.504 187.951 45.897 188.525 ;
     RECT  56.304 187.951 56.697 188.525 ;
     RECT  67.104 187.951 67.497 188.525 ;
     RECT  77.904 187.951 78.297 188.525 ;
     RECT  88.704 187.963 89.097 188.525 ;
     RECT  241.524 188.401 242.37 188.527 ;
     RECT  102.492 188.519 106.29 188.555 ;
     RECT  113.976 188.519 118.242 188.555 ;
     RECT  125.028 188.321 127.314 188.555 ;
     RECT  0.144 188.237 0.162 188.573 ;
     RECT  2.415 188.519 3.006 188.591 ;
     RECT  114.336 188.555 118.242 188.591 ;
     RECT  162.504 188.519 162.594 188.591 ;
     RECT  241.524 188.527 242.946 188.591 ;
     RECT  118.98 188.519 120.474 188.599 ;
     RECT  121.215 188.519 121.497 188.599 ;
     RECT  98.604 187.583 98.622 188.621 ;
     RECT  102.564 188.555 106.29 188.627 ;
     RECT  125.028 188.555 125.658 188.627 ;
     RECT  126.615 188.555 127.314 188.627 ;
     RECT  152.496 188.123 161.298 188.627 ;
     RECT  164.376 188.393 164.697 188.627 ;
     RECT  99.615 188.519 101.538 188.663 ;
     RECT  118.98 188.599 121.497 188.663 ;
     RECT  125.64 188.627 125.658 188.663 ;
     RECT  162.504 188.591 162.522 188.663 ;
     RECT  242.208 188.591 242.946 188.663 ;
     RECT  310.104 188.491 310.497 188.663 ;
     RECT  102.6 188.627 106.29 188.669 ;
     RECT  234.615 2.413 234.897 188.671 ;
     RECT  249.264 188.527 249.282 188.699 ;
     RECT  238.284 188.491 238.338 188.761 ;
     RECT  239.256 188.401 240.297 188.761 ;
     RECT  102.924 188.669 106.182 188.789 ;
     RECT  114.768 188.591 118.242 188.789 ;
     RECT  238.284 188.761 240.678 188.813 ;
     RECT  318.06 188.429 325.962 188.813 ;
     RECT  108.576 188.285 113.202 188.825 ;
     RECT  114.768 188.789 116.262 188.825 ;
     RECT  117.432 188.789 118.242 188.825 ;
     RECT  0.108 188.683 0.126 188.861 ;
     RECT  77.112 188.761 77.13 188.861 ;
     RECT  119.628 188.663 121.497 188.861 ;
     RECT  238.284 188.813 240.642 188.861 ;
     RECT  327.204 188.563 327.222 188.869 ;
     RECT  328.068 187.037 328.23 188.869 ;
     RECT  108.576 188.825 111.042 188.897 ;
     RECT  250.815 186.365 251.097 188.905 ;
     RECT  261.615 186.365 261.897 188.905 ;
     RECT  272.415 186.365 272.697 188.905 ;
     RECT  283.215 187.753 284.13 188.905 ;
     RECT  304.815 184.739 305.097 188.905 ;
     RECT  315.615 187.475 315.897 188.905 ;
     RECT  318.96 188.813 325.962 188.905 ;
     RECT  114.984 188.825 116.097 188.909 ;
     RECT  120.708 188.861 121.497 188.933 ;
     RECT  242.208 188.663 242.226 188.957 ;
     RECT  250.704 188.905 251.097 188.957 ;
     RECT  261.504 188.905 261.897 188.957 ;
     RECT  272.304 188.905 272.697 188.957 ;
     RECT  283.104 188.905 284.13 188.957 ;
     RECT  293.904 188.249 294.297 188.957 ;
     RECT  304.704 188.905 305.097 188.957 ;
     RECT  315.504 188.905 315.897 188.957 ;
     RECT  108.792 188.897 111.042 188.969 ;
     RECT  119.628 188.861 119.718 188.969 ;
     RECT  204.408 188.059 204.426 188.969 ;
     RECT  76.824 188.941 76.842 189.005 ;
     RECT  100.764 188.663 100.962 189.059 ;
     RECT  103.176 188.789 106.182 189.059 ;
     RECT  108.792 188.969 110.697 189.059 ;
     RECT  111.924 188.825 113.202 189.059 ;
     RECT  119.7 188.969 119.718 189.059 ;
     RECT  154.764 188.627 161.226 189.059 ;
     RECT  234.324 188.671 234.897 189.059 ;
     RECT  283.215 188.957 284.13 189.059 ;
     RECT  100.764 189.059 100.782 189.095 ;
     RECT  104.544 189.059 106.182 189.095 ;
     RECT  115.56 188.909 116.097 189.095 ;
     RECT  117.432 188.825 118.062 189.095 ;
     RECT  121.032 188.933 121.497 189.131 ;
     RECT  103.176 189.059 103.734 189.149 ;
     RECT  112.716 189.059 112.842 189.167 ;
     RECT  117.432 189.095 117.45 189.167 ;
     RECT  327.204 188.869 328.23 189.197 ;
     RECT  103.176 189.149 103.194 189.203 ;
     RECT  104.544 189.095 105.966 189.203 ;
     RECT  111.924 189.059 111.942 189.203 ;
     RECT  112.716 189.167 112.734 189.203 ;
     RECT  238.284 188.861 238.698 189.239 ;
     RECT  239.94 188.861 240.642 189.239 ;
     RECT  154.764 189.059 160.938 189.329 ;
     RECT  235.8 187.051 235.818 189.329 ;
     RECT  238.608 189.239 238.698 189.329 ;
     RECT  108.936 189.059 110.697 189.341 ;
     RECT  327.24 189.197 328.23 189.341 ;
     RECT  108.936 189.341 108.954 189.365 ;
     RECT  318.96 188.905 326.106 189.389 ;
     RECT  318.06 188.813 318.222 189.401 ;
     RECT  238.68 189.329 238.698 189.437 ;
     RECT  239.94 189.239 240.57 189.437 ;
     RECT  109.728 189.341 110.697 189.473 ;
     RECT  236.916 188.599 236.934 189.481 ;
     RECT  282.168 189.337 282.186 189.481 ;
     RECT  240.015 189.437 240.57 189.485 ;
     RECT  318.132 189.401 318.222 189.571 ;
     RECT  318.96 189.389 326.034 189.571 ;
     RECT  104.688 189.203 105.966 189.599 ;
     RECT  281.952 189.481 282.186 189.599 ;
     RECT  281.952 189.599 281.97 189.635 ;
     RECT  104.688 189.599 105.534 189.707 ;
     RECT  236.88 189.481 237.078 189.707 ;
     RECT  104.688 189.707 105.426 189.743 ;
     RECT  318.132 189.571 326.034 189.773 ;
     RECT  236.88 189.707 236.898 189.779 ;
     RECT  318.132 189.773 325.854 189.779 ;
     RECT  154.764 189.329 160.794 189.941 ;
     RECT  283.215 189.059 283.914 189.965 ;
     RECT  327.744 189.341 328.23 190.061 ;
     RECT  165.852 190.111 165.87 190.123 ;
     RECT  165.852 190.123 166.482 190.157 ;
     RECT  318.78 189.779 325.854 190.211 ;
     RECT  319.356 190.211 325.854 190.247 ;
     RECT  166.176 190.157 166.482 190.253 ;
     RECT  319.608 190.247 325.854 190.283 ;
     RECT  171.252 190.219 171.27 190.291 ;
     RECT  166.176 190.253 166.194 190.319 ;
     RECT  171.252 190.291 171.63 190.349 ;
     RECT  162.504 190.291 162.594 190.397 ;
     RECT  319.788 190.283 325.854 190.409 ;
     RECT  162.504 190.397 162.522 190.445 ;
     RECT  154.764 189.941 160.686 190.481 ;
     RECT  328.212 190.061 328.23 190.481 ;
     RECT  320.292 190.409 325.854 190.603 ;
     RECT  320.292 190.603 325.962 190.829 ;
     RECT  320.472 190.829 325.962 191.065 ;
     RECT  320.472 191.065 326.646 191.213 ;
     RECT  320.472 191.213 325.962 191.255 ;
     RECT  320.472 191.255 325.818 191.363 ;
     RECT  154.764 190.481 160.074 191.371 ;
     RECT  160.812 190.723 160.83 191.371 ;
     RECT  320.904 191.363 321.354 191.489 ;
     RECT  328.14 190.891 328.158 191.563 ;
     RECT  328.14 191.563 328.23 191.755 ;
     RECT  328.104 191.755 328.23 191.851 ;
     RECT  320.904 191.489 321.297 191.867 ;
     RECT  2.415 188.591 2.697 191.899 ;
     RECT  150.66 187.997 150.678 191.899 ;
     RECT  2.415 191.899 2.79 191.939 ;
     RECT  322.56 191.363 325.818 192.145 ;
     RECT  2.415 191.939 2.697 192.235 ;
     RECT  13.215 188.525 13.497 192.271 ;
     RECT  24.015 188.525 24.297 192.271 ;
     RECT  34.815 188.525 35.097 192.271 ;
     RECT  45.615 188.525 45.897 192.271 ;
     RECT  56.415 188.525 56.697 192.271 ;
     RECT  67.215 188.525 67.497 192.271 ;
     RECT  78.015 188.525 78.297 192.271 ;
     RECT  88.815 188.525 89.097 192.271 ;
     RECT  99.615 188.663 99.897 192.271 ;
     RECT  110.415 189.473 110.697 192.271 ;
     RECT  121.215 189.131 121.497 192.271 ;
     RECT  132.015 186.809 132.297 192.271 ;
     RECT  142.815 186.809 143.097 192.271 ;
     RECT  322.56 192.145 326.034 192.299 ;
     RECT  152.496 188.627 153.897 192.331 ;
     RECT  154.764 191.371 160.83 192.331 ;
     RECT  0.216 192.523 0.234 192.541 ;
     RECT  240.015 189.485 240.297 192.577 ;
     RECT  240.015 192.577 240.606 192.613 ;
     RECT  152.496 192.331 160.83 192.721 ;
     RECT  2.304 192.235 2.697 192.845 ;
     RECT  13.104 192.271 13.497 192.845 ;
     RECT  23.904 192.271 24.297 192.845 ;
     RECT  34.704 192.271 35.097 192.845 ;
     RECT  45.504 192.271 45.897 192.845 ;
     RECT  56.304 192.271 56.697 192.845 ;
     RECT  67.104 192.271 67.497 192.845 ;
     RECT  77.904 192.271 78.297 192.845 ;
     RECT  88.704 192.271 89.097 192.845 ;
     RECT  99.504 192.271 99.897 192.845 ;
     RECT  110.304 192.271 110.697 192.845 ;
     RECT  121.104 192.271 121.497 192.845 ;
     RECT  131.904 192.271 132.297 192.845 ;
     RECT  142.704 192.271 143.097 192.845 ;
     RECT  0.216 192.541 0.306 192.859 ;
     RECT  152.496 192.721 160.938 192.991 ;
     RECT  0.144 192.859 0.306 193.099 ;
     RECT  322.632 192.299 326.034 193.145 ;
     RECT  328.068 191.851 328.23 193.217 ;
     RECT  238.968 191.911 238.986 193.225 ;
     RECT  152.136 192.991 160.938 193.261 ;
     RECT  238.968 193.225 239.274 193.261 ;
     RECT  0.108 193.099 0.306 193.291 ;
     RECT  152.136 193.261 161.19 193.373 ;
     RECT  152.136 193.373 161.118 193.379 ;
     RECT  2.415 192.845 2.697 193.387 ;
     RECT  0.108 193.291 0.342 193.423 ;
     RECT  322.992 193.145 326.034 193.451 ;
     RECT  323.568 193.451 326.034 193.487 ;
     RECT  328.068 193.217 328.086 193.487 ;
     RECT  0.108 193.423 0.378 193.517 ;
     RECT  150.48 191.899 150.678 193.517 ;
     RECT  323.892 193.487 326.034 193.523 ;
     RECT  2.415 193.387 2.718 193.621 ;
     RECT  2.415 193.621 2.79 193.661 ;
     RECT  152.136 193.379 160.974 193.661 ;
     RECT  323.928 193.523 326.034 193.685 ;
     RECT  152.136 193.661 160.578 193.955 ;
     RECT  324.18 193.685 326.034 193.955 ;
     RECT  324.72 193.955 326.034 194.093 ;
     RECT  324.864 194.093 326.034 194.099 ;
     RECT  2.415 193.661 2.697 194.431 ;
     RECT  13.215 192.845 13.497 194.431 ;
     RECT  24.015 192.845 24.297 194.431 ;
     RECT  34.815 192.845 35.097 194.431 ;
     RECT  45.615 192.845 45.897 194.431 ;
     RECT  56.415 192.845 56.697 194.431 ;
     RECT  67.215 192.845 67.497 194.431 ;
     RECT  78.015 192.845 78.297 194.431 ;
     RECT  88.815 192.845 89.097 194.431 ;
     RECT  99.615 192.845 99.897 194.431 ;
     RECT  110.415 192.845 110.697 194.431 ;
     RECT  121.215 192.845 121.497 194.431 ;
     RECT  132.015 192.845 132.297 194.431 ;
     RECT  142.815 192.845 143.097 194.431 ;
     RECT  152.136 193.955 160.434 194.431 ;
     RECT  150.66 193.517 150.678 194.443 ;
     RECT  2.304 194.431 2.697 194.477 ;
     RECT  13.104 194.431 13.497 194.477 ;
     RECT  23.904 194.431 24.297 194.477 ;
     RECT  34.704 194.431 35.097 194.477 ;
     RECT  45.504 194.431 45.897 194.477 ;
     RECT  56.304 194.431 56.697 194.477 ;
     RECT  67.104 194.431 67.497 194.477 ;
     RECT  77.904 194.431 78.297 194.477 ;
     RECT  88.704 194.431 89.097 194.477 ;
     RECT  99.504 194.431 99.897 194.477 ;
     RECT  110.304 194.431 110.697 194.477 ;
     RECT  121.104 194.431 121.497 194.477 ;
     RECT  131.904 194.431 132.297 194.477 ;
     RECT  142.704 194.431 143.097 194.477 ;
     RECT  150.588 194.443 150.678 194.503 ;
     RECT  325.008 194.099 326.034 194.531 ;
     RECT  150.552 194.503 150.678 194.539 ;
     RECT  150.48 194.539 150.678 194.765 ;
     RECT  325.008 194.531 325.998 194.765 ;
     RECT  152.064 194.431 160.434 194.773 ;
     RECT  325.188 194.765 325.998 194.801 ;
     RECT  238.644 193.261 239.274 194.809 ;
     RECT  240.015 192.613 241.038 194.809 ;
     RECT  0.108 193.517 0.342 194.861 ;
     RECT  325.188 194.801 325.962 195.107 ;
     RECT  325.728 195.107 325.962 195.269 ;
     RECT  325.728 195.269 325.746 195.305 ;
     RECT  238.644 194.809 241.038 195.313 ;
     RECT  0.108 194.861 0.198 195.449 ;
     RECT  152.064 194.773 160.578 195.499 ;
     RECT  152.064 195.499 160.794 195.539 ;
     RECT  162.432 195.547 162.45 195.781 ;
     RECT  162 195.781 162.45 195.881 ;
     RECT  152.064 195.539 160.578 196.231 ;
     RECT  162 195.881 162.09 196.465 ;
     RECT  161.856 196.465 162.09 196.501 ;
     RECT  161.46 196.501 162.09 196.591 ;
     RECT  161.388 196.591 162.09 196.699 ;
     RECT  164.415 188.627 164.697 196.699 ;
     RECT  151.74 196.231 160.578 196.771 ;
     RECT  161.388 196.699 162.162 196.771 ;
     RECT  151.74 196.771 162.162 196.861 ;
     RECT  164.124 196.699 164.697 196.897 ;
     RECT  151.74 196.861 162.882 197.041 ;
     RECT  163.728 196.897 164.697 197.041 ;
     RECT  166.464 196.771 166.482 197.473 ;
     RECT  151.74 197.041 164.697 197.537 ;
     RECT  169.815 186.809 170.097 197.545 ;
     RECT  166.356 197.473 166.482 197.573 ;
     RECT  166.464 197.573 166.482 197.581 ;
     RECT  169.56 197.545 170.097 197.851 ;
     RECT  237.024 194.233 237.042 197.969 ;
     RECT  237.924 195.313 241.038 197.969 ;
     RECT  234.615 189.059 234.897 198.121 ;
     RECT  0.18 195.449 0.198 198.149 ;
     RECT  239.832 197.969 241.038 198.239 ;
     RECT  166.464 197.581 166.626 198.311 ;
     RECT  234.288 198.121 234.897 198.311 ;
     RECT  242.244 198.247 242.262 198.347 ;
     RECT  142.815 194.477 143.097 198.481 ;
     RECT  146.736 187.469 148.497 198.481 ;
     RECT  146.448 198.481 148.497 198.509 ;
     RECT  169.308 197.851 170.097 198.625 ;
     RECT  146.448 198.509 146.466 198.689 ;
     RECT  169.308 198.625 170.514 198.751 ;
     RECT  147.42 198.509 148.497 198.851 ;
     RECT  166.464 198.311 166.482 198.851 ;
     RECT  167.544 198.211 167.562 198.859 ;
     RECT  167.544 198.859 167.922 198.895 ;
     RECT  168.84 198.751 170.874 198.895 ;
     RECT  151.992 197.537 164.697 198.923 ;
     RECT  144.828 198.931 144.846 199.021 ;
     RECT  167.292 198.895 170.874 199.165 ;
     RECT  147.888 198.851 148.497 199.229 ;
     RECT  144.324 199.021 144.846 199.355 ;
     RECT  0.036 199.291 0.054 199.363 ;
     RECT  241.956 198.661 241.974 199.363 ;
     RECT  142.776 198.481 143.097 199.399 ;
     RECT  138.528 199.363 138.546 199.463 ;
     RECT  245.415 176.981 245.697 199.471 ;
     RECT  142.56 199.399 143.097 199.499 ;
     RECT  166.932 199.165 170.874 199.561 ;
     RECT  237.924 197.969 239.094 199.705 ;
     RECT  152.172 198.923 164.697 199.741 ;
     RECT  152.172 199.741 165.51 199.939 ;
     RECT  152.172 199.939 166.122 200.011 ;
     RECT  166.932 199.561 170.946 200.011 ;
     RECT  150.66 194.765 150.678 200.101 ;
     RECT  237.78 199.705 239.094 200.165 ;
     RECT  0.036 199.363 0.306 200.173 ;
     RECT  152.172 200.011 171.27 200.173 ;
     RECT  150.48 200.101 150.678 200.237 ;
     RECT  283.215 189.965 283.497 200.245 ;
     RECT  151.524 200.173 171.27 200.273 ;
     RECT  151.524 200.273 171.09 200.281 ;
     RECT  244.332 200.173 244.35 200.281 ;
     RECT  151.488 200.281 171.09 200.399 ;
     RECT  151.488 200.399 151.866 200.435 ;
     RECT  152.64 200.399 171.09 200.543 ;
     RECT  151.848 200.435 151.866 200.621 ;
     RECT  152.676 200.543 171.09 200.861 ;
     RECT  243.936 200.281 244.35 201.019 ;
     RECT  153.072 200.861 171.09 201.055 ;
     RECT  283.215 200.245 283.554 201.055 ;
     RECT  153.072 201.055 171.27 201.209 ;
     RECT  243.072 199.741 243.09 201.361 ;
     RECT  243.936 201.019 244.566 201.361 ;
     RECT  241.704 199.363 241.974 201.389 ;
     RECT  0.036 200.173 0.486 201.523 ;
     RECT  149.724 187.469 149.742 201.523 ;
     RECT  149.616 201.523 149.742 201.595 ;
     RECT  150.66 200.237 150.678 201.595 ;
     RECT  153.072 201.209 171.162 201.749 ;
     RECT  153.072 201.749 161.514 201.793 ;
     RECT  149.616 201.595 150.678 201.829 ;
     RECT  328.284 198.247 328.302 201.835 ;
     RECT  239.832 198.239 240.606 201.869 ;
     RECT  294.015 188.957 294.297 201.883 ;
     RECT  304.815 188.957 305.097 201.883 ;
     RECT  315.615 188.957 315.897 201.883 ;
     RECT  328.104 201.835 328.302 201.883 ;
     RECT  149.616 201.829 151.218 201.901 ;
     RECT  283.14 201.055 283.554 201.917 ;
     RECT  293.904 201.883 294.297 201.929 ;
     RECT  304.704 201.883 305.097 201.929 ;
     RECT  315.504 201.883 315.897 201.929 ;
     RECT  149.616 201.901 151.938 202.027 ;
     RECT  142.815 199.499 143.097 202.075 ;
     RECT  149.58 202.027 151.938 202.075 ;
     RECT  152.928 201.793 161.514 202.099 ;
     RECT  237.78 200.165 238.302 202.109 ;
     RECT  145.26 202.075 145.386 202.123 ;
     RECT  146.484 201.829 146.502 202.123 ;
     RECT  149.364 202.075 151.938 202.135 ;
     RECT  152.712 202.099 161.514 202.135 ;
     RECT  236.34 198.121 236.358 202.157 ;
     RECT  149.364 202.135 161.514 202.163 ;
     RECT  145.26 202.123 146.502 202.171 ;
     RECT  2.415 194.477 2.697 202.261 ;
     RECT  148.215 199.229 148.497 202.261 ;
     RECT  149.364 202.163 151.65 202.261 ;
     RECT  2.415 202.261 2.79 202.301 ;
     RECT  145.26 202.171 147.042 202.349 ;
     RECT  146.052 202.349 147.042 202.369 ;
     RECT  283.14 201.917 283.497 202.397 ;
     RECT  328.032 201.883 328.302 202.411 ;
     RECT  0.036 201.523 0.558 202.445 ;
     RECT  239.904 201.869 240.606 202.445 ;
     RECT  152.496 202.163 161.514 202.531 ;
     RECT  162.468 201.749 171.162 202.531 ;
     RECT  146.052 202.369 147.402 202.589 ;
     RECT  146.844 202.589 147.402 202.603 ;
     RECT  148.215 202.261 151.65 202.603 ;
     RECT  239.904 202.445 240.297 202.637 ;
     RECT  239.076 200.165 239.094 202.685 ;
     RECT  324.9 202.261 325.494 202.699 ;
     RECT  172.476 202.441 172.494 202.711 ;
     RECT  324.9 202.699 325.53 202.739 ;
     RECT  152.496 202.531 171.162 202.795 ;
     RECT  171.972 202.711 173.106 202.795 ;
     RECT  142.524 202.075 143.097 202.801 ;
     RECT  145.26 202.349 145.278 202.829 ;
     RECT  327.96 202.411 328.302 202.829 ;
     RECT  142.488 202.801 143.658 202.837 ;
     RECT  142.416 202.837 143.658 202.877 ;
     RECT  237.78 202.109 237.798 202.877 ;
     RECT  142.416 202.877 143.514 202.945 ;
     RECT  146.844 202.603 151.65 202.945 ;
     RECT  241.956 201.389 241.974 202.973 ;
     RECT  174.42 202.909 174.438 202.981 ;
     RECT  2.415 202.301 2.697 202.987 ;
     RECT  146.844 202.945 151.722 202.987 ;
     RECT  152.496 202.795 173.106 202.987 ;
     RECT  13.215 194.477 13.497 203.071 ;
     RECT  24.015 194.477 24.297 203.071 ;
     RECT  34.815 194.477 35.097 203.071 ;
     RECT  45.615 194.477 45.897 203.071 ;
     RECT  56.415 194.477 56.697 203.071 ;
     RECT  67.215 194.477 67.497 203.071 ;
     RECT  78.015 194.477 78.297 203.071 ;
     RECT  88.815 194.477 89.097 203.071 ;
     RECT  99.615 194.477 99.897 203.071 ;
     RECT  110.415 194.477 110.697 203.071 ;
     RECT  121.215 194.477 121.497 203.071 ;
     RECT  132.015 194.477 132.297 203.071 ;
     RECT  146.844 202.987 173.106 203.071 ;
     RECT  174.276 202.981 174.438 203.071 ;
     RECT  175.215 186.809 175.497 203.071 ;
     RECT  248.616 202.639 248.634 203.099 ;
     RECT  250.815 188.957 251.097 203.107 ;
     RECT  318.42 202.939 318.438 203.131 ;
     RECT  327.96 202.829 328.23 203.179 ;
     RECT  250.236 203.107 251.097 203.207 ;
     RECT  322.056 203.107 322.074 203.207 ;
     RECT  144.432 202.981 144.45 203.251 ;
     RECT  0.036 202.445 0.486 203.341 ;
     RECT  146.052 202.589 146.07 203.341 ;
     RECT  146.844 203.071 175.497 203.341 ;
     RECT  318.42 203.131 318.726 203.369 ;
     RECT  323.82 203.341 324.126 203.405 ;
     RECT  142.38 202.945 143.514 203.419 ;
     RECT  0.036 203.341 0.558 203.477 ;
     RECT  140.976 203.467 140.994 203.521 ;
     RECT  13.104 203.071 13.497 203.549 ;
     RECT  23.904 203.071 24.297 203.549 ;
     RECT  34.704 203.071 35.097 203.549 ;
     RECT  45.504 203.071 45.897 203.549 ;
     RECT  56.304 203.071 56.697 203.549 ;
     RECT  67.104 203.071 67.497 203.549 ;
     RECT  77.904 203.071 78.297 203.549 ;
     RECT  88.704 203.071 89.097 203.549 ;
     RECT  99.504 203.071 99.897 203.549 ;
     RECT  110.304 203.071 110.697 203.549 ;
     RECT  121.104 203.071 121.497 203.549 ;
     RECT  131.904 203.071 132.297 203.549 ;
     RECT  2.304 202.987 2.697 203.597 ;
     RECT  137.415 170.969 137.697 203.611 ;
     RECT  186.015 186.809 186.297 203.611 ;
     RECT  196.815 186.809 197.097 203.611 ;
     RECT  207.615 186.365 207.897 203.611 ;
     RECT  218.415 188.087 218.697 203.611 ;
     RECT  229.215 186.365 229.497 203.611 ;
     RECT  240.015 202.637 240.297 203.611 ;
     RECT  243.072 201.361 244.566 203.611 ;
     RECT  245.415 199.471 245.97 203.611 ;
     RECT  261.615 188.957 261.897 203.611 ;
     RECT  272.415 188.957 272.697 203.611 ;
     RECT  283.215 202.397 283.497 203.611 ;
     RECT  294.015 201.929 294.297 203.611 ;
     RECT  304.815 201.929 305.097 203.611 ;
     RECT  315.615 201.929 315.897 203.611 ;
     RECT  140.76 203.521 140.994 203.639 ;
     RECT  146.052 203.341 175.497 203.683 ;
     RECT  144.432 203.251 144.522 203.755 ;
     RECT  242.244 202.981 242.262 203.819 ;
     RECT  243.072 203.611 245.97 203.819 ;
     RECT  139.104 203.755 139.266 203.881 ;
     RECT  327.744 203.179 328.23 203.885 ;
     RECT  139.104 203.881 139.374 203.909 ;
     RECT  140.976 203.639 140.994 203.909 ;
     RECT  243.18 203.819 245.97 203.909 ;
     RECT  247.896 203.791 247.914 203.909 ;
     RECT  285.984 203.755 286.002 203.909 ;
     RECT  136.8 203.611 137.697 203.945 ;
     RECT  139.248 203.909 139.374 203.945 ;
     RECT  326.592 203.755 326.61 203.981 ;
     RECT  139.356 203.945 139.374 204.017 ;
     RECT  328.068 203.885 328.23 204.017 ;
     RECT  141.948 203.419 143.514 204.025 ;
     RECT  144.396 203.755 144.522 204.025 ;
     RECT  145.332 203.683 175.497 204.025 ;
     RECT  134.532 203.917 134.55 204.053 ;
     RECT  327.204 204.025 327.222 204.077 ;
     RECT  185.904 203.611 186.297 204.089 ;
     RECT  196.704 203.611 197.097 204.089 ;
     RECT  207.504 203.611 207.897 204.089 ;
     RECT  218.304 203.611 218.697 204.089 ;
     RECT  229.104 203.611 229.497 204.089 ;
     RECT  239.904 203.611 240.297 204.089 ;
     RECT  250.704 203.207 251.097 204.089 ;
     RECT  261.504 203.611 261.897 204.089 ;
     RECT  272.304 203.611 272.697 204.089 ;
     RECT  283.104 203.611 283.497 204.089 ;
     RECT  293.904 203.611 294.297 204.089 ;
     RECT  304.704 203.611 305.097 204.089 ;
     RECT  315.504 203.611 315.897 204.089 ;
     RECT  144.396 204.025 175.497 204.091 ;
     RECT  324.9 202.739 325.494 204.139 ;
     RECT  322.056 204.043 322.074 204.173 ;
     RECT  139.5 204.025 139.518 204.179 ;
     RECT  144.324 204.091 175.497 204.259 ;
     RECT  141.012 204.025 143.514 204.283 ;
     RECT  144.288 204.259 175.497 204.283 ;
     RECT  323.82 203.405 324.018 204.379 ;
     RECT  324.9 204.139 325.53 204.449 ;
     RECT  0.072 203.477 0.558 204.629 ;
     RECT  323.712 204.379 324.018 204.691 ;
     RECT  324.9 204.449 325.494 204.691 ;
     RECT  138.636 204.715 138.654 204.811 ;
     RECT  141.012 204.283 175.497 204.811 ;
     RECT  140.796 204.811 175.497 204.859 ;
     RECT  138.528 204.811 138.654 205.085 ;
     RECT  328.068 204.017 328.158 205.085 ;
     RECT  138.6 205.085 138.654 205.133 ;
     RECT  140.796 204.859 175.59 205.133 ;
     RECT  140.796 205.133 175.554 205.231 ;
     RECT  186.015 204.089 186.297 205.231 ;
     RECT  196.815 204.089 197.097 205.231 ;
     RECT  207.615 204.089 207.897 205.231 ;
     RECT  218.415 204.089 218.697 205.231 ;
     RECT  229.215 204.089 229.497 205.231 ;
     RECT  240.015 204.089 240.297 205.231 ;
     RECT  261.615 204.089 261.897 205.231 ;
     RECT  272.415 204.089 272.697 205.231 ;
     RECT  283.215 204.089 283.497 205.231 ;
     RECT  294.015 204.089 294.297 205.231 ;
     RECT  304.815 204.089 305.097 205.231 ;
     RECT  315.615 204.089 315.897 205.231 ;
     RECT  243.216 203.909 245.97 205.243 ;
     RECT  138.6 205.133 138.618 205.295 ;
     RECT  182.412 205.231 182.43 205.331 ;
     RECT  194.364 205.231 194.382 205.331 ;
     RECT  206.352 205.231 206.37 205.331 ;
     RECT  214.344 205.231 214.362 205.331 ;
     RECT  226.296 205.231 226.314 205.331 ;
     RECT  238.284 205.231 238.302 205.331 ;
     RECT  243.216 205.243 246.33 205.373 ;
     RECT  250.815 204.089 251.097 205.387 ;
     RECT  243.216 205.373 246.258 205.613 ;
     RECT  250.815 205.387 251.154 205.613 ;
     RECT  140.292 205.231 175.554 205.673 ;
     RECT  2.415 203.597 2.697 205.675 ;
     RECT  13.215 203.549 13.497 205.675 ;
     RECT  24.015 203.549 24.297 205.675 ;
     RECT  34.815 203.549 35.097 205.675 ;
     RECT  45.615 203.549 45.897 205.675 ;
     RECT  56.415 203.549 56.697 205.675 ;
     RECT  67.215 203.549 67.497 205.675 ;
     RECT  78.015 203.549 78.297 205.675 ;
     RECT  88.815 203.549 89.097 205.675 ;
     RECT  99.615 203.549 99.897 205.675 ;
     RECT  110.415 203.549 110.697 205.675 ;
     RECT  121.215 203.549 121.497 205.675 ;
     RECT  132.015 203.549 132.297 205.675 ;
     RECT  326.592 205.195 326.61 205.709 ;
     RECT  250.815 205.613 251.097 205.771 ;
     RECT  328.14 205.085 328.158 205.771 ;
     RECT  243.216 205.613 245.97 205.799 ;
     RECT  0.108 204.629 0.558 205.871 ;
     RECT  139.68 205.681 139.806 205.915 ;
     RECT  328.14 205.771 328.23 205.915 ;
     RECT  139.428 205.915 139.806 205.951 ;
     RECT  327.168 205.867 327.186 205.979 ;
     RECT  140.76 205.673 175.554 206.069 ;
     RECT  285.804 204.025 285.822 206.093 ;
     RECT  139.392 205.951 139.806 206.105 ;
     RECT  249.444 205.579 249.462 206.105 ;
     RECT  141.876 206.069 175.554 206.107 ;
     RECT  140.76 206.069 141.03 206.141 ;
     RECT  323.712 204.691 325.494 206.203 ;
     RECT  2.304 205.675 2.697 206.221 ;
     RECT  61.815 173.849 62.097 206.221 ;
     RECT  141.876 206.107 175.662 206.221 ;
     RECT  13.104 205.675 13.497 206.249 ;
     RECT  23.904 205.675 24.297 206.249 ;
     RECT  34.704 205.675 35.097 206.249 ;
     RECT  45.504 205.675 45.897 206.249 ;
     RECT  56.304 205.675 56.697 206.249 ;
     RECT  67.104 205.675 67.497 206.249 ;
     RECT  77.904 205.675 78.297 206.249 ;
     RECT  88.704 205.675 89.097 206.249 ;
     RECT  99.504 205.675 99.897 206.249 ;
     RECT  110.304 205.675 110.697 206.249 ;
     RECT  121.104 205.675 121.497 206.249 ;
     RECT  131.904 205.675 132.297 206.249 ;
     RECT  139.428 206.105 139.806 206.249 ;
     RECT  182.412 206.149 182.43 206.249 ;
     RECT  185.904 205.231 186.297 206.249 ;
     RECT  194.364 206.149 194.382 206.249 ;
     RECT  196.704 205.231 197.097 206.249 ;
     RECT  206.352 206.149 206.37 206.249 ;
     RECT  207.504 205.231 207.897 206.249 ;
     RECT  214.344 206.149 214.362 206.249 ;
     RECT  218.304 205.231 218.697 206.249 ;
     RECT  226.296 206.149 226.314 206.249 ;
     RECT  229.104 205.231 229.497 206.249 ;
     RECT  238.284 206.149 238.302 206.249 ;
     RECT  239.904 205.231 240.297 206.249 ;
     RECT  250.704 205.771 251.097 206.249 ;
     RECT  261.504 205.231 261.897 206.249 ;
     RECT  272.304 205.231 272.697 206.249 ;
     RECT  283.104 205.231 283.497 206.249 ;
     RECT  293.904 205.231 294.297 206.249 ;
     RECT  304.704 205.231 305.097 206.249 ;
     RECT  315.504 205.231 315.897 206.249 ;
     RECT  2.304 206.221 2.862 206.285 ;
     RECT  2.415 206.285 2.862 206.339 ;
     RECT  10.836 206.221 10.854 206.339 ;
     RECT  22.824 206.221 22.842 206.339 ;
     RECT  30.78 206.221 30.798 206.339 ;
     RECT  42.768 206.221 42.786 206.339 ;
     RECT  54.72 206.221 54.738 206.339 ;
     RECT  61.815 206.221 62.73 206.339 ;
     RECT  74.664 206.221 74.682 206.339 ;
     RECT  86.652 206.221 86.67 206.339 ;
     RECT  98.604 206.221 98.622 206.339 ;
     RECT  106.596 206.221 106.614 206.339 ;
     RECT  118.584 206.221 118.602 206.339 ;
     RECT  130.536 206.221 130.554 206.339 ;
     RECT  141.876 206.221 175.734 206.339 ;
     RECT  323.712 206.203 325.53 206.339 ;
     RECT  322.056 205.771 322.074 206.347 ;
     RECT  328.104 205.915 328.23 206.347 ;
     RECT  140.796 206.141 141.03 206.375 ;
     RECT  243.216 205.799 245.79 206.381 ;
     RECT  328.032 206.347 328.23 206.411 ;
     RECT  328.032 206.411 328.158 206.443 ;
     RECT  243.216 206.381 245.697 206.447 ;
     RECT  322.056 206.347 322.182 206.477 ;
     RECT  243.216 206.447 244.386 206.621 ;
     RECT  0.396 205.871 0.558 206.669 ;
     RECT  243.216 206.621 244.17 206.717 ;
     RECT  138.528 206.107 138.546 206.879 ;
     RECT  327.924 206.443 328.158 206.923 ;
     RECT  243.072 206.761 243.09 206.987 ;
     RECT  327.636 206.923 328.158 207.053 ;
     RECT  240.015 206.249 240.297 207.121 ;
     RECT  244.152 206.717 244.17 207.149 ;
     RECT  328.14 207.053 328.158 207.211 ;
     RECT  322.056 206.477 322.074 207.257 ;
     RECT  328.14 207.211 328.23 207.257 ;
     RECT  290.088 207.157 290.106 207.293 ;
     RECT  323.712 206.339 325.494 207.301 ;
     RECT  0.432 206.669 0.558 207.341 ;
     RECT  2.415 206.339 2.697 207.391 ;
     RECT  13.215 206.249 13.497 207.391 ;
     RECT  24.015 206.249 24.297 207.391 ;
     RECT  34.815 206.249 35.097 207.391 ;
     RECT  45.615 206.249 45.897 207.391 ;
     RECT  56.415 206.249 56.697 207.391 ;
     RECT  67.215 206.249 67.497 207.391 ;
     RECT  78.015 206.249 78.297 207.391 ;
     RECT  88.815 206.249 89.097 207.391 ;
     RECT  99.615 206.249 99.897 207.391 ;
     RECT  110.415 206.249 110.697 207.391 ;
     RECT  121.215 206.249 121.497 207.391 ;
     RECT  132.015 206.249 132.297 207.391 ;
     RECT  186.015 206.249 186.297 207.391 ;
     RECT  196.815 206.249 197.097 207.391 ;
     RECT  207.615 206.249 207.897 207.391 ;
     RECT  218.415 206.249 218.697 207.391 ;
     RECT  229.215 206.249 229.497 207.391 ;
     RECT  240.015 207.121 240.786 207.391 ;
     RECT  250.815 206.249 251.097 207.391 ;
     RECT  261.615 206.249 261.897 207.391 ;
     RECT  272.415 206.249 272.697 207.391 ;
     RECT  283.215 206.249 283.497 207.391 ;
     RECT  294.015 206.249 294.297 207.391 ;
     RECT  304.815 206.249 305.097 207.391 ;
     RECT  315.615 206.249 315.897 207.391 ;
     RECT  323.712 207.301 326.07 207.437 ;
     RECT  141.876 206.339 175.497 207.463 ;
     RECT  141.768 207.463 175.497 207.499 ;
     RECT  0.432 207.341 0.45 207.533 ;
     RECT  0.18 207.547 0.198 207.595 ;
     RECT  140.796 206.375 140.85 207.661 ;
     RECT  141.588 207.499 175.497 207.661 ;
     RECT  0.108 207.595 0.198 207.725 ;
     RECT  239.904 207.391 240.786 207.841 ;
     RECT  13.104 207.391 13.497 207.869 ;
     RECT  23.904 207.391 24.297 207.869 ;
     RECT  34.704 207.391 35.097 207.869 ;
     RECT  45.504 207.391 45.897 207.869 ;
     RECT  56.304 207.391 56.697 207.869 ;
     RECT  67.104 207.391 67.497 207.869 ;
     RECT  77.904 207.391 78.297 207.869 ;
     RECT  88.704 207.391 89.097 207.869 ;
     RECT  99.504 207.391 99.897 207.869 ;
     RECT  110.304 207.391 110.697 207.869 ;
     RECT  121.104 207.391 121.497 207.869 ;
     RECT  131.904 207.391 132.297 207.869 ;
     RECT  140.796 207.661 175.497 207.869 ;
     RECT  2.304 207.391 2.697 207.917 ;
     RECT  140.796 207.869 156.582 208.013 ;
     RECT  140.796 208.013 155.358 208.067 ;
     RECT  157.716 207.869 175.497 208.075 ;
     RECT  140.796 208.067 153.897 208.103 ;
     RECT  154.944 208.067 155.358 208.103 ;
     RECT  156.096 208.013 156.582 208.109 ;
     RECT  157.716 208.075 175.554 208.109 ;
     RECT  140.796 208.103 145.494 208.229 ;
     RECT  157.716 208.109 172.242 208.229 ;
     RECT  173.34 208.109 175.554 208.229 ;
     RECT  239.904 207.841 241.146 208.229 ;
     RECT  158.904 208.229 171.018 208.265 ;
     RECT  323.712 207.437 325.494 208.267 ;
     RECT  328.14 207.257 328.158 208.267 ;
     RECT  159.012 208.265 170.586 208.301 ;
     RECT  173.88 208.229 175.554 208.301 ;
     RECT  327.96 208.267 328.158 208.315 ;
     RECT  140.796 208.229 145.386 208.337 ;
     RECT  327.888 208.315 328.158 208.345 ;
     RECT  140.796 208.337 145.134 208.373 ;
     RECT  157.716 208.229 157.986 208.373 ;
     RECT  327.888 208.345 328.23 208.373 ;
     RECT  140.796 208.373 145.098 208.409 ;
     RECT  146.232 208.103 153.897 208.409 ;
     RECT  155.16 208.103 155.358 208.409 ;
     RECT  173.916 208.301 175.497 208.409 ;
     RECT  182.412 208.309 182.43 208.409 ;
     RECT  185.904 207.391 186.297 208.409 ;
     RECT  194.364 208.309 194.382 208.409 ;
     RECT  196.704 207.391 197.097 208.409 ;
     RECT  206.352 208.309 206.37 208.409 ;
     RECT  207.504 207.391 207.897 208.409 ;
     RECT  214.344 208.309 214.362 208.409 ;
     RECT  218.304 207.391 218.697 208.409 ;
     RECT  226.296 208.309 226.314 208.409 ;
     RECT  229.104 207.391 229.497 208.409 ;
     RECT  239.904 208.229 240.297 208.409 ;
     RECT  250.704 207.391 251.097 208.409 ;
     RECT  261.504 207.391 261.897 208.409 ;
     RECT  272.304 207.391 272.697 208.409 ;
     RECT  283.104 207.391 283.497 208.409 ;
     RECT  293.904 207.391 294.297 208.409 ;
     RECT  304.704 207.391 305.097 208.409 ;
     RECT  315.504 207.391 315.897 208.409 ;
     RECT  327.96 208.373 328.23 208.493 ;
     RECT  140.796 208.409 140.814 208.499 ;
     RECT  141.876 208.409 145.098 208.499 ;
     RECT  156.096 208.109 156.294 208.499 ;
     RECT  171.828 208.229 172.242 208.499 ;
     RECT  174.6 208.409 175.497 208.499 ;
     RECT  323.712 208.267 325.53 208.499 ;
     RECT  241.128 208.229 241.146 208.507 ;
     RECT  0.108 207.725 0.126 208.535 ;
     RECT  156.096 208.499 156.114 208.535 ;
     RECT  160.74 208.301 170.586 208.535 ;
     RECT  144.72 208.499 145.098 208.541 ;
     RECT  157.716 208.373 157.842 208.541 ;
     RECT  159.012 208.301 159.966 208.541 ;
     RECT  141.948 208.499 143.91 208.571 ;
     RECT  146.412 208.409 153.897 208.571 ;
     RECT  160.74 208.535 170.442 208.589 ;
     RECT  171.864 208.499 172.242 208.589 ;
     RECT  138.528 208.507 138.546 208.607 ;
     RECT  142.092 208.571 143.91 208.607 ;
     RECT  144.72 208.541 144.846 208.607 ;
     RECT  155.16 208.409 155.178 208.607 ;
     RECT  157.824 208.541 157.842 208.607 ;
     RECT  160.74 208.589 170.097 208.607 ;
     RECT  174.672 208.499 175.497 208.607 ;
     RECT  142.272 208.607 143.91 208.643 ;
     RECT  144.72 208.607 144.81 208.643 ;
     RECT  244.548 208.471 244.566 208.651 ;
     RECT  245.304 206.447 245.697 208.651 ;
     RECT  142.272 208.643 143.73 208.679 ;
     RECT  241.128 208.507 241.722 208.679 ;
     RECT  146.736 208.571 148.497 208.769 ;
     RECT  244.548 208.651 245.697 208.769 ;
     RECT  323.712 208.499 325.494 208.769 ;
     RECT  245.415 208.769 245.697 208.777 ;
     RECT  146.736 208.769 146.934 208.805 ;
     RECT  159.012 208.541 159.786 208.829 ;
     RECT  324.324 208.769 325.494 208.829 ;
     RECT  245.415 208.777 246.222 208.877 ;
     RECT  244.548 208.769 244.566 208.885 ;
     RECT  238.284 208.381 238.302 208.949 ;
     RECT  241.128 208.679 241.47 208.949 ;
     RECT  243.216 208.849 243.234 208.949 ;
     RECT  149.328 208.571 153.897 209.035 ;
     RECT  144.792 208.643 144.81 209.039 ;
     RECT  149.328 209.035 154.53 209.039 ;
     RECT  285.84 208.813 285.858 209.039 ;
     RECT  286.956 208.777 286.974 209.039 ;
     RECT  150.156 209.039 154.53 209.075 ;
     RECT  142.815 208.679 143.73 209.111 ;
     RECT  146.916 208.805 146.934 209.147 ;
     RECT  327.204 209.011 327.222 209.165 ;
     RECT  290.088 209.047 290.106 209.183 ;
     RECT  244.476 208.885 244.566 209.191 ;
     RECT  285.624 209.155 285.642 209.213 ;
     RECT  149.328 209.039 149.346 209.309 ;
     RECT  244.224 209.191 244.566 209.309 ;
     RECT  322.056 209.047 322.074 209.317 ;
     RECT  244.476 209.309 244.494 209.381 ;
     RECT  328.068 208.493 328.23 209.389 ;
     RECT  284.544 208.345 284.562 209.405 ;
     RECT  241.452 208.949 241.47 209.417 ;
     RECT  147.672 208.769 148.497 209.425 ;
     RECT  286.668 209.317 286.686 209.453 ;
     RECT  327.744 209.389 328.23 209.453 ;
     RECT  161.316 208.607 167.994 209.461 ;
     RECT  150.156 209.075 154.494 209.489 ;
     RECT  158.22 209.119 158.238 209.579 ;
     RECT  282.168 209.191 282.186 209.579 ;
     RECT  327.816 209.453 328.23 209.645 ;
     RECT  168.768 208.607 170.097 209.651 ;
     RECT  161.208 209.461 167.994 209.659 ;
     RECT  147.672 209.425 149.13 209.687 ;
     RECT  169.815 209.651 170.097 209.695 ;
     RECT  159.015 208.829 159.786 209.755 ;
     RECT  161.028 209.659 167.994 209.755 ;
     RECT  147.672 209.687 148.497 209.759 ;
     RECT  150.156 209.489 153.897 209.849 ;
     RECT  159.015 209.755 167.994 209.849 ;
     RECT  151.092 209.849 151.182 209.885 ;
     RECT  152.532 209.849 153.897 209.885 ;
     RECT  322.056 209.317 322.11 209.899 ;
     RECT  151.092 209.885 151.11 209.921 ;
     RECT  152.532 209.885 152.838 209.921 ;
     RECT  324.54 208.829 325.494 209.929 ;
     RECT  160.776 209.849 167.994 209.947 ;
     RECT  168.768 209.651 168.966 209.947 ;
     RECT  160.776 209.947 168.966 209.993 ;
     RECT  175.215 208.607 175.497 209.995 ;
     RECT  186.015 208.409 186.297 209.995 ;
     RECT  196.815 208.409 197.097 209.995 ;
     RECT  207.615 208.409 207.897 209.995 ;
     RECT  218.415 208.409 218.697 209.995 ;
     RECT  229.215 208.409 229.497 209.995 ;
     RECT  240.015 208.409 240.297 209.995 ;
     RECT  250.815 208.409 251.097 209.995 ;
     RECT  261.615 208.409 261.897 209.995 ;
     RECT  272.415 208.409 272.697 209.995 ;
     RECT  283.215 208.409 283.497 209.995 ;
     RECT  294.015 208.409 294.297 209.995 ;
     RECT  304.815 208.409 305.097 209.995 ;
     RECT  315.615 208.409 315.897 209.995 ;
     RECT  168.948 209.993 168.966 210.029 ;
     RECT  169.815 209.695 170.406 210.029 ;
     RECT  175.104 209.995 175.497 210.029 ;
     RECT  185.904 209.995 186.297 210.029 ;
     RECT  196.704 209.995 197.097 210.029 ;
     RECT  207.504 209.995 207.897 210.029 ;
     RECT  218.304 209.995 218.697 210.029 ;
     RECT  229.104 209.995 229.497 210.029 ;
     RECT  239.904 209.995 240.297 210.029 ;
     RECT  250.704 209.995 251.097 210.029 ;
     RECT  261.504 209.995 261.897 210.029 ;
     RECT  272.304 209.995 272.697 210.029 ;
     RECT  283.104 209.995 283.497 210.029 ;
     RECT  293.904 209.995 294.297 210.029 ;
     RECT  304.704 209.995 305.097 210.029 ;
     RECT  315.504 209.995 315.897 210.029 ;
     RECT  318.348 209.899 318.366 210.091 ;
     RECT  152.532 209.921 152.55 210.119 ;
     RECT  158.004 209.947 158.022 210.119 ;
     RECT  159.015 209.849 159.93 210.119 ;
     RECT  318.348 210.091 318.69 210.119 ;
     RECT  324.324 209.929 325.494 210.119 ;
     RECT  245.415 208.877 245.697 210.163 ;
     RECT  318.672 210.119 318.69 210.173 ;
     RECT  322.056 209.899 322.182 210.221 ;
     RECT  160.776 209.993 168.174 210.227 ;
     RECT  319.536 210.187 319.554 210.227 ;
     RECT  167.868 210.227 168.174 210.299 ;
     RECT  319.86 210.235 319.878 210.299 ;
     RECT  160.776 210.227 166.59 210.389 ;
     RECT  244.872 210.163 245.697 210.389 ;
     RECT  324.324 210.119 324.918 210.389 ;
     RECT  327.924 209.645 328.23 210.433 ;
     RECT  326.592 210.379 326.61 210.469 ;
     RECT  238.32 210.361 238.338 210.497 ;
     RECT  160.776 210.389 166.482 210.509 ;
     RECT  326.592 210.469 326.646 210.569 ;
     RECT  326.628 210.569 326.646 210.605 ;
     RECT  245.415 210.389 245.697 210.631 ;
     RECT  160.776 210.509 161.01 210.659 ;
     RECT  167.868 210.299 167.886 210.659 ;
     RECT  322.128 210.221 322.182 210.731 ;
     RECT  324.9 210.389 324.918 210.731 ;
     RECT  161.856 210.509 166.482 210.767 ;
     RECT  160.992 210.659 161.01 210.797 ;
     RECT  161.928 210.767 166.482 210.803 ;
     RECT  322.128 210.731 322.146 210.803 ;
     RECT  327.744 210.433 328.23 210.803 ;
     RECT  327.744 210.803 327.798 210.811 ;
     RECT  163.116 210.803 166.482 210.839 ;
     RECT  243.108 210.541 243.126 210.839 ;
     RECT  245.415 210.631 246.33 210.839 ;
     RECT  327.204 210.811 327.798 210.893 ;
     RECT  161.964 210.803 162.198 210.941 ;
     RECT  161.964 210.941 161.982 210.965 ;
     RECT  327.204 210.893 327.726 210.989 ;
     RECT  163.548 210.839 166.482 211.001 ;
     RECT  327.708 210.989 327.726 211.109 ;
     RECT  165.744 211.001 166.482 211.235 ;
     RECT  242.316 210.631 242.334 211.271 ;
     RECT  163.548 211.001 165.006 211.307 ;
     RECT  163.548 211.307 163.566 211.343 ;
     RECT  164.34 211.307 165.006 211.343 ;
     RECT  166.464 211.235 166.482 211.343 ;
     RECT  164.415 211.343 165.006 211.379 ;
     RECT  142.815 209.111 143.097 213.163 ;
     RECT  142.815 213.163 143.19 213.359 ;
     RECT  204.48 213.601 204.498 213.603 ;
     RECT  206.028 213.163 206.046 213.629 ;
     RECT  177.48 213.601 177.498 213.643 ;
     RECT  149.796 213.601 149.814 213.677 ;
     RECT  204.477 213.603 204.501 213.72 ;
     RECT  177.372 213.643 177.498 213.725 ;
     RECT  204.48 213.72 204.498 213.725 ;
     RECT  177.372 213.725 177.39 213.809 ;
     RECT  169.815 210.029 170.097 220.621 ;
     RECT  169.815 220.621 170.766 220.685 ;
     RECT  171.576 220.603 171.594 220.919 ;
     RECT  169.815 220.685 170.514 221.069 ;
     RECT  192.528 234.859 192.546 235.229 ;
     RECT  191.415 2.413 191.697 235.381 ;
     RECT  190.98 235.381 191.697 235.383 ;
     RECT  190.977 235.383 191.697 235.416 ;
     RECT  190.98 235.416 191.697 235.421 ;
     RECT  186.015 210.029 186.297 242.059 ;
     RECT  183.96 242.059 183.978 242.155 ;
     RECT  182.412 242.059 182.43 242.189 ;
     RECT  186.015 242.059 186.426 242.237 ;
     RECT  183.96 242.155 184.266 242.249 ;
     RECT  212.22 249.355 212.238 249.511 ;
     RECT  211.932 249.511 212.238 249.539 ;
     RECT  211.932 249.539 211.95 249.629 ;
     RECT  210.564 188.527 210.582 259.295 ;
     RECT  159.015 210.119 159.786 300.037 ;
     RECT  138.528 300.037 138.546 300.209 ;
     RECT  88.815 207.869 89.097 300.271 ;
     RECT  99.615 207.869 99.897 300.271 ;
     RECT  110.415 207.869 110.697 300.271 ;
     RECT  115.815 189.095 116.097 300.271 ;
     RECT  88.704 300.271 89.097 300.317 ;
     RECT  99.504 300.271 99.897 300.317 ;
     RECT  110.304 300.271 110.697 300.317 ;
     RECT  115.704 300.271 116.097 300.331 ;
     RECT  136.62 300.001 136.638 300.365 ;
     RECT  115.632 300.331 116.097 300.371 ;
     RECT  191.415 235.421 191.697 307.243 ;
     RECT  191.415 307.243 191.862 307.589 ;
     RECT  164.415 211.379 164.697 307.867 ;
     RECT  158.724 300.037 159.786 308.515 ;
     RECT  158.724 308.515 160.038 308.551 ;
     RECT  158.724 308.551 160.47 308.669 ;
     RECT  158.724 308.669 159.354 308.741 ;
     RECT  160.452 308.669 160.47 308.741 ;
     RECT  159.015 308.741 159.354 308.813 ;
     RECT  162.432 307.867 162.45 308.813 ;
     RECT  171.036 259.231 171.054 337.639 ;
     RECT  171.936 337.567 171.954 337.639 ;
     RECT  171.036 337.639 171.954 337.675 ;
     RECT  170.892 337.675 171.954 337.711 ;
     RECT  169.815 221.069 170.097 337.801 ;
     RECT  170.892 337.711 172.17 337.801 ;
     RECT  169.815 337.801 172.17 337.829 ;
     RECT  169.815 337.829 171.45 337.949 ;
     RECT  168.552 337.945 168.57 338.099 ;
     RECT  167.688 338.071 167.706 338.179 ;
     RECT  167.688 338.179 168.246 338.251 ;
     RECT  167.292 338.251 168.246 338.285 ;
     RECT  171.432 337.949 171.45 338.441 ;
     RECT  167.688 338.285 168.246 339.151 ;
     RECT  167.58 339.151 168.246 339.295 ;
     RECT  167.22 339.295 168.246 339.331 ;
     RECT  167.22 339.331 168.426 339.341 ;
     RECT  167.58 339.341 168.426 339.521 ;
     RECT  167.976 339.521 168.426 339.601 ;
     RECT  167.976 339.601 168.498 340.141 ;
     RECT  167.976 340.141 169.038 340.259 ;
     RECT  169.815 337.949 170.406 340.411 ;
     RECT  167.976 340.259 168.57 340.537 ;
     RECT  167.112 340.375 167.13 340.589 ;
     RECT  167.904 340.537 168.57 340.681 ;
     RECT  167.256 340.681 168.57 340.835 ;
     RECT  167.256 340.835 168.21 341.069 ;
     RECT  167.328 341.069 168.21 341.653 ;
     RECT  167.328 341.653 168.246 342.193 ;
     RECT  167.328 342.193 168.282 342.265 ;
     RECT  167.328 342.265 168.462 342.301 ;
     RECT  167.328 342.301 168.57 342.661 ;
     RECT  169.815 340.411 170.622 342.725 ;
     RECT  169.815 342.725 170.406 342.733 ;
     RECT  167.184 342.661 168.57 342.805 ;
     RECT  167.184 342.805 168.642 342.841 ;
     RECT  167.184 342.841 168.786 342.931 ;
     RECT  169.596 342.733 170.406 342.931 ;
     RECT  167.184 342.931 170.406 343.195 ;
     RECT  166.536 343.195 170.406 343.229 ;
     RECT  166.68 343.229 170.406 343.409 ;
     RECT  166.68 343.409 169.002 343.499 ;
     RECT  169.815 343.409 170.406 343.679 ;
     RECT  167.328 343.499 169.002 344.191 ;
     RECT  169.815 343.679 170.097 344.191 ;
     RECT  167.328 344.191 170.097 344.489 ;
     RECT  167.328 344.489 168.894 344.723 ;
     RECT  167.436 344.723 168.894 344.849 ;
     RECT  167.868 344.849 168.894 345.119 ;
     RECT  168.12 345.119 168.894 345.263 ;
     RECT  168.876 345.263 168.894 345.271 ;
     RECT  169.74 344.489 170.097 345.271 ;
     RECT  168.876 345.271 168.93 345.541 ;
     RECT  169.668 345.271 170.097 345.541 ;
     RECT  168.12 345.263 168.138 351.481 ;
     RECT  168.876 345.541 170.097 351.481 ;
     RECT  168.12 351.481 170.097 351.509 ;
     RECT  168.408 351.509 170.097 358.457 ;
     RECT  168.552 358.457 170.097 365.279 ;
     RECT  164.232 307.867 164.697 368.339 ;
     RECT  168.84 365.279 170.097 368.761 ;
     RECT  168.768 368.761 170.097 368.915 ;
     RECT  2.415 207.917 2.697 369.107 ;
     RECT  7.815 2.413 8.097 369.107 ;
     RECT  13.215 207.869 13.497 369.107 ;
     RECT  18.615 2.413 18.897 369.107 ;
     RECT  24.015 207.869 24.297 369.107 ;
     RECT  29.415 2.413 29.697 369.107 ;
     RECT  34.815 207.869 35.097 369.107 ;
     RECT  40.215 2.413 40.497 369.107 ;
     RECT  45.615 207.869 45.897 369.107 ;
     RECT  51.015 2.413 51.297 369.107 ;
     RECT  56.415 207.869 56.697 369.107 ;
     RECT  61.815 206.339 62.097 369.107 ;
     RECT  67.215 207.869 67.497 369.107 ;
     RECT  72.615 2.413 72.897 369.107 ;
     RECT  78.015 207.869 78.297 369.107 ;
     RECT  83.415 186.653 83.697 369.107 ;
     RECT  88.815 300.317 89.097 369.107 ;
     RECT  94.215 187.439 94.497 369.107 ;
     RECT  99.615 300.317 99.897 369.107 ;
     RECT  105.015 189.743 105.297 369.107 ;
     RECT  110.415 300.317 110.697 369.107 ;
     RECT  115.815 300.371 116.097 369.107 ;
     RECT  121.215 207.869 121.497 369.107 ;
     RECT  126.615 188.627 126.897 369.107 ;
     RECT  132.015 207.869 132.297 369.107 ;
     RECT  137.415 203.945 137.697 369.107 ;
     RECT  142.815 213.359 143.097 369.107 ;
     RECT  148.215 209.759 148.497 369.107 ;
     RECT  153.615 209.885 153.897 369.107 ;
     RECT  159.015 308.813 159.297 369.107 ;
     RECT  164.415 368.339 164.697 369.107 ;
     RECT  168.876 368.915 170.097 369.107 ;
     RECT  175.215 210.029 175.497 369.107 ;
     RECT  180.615 173.129 180.897 369.107 ;
     RECT  186.015 242.237 186.297 369.107 ;
     RECT  191.415 307.589 191.697 369.107 ;
     RECT  196.815 210.029 197.097 369.107 ;
     RECT  202.215 185.357 202.497 369.107 ;
     RECT  207.615 210.029 207.897 369.107 ;
     RECT  213.015 188.051 213.297 369.107 ;
     RECT  218.415 210.029 218.697 369.107 ;
     RECT  223.815 2.413 224.097 369.107 ;
     RECT  229.215 210.029 229.497 369.107 ;
     RECT  234.615 198.311 234.897 369.107 ;
     RECT  240.015 210.029 240.297 369.107 ;
     RECT  245.415 210.839 245.697 369.107 ;
     RECT  250.815 210.029 251.097 369.107 ;
     RECT  256.215 171.077 256.497 369.107 ;
     RECT  261.615 210.029 261.897 369.107 ;
     RECT  267.015 186.125 267.297 369.107 ;
     RECT  272.415 210.029 272.697 369.107 ;
     RECT  277.815 187.817 278.097 369.107 ;
     RECT  283.215 210.029 283.497 369.107 ;
     RECT  288.615 176.783 288.897 369.107 ;
     RECT  294.015 210.029 294.297 369.107 ;
     RECT  299.415 187.043 299.697 369.107 ;
     RECT  304.815 210.029 305.097 369.107 ;
     RECT  310.215 188.663 310.497 369.107 ;
     RECT  315.615 210.029 315.897 369.107 ;
     RECT  321.015 191.867 321.297 369.107 ;
     RECT  2.415 369.107 2.505 369.377 ;
     RECT  7.815 369.107 7.905 369.377 ;
     RECT  13.215 369.107 13.305 369.377 ;
     RECT  18.615 369.107 18.705 369.377 ;
     RECT  24.015 369.107 24.105 369.377 ;
     RECT  29.415 369.107 29.505 369.377 ;
     RECT  34.815 369.107 34.905 369.377 ;
     RECT  40.215 369.107 40.305 369.377 ;
     RECT  45.615 369.107 45.705 369.377 ;
     RECT  51.015 369.107 51.105 369.377 ;
     RECT  56.415 369.107 56.505 369.377 ;
     RECT  61.815 369.107 61.905 369.377 ;
     RECT  67.215 369.107 67.305 369.377 ;
     RECT  72.615 369.107 72.705 369.377 ;
     RECT  78.015 369.107 78.105 369.377 ;
     RECT  83.415 369.107 83.505 369.377 ;
     RECT  88.815 369.107 88.905 369.377 ;
     RECT  94.215 369.107 94.305 369.377 ;
     RECT  99.615 369.107 99.705 369.377 ;
     RECT  105.015 369.107 105.105 369.377 ;
     RECT  110.415 369.107 110.505 369.377 ;
     RECT  115.815 369.107 115.905 369.377 ;
     RECT  121.215 369.107 121.305 369.377 ;
     RECT  126.615 369.107 126.705 369.377 ;
     RECT  132.015 369.107 132.105 369.377 ;
     RECT  137.415 369.107 137.505 369.377 ;
     RECT  142.815 369.107 142.905 369.377 ;
     RECT  148.215 369.107 148.305 369.377 ;
     RECT  153.615 369.107 153.705 369.377 ;
     RECT  159.015 369.107 159.105 369.377 ;
     RECT  164.415 369.107 164.505 369.377 ;
     RECT  168.876 369.107 169.905 369.377 ;
     RECT  175.215 369.107 175.305 369.377 ;
     RECT  180.615 369.107 180.705 369.377 ;
     RECT  186.015 369.107 186.105 369.377 ;
     RECT  191.415 369.107 191.505 369.377 ;
     RECT  196.815 369.107 196.905 369.377 ;
     RECT  202.215 369.107 202.305 369.377 ;
     RECT  207.615 369.107 207.705 369.377 ;
     RECT  213.015 369.107 213.105 369.377 ;
     RECT  218.415 369.107 218.505 369.377 ;
     RECT  223.815 369.107 223.905 369.377 ;
     RECT  229.215 369.107 229.305 369.377 ;
     RECT  234.615 369.107 234.705 369.377 ;
     RECT  240.015 369.107 240.105 369.377 ;
     RECT  245.415 369.107 245.505 369.377 ;
     RECT  250.815 369.107 250.905 369.377 ;
     RECT  256.215 369.107 256.305 369.377 ;
     RECT  261.615 369.107 261.705 369.377 ;
     RECT  267.015 369.107 267.105 369.377 ;
     RECT  272.415 369.107 272.505 369.377 ;
     RECT  277.815 369.107 277.905 369.377 ;
     RECT  283.215 369.107 283.305 369.377 ;
     RECT  288.615 369.107 288.705 369.377 ;
     RECT  294.015 369.107 294.105 369.377 ;
     RECT  299.415 369.107 299.505 369.377 ;
     RECT  304.815 369.107 304.905 369.377 ;
     RECT  310.215 369.107 310.305 369.377 ;
     RECT  315.615 369.107 315.705 369.377 ;
     RECT  321.015 369.107 321.105 369.377 ;
     RECT  168.876 369.377 169.182 370.445 ;
     RECT  168.876 370.445 168.894 370.493 ;
    LAYER M4 ;
     RECT  0.06 186.96 0.097 188.712 ;
     RECT  0.097 186.96 0.133 188.856 ;
     RECT  0.06 160.368 0.389 175.656 ;
     RECT  0.06 201.84 0.533 207.912 ;
     RECT  0.533 201.84 0.569 203.784 ;
     RECT  0.533 204.912 0.569 207.912 ;
     RECT  0.389 160.368 2.408 175.608 ;
     RECT  0.06 182.64 2.408 185.64 ;
     RECT  0.133 186.912 2.408 188.856 ;
     RECT  0.06 191.856 2.408 194.856 ;
     RECT  0.569 202.032 2.408 203.784 ;
     RECT  0.569 205.056 2.408 207.912 ;
     RECT  2.408 2.148 2.512 369.372 ;
     RECT  2.512 2.418 2.704 369.102 ;
     RECT  2.704 186.768 3.733 188.856 ;
     RECT  2.704 160.32 7.808 175.608 ;
     RECT  2.704 182.64 7.808 185.64 ;
     RECT  3.733 186.624 7.808 188.856 ;
     RECT  2.704 191.856 7.808 194.856 ;
     RECT  2.704 202.032 7.808 203.784 ;
     RECT  2.704 205.056 7.808 207.864 ;
     RECT  7.808 2.148 7.912 369.372 ;
     RECT  7.912 2.418 8.104 369.102 ;
     RECT  8.104 160.32 13.208 175.608 ;
     RECT  8.104 182.64 13.208 185.64 ;
     RECT  8.104 186.624 13.208 188.856 ;
     RECT  8.104 191.856 13.208 194.856 ;
     RECT  8.104 202.032 13.208 203.784 ;
     RECT  8.104 205.056 13.208 207.864 ;
     RECT  13.208 2.148 13.312 369.372 ;
     RECT  13.312 2.418 13.504 369.102 ;
     RECT  13.504 160.32 18.608 175.608 ;
     RECT  13.504 182.64 18.608 185.64 ;
     RECT  13.504 186.624 18.608 188.856 ;
     RECT  13.504 191.856 18.608 194.856 ;
     RECT  13.504 202.032 18.608 203.784 ;
     RECT  13.504 205.056 18.608 207.864 ;
     RECT  18.608 2.148 18.712 369.372 ;
     RECT  18.712 2.418 18.904 369.102 ;
     RECT  18.904 160.32 24.008 175.608 ;
     RECT  18.904 182.64 24.008 185.64 ;
     RECT  18.904 186.624 24.008 188.856 ;
     RECT  18.904 191.856 24.008 194.856 ;
     RECT  18.904 202.032 24.008 203.784 ;
     RECT  18.904 205.056 24.008 207.864 ;
     RECT  24.008 2.148 24.112 369.372 ;
     RECT  24.112 2.418 24.304 369.102 ;
     RECT  24.304 160.32 29.408 175.608 ;
     RECT  24.304 182.64 29.408 185.64 ;
     RECT  24.304 186.624 29.408 188.856 ;
     RECT  24.304 191.856 29.408 194.856 ;
     RECT  24.304 202.032 29.408 203.784 ;
     RECT  24.304 205.056 29.408 207.864 ;
     RECT  29.408 2.148 29.512 369.372 ;
     RECT  29.512 2.418 29.704 369.102 ;
     RECT  29.704 160.32 34.808 175.608 ;
     RECT  29.704 182.64 34.808 185.64 ;
     RECT  29.704 186.624 34.808 188.856 ;
     RECT  29.704 191.856 34.808 194.856 ;
     RECT  29.704 202.032 34.808 203.784 ;
     RECT  29.704 205.056 34.808 207.864 ;
     RECT  34.808 2.148 34.912 369.372 ;
     RECT  34.912 2.418 35.104 369.102 ;
     RECT  35.104 160.32 40.208 175.608 ;
     RECT  35.104 182.64 40.208 185.64 ;
     RECT  35.104 186.624 40.208 188.856 ;
     RECT  35.104 191.856 40.208 194.856 ;
     RECT  35.104 202.032 40.208 203.784 ;
     RECT  35.104 205.056 40.208 207.864 ;
     RECT  40.208 2.148 40.312 369.372 ;
     RECT  40.312 2.418 40.504 369.102 ;
     RECT  40.504 160.32 45.608 175.608 ;
     RECT  40.504 182.64 45.608 185.64 ;
     RECT  40.504 186.624 45.608 188.856 ;
     RECT  40.504 191.856 45.608 194.856 ;
     RECT  40.504 202.032 45.608 203.784 ;
     RECT  40.504 205.056 45.608 207.864 ;
     RECT  45.608 2.148 45.712 369.372 ;
     RECT  45.712 2.418 45.904 369.102 ;
     RECT  45.904 160.32 51.008 175.608 ;
     RECT  45.904 182.64 51.008 185.64 ;
     RECT  45.904 186.624 51.008 188.856 ;
     RECT  45.904 191.856 51.008 194.856 ;
     RECT  45.904 202.032 51.008 203.784 ;
     RECT  45.904 205.056 51.008 207.864 ;
     RECT  51.008 2.148 51.112 369.372 ;
     RECT  51.112 2.418 51.304 369.102 ;
     RECT  51.304 160.32 56.408 175.608 ;
     RECT  51.304 182.64 56.408 185.64 ;
     RECT  51.304 186.624 56.408 188.856 ;
     RECT  51.304 191.856 56.408 194.856 ;
     RECT  51.304 202.032 56.408 203.784 ;
     RECT  51.304 205.056 56.408 207.864 ;
     RECT  56.408 2.148 56.512 369.372 ;
     RECT  56.512 2.418 56.704 369.102 ;
     RECT  56.704 160.32 61.808 175.608 ;
     RECT  56.704 182.64 61.808 185.64 ;
     RECT  56.704 186.624 61.808 188.856 ;
     RECT  56.704 191.856 61.808 194.856 ;
     RECT  56.704 202.032 61.808 203.784 ;
     RECT  56.704 205.056 61.808 207.864 ;
     RECT  61.808 2.148 61.912 369.372 ;
     RECT  61.912 2.418 62.104 369.102 ;
     RECT  62.104 160.32 67.208 175.608 ;
     RECT  62.104 182.64 67.208 185.64 ;
     RECT  62.104 186.624 67.208 188.856 ;
     RECT  62.104 191.856 67.208 194.856 ;
     RECT  62.104 202.032 67.208 203.784 ;
     RECT  62.104 205.056 67.208 207.864 ;
     RECT  67.208 2.148 67.312 369.372 ;
     RECT  67.312 2.418 67.504 369.102 ;
     RECT  67.504 160.32 72.608 175.608 ;
     RECT  67.504 182.64 72.608 185.64 ;
     RECT  67.504 186.624 72.608 188.856 ;
     RECT  67.504 191.856 72.608 194.856 ;
     RECT  67.504 202.032 72.608 203.784 ;
     RECT  67.504 205.056 72.608 207.864 ;
     RECT  72.608 2.148 72.712 369.372 ;
     RECT  72.712 2.418 72.904 369.102 ;
     RECT  72.904 186.624 76.813 188.856 ;
     RECT  76.813 186.624 76.883 189 ;
     RECT  72.904 160.32 78.008 175.608 ;
     RECT  72.904 182.64 78.008 185.64 ;
     RECT  76.883 186.624 78.008 188.856 ;
     RECT  72.904 191.856 78.008 194.856 ;
     RECT  72.904 202.032 78.008 203.784 ;
     RECT  72.904 205.056 78.008 207.864 ;
     RECT  76.837 300.144 78.008 300.168 ;
     RECT  78.008 2.148 78.112 369.372 ;
     RECT  78.112 2.418 78.304 369.102 ;
     RECT  78.304 182.64 82.249 185.64 ;
     RECT  78.304 186.624 82.249 188.568 ;
     RECT  78.304 160.32 83.408 175.608 ;
     RECT  82.249 182.64 83.408 188.568 ;
     RECT  78.304 191.856 83.408 194.856 ;
     RECT  78.304 202.032 83.408 203.784 ;
     RECT  78.304 205.056 83.408 207.864 ;
     RECT  78.304 300.288 83.408 300.312 ;
     RECT  83.408 2.148 83.512 369.372 ;
     RECT  83.512 2.418 83.704 369.102 ;
     RECT  83.704 160.32 88.808 175.608 ;
     RECT  83.704 182.64 88.808 188.568 ;
     RECT  83.704 191.856 88.808 194.856 ;
     RECT  83.704 202.032 88.808 203.784 ;
     RECT  83.704 205.056 88.808 207.864 ;
     RECT  83.704 300.288 88.808 300.312 ;
     RECT  88.808 2.148 88.912 369.372 ;
     RECT  88.912 2.418 89.104 369.102 ;
     RECT  89.104 160.32 94.208 175.608 ;
     RECT  89.104 182.64 94.208 188.568 ;
     RECT  89.104 191.856 94.208 194.856 ;
     RECT  89.104 202.032 94.208 203.784 ;
     RECT  89.104 205.056 94.208 207.864 ;
     RECT  89.104 300.288 94.208 300.312 ;
     RECT  94.208 2.148 94.312 369.372 ;
     RECT  94.312 2.418 94.504 369.102 ;
     RECT  94.504 182.64 98.593 188.568 ;
     RECT  94.504 160.32 99.608 175.608 ;
     RECT  98.593 182.64 99.608 188.616 ;
     RECT  94.504 191.856 99.608 194.856 ;
     RECT  94.504 202.032 99.608 203.784 ;
     RECT  94.504 205.056 99.608 207.864 ;
     RECT  94.504 300.288 99.608 300.312 ;
     RECT  99.608 2.148 99.712 369.372 ;
     RECT  99.712 2.418 99.904 369.102 ;
     RECT  99.904 182.64 102.037 188.568 ;
     RECT  102.037 182.64 102.517 188.808 ;
     RECT  102.517 182.352 102.563 188.808 ;
     RECT  102.563 182.64 103.705 188.808 ;
     RECT  103.705 182.64 104.821 189.144 ;
     RECT  99.904 160.32 105.008 175.608 ;
     RECT  104.821 182.64 105.008 189.288 ;
     RECT  99.904 191.856 105.008 194.856 ;
     RECT  99.904 202.032 105.008 203.784 ;
     RECT  99.904 205.056 105.008 207.864 ;
     RECT  99.904 300.288 105.008 300.312 ;
     RECT  105.008 2.148 105.112 369.372 ;
     RECT  105.112 2.418 105.304 369.102 ;
     RECT  105.304 182.64 105.473 189.144 ;
     RECT  105.473 183.936 105.545 189.144 ;
     RECT  105.545 183.936 105.761 188.712 ;
     RECT  105.761 183.936 106.301 188.664 ;
     RECT  105.473 182.64 107.377 182.712 ;
     RECT  106.301 183.936 107.377 188.568 ;
     RECT  107.377 182.64 107.413 188.568 ;
     RECT  107.413 182.64 108.857 189.336 ;
     RECT  108.857 183.744 109.181 189.336 ;
     RECT  109.181 183.744 109.427 189.288 ;
     RECT  108.857 182.64 110.041 182.712 ;
     RECT  109.427 183.744 110.041 188.568 ;
     RECT  105.304 160.32 110.408 175.608 ;
     RECT  110.041 182.64 110.408 188.568 ;
     RECT  105.304 191.856 110.408 194.856 ;
     RECT  105.304 202.032 110.408 203.784 ;
     RECT  105.304 205.056 110.408 207.864 ;
     RECT  105.304 300.288 110.408 300.312 ;
     RECT  110.408 2.148 110.512 369.372 ;
     RECT  110.512 2.418 110.704 369.102 ;
     RECT  110.704 182.64 111.913 188.808 ;
     RECT  111.913 182.64 111.971 189.192 ;
     RECT  111.971 182.64 112.787 189.144 ;
     RECT  112.787 184.368 112.883 189.144 ;
     RECT  112.883 184.368 114.565 188.808 ;
     RECT  110.704 300.288 115.621 300.312 ;
     RECT  110.704 160.32 115.808 175.608 ;
     RECT  112.787 182.64 115.808 182.664 ;
     RECT  114.565 184.368 115.808 188.904 ;
     RECT  110.704 191.856 115.808 194.856 ;
     RECT  110.704 202.032 115.808 203.784 ;
     RECT  110.704 205.056 115.808 207.864 ;
     RECT  115.621 300.288 115.808 300.36 ;
     RECT  115.808 2.148 115.912 369.372 ;
     RECT  115.912 2.418 116.104 369.102 ;
     RECT  116.104 184.56 116.309 188.664 ;
     RECT  116.309 184.56 118.069 188.616 ;
     RECT  118.069 184.56 119.077 188.664 ;
     RECT  119.077 184.08 119.761 188.664 ;
     RECT  119.761 184.08 119.843 188.76 ;
     RECT  116.104 160.32 121.208 175.608 ;
     RECT  116.104 182.64 121.208 182.664 ;
     RECT  119.843 184.08 121.208 188.664 ;
     RECT  116.104 191.856 121.208 194.856 ;
     RECT  116.104 202.032 121.208 203.784 ;
     RECT  116.104 205.056 121.208 207.864 ;
     RECT  116.104 300.336 121.208 300.36 ;
     RECT  121.208 2.148 121.312 369.372 ;
     RECT  121.312 2.418 121.504 369.102 ;
     RECT  121.504 183.744 123.037 188.04 ;
     RECT  123.037 183.744 124.373 188.088 ;
     RECT  124.373 185.28 124.481 188.088 ;
     RECT  124.481 185.28 124.841 188.04 ;
     RECT  121.504 182.64 125.029 182.664 ;
     RECT  124.373 183.744 125.029 184.296 ;
     RECT  124.841 185.328 125.629 188.04 ;
     RECT  125.029 182.64 126.025 184.296 ;
     RECT  125.629 185.328 126.025 188.136 ;
     RECT  121.504 202.032 126.229 203.784 ;
     RECT  121.504 205.056 126.229 207.864 ;
     RECT  121.504 160.32 126.608 175.608 ;
     RECT  126.025 182.64 126.608 188.136 ;
     RECT  121.504 191.856 126.608 194.856 ;
     RECT  126.229 202.032 126.608 207.864 ;
     RECT  121.504 300.336 126.608 300.36 ;
     RECT  126.608 2.148 126.712 369.372 ;
     RECT  126.712 2.418 126.904 369.102 ;
     RECT  126.904 160.32 132.008 175.608 ;
     RECT  126.904 182.64 132.008 188.04 ;
     RECT  126.904 191.856 132.008 194.856 ;
     RECT  126.904 202.032 132.008 207.864 ;
     RECT  126.904 300.336 132.008 300.36 ;
     RECT  132.008 2.148 132.112 369.372 ;
     RECT  132.112 2.418 132.304 369.102 ;
     RECT  132.304 160.32 137.408 175.608 ;
     RECT  132.304 182.64 137.408 188.04 ;
     RECT  132.304 191.856 137.408 194.856 ;
     RECT  132.304 202.032 137.408 207.864 ;
     RECT  132.304 300.336 137.408 300.36 ;
     RECT  137.408 2.148 137.512 369.372 ;
     RECT  137.512 2.418 137.704 369.102 ;
     RECT  137.704 182.64 140.483 188.04 ;
     RECT  137.704 202.032 140.821 207.864 ;
     RECT  140.821 202.032 141.505 208.008 ;
     RECT  137.704 160.32 142.808 175.608 ;
     RECT  140.483 182.64 142.808 182.664 ;
     RECT  140.483 184.272 142.808 188.04 ;
     RECT  137.704 191.856 142.808 194.856 ;
     RECT  141.505 202.032 142.808 208.392 ;
     RECT  142.808 2.148 142.912 369.372 ;
     RECT  142.912 2.418 143.104 369.102 ;
     RECT  143.104 160.32 143.201 175.608 ;
     RECT  143.104 213.168 143.219 213.384 ;
     RECT  143.104 202.032 144.817 208.152 ;
     RECT  143.201 160.32 145.069 163.416 ;
     RECT  143.201 164.448 145.069 175.608 ;
     RECT  144.817 202.032 145.069 208.296 ;
     RECT  145.069 202.032 146.441 208.536 ;
     RECT  145.069 160.32 146.837 175.608 ;
     RECT  146.837 162.096 147.053 175.608 ;
     RECT  147.053 162.192 147.161 175.608 ;
     RECT  147.161 162.624 148.129 175.608 ;
     RECT  146.837 160.32 148.208 160.872 ;
     RECT  148.129 161.904 148.208 175.608 ;
     RECT  143.104 182.64 148.208 182.664 ;
     RECT  143.104 184.272 148.208 188.04 ;
     RECT  143.104 191.856 148.208 194.856 ;
     RECT  143.104 198.336 148.208 198.36 ;
     RECT  146.441 202.032 148.208 208.296 ;
     RECT  143.219 213.36 148.208 213.384 ;
     RECT  148.208 2.148 148.312 369.372 ;
     RECT  148.312 2.418 148.504 369.102 ;
     RECT  148.504 213.648 148.643 213.72 ;
     RECT  148.504 202.032 148.817 208.296 ;
     RECT  148.817 202.032 149.609 208.2 ;
     RECT  148.504 160.848 149.933 175.608 ;
     RECT  149.609 202.08 149.965 208.2 ;
     RECT  150.145 209.664 150.469 209.688 ;
     RECT  149.965 202.08 150.505 208.296 ;
     RECT  150.469 209.664 150.505 209.784 ;
     RECT  149.933 160.848 150.509 161.016 ;
     RECT  148.504 191.856 150.997 194.856 ;
     RECT  150.505 202.08 151.043 209.784 ;
     RECT  149.933 162.48 151.261 175.608 ;
     RECT  151.261 162.336 151.769 175.608 ;
     RECT  150.509 160.992 151.873 161.016 ;
     RECT  151.981 197.28 152.125 197.304 ;
     RECT  151.769 162.336 152.129 171.96 ;
     RECT  148.504 198.336 152.197 198.36 ;
     RECT  151.837 200.592 152.197 200.616 ;
     RECT  151.769 173.28 152.237 175.608 ;
     RECT  151.043 202.08 152.243 209.688 ;
     RECT  152.197 198.336 152.437 198.936 ;
     RECT  148.504 184.272 152.557 188.04 ;
     RECT  152.125 196.32 152.557 197.304 ;
     RECT  152.437 198.336 152.557 199.416 ;
     RECT  152.197 200.592 152.557 200.856 ;
     RECT  152.243 202.224 152.725 209.688 ;
     RECT  151.873 160.992 152.737 161.304 ;
     RECT  152.129 162.336 152.737 171.912 ;
     RECT  150.997 191.856 152.989 195.288 ;
     RECT  152.557 196.32 152.989 200.856 ;
     RECT  152.737 160.992 153.313 171.912 ;
     RECT  152.237 174.624 153.457 175.608 ;
     RECT  153.313 160.704 153.608 171.912 ;
     RECT  152.237 173.28 153.608 173.304 ;
     RECT  153.457 174.624 153.608 176.328 ;
     RECT  153.385 177.456 153.608 177.48 ;
     RECT  148.504 182.64 153.608 182.664 ;
     RECT  152.557 184.272 153.608 188.088 ;
     RECT  152.989 191.856 153.608 200.856 ;
     RECT  152.725 202.224 153.608 209.976 ;
     RECT  148.643 213.648 153.608 213.672 ;
     RECT  148.504 220.656 153.608 220.68 ;
     RECT  153.608 2.148 153.712 369.372 ;
     RECT  153.712 2.418 153.904 369.102 ;
     RECT  153.904 174.624 154.163 175.752 ;
     RECT  153.904 173.28 154.211 173.304 ;
     RECT  153.904 176.928 154.397 177.768 ;
     RECT  153.904 160.608 154.451 172.152 ;
     RECT  153.904 200.784 154.541 209.976 ;
     RECT  154.163 174.624 154.613 175.608 ;
     RECT  153.904 191.856 154.901 195.336 ;
     RECT  154.897 181.248 154.933 181.272 ;
     RECT  153.904 182.64 154.933 182.664 ;
     RECT  154.933 181.248 154.979 182.664 ;
     RECT  153.904 196.656 154.981 199.32 ;
     RECT  153.904 184.272 155.077 188.04 ;
     RECT  155.077 184.224 155.257 188.04 ;
     RECT  154.397 176.928 155.369 176.952 ;
     RECT  154.901 191.856 155.369 195.288 ;
     RECT  155.257 184.224 155.401 188.664 ;
     RECT  154.979 181.824 155.557 182.664 ;
     RECT  155.401 183.696 155.557 188.664 ;
     RECT  155.473 176.976 155.617 177.096 ;
     RECT  154.981 196.608 155.833 199.32 ;
     RECT  154.541 200.784 155.833 208.296 ;
     RECT  155.833 196.608 155.837 208.296 ;
     RECT  155.557 181.824 155.869 188.664 ;
     RECT  155.869 181.824 155.893 189 ;
     RECT  153.904 179.088 155.905 179.592 ;
     RECT  155.893 181.824 155.939 189.864 ;
     RECT  154.451 160.608 156.013 171.96 ;
     RECT  156.013 160.608 156.121 172.152 ;
     RECT  156.085 173.136 156.121 173.16 ;
     RECT  155.939 181.824 156.181 188.136 ;
     RECT  155.905 179.088 156.269 180.264 ;
     RECT  155.369 193.632 156.445 195.288 ;
     RECT  155.837 196.608 156.445 197.208 ;
     RECT  156.269 179.568 156.593 180.264 ;
     RECT  156.593 180.048 156.757 180.264 ;
     RECT  156.181 181.248 156.757 188.136 ;
     RECT  156.121 160.608 156.773 173.304 ;
     RECT  156.757 180.048 156.803 188.136 ;
     RECT  156.445 193.632 156.805 197.208 ;
     RECT  155.369 191.856 156.841 192.6 ;
     RECT  155.939 189.84 156.845 189.864 ;
     RECT  156.841 190.896 156.899 192.6 ;
     RECT  156.773 160.704 156.913 173.304 ;
     RECT  156.803 180.048 156.917 181.128 ;
     RECT  156.805 193.632 156.917 197.4 ;
     RECT  156.913 160.704 156.985 173.496 ;
     RECT  154.613 174.624 156.985 175.32 ;
     RECT  156.917 180.192 157.097 181.128 ;
     RECT  156.917 196.512 157.165 197.4 ;
     RECT  155.837 198.384 157.165 208.296 ;
     RECT  155.617 176.976 157.349 177.816 ;
     RECT  157.349 176.976 157.385 177.24 ;
     RECT  156.803 182.16 157.417 188.136 ;
     RECT  157.385 177.216 157.421 177.24 ;
     RECT  157.165 196.512 157.523 208.296 ;
     RECT  157.417 182.16 157.571 188.664 ;
     RECT  156.985 160.704 157.601 175.32 ;
     RECT  157.571 182.208 157.633 188.664 ;
     RECT  157.633 182.208 157.667 189.24 ;
     RECT  157.523 196.704 157.705 208.296 ;
     RECT  154.541 209.328 157.705 209.976 ;
     RECT  157.097 180.192 157.709 180.216 ;
     RECT  157.667 182.208 157.715 182.424 ;
     RECT  157.667 183.504 157.885 189.24 ;
     RECT  157.705 196.704 158.033 209.976 ;
     RECT  156.899 191.328 158.209 192.6 ;
     RECT  157.601 160.992 158.245 175.32 ;
     RECT  156.917 193.632 158.281 195.288 ;
     RECT  157.885 183.504 158.353 189.864 ;
     RECT  158.209 190.848 158.353 192.6 ;
     RECT  153.904 213.648 158.485 213.672 ;
     RECT  158.281 193.632 158.569 195.72 ;
     RECT  158.033 196.704 158.569 209.352 ;
     RECT  157.715 182.304 158.869 182.424 ;
     RECT  158.353 183.504 158.869 192.6 ;
     RECT  158.245 160.992 159.008 175.512 ;
     RECT  158.437 176.64 159.008 176.664 ;
     RECT  158.869 182.304 159.008 192.6 ;
     RECT  158.569 193.632 159.008 209.352 ;
     RECT  158.485 213.168 159.008 213.672 ;
     RECT  153.904 220.656 159.008 220.68 ;
     RECT  159.008 2.148 159.112 369.372 ;
     RECT  159.112 2.418 159.304 369.102 ;
     RECT  159.304 182.304 159.473 208.824 ;
     RECT  159.304 160.992 159.587 174.456 ;
     RECT  159.473 191.52 159.617 208.824 ;
     RECT  159.617 191.52 159.977 199.32 ;
     RECT  159.977 191.52 160.085 193.656 ;
     RECT  159.977 194.64 160.121 199.32 ;
     RECT  159.587 160.992 160.193 174.264 ;
     RECT  160.193 160.992 160.265 174.024 ;
     RECT  160.265 160.992 160.333 172.344 ;
     RECT  160.265 173.952 160.445 174.024 ;
     RECT  160.121 194.736 160.445 199.32 ;
     RECT  160.333 160.128 160.451 172.344 ;
     RECT  159.304 213.168 160.453 213.192 ;
     RECT  159.617 200.4 160.477 208.824 ;
     RECT  159.304 210.336 160.477 210.36 ;
     RECT  160.445 195.504 160.499 199.32 ;
     RECT  159.473 182.304 160.553 190.536 ;
     RECT  160.499 196.752 160.553 199.32 ;
     RECT  160.085 192.48 160.589 193.656 ;
     RECT  160.553 196.992 160.595 199.32 ;
     RECT  160.499 195.504 160.805 195.528 ;
     RECT  160.477 200.4 160.981 210.36 ;
     RECT  160.589 193.344 160.985 193.656 ;
     RECT  160.595 197.04 160.985 199.32 ;
     RECT  160.985 198.288 161.197 199.32 ;
     RECT  160.981 200.4 161.197 210.792 ;
     RECT  160.985 193.344 161.201 193.368 ;
     RECT  160.553 182.304 161.315 188.808 ;
     RECT  161.315 182.304 161.345 182.952 ;
     RECT  160.451 160.992 161.413 172.344 ;
     RECT  161.413 160.704 161.629 172.344 ;
     RECT  161.161 159.024 161.701 159.048 ;
     RECT  161.701 159.024 161.737 159.192 ;
     RECT  161.737 159.024 161.845 159.288 ;
     RECT  161.629 160.512 161.845 172.344 ;
     RECT  161.197 198.288 161.845 210.792 ;
     RECT  161.315 184.08 161.849 188.808 ;
     RECT  160.985 197.04 161.953 197.208 ;
     RECT  161.845 198.288 161.953 210.936 ;
     RECT  161.953 197.04 162.209 210.936 ;
     RECT  161.845 159.024 162.385 159.336 ;
     RECT  162.385 158.736 162.421 159.336 ;
     RECT  161.845 160.464 162.421 172.344 ;
     RECT  160.553 190.512 162.421 190.536 ;
     RECT  162.421 158.736 162.467 172.344 ;
     RECT  162.421 190.368 162.467 190.536 ;
     RECT  162.467 190.368 162.605 190.44 ;
     RECT  160.445 173.952 162.673 173.976 ;
     RECT  162.209 197.04 162.853 210.792 ;
     RECT  162.673 173.952 162.997 174.408 ;
     RECT  161.345 182.352 163.141 182.952 ;
     RECT  163.141 182.16 163.181 182.952 ;
     RECT  162.467 159.12 163.285 172.344 ;
     RECT  162.853 196.896 163.397 210.792 ;
     RECT  163.397 199.296 163.645 210.792 ;
     RECT  163.285 159.12 164.005 172.728 ;
     RECT  162.997 173.952 164.005 175.08 ;
     RECT  163.645 199.296 164.077 210.936 ;
     RECT  162.605 190.416 164.101 190.44 ;
     RECT  164.005 159.12 164.408 175.08 ;
     RECT  163.181 182.16 164.408 182.856 ;
     RECT  161.849 184.08 164.408 187.8 ;
     RECT  161.849 188.784 164.408 188.808 ;
     RECT  164.101 190.272 164.408 190.44 ;
     RECT  161.989 195.792 164.408 195.816 ;
     RECT  163.397 196.896 164.408 198.312 ;
     RECT  164.077 199.296 164.408 210.984 ;
     RECT  160.453 213.168 164.408 213.672 ;
     RECT  159.304 220.656 164.408 220.68 ;
     RECT  159.304 308.448 164.408 308.472 ;
     RECT  164.408 2.148 164.512 369.372 ;
     RECT  164.512 2.418 164.704 369.102 ;
     RECT  164.704 199.872 164.801 210.984 ;
     RECT  164.704 213.168 165.347 213.72 ;
     RECT  164.801 200.208 165.413 210.984 ;
     RECT  165.347 213.648 165.587 213.72 ;
     RECT  164.704 181.728 165.683 182.328 ;
     RECT  164.704 190.272 165.841 190.296 ;
     RECT  165.413 200.208 166.025 210.504 ;
     RECT  165.841 190.128 166.205 190.296 ;
     RECT  166.025 200.208 166.205 210.216 ;
     RECT  164.704 158.976 166.345 175.128 ;
     RECT  166.345 158.88 166.457 175.128 ;
     RECT  166.205 190.128 166.493 190.248 ;
     RECT  166.205 200.208 166.529 201.048 ;
     RECT  166.457 158.88 166.777 175.032 ;
     RECT  166.529 200.208 166.921 200.952 ;
     RECT  164.704 196.896 166.979 196.92 ;
     RECT  166.921 199.344 166.979 200.952 ;
     RECT  166.777 158.784 167.177 175.032 ;
     RECT  164.704 338.64 167.209 338.664 ;
     RECT  167.209 338.64 167.269 339.336 ;
     RECT  166.525 343.2 167.269 343.224 ;
     RECT  164.704 308.448 167.315 308.472 ;
     RECT  167.269 338.256 167.315 339.336 ;
     RECT  167.101 340.56 167.315 340.584 ;
     RECT  167.269 343.056 167.317 343.8 ;
     RECT  166.205 202.032 167.321 210.216 ;
     RECT  167.315 338.256 167.321 339.096 ;
     RECT  167.317 343.056 167.357 344.376 ;
     RECT  167.357 343.056 167.425 343.08 ;
     RECT  167.177 158.88 167.533 175.032 ;
     RECT  166.979 199.68 167.557 200.952 ;
     RECT  167.321 202.032 167.557 208.824 ;
     RECT  167.533 158.88 167.857 175.56 ;
     RECT  167.857 158.88 167.893 175.704 ;
     RECT  165.683 181.776 167.939 182.328 ;
     RECT  167.321 210.144 168.001 210.216 ;
     RECT  167.893 158.88 168.145 175.896 ;
     RECT  167.425 342.72 168.185 343.08 ;
     RECT  168.145 158.496 168.217 175.896 ;
     RECT  167.321 338.592 168.257 339.096 ;
     RECT  167.357 344.352 168.473 344.376 ;
     RECT  168.001 210.144 168.649 210.264 ;
     RECT  168.217 157.872 168.829 175.896 ;
     RECT  168.805 370.464 168.901 370.488 ;
     RECT  168.901 370.416 168.905 370.488 ;
     RECT  168.937 369.312 169.045 369.336 ;
     RECT  168.829 157.776 169.081 175.896 ;
     RECT  167.557 199.68 169.081 208.824 ;
     RECT  168.649 209.952 169.081 210.264 ;
     RECT  168.905 370.416 169.193 370.44 ;
     RECT  168.257 338.592 169.333 338.616 ;
     RECT  169.081 157.776 169.808 176.184 ;
     RECT  167.939 182.304 169.808 182.328 ;
     RECT  164.704 184.272 169.808 184.296 ;
     RECT  164.704 185.28 169.808 187.8 ;
     RECT  164.704 188.784 169.808 188.808 ;
     RECT  166.493 190.224 169.808 190.248 ;
     RECT  169.081 199.68 169.808 210.264 ;
     RECT  165.587 213.648 169.808 213.672 ;
     RECT  164.704 220.656 169.808 220.68 ;
     RECT  168.709 307.632 169.808 307.656 ;
     RECT  169.333 337.92 169.808 338.616 ;
     RECT  168.185 343.056 169.808 343.08 ;
     RECT  169.045 369.264 169.808 369.336 ;
     RECT  169.808 2.148 169.912 369.372 ;
     RECT  169.912 2.418 170.104 369.102 ;
     RECT  170.104 199.344 170.345 210.264 ;
     RECT  170.345 199.344 170.417 200.376 ;
     RECT  170.104 162.096 170.435 163.176 ;
     RECT  170.104 220.656 170.531 221.064 ;
     RECT  170.104 242.064 170.531 242.088 ;
     RECT  170.417 199.344 170.777 199.368 ;
     RECT  170.531 220.656 170.777 220.68 ;
     RECT  170.104 337.92 170.921 337.944 ;
     RECT  170.345 201.792 171.173 210.264 ;
     RECT  170.104 190.224 171.241 190.248 ;
     RECT  171.241 190.224 171.281 190.344 ;
     RECT  171.253 220.608 171.605 220.632 ;
     RECT  170.104 164.208 171.635 176.664 ;
     RECT  171.173 202.032 171.635 210.264 ;
     RECT  171.281 190.32 171.641 190.344 ;
     RECT  170.435 162.096 172.645 163.032 ;
     RECT  171.635 164.208 172.645 173.496 ;
     RECT  171.635 174.816 172.645 176.664 ;
     RECT  171.635 202.704 172.645 210.264 ;
     RECT  172.645 162.096 173.185 163.224 ;
     RECT  172.645 164.208 173.185 176.664 ;
     RECT  170.104 157.728 173.617 161.064 ;
     RECT  173.185 162.096 173.617 176.664 ;
     RECT  173.617 157.728 175.208 176.664 ;
     RECT  170.104 182.304 175.208 182.328 ;
     RECT  170.104 184.272 175.208 184.296 ;
     RECT  170.104 185.28 175.208 187.8 ;
     RECT  170.104 188.784 175.208 188.808 ;
     RECT  172.645 202.272 175.208 210.264 ;
     RECT  170.104 213.648 175.208 213.672 ;
     RECT  170.531 242.067 175.208 242.085 ;
     RECT  170.104 307.632 175.208 307.656 ;
     RECT  175.208 2.148 175.312 369.372 ;
     RECT  175.312 2.418 175.504 369.102 ;
     RECT  175.504 157.728 175.601 176.664 ;
     RECT  175.601 164.832 176.177 176.664 ;
     RECT  175.601 157.728 176.573 163.512 ;
     RECT  176.177 165.072 176.645 176.664 ;
     RECT  175.504 213.648 177.401 213.672 ;
     RECT  177.469 213.696 177.509 213.72 ;
     RECT  176.645 165.648 178.301 176.664 ;
     RECT  178.301 166.08 178.445 176.664 ;
     RECT  178.445 166.416 179.633 176.664 ;
     RECT  176.573 157.728 180.608 161.064 ;
     RECT  176.573 162.096 180.608 163.416 ;
     RECT  179.633 166.992 180.608 176.664 ;
     RECT  175.504 182.304 180.608 182.328 ;
     RECT  175.504 184.272 180.608 184.296 ;
     RECT  175.504 185.28 180.608 187.8 ;
     RECT  175.504 188.784 180.608 188.808 ;
     RECT  175.504 202.272 180.608 210.264 ;
     RECT  177.509 213.699 180.608 213.717 ;
     RECT  175.504 242.067 180.608 242.085 ;
     RECT  175.504 307.632 180.608 307.656 ;
     RECT  180.608 2.148 180.712 369.372 ;
     RECT  180.712 2.418 180.904 369.102 ;
     RECT  180.904 166.848 181.907 176.664 ;
     RECT  180.904 182.304 181.957 182.328 ;
     RECT  180.904 185.28 182.005 187.8 ;
     RECT  180.904 188.784 182.005 188.808 ;
     RECT  180.904 242.067 182.401 242.085 ;
     RECT  182.401 242.064 182.441 242.184 ;
     RECT  181.907 167.04 183.017 176.664 ;
     RECT  183.017 167.184 183.521 176.664 ;
     RECT  183.521 167.184 183.557 167.304 ;
     RECT  183.521 168.336 183.737 176.664 ;
     RECT  183.737 168.336 183.773 169.128 ;
     RECT  183.773 168.384 183.845 169.128 ;
     RECT  182.441 242.163 183.949 242.181 ;
     RECT  183.949 242.064 183.989 242.181 ;
     RECT  183.989 242.067 184.237 242.181 ;
     RECT  184.237 242.067 184.277 242.184 ;
     RECT  182.005 185.28 184.931 188.808 ;
     RECT  180.904 157.728 186.008 161.064 ;
     RECT  180.904 162.096 186.008 163.416 ;
     RECT  183.557 167.184 186.008 167.256 ;
     RECT  183.845 168.576 186.008 169.128 ;
     RECT  183.737 170.16 186.008 176.664 ;
     RECT  181.957 182.304 186.008 182.616 ;
     RECT  180.904 184.272 186.008 184.296 ;
     RECT  184.931 185.28 186.008 187.8 ;
     RECT  184.931 188.784 186.008 188.808 ;
     RECT  180.904 202.272 186.008 210.264 ;
     RECT  180.904 213.699 186.008 213.717 ;
     RECT  184.277 242.067 186.008 242.085 ;
     RECT  180.904 307.632 186.008 307.656 ;
     RECT  186.008 2.148 186.112 369.372 ;
     RECT  186.112 2.418 186.304 369.102 ;
     RECT  186.304 242.064 186.437 242.232 ;
     RECT  186.437 242.211 190.981 242.229 ;
     RECT  186.304 157.728 191.408 161.064 ;
     RECT  186.304 162.096 191.408 163.416 ;
     RECT  186.304 167.184 191.408 167.256 ;
     RECT  186.304 168.576 191.408 169.128 ;
     RECT  186.304 170.16 191.408 176.664 ;
     RECT  186.304 182.304 191.408 182.616 ;
     RECT  186.304 184.272 191.408 184.296 ;
     RECT  186.304 185.28 191.408 187.8 ;
     RECT  186.304 188.784 191.408 188.808 ;
     RECT  186.304 202.272 191.408 210.264 ;
     RECT  186.304 213.699 191.408 213.717 ;
     RECT  190.969 235.392 191.408 235.416 ;
     RECT  190.981 242.208 191.408 242.232 ;
     RECT  191.173 249.36 191.408 249.384 ;
     RECT  186.304 307.632 191.408 307.656 ;
     RECT  191.408 2.148 191.512 369.372 ;
     RECT  191.512 2.418 191.704 369.102 ;
     RECT  191.704 249.363 191.891 249.624 ;
     RECT  191.704 307.248 191.891 307.272 ;
     RECT  191.704 234.864 192.563 234.888 ;
     RECT  191.704 157.728 196.808 161.064 ;
     RECT  191.704 162.096 196.808 163.416 ;
     RECT  191.704 167.184 196.808 167.256 ;
     RECT  191.704 168.576 196.808 169.128 ;
     RECT  191.704 170.16 196.808 176.664 ;
     RECT  191.704 182.304 196.808 182.616 ;
     RECT  191.704 184.272 196.808 184.296 ;
     RECT  191.704 185.28 196.808 187.8 ;
     RECT  191.704 188.784 196.808 188.808 ;
     RECT  191.704 202.272 196.808 210.264 ;
     RECT  191.704 213.696 196.808 213.72 ;
     RECT  191.891 249.363 196.808 249.621 ;
     RECT  196.808 2.148 196.912 369.372 ;
     RECT  196.912 2.418 197.104 369.102 ;
     RECT  197.104 184.272 199.825 184.296 ;
     RECT  197.104 185.28 199.825 187.8 ;
     RECT  199.825 184.272 201.233 187.8 ;
     RECT  197.104 157.728 202.208 161.064 ;
     RECT  197.104 162.096 202.208 163.416 ;
     RECT  197.104 167.184 202.208 167.256 ;
     RECT  197.104 168.576 202.208 169.128 ;
     RECT  197.104 170.16 202.208 176.664 ;
     RECT  197.104 182.304 202.208 182.616 ;
     RECT  201.233 184.752 202.208 187.8 ;
     RECT  197.104 188.784 202.208 188.808 ;
     RECT  197.104 202.272 202.208 210.264 ;
     RECT  197.104 213.696 202.208 213.72 ;
     RECT  197.104 249.363 202.208 249.621 ;
     RECT  202.208 2.148 202.312 369.372 ;
     RECT  202.312 2.418 202.504 369.102 ;
     RECT  202.504 182.304 203.033 182.616 ;
     RECT  202.504 213.696 204.509 213.72 ;
     RECT  202.504 184.752 204.581 187.8 ;
     RECT  203.033 182.352 206.099 182.616 ;
     RECT  206.017 213.168 206.099 213.192 ;
     RECT  202.504 157.728 207.608 161.064 ;
     RECT  202.504 162.096 207.608 163.416 ;
     RECT  202.504 167.184 207.608 167.256 ;
     RECT  202.504 168.576 207.608 169.128 ;
     RECT  202.504 170.16 207.608 176.664 ;
     RECT  206.099 182.544 207.608 182.616 ;
     RECT  204.581 184.752 207.608 187.464 ;
     RECT  202.504 188.784 207.608 188.808 ;
     RECT  202.504 202.272 207.608 210.264 ;
     RECT  202.504 249.363 207.608 249.621 ;
     RECT  207.608 2.148 207.712 369.372 ;
     RECT  207.712 2.418 207.904 369.102 ;
     RECT  207.904 249.363 211.921 249.621 ;
     RECT  211.921 249.363 211.961 249.624 ;
     RECT  211.961 249.363 212.209 249.384 ;
     RECT  207.904 184.752 212.749 187.464 ;
     RECT  207.904 188.784 212.749 188.808 ;
     RECT  207.904 157.728 213.008 161.064 ;
     RECT  207.904 162.096 213.008 163.416 ;
     RECT  207.904 167.184 213.008 167.256 ;
     RECT  207.904 168.576 213.008 169.128 ;
     RECT  207.904 170.16 213.008 176.664 ;
     RECT  207.904 182.592 213.008 182.616 ;
     RECT  212.749 184.752 213.008 188.808 ;
     RECT  207.904 202.272 213.008 210.264 ;
     RECT  212.209 249.36 213.008 249.384 ;
     RECT  213.008 2.148 213.112 369.372 ;
     RECT  213.112 2.418 213.304 369.102 ;
     RECT  213.304 157.728 218.408 161.064 ;
     RECT  213.304 162.096 218.408 163.416 ;
     RECT  213.304 167.184 218.408 167.256 ;
     RECT  213.304 168.576 218.408 169.128 ;
     RECT  213.304 170.16 218.408 176.664 ;
     RECT  213.304 182.592 218.408 182.616 ;
     RECT  213.304 184.752 218.408 187.464 ;
     RECT  213.304 188.784 218.408 188.808 ;
     RECT  213.304 202.272 218.408 210.264 ;
     RECT  218.408 2.148 218.512 369.372 ;
     RECT  218.512 2.418 218.704 369.102 ;
     RECT  218.704 157.728 223.808 161.064 ;
     RECT  218.704 162.096 223.808 163.416 ;
     RECT  218.704 167.184 223.808 167.256 ;
     RECT  218.704 168.576 223.808 169.128 ;
     RECT  218.704 170.16 223.808 176.664 ;
     RECT  218.704 182.592 223.808 182.616 ;
     RECT  218.704 184.752 223.808 187.464 ;
     RECT  218.704 188.784 223.808 188.808 ;
     RECT  218.704 202.272 223.808 210.264 ;
     RECT  223.808 2.148 223.912 369.372 ;
     RECT  223.912 2.418 224.104 369.102 ;
     RECT  224.104 157.728 229.208 161.064 ;
     RECT  224.104 162.096 229.208 163.416 ;
     RECT  224.104 167.184 229.208 167.256 ;
     RECT  224.104 168.576 229.208 169.128 ;
     RECT  224.104 170.16 229.208 176.664 ;
     RECT  224.104 182.592 229.208 182.616 ;
     RECT  224.104 184.752 229.208 187.464 ;
     RECT  224.104 188.784 229.208 188.808 ;
     RECT  224.104 202.272 229.208 210.264 ;
     RECT  229.208 2.148 229.312 369.372 ;
     RECT  229.312 2.418 229.504 369.102 ;
     RECT  229.504 157.728 234.608 161.064 ;
     RECT  229.504 162.096 234.608 163.416 ;
     RECT  229.504 167.184 234.608 167.256 ;
     RECT  229.504 168.576 234.608 169.128 ;
     RECT  229.504 170.16 234.608 176.664 ;
     RECT  229.504 182.592 234.608 182.616 ;
     RECT  229.504 184.752 234.608 187.464 ;
     RECT  229.504 188.784 234.608 188.808 ;
     RECT  229.504 202.272 234.608 210.264 ;
     RECT  234.608 2.148 234.712 369.372 ;
     RECT  234.712 2.418 234.904 369.102 ;
     RECT  234.904 202.272 236.329 210.264 ;
     RECT  236.329 202.128 237.949 210.264 ;
     RECT  234.904 157.728 238.313 161.064 ;
     RECT  238.313 160.416 238.385 161.064 ;
     RECT  234.904 188.784 239.245 188.808 ;
     RECT  237.949 202.032 239.821 210.264 ;
     RECT  238.313 157.728 240.008 159.432 ;
     RECT  238.385 160.464 240.008 161.064 ;
     RECT  234.904 162.096 240.008 163.416 ;
     RECT  234.904 167.184 240.008 167.256 ;
     RECT  234.904 168.576 240.008 169.128 ;
     RECT  234.904 170.16 240.008 176.664 ;
     RECT  234.904 182.592 240.008 182.616 ;
     RECT  234.904 184.752 240.008 187.464 ;
     RECT  239.245 188.784 240.008 188.856 ;
     RECT  239.821 201.84 240.008 210.264 ;
     RECT  240.008 2.148 240.112 369.372 ;
     RECT  240.112 2.418 240.304 369.102 ;
     RECT  240.304 188.784 240.689 189.48 ;
     RECT  240.689 188.832 242.237 189.48 ;
     RECT  240.304 157.728 245.408 161.064 ;
     RECT  240.304 162.096 245.408 163.416 ;
     RECT  240.304 167.184 245.408 167.256 ;
     RECT  240.304 168.576 245.408 169.128 ;
     RECT  240.304 170.16 245.408 176.664 ;
     RECT  240.304 182.592 245.408 182.616 ;
     RECT  240.304 184.752 245.408 187.464 ;
     RECT  242.237 188.928 245.408 189.48 ;
     RECT  240.304 201.84 245.408 210.264 ;
     RECT  245.408 2.148 245.512 369.372 ;
     RECT  245.512 2.418 245.704 369.102 ;
     RECT  245.704 157.728 247.237 161.064 ;
     RECT  245.704 162.096 247.237 163.416 ;
     RECT  247.237 157.728 250.808 163.416 ;
     RECT  245.704 167.184 250.808 167.256 ;
     RECT  245.704 168.576 250.808 169.128 ;
     RECT  245.704 170.16 250.808 176.664 ;
     RECT  245.704 182.592 250.808 182.616 ;
     RECT  245.704 184.752 250.808 187.464 ;
     RECT  245.704 188.928 250.808 189.48 ;
     RECT  245.704 201.84 250.808 210.264 ;
     RECT  250.808 2.148 250.912 369.372 ;
     RECT  250.912 2.418 251.104 369.102 ;
     RECT  251.104 184.752 251.993 187.464 ;
     RECT  251.993 187.44 252.821 187.464 ;
     RECT  251.104 168.576 253.285 169.128 ;
     RECT  251.104 170.16 253.285 176.664 ;
     RECT  251.104 167.184 253.393 167.256 ;
     RECT  253.285 168.576 253.393 176.664 ;
     RECT  251.104 157.728 256.208 163.176 ;
     RECT  253.393 167.184 256.208 176.664 ;
     RECT  251.104 182.592 256.208 182.616 ;
     RECT  251.993 184.752 256.208 186.36 ;
     RECT  251.104 188.928 256.208 189.48 ;
     RECT  251.104 201.84 256.208 210.264 ;
     RECT  256.208 2.148 256.312 369.372 ;
     RECT  256.312 2.418 256.504 369.102 ;
     RECT  256.504 157.728 261.608 163.176 ;
     RECT  256.504 167.184 261.608 176.664 ;
     RECT  256.504 182.592 261.608 182.616 ;
     RECT  256.504 184.752 261.608 186.36 ;
     RECT  256.504 188.928 261.608 189.48 ;
     RECT  256.504 201.84 261.608 210.264 ;
     RECT  261.608 2.148 261.712 369.372 ;
     RECT  261.712 2.418 261.904 369.102 ;
     RECT  261.904 184.752 264.233 186.36 ;
     RECT  264.233 184.848 265.573 186.36 ;
     RECT  261.904 157.728 267.008 163.176 ;
     RECT  261.904 167.184 267.008 176.664 ;
     RECT  261.904 182.592 267.008 182.616 ;
     RECT  265.573 184.8 267.008 186.36 ;
     RECT  261.904 188.928 267.008 189.48 ;
     RECT  261.904 201.84 267.008 210.264 ;
     RECT  267.008 2.148 267.112 369.372 ;
     RECT  267.112 2.418 267.304 369.102 ;
     RECT  267.304 157.728 272.408 163.176 ;
     RECT  267.304 167.184 272.408 176.664 ;
     RECT  267.304 182.592 272.408 182.616 ;
     RECT  267.304 184.8 272.408 184.872 ;
     RECT  267.304 186.336 272.408 186.36 ;
     RECT  267.304 188.928 272.408 189.48 ;
     RECT  267.304 201.84 272.408 210.264 ;
     RECT  272.408 2.148 272.512 369.372 ;
     RECT  272.512 2.418 272.704 369.102 ;
     RECT  272.704 157.728 277.808 163.176 ;
     RECT  272.704 167.184 277.808 176.664 ;
     RECT  272.704 182.592 277.808 182.616 ;
     RECT  272.704 184.8 277.808 184.872 ;
     RECT  272.704 186.336 277.808 186.36 ;
     RECT  272.704 188.928 277.808 189.48 ;
     RECT  272.704 201.84 277.808 210.264 ;
     RECT  277.808 2.148 277.912 369.372 ;
     RECT  277.912 2.418 278.104 369.102 ;
     RECT  278.104 157.728 283.208 163.176 ;
     RECT  278.104 167.184 283.208 176.664 ;
     RECT  278.104 182.592 283.208 182.616 ;
     RECT  278.104 184.8 283.208 184.872 ;
     RECT  278.104 186.336 283.208 186.36 ;
     RECT  278.104 188.928 283.208 189.48 ;
     RECT  278.104 201.84 283.208 210.264 ;
     RECT  283.208 2.148 283.312 369.372 ;
     RECT  283.312 2.418 283.504 369.102 ;
     RECT  283.504 157.728 285.293 163.176 ;
     RECT  283.504 186.336 286.153 186.36 ;
     RECT  286.153 186.288 286.165 186.36 ;
     RECT  286.165 186.288 286.211 186.936 ;
     RECT  286.211 186.336 286.517 186.936 ;
     RECT  285.293 157.728 287.413 160.296 ;
     RECT  285.293 161.376 287.413 163.176 ;
     RECT  287.413 157.728 288.608 163.176 ;
     RECT  283.504 167.184 288.608 176.664 ;
     RECT  283.504 182.592 288.608 182.616 ;
     RECT  283.504 184.8 288.608 184.872 ;
     RECT  286.517 186.912 288.608 186.936 ;
     RECT  283.504 188.928 288.608 189.96 ;
     RECT  283.504 201.84 288.608 210.264 ;
     RECT  288.608 2.148 288.712 369.372 ;
     RECT  288.712 2.418 288.904 369.102 ;
     RECT  288.904 157.728 290.221 160.584 ;
     RECT  288.904 161.616 290.221 163.176 ;
     RECT  290.221 157.728 290.797 163.176 ;
     RECT  288.904 167.184 290.977 176.664 ;
     RECT  290.797 157.728 291.301 163.464 ;
     RECT  288.904 186.912 292.525 186.936 ;
     RECT  291.301 157.728 294.008 163.512 ;
     RECT  290.977 166.992 294.008 176.664 ;
     RECT  288.904 182.592 294.008 182.616 ;
     RECT  288.904 184.8 294.008 184.872 ;
     RECT  292.525 186.912 294.008 187.512 ;
     RECT  288.904 188.928 294.008 189.96 ;
     RECT  288.904 201.84 294.008 210.264 ;
     RECT  294.008 2.148 294.112 369.372 ;
     RECT  294.112 2.418 294.304 369.102 ;
     RECT  294.304 157.728 294.401 163.512 ;
     RECT  294.304 184.8 296.197 184.872 ;
     RECT  296.197 184.656 296.809 184.872 ;
     RECT  296.809 184.56 297.673 184.872 ;
     RECT  294.401 157.728 299.408 163.464 ;
     RECT  294.304 166.992 299.408 176.664 ;
     RECT  294.304 182.592 299.408 182.616 ;
     RECT  297.673 184.56 299.408 185.16 ;
     RECT  294.304 186.912 299.408 187.512 ;
     RECT  294.304 188.928 299.408 189.96 ;
     RECT  294.304 201.84 299.408 210.264 ;
     RECT  299.408 2.148 299.512 369.372 ;
     RECT  299.512 2.418 299.704 369.102 ;
     RECT  299.704 157.728 304.808 163.464 ;
     RECT  299.704 166.992 304.808 176.664 ;
     RECT  299.704 182.592 304.808 182.616 ;
     RECT  299.704 184.56 304.808 185.16 ;
     RECT  299.704 186.912 304.808 187.512 ;
     RECT  299.704 188.928 304.808 189.96 ;
     RECT  299.704 201.84 304.808 210.264 ;
     RECT  304.808 2.148 304.912 369.372 ;
     RECT  304.912 2.418 305.104 369.102 ;
     RECT  305.104 157.728 306.997 163.464 ;
     RECT  306.997 157.584 310.208 163.464 ;
     RECT  305.104 166.992 310.208 176.664 ;
     RECT  305.104 182.592 310.208 182.616 ;
     RECT  305.104 184.56 310.208 185.16 ;
     RECT  305.104 186.912 310.208 187.512 ;
     RECT  305.104 188.928 310.208 189.96 ;
     RECT  305.104 201.84 310.208 210.264 ;
     RECT  310.208 2.148 310.312 369.372 ;
     RECT  310.312 2.418 310.504 369.102 ;
     RECT  310.504 157.584 315.608 163.464 ;
     RECT  310.504 166.992 315.608 176.664 ;
     RECT  310.504 182.592 315.608 182.616 ;
     RECT  310.504 184.56 315.608 185.16 ;
     RECT  310.504 186.912 315.608 187.512 ;
     RECT  310.504 188.928 315.608 189.96 ;
     RECT  310.504 201.84 315.608 210.264 ;
     RECT  315.608 2.148 315.712 369.372 ;
     RECT  315.712 2.418 315.904 369.102 ;
     RECT  315.904 186.912 317.045 187.512 ;
     RECT  317.045 187.488 317.437 187.512 ;
     RECT  315.904 188.928 317.437 189.96 ;
     RECT  317.437 187.488 318.049 189.96 ;
     RECT  318.049 187.296 318.301 189.96 ;
     RECT  315.904 184.56 318.325 185.16 ;
     RECT  318.325 184.56 318.565 185.688 ;
     RECT  318.301 187.152 318.565 189.96 ;
     RECT  315.904 166.992 319.525 176.664 ;
     RECT  315.904 201.84 319.889 210.264 ;
     RECT  318.565 184.56 320.281 189.96 ;
     RECT  320.281 184.56 320.497 190.824 ;
     RECT  315.904 157.584 321.008 163.464 ;
     RECT  319.525 166.992 321.008 176.76 ;
     RECT  315.904 182.592 321.008 182.616 ;
     RECT  320.497 184.32 321.008 190.824 ;
     RECT  319.889 201.84 321.008 210.216 ;
     RECT  321.008 2.148 321.112 369.372 ;
     RECT  321.112 2.418 321.304 369.102 ;
     RECT  321.304 182.4 321.539 191.352 ;
     RECT  321.304 177.984 322.357 181.32 ;
     RECT  321.539 182.4 322.357 191.016 ;
     RECT  321.304 166.992 322.477 176.856 ;
     RECT  322.357 177.984 322.477 191.016 ;
     RECT  322.477 166.992 322.501 191.016 ;
     RECT  322.501 166.992 322.549 191.64 ;
     RECT  322.597 193.44 322.693 193.464 ;
     RECT  322.693 193.296 322.837 193.464 ;
     RECT  322.549 166.992 322.981 192.12 ;
     RECT  322.837 193.248 322.981 193.464 ;
     RECT  322.981 166.992 324.085 193.464 ;
     RECT  324.085 166.992 324.385 193.848 ;
     RECT  324.385 166.992 324.457 193.896 ;
     RECT  324.457 166.992 324.565 193.944 ;
     RECT  324.565 166.992 324.709 194.568 ;
     RECT  324.709 166.992 324.757 194.952 ;
     RECT  321.304 157.584 324.889 163.464 ;
     RECT  324.757 166.992 325.907 195.096 ;
     RECT  325.907 193.824 325.955 195.096 ;
     RECT  325.907 166.992 325.973 192.792 ;
     RECT  325.955 193.824 325.973 193.848 ;
     RECT  325.955 194.928 325.973 195.096 ;
     RECT  325.973 180.72 326.003 192.792 ;
     RECT  325.973 177.984 326.009 178.344 ;
     RECT  326.003 180.72 326.009 192.696 ;
     RECT  326.009 180.816 326.045 192.696 ;
     RECT  326.009 178.32 326.051 178.344 ;
     RECT  326.045 181.104 326.051 191.496 ;
     RECT  326.045 192.672 326.051 192.696 ;
     RECT  326.051 181.104 326.099 181.176 ;
     RECT  326.099 181.152 326.195 181.176 ;
     RECT  321.304 201.84 326.581 210.216 ;
     RECT  326.581 201.84 326.617 210.408 ;
     RECT  326.617 201.84 327.193 210.6 ;
     RECT  327.193 201.84 327.697 210.984 ;
     RECT  325.973 166.992 327.733 176.52 ;
     RECT  326.051 182.592 328.057 191.496 ;
     RECT  324.889 157.488 328.129 163.464 ;
     RECT  327.697 201.84 328.133 211.08 ;
     RECT  328.057 182.592 328.241 191.88 ;
     RECT  328.129 157.392 328.284 163.464 ;
     RECT  327.733 166.608 328.284 176.52 ;
     RECT  328.241 182.736 328.284 191.88 ;
     RECT  328.133 201.936 328.284 211.08 ;
    LAYER M5 ;
     RECT  2.4 2.137 2.52 2.151 ;
     RECT  7.8 2.137 7.92 2.151 ;
     RECT  13.2 2.137 13.32 2.151 ;
     RECT  18.6 2.137 18.72 2.151 ;
     RECT  24 2.137 24.12 2.151 ;
     RECT  29.4 2.137 29.52 2.151 ;
     RECT  34.8 2.137 34.92 2.151 ;
     RECT  40.2 2.137 40.32 2.151 ;
     RECT  45.6 2.137 45.72 2.151 ;
     RECT  51 2.137 51.12 2.151 ;
     RECT  56.4 2.137 56.52 2.151 ;
     RECT  61.8 2.137 61.92 2.151 ;
     RECT  67.2 2.137 67.32 2.151 ;
     RECT  72.6 2.137 72.72 2.151 ;
     RECT  78 2.137 78.12 2.151 ;
     RECT  83.4 2.137 83.52 2.151 ;
     RECT  88.8 2.137 88.92 2.151 ;
     RECT  94.2 2.137 94.32 2.151 ;
     RECT  99.6 2.137 99.72 2.151 ;
     RECT  105 2.137 105.12 2.151 ;
     RECT  110.4 2.137 110.52 2.151 ;
     RECT  115.8 2.137 115.92 2.151 ;
     RECT  121.2 2.137 121.32 2.151 ;
     RECT  126.6 2.137 126.72 2.151 ;
     RECT  132 2.137 132.12 2.151 ;
     RECT  137.4 2.137 137.52 2.151 ;
     RECT  142.8 2.137 142.92 2.151 ;
     RECT  148.2 2.137 148.32 2.151 ;
     RECT  153.6 2.137 153.72 2.151 ;
     RECT  159 2.137 159.12 2.151 ;
     RECT  164.4 2.137 164.52 2.151 ;
     RECT  169.8 2.137 169.92 2.151 ;
     RECT  175.2 2.137 175.32 2.151 ;
     RECT  180.6 2.137 180.72 2.151 ;
     RECT  186 2.137 186.12 2.151 ;
     RECT  191.4 2.137 191.52 2.151 ;
     RECT  196.8 2.137 196.92 2.151 ;
     RECT  202.2 2.137 202.32 2.151 ;
     RECT  207.6 2.137 207.72 2.151 ;
     RECT  213 2.137 213.12 2.151 ;
     RECT  218.4 2.137 218.52 2.151 ;
     RECT  223.8 2.137 223.92 2.151 ;
     RECT  229.2 2.137 229.32 2.151 ;
     RECT  234.6 2.137 234.72 2.151 ;
     RECT  240 2.137 240.12 2.151 ;
     RECT  245.4 2.137 245.52 2.151 ;
     RECT  250.8 2.137 250.92 2.151 ;
     RECT  256.2 2.137 256.32 2.151 ;
     RECT  261.6 2.137 261.72 2.151 ;
     RECT  267 2.137 267.12 2.151 ;
     RECT  272.4 2.137 272.52 2.151 ;
     RECT  277.8 2.137 277.92 2.151 ;
     RECT  283.2 2.137 283.32 2.151 ;
     RECT  288.6 2.137 288.72 2.151 ;
     RECT  294 2.137 294.12 2.151 ;
     RECT  299.4 2.137 299.52 2.151 ;
     RECT  304.8 2.137 304.92 2.151 ;
     RECT  310.2 2.137 310.32 2.151 ;
     RECT  315.6 2.137 315.72 2.151 ;
     RECT  321 2.137 321.12 2.151 ;
     RECT  325.824 158.053 325.848 158.483 ;
     RECT  307.2 158.005 307.224 158.531 ;
     RECT  277.8 2.151 278.112 158.581 ;
     RECT  328.128 158.677 328.152 158.867 ;
     RECT  167.04 158.869 167.064 158.917 ;
     RECT  162.432 158.725 162.456 159.109 ;
     RECT  162.432 159.109 162.792 159.157 ;
     RECT  277.8 158.581 278.232 159.203 ;
     RECT  164.4 2.151 164.712 159.445 ;
     RECT  167.04 158.917 167.592 159.635 ;
     RECT  167.04 159.635 167.496 160.211 ;
     RECT  164.112 159.445 164.712 160.309 ;
     RECT  162.432 159.157 163.08 160.453 ;
     RECT  288.6 2.151 288.912 160.549 ;
     RECT  161.856 160.453 163.08 160.693 ;
     RECT  164.112 160.309 165.288 160.693 ;
     RECT  161.424 160.693 165.288 160.787 ;
     RECT  161.424 160.787 164.712 161.363 ;
     RECT  167.088 160.211 167.496 161.363 ;
     RECT  287.808 160.549 288.912 161.363 ;
     RECT  161.424 161.363 162.936 161.411 ;
     RECT  157.104 160.789 157.128 161.555 ;
     RECT  148.2 2.151 148.512 161.845 ;
     RECT  164.4 161.363 164.712 162.085 ;
     RECT  169.8 2.151 170.112 162.229 ;
     RECT  160.416 160.117 160.44 162.277 ;
     RECT  167.088 161.363 167.112 162.323 ;
     RECT  152.16 161.269 152.184 162.373 ;
     RECT  159 2.151 159.312 162.373 ;
     RECT  160.416 162.277 160.728 162.373 ;
     RECT  152.112 162.373 152.184 162.421 ;
     RECT  153.6 2.151 153.912 162.421 ;
     RECT  142.8 2.151 143.112 162.469 ;
     RECT  324.288 161.989 324.312 162.515 ;
     RECT  159 162.373 160.728 162.565 ;
     RECT  161.808 161.411 162.936 162.565 ;
     RECT  142.656 162.469 143.112 162.613 ;
     RECT  319.536 162.373 319.56 162.755 ;
     RECT  142.56 162.613 143.112 162.947 ;
     RECT  164.4 162.085 165.576 162.949 ;
     RECT  166.752 162.373 166.776 162.949 ;
     RECT  148.2 161.845 148.632 162.997 ;
     RECT  159 162.565 162.936 163.043 ;
     RECT  159 163.043 162.456 163.139 ;
     RECT  0.288 161.701 0.312 163.187 ;
     RECT  169.8 162.229 170.424 163.187 ;
     RECT  159 163.139 161.016 163.477 ;
     RECT  152.112 162.421 153.912 163.619 ;
     RECT  158.4 163.477 161.016 163.667 ;
     RECT  158.4 163.667 160.728 163.715 ;
     RECT  168.672 162.997 168.696 163.811 ;
     RECT  148.2 162.997 148.776 164.005 ;
     RECT  157.008 162.757 157.032 164.005 ;
     RECT  175.2 2.151 175.512 164.053 ;
     RECT  149.856 163.525 149.88 164.101 ;
     RECT  162 163.139 162.456 164.101 ;
     RECT  164.4 162.949 166.776 164.195 ;
     RECT  164.4 164.195 166.44 164.293 ;
     RECT  149.856 164.101 150.216 164.389 ;
     RECT  151.728 163.957 151.8 164.389 ;
     RECT  157.008 164.005 157.272 164.389 ;
     RECT  162 164.101 163.128 164.485 ;
     RECT  161.808 164.485 163.128 164.531 ;
     RECT  155.568 164.197 155.592 164.677 ;
     RECT  157.008 164.389 157.32 164.677 ;
     RECT  158.4 163.715 159.528 164.677 ;
     RECT  160.704 163.715 160.728 164.677 ;
     RECT  171.84 162.997 171.864 164.677 ;
     RECT  149.856 164.389 151.8 164.771 ;
     RECT  155.568 164.677 157.32 164.771 ;
     RECT  142.8 162.947 143.112 164.773 ;
     RECT  164.304 164.293 166.44 164.773 ;
     RECT  158.4 164.677 160.728 164.819 ;
     RECT  169.8 163.187 170.112 164.821 ;
     RECT  156.144 164.771 157.32 164.867 ;
     RECT  161.808 164.531 162.504 164.915 ;
     RECT  156.672 164.867 157.32 165.109 ;
     RECT  158.88 164.819 160.728 165.109 ;
     RECT  161.808 164.915 162.456 165.109 ;
     RECT  148.08 164.005 148.776 165.205 ;
     RECT  150.192 164.771 151.8 165.253 ;
     RECT  168.096 164.245 168.12 165.253 ;
     RECT  169.68 164.821 170.112 165.253 ;
     RECT  171.552 164.677 171.864 165.253 ;
     RECT  141.888 164.773 143.112 165.347 ;
     RECT  158.88 165.109 162.456 165.395 ;
     RECT  150.192 165.253 151.848 165.397 ;
     RECT  137.4 2.151 137.712 165.445 ;
     RECT  145.872 165.349 145.896 165.493 ;
     RECT  150.192 165.397 152.232 165.587 ;
     RECT  142.368 165.347 143.112 165.733 ;
     RECT  151.056 165.587 152.232 165.781 ;
     RECT  148.032 165.205 148.776 165.829 ;
     RECT  153.6 163.619 153.912 165.829 ;
     RECT  154.944 164.917 155.016 165.829 ;
     RECT  164.16 164.773 166.44 165.829 ;
     RECT  175.104 164.053 175.512 165.829 ;
     RECT  148.032 165.829 150.072 165.971 ;
     RECT  145.296 165.493 145.896 166.117 ;
     RECT  173.232 165.781 173.256 166.117 ;
     RECT  174.816 165.829 175.512 166.117 ;
     RECT  168.096 165.253 171.864 166.165 ;
     RECT  156.672 165.109 157.656 166.309 ;
     RECT  151.056 165.781 152.28 166.357 ;
     RECT  153.6 165.829 155.016 166.357 ;
     RECT  156.672 166.309 157.8 166.405 ;
     RECT  145.296 166.117 146.808 166.453 ;
     RECT  145.008 166.453 146.808 166.499 ;
     RECT  163.44 165.829 166.44 166.499 ;
     RECT  145.008 166.499 145.32 166.547 ;
     RECT  159 165.395 162.456 166.547 ;
     RECT  168.096 166.165 172.152 166.547 ;
     RECT  142.368 165.733 143.64 166.595 ;
     RECT  148.08 165.971 150.072 166.597 ;
     RECT  151.056 166.357 155.016 166.597 ;
     RECT  162.432 166.547 162.456 166.645 ;
     RECT  168.912 166.547 172.152 166.787 ;
     RECT  156.096 166.405 157.8 166.789 ;
     RECT  159 166.547 161.4 166.789 ;
     RECT  180.6 2.151 180.912 166.837 ;
     RECT  156.096 166.789 161.4 166.931 ;
     RECT  142.8 166.595 143.592 166.979 ;
     RECT  158.64 166.931 161.4 166.979 ;
     RECT  171.84 166.787 172.152 167.075 ;
     RECT  162.432 166.645 162.984 167.123 ;
     RECT  178.272 166.405 178.296 167.123 ;
     RECT  146.784 166.499 146.808 167.125 ;
     RECT  148.08 166.597 155.016 167.125 ;
     RECT  145.008 166.547 145.032 167.171 ;
     RECT  158.832 166.979 161.4 167.171 ;
     RECT  164.208 166.499 166.44 167.171 ;
     RECT  160.704 167.171 161.4 167.267 ;
     RECT  164.208 167.171 165.864 167.267 ;
     RECT  146.784 167.125 155.016 167.269 ;
     RECT  156.096 166.931 157.608 167.269 ;
     RECT  180.6 166.837 181.896 167.461 ;
     RECT  180.6 167.461 182.808 167.509 ;
     RECT  146.784 167.269 157.608 167.555 ;
     RECT  162.96 167.123 162.984 167.557 ;
     RECT  146.784 167.555 155.016 167.651 ;
     RECT  173.232 166.117 175.512 167.653 ;
     RECT  137.4 165.445 138.504 167.747 ;
     RECT  156.096 167.555 157.608 167.747 ;
     RECT  162.96 167.557 163.032 167.749 ;
     RECT  164.208 167.267 165.24 167.749 ;
     RECT  167.712 167.701 167.736 167.797 ;
     RECT  168.912 166.787 170.424 167.797 ;
     RECT  167.712 167.797 170.424 167.843 ;
     RECT  158.832 167.171 159.528 167.941 ;
     RECT  171.84 167.075 171.864 168.085 ;
     RECT  141.312 166.981 141.336 168.131 ;
     RECT  150.336 167.651 155.016 168.275 ;
     RECT  156.096 167.747 156.936 168.275 ;
     RECT  150.384 168.275 155.016 168.323 ;
     RECT  156.576 168.275 156.936 168.371 ;
     RECT  158.736 167.941 159.528 168.421 ;
     RECT  180.48 167.509 182.808 168.613 ;
     RECT  140.832 168.565 140.856 168.661 ;
     RECT  158.736 168.421 159.96 168.661 ;
     RECT  173.184 167.653 175.512 168.707 ;
     RECT  158.256 168.661 159.96 168.709 ;
     RECT  161.232 167.267 161.4 168.709 ;
     RECT  150.384 168.323 151.032 168.755 ;
     RECT  152.208 168.323 155.016 168.755 ;
     RECT  171.84 168.085 172.2 168.755 ;
     RECT  180.432 168.613 182.808 168.755 ;
     RECT  168.672 167.843 170.424 168.805 ;
     RECT  150.384 168.755 150.408 168.851 ;
     RECT  142.8 166.979 143.112 168.853 ;
     RECT  162.96 167.749 165.24 168.853 ;
     RECT  142.8 168.853 143.592 168.901 ;
     RECT  173.76 168.707 175.512 168.947 ;
     RECT  146.784 167.651 149.352 168.997 ;
     RECT  162.96 168.853 165.384 168.997 ;
     RECT  177.072 166.981 177.096 169.043 ;
     RECT  168.096 168.805 170.424 169.189 ;
     RECT  158.256 168.709 161.4 169.235 ;
     RECT  168.096 169.189 170.76 169.237 ;
     RECT  171.984 168.755 172.2 169.237 ;
     RECT  168.048 169.237 170.76 169.285 ;
     RECT  152.64 168.755 155.016 169.331 ;
     RECT  158.448 169.235 161.4 169.331 ;
     RECT  166.608 168.613 166.632 169.331 ;
     RECT  140.736 168.661 140.856 169.381 ;
     RECT  145.872 168.997 149.352 169.381 ;
     RECT  168.048 169.285 170.808 169.381 ;
     RECT  158.448 169.331 161.304 169.427 ;
     RECT  180.432 168.755 182.376 169.427 ;
     RECT  153.312 169.331 155.016 169.669 ;
     RECT  2.4 2.151 2.712 169.717 ;
     RECT  151.536 169.525 151.56 169.765 ;
     RECT  168.048 169.381 171 169.765 ;
     RECT  171.984 169.237 172.68 169.765 ;
     RECT  144.864 169.717 144.888 169.813 ;
     RECT  156.672 168.371 156.936 169.859 ;
     RECT  145.872 169.381 149.88 169.907 ;
     RECT  173.76 168.947 173.784 169.907 ;
     RECT  153.312 169.669 155.4 169.955 ;
     RECT  154.896 169.955 155.4 169.957 ;
     RECT  154.896 169.957 155.496 170.005 ;
     RECT  167.808 169.765 172.68 170.051 ;
     RECT  151.536 169.765 152.184 170.053 ;
     RECT  2.304 169.717 2.712 170.099 ;
     RECT  146.784 169.907 149.88 170.099 ;
     RECT  154.896 170.005 155.592 170.147 ;
     RECT  146.784 170.099 148.776 170.195 ;
     RECT  169.68 170.051 172.68 170.195 ;
     RECT  142.512 168.901 143.592 170.341 ;
     RECT  144.816 169.813 144.888 170.341 ;
     RECT  151.488 170.053 152.184 170.341 ;
     RECT  140.736 169.381 141.336 170.389 ;
     RECT  158.448 169.427 159.576 170.389 ;
     RECT  160.56 169.427 161.304 170.389 ;
     RECT  167.808 170.051 168.696 170.389 ;
     RECT  140.016 170.389 141.336 170.435 ;
     RECT  155.472 170.147 155.592 170.435 ;
     RECT  167.472 170.389 168.696 170.435 ;
     RECT  158.448 170.389 161.304 170.437 ;
     RECT  162.432 168.997 165.384 170.437 ;
     RECT  179.424 168.853 179.448 170.437 ;
     RECT  180.432 169.427 181.944 170.437 ;
     RECT  142.512 170.341 144.888 170.483 ;
     RECT  155.568 170.435 155.592 170.483 ;
     RECT  158.448 170.437 165.384 170.483 ;
     RECT  167.472 170.435 168.12 170.483 ;
     RECT  178.368 169.621 178.392 170.483 ;
     RECT  179.424 170.437 181.944 170.483 ;
     RECT  325.152 170.389 325.176 170.485 ;
     RECT  147.072 170.195 148.776 170.531 ;
     RECT  153.312 169.955 153.912 170.531 ;
     RECT  158.88 170.483 165.384 170.531 ;
     RECT  149.76 170.099 149.88 170.581 ;
     RECT  151.008 170.341 152.184 170.581 ;
     RECT  141.168 170.435 141.336 170.629 ;
     RECT  142.512 170.483 144.84 170.629 ;
     RECT  169.68 170.195 172.008 170.675 ;
     RECT  149.76 170.581 152.184 170.723 ;
     RECT  141.168 170.629 144.84 170.771 ;
     RECT  147.456 170.531 148.776 170.771 ;
     RECT  177.552 170.773 177.576 170.821 ;
     RECT  156.72 169.859 156.936 170.869 ;
     RECT  175.2 168.947 175.512 170.869 ;
     RECT  324.72 170.485 325.176 170.869 ;
     RECT  153.6 170.531 153.912 170.917 ;
     RECT  179.424 170.483 180.912 170.965 ;
     RECT  181.92 170.483 181.944 170.965 ;
     RECT  161.28 170.531 165.384 171.013 ;
     RECT  151.008 170.723 152.184 171.059 ;
     RECT  161.28 171.013 165.912 171.059 ;
     RECT  167.472 170.483 168.072 171.059 ;
     RECT  173.088 170.245 173.592 171.059 ;
     RECT  175.104 170.869 175.8 171.061 ;
     RECT  167.472 171.059 167.496 171.107 ;
     RECT  178.944 170.965 180.912 171.203 ;
     RECT  153.6 170.917 154.2 171.205 ;
     RECT  177.216 170.821 177.576 171.205 ;
     RECT  181.92 170.965 182.376 171.347 ;
     RECT  165.696 171.059 165.912 171.397 ;
     RECT  324.72 170.869 325.704 171.493 ;
     RECT  0.144 171.253 0.168 171.539 ;
     RECT  151.2 171.059 152.184 171.635 ;
     RECT  161.808 171.059 164.712 171.635 ;
     RECT  178.944 171.203 178.968 171.635 ;
     RECT  175.104 171.061 176.136 171.637 ;
     RECT  174.816 171.637 176.136 171.683 ;
     RECT  142.512 170.771 144.84 171.731 ;
     RECT  151.2 171.635 152.136 171.731 ;
     RECT  174.816 171.683 175.8 171.731 ;
     RECT  177.12 171.205 177.576 171.731 ;
     RECT  142.608 171.731 144.84 171.733 ;
     RECT  158.88 170.531 160.152 171.779 ;
     RECT  165.696 171.397 166.44 171.781 ;
     RECT  147.456 170.771 148.728 171.829 ;
     RECT  149.76 170.723 149.976 171.829 ;
     RECT  174.816 171.731 175.608 171.877 ;
     RECT  140.016 170.435 140.04 171.923 ;
     RECT  142.608 171.733 144.936 171.923 ;
     RECT  156.384 170.869 156.936 171.925 ;
     RECT  158.88 171.779 159.576 172.019 ;
     RECT  162.96 171.635 164.712 172.069 ;
     RECT  165.696 171.781 166.488 172.069 ;
     RECT  162.96 172.069 166.488 172.115 ;
     RECT  142.656 171.923 144.216 172.163 ;
     RECT  147.456 171.829 149.976 172.163 ;
     RECT  153.6 171.205 154.44 172.163 ;
     RECT  158.88 172.019 159.528 172.163 ;
     RECT  161.808 171.635 161.832 172.163 ;
     RECT  177.12 171.731 177.24 172.163 ;
     RECT  172.656 171.301 172.68 172.165 ;
     RECT  181.968 171.347 182.376 172.259 ;
     RECT  142.704 172.163 144.216 172.355 ;
     RECT  159 172.163 159.528 172.355 ;
     RECT  142.8 172.355 144.216 172.403 ;
     RECT  147.456 172.163 149.4 172.403 ;
     RECT  151.2 171.731 151.752 172.403 ;
     RECT  167.904 172.069 167.928 172.453 ;
     RECT  177.216 172.163 177.24 172.595 ;
     RECT  179.952 171.203 180.912 172.595 ;
     RECT  163.152 172.115 166.488 172.597 ;
     RECT  167.904 172.453 168.408 172.597 ;
     RECT  324.48 171.493 325.704 172.597 ;
     RECT  172.656 172.165 173.256 172.643 ;
     RECT  324.384 172.597 325.704 172.645 ;
     RECT  142.8 172.403 144.072 172.691 ;
     RECT  173.232 172.643 173.256 172.739 ;
     RECT  174.384 171.877 175.608 172.739 ;
     RECT  178.464 172.069 178.488 172.739 ;
     RECT  174.432 172.739 175.608 172.931 ;
     RECT  169.68 170.675 171.624 172.981 ;
     RECT  324.192 172.645 325.704 172.981 ;
     RECT  147.744 172.403 149.4 173.027 ;
     RECT  324.192 172.981 325.848 173.077 ;
     RECT  156.096 171.925 156.936 173.171 ;
     RECT  163.152 172.597 168.408 173.171 ;
     RECT  174.432 172.931 175.512 173.219 ;
     RECT  323.712 173.077 325.848 173.221 ;
     RECT  168.384 173.171 168.408 173.267 ;
     RECT  153.6 172.163 154.2 173.269 ;
     RECT  151.2 172.403 151.224 173.315 ;
     RECT  153.504 173.269 154.2 173.315 ;
     RECT  164.4 173.171 167.016 173.315 ;
     RECT  147.744 173.027 148.512 173.555 ;
     RECT  323.712 173.221 325.896 173.557 ;
     RECT  150.192 173.125 150.216 173.653 ;
     RECT  323.712 173.557 325.944 173.701 ;
     RECT  323.712 173.701 326.04 173.797 ;
     RECT  159 172.355 159.432 173.941 ;
     RECT  150.192 173.653 151.032 173.987 ;
     RECT  163.152 173.171 163.176 174.373 ;
     RECT  164.4 173.315 166.776 174.373 ;
     RECT  159 173.941 159.576 174.467 ;
     RECT  323.616 173.797 326.04 174.467 ;
     RECT  169.632 172.981 171.624 174.469 ;
     RECT  163.008 174.373 166.776 174.995 ;
     RECT  164.4 174.995 166.776 175.043 ;
     RECT  169.344 174.469 171.624 175.043 ;
     RECT  323.616 174.467 325.992 175.043 ;
     RECT  163.008 174.995 163.032 175.091 ;
     RECT  159 174.467 159.312 175.477 ;
     RECT  321 2.151 321.312 175.525 ;
     RECT  323.616 175.043 325.944 175.525 ;
     RECT  169.344 175.043 170.424 175.619 ;
     RECT  323.376 175.525 325.944 175.619 ;
     RECT  167.904 174.613 167.928 175.669 ;
     RECT  321 175.525 322.296 175.669 ;
     RECT  323.376 175.619 325.464 175.669 ;
     RECT  153.504 173.315 153.912 175.717 ;
     RECT  321 175.669 325.464 176.195 ;
     RECT  171.552 175.043 171.624 176.243 ;
     RECT  158.448 175.477 159.312 176.675 ;
     RECT  169.8 175.619 170.424 176.675 ;
     RECT  319.536 175.477 319.56 176.771 ;
     RECT  153.504 175.717 154.152 176.963 ;
     RECT  156.384 173.171 156.936 177.061 ;
     RECT  153.504 176.963 153.912 177.491 ;
     RECT  321 176.195 325.368 177.781 ;
     RECT  321 177.781 325.8 178.067 ;
     RECT  324.288 178.067 325.8 178.309 ;
     RECT  153.6 177.491 153.912 179.077 ;
     RECT  155.52 177.061 156.936 179.077 ;
     RECT  321 178.067 323.16 179.221 ;
     RECT  324.288 178.309 326.04 179.221 ;
     RECT  153.6 179.077 156.936 179.603 ;
     RECT  321 179.221 326.04 181.093 ;
     RECT  321 181.093 326.088 181.141 ;
     RECT  156.192 179.603 156.936 181.283 ;
     RECT  321 181.141 326.184 181.571 ;
     RECT  167.904 175.669 168.456 181.811 ;
     RECT  154.944 181.237 154.968 181.859 ;
     RECT  156.768 181.283 156.936 182.149 ;
     RECT  156.768 182.149 157.56 182.197 ;
     RECT  156.768 182.197 157.704 182.293 ;
     RECT  159 176.675 159.312 182.293 ;
     RECT  164.4 175.043 165.672 182.339 ;
     RECT  156.768 182.293 159.312 182.435 ;
     RECT  163.152 182.149 163.176 182.627 ;
     RECT  181.968 172.259 182.04 182.627 ;
     RECT  110.4 2.151 110.712 182.725 ;
     RECT  155.568 182.821 155.592 182.917 ;
     RECT  156.768 182.435 157.704 182.917 ;
     RECT  126.6 2.151 126.912 183.157 ;
     RECT  99.6 2.151 99.912 183.205 ;
     RECT  102.528 182.341 102.552 183.205 ;
     RECT  321 181.571 321.576 183.301 ;
     RECT  322.704 181.571 326.184 183.347 ;
     RECT  140.448 172.117 140.472 183.443 ;
     RECT  2.4 170.099 2.712 183.493 ;
     RECT  83.4 2.151 83.712 183.493 ;
     RECT  155.568 182.917 157.704 183.493 ;
     RECT  158.88 182.435 159.312 183.493 ;
     RECT  161.28 182.725 161.304 183.587 ;
     RECT  99.6 183.205 100.152 183.685 ;
     RECT  121.2 2.151 121.512 183.733 ;
     RECT  2.4 183.493 2.808 183.779 ;
     RECT  321 183.301 321.624 183.781 ;
     RECT  322.704 183.347 326.04 183.781 ;
     RECT  99.504 183.685 100.152 184.069 ;
     RECT  105 2.151 105.312 184.069 ;
     RECT  102.048 183.205 102.552 184.163 ;
     RECT  110.4 182.725 111.144 184.163 ;
     RECT  104.88 184.069 105.312 184.165 ;
     RECT  104.88 184.165 106.008 184.261 ;
     RECT  104.88 184.261 106.824 184.307 ;
     RECT  112.752 183.445 112.776 184.403 ;
     RECT  82.176 184.069 82.2 184.499 ;
     RECT  160.704 184.261 160.728 184.499 ;
     RECT  155.568 183.493 159.312 184.501 ;
     RECT  115.8 2.151 116.112 184.549 ;
     RECT  155.568 184.501 159.576 184.549 ;
     RECT  321 183.781 326.04 184.597 ;
     RECT  102.48 184.163 102.552 184.645 ;
     RECT  103.728 184.069 103.752 184.645 ;
     RECT  155.568 184.549 160.2 184.645 ;
     RECT  110.4 184.163 110.808 184.739 ;
     RECT  320.88 184.597 326.04 184.739 ;
     RECT  110.4 184.739 110.712 184.741 ;
     RECT  115.8 184.549 116.616 184.741 ;
     RECT  102.48 184.645 103.752 184.787 ;
     RECT  148.2 173.555 148.512 184.837 ;
     RECT  115.44 184.741 116.616 184.883 ;
     RECT  99.504 184.069 100.296 184.885 ;
     RECT  108.816 183.493 108.84 184.885 ;
     RECT  97.44 183.973 97.464 185.029 ;
     RECT  117.936 184.741 117.96 185.075 ;
     RECT  97.44 185.029 98.184 185.077 ;
     RECT  99.504 184.885 101.016 185.077 ;
     RECT  110.304 184.741 110.712 185.077 ;
     RECT  121.2 183.733 121.608 185.077 ;
     RECT  97.44 185.077 101.016 185.171 ;
     RECT  126.384 183.157 126.912 185.173 ;
     RECT  102.48 184.787 102.792 185.267 ;
     RECT  98.592 185.171 101.016 185.269 ;
     RECT  115.8 184.883 116.616 185.269 ;
     RECT  163.056 182.917 163.08 185.315 ;
     RECT  265.584 184.789 265.608 185.315 ;
     RECT  114.048 185.365 114.072 185.413 ;
     RECT  121.2 185.077 121.992 185.461 ;
     RECT  115.8 185.269 116.712 185.507 ;
     RECT  168.432 181.811 168.456 185.603 ;
     RECT  155.328 184.645 160.2 185.605 ;
     RECT  184.8 185.557 184.824 185.605 ;
     RECT  117.888 185.461 117.912 185.651 ;
     RECT  105 184.307 106.824 185.797 ;
     RECT  320.88 184.739 325.848 185.797 ;
     RECT  110.208 185.077 110.712 185.843 ;
     RECT  155.328 185.605 160.392 185.843 ;
     RECT  184.8 185.605 184.92 185.843 ;
     RECT  96.288 185.221 96.312 185.891 ;
     RECT  97.296 185.221 97.32 185.891 ;
     RECT  102.768 185.267 102.792 185.891 ;
     RECT  119.712 185.077 119.736 185.891 ;
     RECT  157.44 185.843 160.392 185.891 ;
     RECT  148.2 184.837 149.496 186.083 ;
     RECT  155.328 185.843 156.216 186.083 ;
     RECT  123.504 184.837 123.528 186.085 ;
     RECT  114.048 185.413 114.696 186.131 ;
     RECT  320.544 185.797 325.848 186.131 ;
     RECT  157.92 185.891 160.392 186.133 ;
     RECT  142.8 172.691 143.112 186.181 ;
     RECT  148.2 186.083 148.512 186.181 ;
     RECT  83.184 183.493 83.712 186.227 ;
     RECT  98.592 185.269 101.112 186.323 ;
     RECT  157.92 186.133 160.776 186.325 ;
     RECT  100.992 186.323 101.112 186.371 ;
     RECT  98.592 186.323 99.912 186.373 ;
     RECT  117.408 185.653 117.432 186.419 ;
     RECT  121.2 185.461 122.52 186.419 ;
     RECT  123.504 186.085 123.624 186.419 ;
     RECT  157.92 186.325 161.304 186.419 ;
     RECT  126.24 185.173 126.912 186.421 ;
     RECT  108.48 184.885 108.84 186.467 ;
     RECT  125.04 183.205 125.064 186.467 ;
     RECT  318.336 185.653 318.36 186.469 ;
     RECT  157.968 186.419 161.304 186.515 ;
     RECT  98.496 186.373 99.912 186.899 ;
     RECT  148.08 186.181 148.512 186.901 ;
     RECT  108.576 186.467 108.84 186.947 ;
     RECT  123.504 186.419 123.528 186.947 ;
     RECT  286.176 186.277 286.2 186.947 ;
     RECT  98.496 186.899 98.616 186.995 ;
     RECT  102.816 186.277 102.84 186.995 ;
     RECT  104.832 185.797 106.824 186.995 ;
     RECT  155.52 186.083 156.216 186.995 ;
     RECT  121.2 186.419 121.608 187.043 ;
     RECT  98.496 186.995 98.52 187.139 ;
     RECT  318.336 186.469 318.6 187.187 ;
     RECT  112.032 185.893 112.056 187.237 ;
     RECT  100.992 186.371 101.016 187.429 ;
     RECT  111.936 187.237 112.056 187.429 ;
     RECT  0.144 187.285 0.168 187.475 ;
     RECT  320.544 186.131 325.464 187.525 ;
     RECT  105 186.995 106.824 187.571 ;
     RECT  320.544 187.525 326.04 187.571 ;
     RECT  147.504 186.901 148.512 187.619 ;
     RECT  158.64 186.515 161.304 187.667 ;
     RECT  126.144 186.421 126.912 187.763 ;
     RECT  106.512 187.571 106.824 187.811 ;
     RECT  100.992 187.429 101.976 187.859 ;
     RECT  110.304 185.843 110.712 187.861 ;
     RECT  111.936 187.429 112.92 187.861 ;
     RECT  103.2 187.813 103.224 188.051 ;
     RECT  106.656 187.811 106.824 188.051 ;
     RECT  158.64 187.667 160.776 188.051 ;
     RECT  101.952 187.859 101.976 188.053 ;
     RECT  108.816 186.947 108.84 188.053 ;
     RECT  110.304 187.861 112.92 188.053 ;
     RECT  153.6 179.603 153.912 188.053 ;
     RECT  101.952 188.053 102.072 188.147 ;
     RECT  155.52 186.995 155.544 188.147 ;
     RECT  184.896 185.843 184.92 188.147 ;
     RECT  318.576 187.187 318.6 188.147 ;
     RECT  108.816 188.053 112.92 188.195 ;
     RECT  182.016 182.627 182.04 188.291 ;
     RECT  105 187.571 105.312 188.533 ;
     RECT  108.816 188.195 112.872 188.579 ;
     RECT  108.816 188.579 109.416 188.723 ;
     RECT  158.64 188.051 160.152 188.723 ;
     RECT  119.808 186.229 119.832 188.771 ;
     RECT  321 187.571 326.04 188.771 ;
     RECT  114.672 186.131 114.696 188.773 ;
     RECT  102.048 188.147 102.072 188.819 ;
     RECT  110.4 188.579 112.872 188.819 ;
     RECT  114.576 188.773 114.696 188.819 ;
     RECT  321 188.771 325.944 188.819 ;
     RECT  114.576 188.819 114.6 188.915 ;
     RECT  111.936 188.819 112.872 189.155 ;
     RECT  111.936 189.155 111.96 189.203 ;
     RECT  104.832 188.533 105.312 189.299 ;
     RECT  109.392 188.723 109.416 189.299 ;
     RECT  159 188.723 160.152 189.299 ;
     RECT  319.056 188.581 319.08 189.299 ;
     RECT  107.424 188.053 107.448 189.347 ;
     RECT  328.128 189.301 328.152 189.491 ;
     RECT  155.904 188.965 155.928 189.875 ;
     RECT  159 189.299 159.576 190.261 ;
     RECT  164.4 182.339 164.712 190.261 ;
     RECT  171.6 176.243 171.624 190.309 ;
     RECT  164.112 190.261 164.712 190.405 ;
     RECT  158.4 190.261 159.576 190.547 ;
     RECT  162.432 190.357 162.456 190.547 ;
     RECT  321 188.819 325.464 190.693 ;
     RECT  321 190.693 325.896 191.027 ;
     RECT  322.512 191.027 325.896 191.077 ;
     RECT  321 191.027 321.528 191.363 ;
     RECT  158.4 190.547 159.528 191.555 ;
     RECT  322.512 191.077 326.04 191.651 ;
     RECT  158.4 191.555 159.432 191.989 ;
     RECT  156.864 190.885 156.888 192.131 ;
     RECT  322.56 191.651 326.04 192.131 ;
     RECT  152.976 188.053 153.912 192.613 ;
     RECT  322.608 192.131 326.04 192.707 ;
     RECT  322.608 192.707 325.992 192.803 ;
     RECT  0.288 192.037 0.312 193.139 ;
     RECT  152.88 192.613 153.912 193.189 ;
     RECT  322.608 192.803 325.944 193.283 ;
     RECT  322.608 193.283 322.728 193.331 ;
     RECT  322.608 193.331 322.632 193.475 ;
     RECT  158.256 191.989 159.432 193.621 ;
     RECT  158.256 193.621 159.528 193.669 ;
     RECT  157.488 193.669 159.528 193.765 ;
     RECT  156.768 193.765 159.528 193.811 ;
     RECT  324.096 193.283 325.944 193.859 ;
     RECT  158.256 193.811 159.528 194.341 ;
     RECT  152.88 193.189 154.104 194.435 ;
     RECT  324.576 193.859 325.944 194.579 ;
     RECT  156.768 193.811 156.792 194.629 ;
     RECT  158.256 194.341 159.576 194.629 ;
     RECT  324.72 194.579 325.944 194.675 ;
     RECT  152.88 194.435 153.912 194.963 ;
     RECT  324.72 194.675 324.792 194.963 ;
     RECT  325.92 194.675 325.944 195.011 ;
     RECT  158.256 194.629 160.104 195.107 ;
     RECT  324.768 194.963 324.792 195.107 ;
     RECT  151.008 173.987 151.032 195.299 ;
     RECT  158.304 195.107 160.104 195.539 ;
     RECT  163.728 190.405 164.712 195.781 ;
     RECT  153.12 194.963 153.912 196.307 ;
     RECT  156.48 194.629 156.792 196.501 ;
     RECT  158.304 195.539 159.312 196.501 ;
     RECT  160.464 195.973 160.488 196.981 ;
     RECT  153.6 196.307 153.912 198.037 ;
     RECT  160.464 196.981 160.584 198.277 ;
     RECT  161.664 197.173 161.688 198.277 ;
     RECT  142.8 186.181 143.352 198.371 ;
     RECT  156.48 196.501 159.312 198.419 ;
     RECT  156.816 198.419 159.312 198.467 ;
     RECT  154.992 196.597 155.016 198.899 ;
     RECT  158.592 198.467 159.312 199.093 ;
     RECT  152.688 198.037 153.912 199.381 ;
     RECT  163.584 195.781 164.712 199.477 ;
     RECT  152.448 199.381 153.912 199.523 ;
     RECT  160.464 198.277 161.688 200.005 ;
     RECT  163.008 199.477 164.712 200.005 ;
     RECT  166.944 196.885 166.968 200.051 ;
     RECT  156.816 198.467 157.464 200.099 ;
     RECT  160.464 200.005 164.712 200.099 ;
     RECT  157.248 200.099 157.464 200.147 ;
     RECT  162.288 200.099 164.712 200.243 ;
     RECT  165.936 185.557 165.96 200.435 ;
     RECT  158.592 199.093 159.432 200.437 ;
     RECT  160.464 200.099 160.488 200.437 ;
     RECT  152.448 199.523 152.472 200.581 ;
     RECT  158.592 200.437 160.488 200.675 ;
     RECT  168.768 200.725 168.792 201.061 ;
     RECT  162.288 200.243 162.504 201.107 ;
     RECT  162.288 201.107 162.312 201.109 ;
     RECT  165.888 200.581 165.912 201.109 ;
     RECT  168.672 201.061 168.792 201.157 ;
     RECT  169.8 176.675 170.112 201.157 ;
     RECT  155.232 200.965 155.256 201.251 ;
     RECT  161.568 201.109 162.312 201.443 ;
     RECT  159 200.675 160.488 201.491 ;
     RECT  153.6 199.523 153.912 201.733 ;
     RECT  157.44 200.147 157.464 201.733 ;
     RECT  159 201.491 159.312 201.733 ;
     RECT  165.792 201.109 165.912 201.733 ;
     RECT  157.44 201.733 159.312 201.827 ;
     RECT  168.672 201.157 170.112 201.827 ;
     RECT  168.672 201.827 168.792 201.875 ;
     RECT  167.568 201.205 167.592 202.067 ;
     RECT  152.208 200.581 152.472 202.213 ;
     RECT  152.16 202.213 152.472 202.261 ;
     RECT  153.6 201.733 154.632 202.261 ;
     RECT  148.2 187.619 148.512 202.309 ;
     RECT  152.16 202.261 154.632 202.309 ;
     RECT  163.728 200.243 164.712 202.309 ;
     RECT  165.696 201.733 165.912 202.309 ;
     RECT  168.672 201.875 168.696 202.403 ;
     RECT  169.8 201.827 170.112 202.453 ;
     RECT  171.264 190.309 171.624 202.453 ;
     RECT  163.296 202.309 165.912 202.643 ;
     RECT  169.8 202.453 171.624 202.741 ;
     RECT  172.656 202.261 172.68 202.741 ;
     RECT  148.2 202.309 148.632 202.933 ;
     RECT  158.16 201.827 159.312 202.979 ;
     RECT  167.136 202.309 167.16 202.979 ;
     RECT  169.8 202.741 172.68 202.979 ;
     RECT  169.8 202.979 172.008 203.027 ;
     RECT  152.16 202.309 154.968 203.075 ;
     RECT  152.16 203.075 152.472 203.173 ;
     RECT  161.568 201.443 161.592 203.173 ;
     RECT  163.296 202.643 165.864 203.173 ;
     RECT  175.2 173.219 175.512 203.173 ;
     RECT  156.336 202.741 156.36 203.365 ;
     RECT  169.8 203.027 170.28 203.365 ;
     RECT  161.568 203.173 165.864 203.411 ;
     RECT  156.144 203.365 156.36 203.413 ;
     RECT  157.344 203.221 157.368 203.413 ;
     RECT  161.568 203.411 162.456 203.459 ;
     RECT  148.2 202.933 148.824 203.461 ;
     RECT  324.912 202.309 324.936 203.461 ;
     RECT  156.144 203.413 157.368 203.555 ;
     RECT  163.728 203.411 165.864 203.555 ;
     RECT  148.2 203.461 150.504 203.603 ;
     RECT  324.912 203.461 325.464 203.603 ;
     RECT  153.6 203.075 154.968 203.605 ;
     RECT  156.144 203.555 156.168 203.605 ;
     RECT  149.664 203.603 150.504 203.749 ;
     RECT  153.6 203.605 156.168 203.795 ;
     RECT  158.784 202.979 159.312 203.845 ;
     RECT  160.464 201.491 160.488 203.845 ;
     RECT  154.944 203.795 156.168 203.939 ;
     RECT  158.784 203.845 160.488 203.989 ;
     RECT  152.064 203.173 152.472 204.037 ;
     RECT  153.6 203.795 153.912 204.037 ;
     RECT  163.92 203.555 165.864 204.037 ;
     RECT  167.088 203.221 167.112 204.037 ;
     RECT  168.096 203.893 168.12 204.037 ;
     RECT  169.248 203.365 170.28 204.037 ;
     RECT  149.664 203.749 150.6 204.083 ;
     RECT  168.096 204.037 170.28 204.083 ;
     RECT  174.96 203.173 175.512 204.083 ;
     RECT  162.432 203.459 162.456 204.227 ;
     RECT  142.8 198.371 143.208 204.277 ;
     RECT  126.24 187.763 126.912 204.323 ;
     RECT  145.296 204.037 145.32 204.421 ;
     RECT  169.8 204.083 170.28 204.421 ;
     RECT  171.264 203.027 172.008 204.421 ;
     RECT  145.296 204.421 145.416 204.563 ;
     RECT  147.024 203.413 147.048 204.565 ;
     RECT  148.2 203.603 148.68 204.565 ;
     RECT  158.784 203.989 160.728 204.565 ;
     RECT  163.92 204.037 167.112 204.659 ;
     RECT  158.64 204.565 160.728 204.707 ;
     RECT  173.232 203.701 173.256 204.707 ;
     RECT  157.152 203.555 157.368 204.755 ;
     RECT  157.344 204.755 157.368 204.901 ;
     RECT  158.64 204.707 159.312 204.901 ;
     RECT  142.8 204.277 143.688 204.997 ;
     RECT  160.464 204.707 160.728 204.997 ;
     RECT  147.024 204.565 148.68 205.043 ;
     RECT  168.096 204.083 168.6 205.043 ;
     RECT  169.8 204.421 172.008 205.045 ;
     RECT  150.48 204.083 150.6 205.093 ;
     RECT  166.32 204.659 167.112 205.093 ;
     RECT  325.344 203.603 325.464 205.139 ;
     RECT  173.28 204.757 173.496 205.141 ;
     RECT  149.856 205.093 150.6 205.187 ;
     RECT  147.024 205.043 148.512 205.235 ;
     RECT  155.568 203.939 156.168 205.235 ;
     RECT  160.464 204.997 161.496 205.235 ;
     RECT  166.32 205.093 167.688 205.379 ;
     RECT  163.92 204.659 165.144 205.573 ;
     RECT  168.72 205.045 172.008 205.669 ;
     RECT  157.344 204.901 159.312 205.715 ;
     RECT  152.064 204.037 153.912 205.765 ;
     RECT  142.272 204.997 143.688 205.811 ;
     RECT  149.856 205.187 150.312 205.811 ;
     RECT  151.728 205.765 153.912 205.811 ;
     RECT  167.664 205.379 167.688 205.811 ;
     RECT  173.28 205.141 173.832 205.859 ;
     RECT  153.504 205.811 153.912 205.909 ;
     RECT  154.944 205.429 155.016 205.909 ;
     RECT  161.472 205.235 161.496 205.909 ;
     RECT  157.68 205.715 159.312 206.003 ;
     RECT  149.904 205.811 150.312 206.051 ;
     RECT  151.728 205.811 152.472 206.051 ;
     RECT  157.968 206.003 159.312 206.101 ;
     RECT  160.464 205.235 160.488 206.101 ;
     RECT  156.192 205.717 156.216 206.245 ;
     RECT  161.472 205.909 162.504 206.291 ;
     RECT  163.584 205.573 165.144 206.293 ;
     RECT  166.32 205.379 166.44 206.293 ;
     RECT  323.712 205.717 323.736 206.293 ;
     RECT  325.44 205.139 325.464 206.341 ;
     RECT  325.44 206.341 325.56 206.387 ;
     RECT  163.584 206.293 166.44 206.437 ;
     RECT  325.536 206.387 325.56 206.437 ;
     RECT  325.536 206.437 325.656 206.483 ;
     RECT  157.968 206.101 160.488 206.485 ;
     RECT  157.968 206.485 160.536 206.531 ;
     RECT  325.632 206.483 325.656 206.579 ;
     RECT  161.664 206.291 162.504 206.581 ;
     RECT  163.584 206.437 166.872 206.581 ;
     RECT  2.4 183.779 2.712 206.677 ;
     RECT  146.304 205.861 146.328 206.723 ;
     RECT  168.72 205.669 172.248 206.723 ;
     RECT  153.504 205.909 155.016 206.725 ;
     RECT  156.192 206.245 156.552 206.725 ;
     RECT  142.272 205.811 143.208 206.773 ;
     RECT  152.448 206.051 152.472 206.821 ;
     RECT  153.504 206.725 156.552 206.821 ;
     RECT  2.304 206.677 2.712 206.867 ;
     RECT  141.888 206.773 143.208 206.869 ;
     RECT  168.72 206.723 172.008 206.869 ;
     RECT  152.448 206.821 156.552 206.963 ;
     RECT  161.664 206.581 166.872 206.963 ;
     RECT  168.48 206.869 172.008 206.963 ;
     RECT  147.408 205.235 148.512 207.011 ;
     RECT  158.352 206.531 160.536 207.011 ;
     RECT  168.48 206.963 168.744 207.011 ;
     RECT  169.8 206.963 172.008 207.011 ;
     RECT  326.592 206.869 326.616 207.155 ;
     RECT  168.48 207.011 168.696 207.203 ;
     RECT  141.888 206.869 143.256 207.299 ;
     RECT  323.616 206.293 323.736 207.347 ;
     RECT  161.664 206.963 166.536 207.395 ;
     RECT  149.904 206.051 149.928 207.397 ;
     RECT  161.664 207.395 165.48 207.443 ;
     RECT  142.8 207.299 143.256 207.539 ;
     RECT  155.568 206.963 156.552 207.539 ;
     RECT  158.4 207.011 160.536 207.539 ;
     RECT  161.664 207.443 165.288 207.539 ;
     RECT  155.568 207.539 155.592 207.587 ;
     RECT  149.856 207.397 149.928 207.635 ;
     RECT  147.6 207.011 148.512 207.731 ;
     RECT  323.616 207.347 323.688 207.731 ;
     RECT  168.624 207.203 168.696 207.779 ;
     RECT  148.2 207.731 148.512 207.781 ;
     RECT  148.2 207.781 148.824 207.923 ;
     RECT  323.664 207.731 323.688 207.923 ;
     RECT  149.856 207.635 149.88 207.971 ;
     RECT  169.8 207.011 171.528 207.973 ;
     RECT  158.688 207.539 160.536 208.021 ;
     RECT  175.2 204.083 175.512 208.021 ;
     RECT  325.44 207.445 325.464 208.021 ;
     RECT  168.624 207.779 168.648 208.115 ;
     RECT  152.448 206.963 154.488 208.165 ;
     RECT  174.384 208.021 175.512 208.259 ;
     RECT  152.016 208.165 154.488 208.307 ;
     RECT  162.48 207.539 165.288 208.307 ;
     RECT  328.08 208.357 328.104 208.499 ;
     RECT  169.68 207.973 171.528 208.549 ;
     RECT  325.392 208.021 325.464 208.549 ;
     RECT  152.736 208.307 154.488 208.595 ;
     RECT  169.68 208.549 172.152 208.595 ;
     RECT  166.512 207.395 166.536 208.643 ;
     RECT  325.344 208.549 325.464 209.075 ;
     RECT  151.008 209.029 151.032 209.125 ;
     RECT  162.48 208.307 163.032 209.125 ;
     RECT  164.4 208.307 165.288 209.125 ;
     RECT  169.68 208.595 170.112 209.125 ;
     RECT  325.392 209.075 325.464 209.173 ;
     RECT  325.392 209.173 325.56 209.315 ;
     RECT  171.264 208.595 172.152 209.363 ;
     RECT  161.808 209.125 163.032 209.507 ;
     RECT  150.864 209.125 151.032 209.699 ;
     RECT  151.008 209.699 151.032 209.795 ;
     RECT  158.688 208.021 160.728 209.795 ;
     RECT  162.96 209.507 163.032 209.795 ;
     RECT  164.4 209.125 165.864 209.795 ;
     RECT  161.808 209.507 161.88 209.843 ;
     RECT  169.2 209.125 170.112 209.891 ;
     RECT  325.392 209.315 325.416 209.939 ;
     RECT  152.736 208.595 153.912 209.987 ;
     RECT  164.4 209.795 165.336 210.181 ;
     RECT  158.688 209.795 160.488 210.371 ;
     RECT  162.96 209.795 162.984 210.371 ;
     RECT  161.856 209.843 161.88 210.947 ;
     RECT  164.112 210.181 165.336 210.947 ;
     RECT  158.688 210.371 159.312 213.157 ;
     RECT  142.8 207.539 143.208 213.203 ;
     RECT  206.064 182.341 206.088 213.203 ;
     RECT  158.496 213.157 159.312 213.683 ;
     RECT  160.464 210.371 160.488 213.683 ;
     RECT  148.2 207.923 148.512 213.685 ;
     RECT  164.4 210.947 165.336 213.685 ;
     RECT  191.4 2.151 191.712 213.685 ;
     RECT  191.4 213.685 192.552 213.731 ;
     RECT  171.264 209.363 171.288 220.643 ;
     RECT  148.2 213.685 148.632 220.691 ;
     RECT  169.8 209.891 170.112 221.029 ;
     RECT  169.8 221.029 170.52 221.075 ;
     RECT  191.4 213.731 192.549 234.853 ;
     RECT  191.4 234.853 192.552 234.899 ;
     RECT  191.4 234.899 191.712 235.381 ;
     RECT  169.8 221.075 170.517 242.053 ;
     RECT  169.8 242.053 170.52 242.099 ;
     RECT  190.992 235.381 191.712 242.243 ;
     RECT  191.187 242.243 191.712 249.349 ;
     RECT  191.184 249.349 191.712 249.395 ;
     RECT  191.4 249.395 191.712 249.589 ;
     RECT  191.4 249.589 191.88 249.635 ;
     RECT  76.848 188.965 76.872 300.179 ;
     RECT  191.4 249.635 191.877 307.237 ;
     RECT  191.4 307.237 191.88 307.283 ;
     RECT  168.72 307.621 168.744 337.909 ;
     RECT  169.8 242.099 170.112 337.909 ;
     RECT  168.72 337.909 170.112 338.627 ;
     RECT  164.4 213.685 165.576 338.675 ;
     RECT  167.28 308.437 167.304 343.811 ;
     RECT  168.72 338.627 168.744 369.253 ;
     RECT  169.8 338.627 170.112 369.253 ;
     RECT  2.4 206.867 2.712 369.369 ;
     RECT  7.8 2.151 8.112 369.369 ;
     RECT  13.2 2.151 13.512 369.369 ;
     RECT  18.6 2.151 18.912 369.369 ;
     RECT  24 2.151 24.312 369.369 ;
     RECT  29.4 2.151 29.712 369.369 ;
     RECT  34.8 2.151 35.112 369.369 ;
     RECT  40.2 2.151 40.512 369.369 ;
     RECT  45.6 2.151 45.912 369.369 ;
     RECT  51 2.151 51.312 369.369 ;
     RECT  56.4 2.151 56.712 369.369 ;
     RECT  61.8 2.151 62.112 369.369 ;
     RECT  67.2 2.151 67.512 369.369 ;
     RECT  72.6 2.151 72.912 369.369 ;
     RECT  78 2.151 78.312 369.369 ;
     RECT  83.4 186.227 83.712 369.369 ;
     RECT  88.8 2.151 89.112 369.369 ;
     RECT  94.2 2.151 94.512 369.369 ;
     RECT  99.6 186.899 99.912 369.369 ;
     RECT  105 189.299 105.312 369.369 ;
     RECT  110.4 188.819 110.712 369.369 ;
     RECT  115.8 185.507 116.112 369.369 ;
     RECT  121.2 187.043 121.512 369.369 ;
     RECT  126.6 204.323 126.912 369.369 ;
     RECT  132 2.151 132.312 369.369 ;
     RECT  137.4 167.747 137.712 369.369 ;
     RECT  142.8 213.203 143.112 369.369 ;
     RECT  148.2 220.691 148.512 369.369 ;
     RECT  153.6 209.987 153.912 369.369 ;
     RECT  159 213.683 159.312 369.369 ;
     RECT  164.4 338.675 164.712 369.369 ;
     RECT  168.72 369.253 170.112 369.369 ;
     RECT  175.2 208.259 175.512 369.369 ;
     RECT  180.6 172.595 180.912 369.369 ;
     RECT  186 2.151 186.312 369.369 ;
     RECT  191.4 307.283 191.712 369.369 ;
     RECT  196.8 2.151 197.112 369.369 ;
     RECT  202.2 2.151 202.512 369.369 ;
     RECT  207.6 2.151 207.912 369.369 ;
     RECT  213 2.151 213.312 369.369 ;
     RECT  218.4 2.151 218.712 369.369 ;
     RECT  223.8 2.151 224.112 369.369 ;
     RECT  229.2 2.151 229.512 369.369 ;
     RECT  234.6 2.151 234.912 369.369 ;
     RECT  240 2.151 240.312 369.369 ;
     RECT  245.4 2.151 245.712 369.369 ;
     RECT  250.8 2.151 251.112 369.369 ;
     RECT  256.2 2.151 256.512 369.369 ;
     RECT  261.6 2.151 261.912 369.369 ;
     RECT  267 2.151 267.312 369.369 ;
     RECT  272.4 2.151 272.712 369.369 ;
     RECT  277.8 159.203 278.112 369.369 ;
     RECT  283.2 2.151 283.512 369.369 ;
     RECT  288.6 161.363 288.912 369.369 ;
     RECT  294 2.151 294.312 369.369 ;
     RECT  299.4 2.151 299.712 369.369 ;
     RECT  304.8 2.151 305.112 369.369 ;
     RECT  310.2 2.151 310.512 369.369 ;
     RECT  315.6 2.151 315.912 369.369 ;
     RECT  321 191.363 321.312 369.369 ;
     RECT  2.4 369.369 2.52 369.383 ;
     RECT  7.8 369.369 7.92 369.383 ;
     RECT  13.2 369.369 13.32 369.383 ;
     RECT  18.6 369.369 18.72 369.383 ;
     RECT  24 369.369 24.12 369.383 ;
     RECT  29.4 369.369 29.52 369.383 ;
     RECT  34.8 369.369 34.92 369.383 ;
     RECT  40.2 369.369 40.32 369.383 ;
     RECT  45.6 369.369 45.72 369.383 ;
     RECT  51 369.369 51.12 369.383 ;
     RECT  56.4 369.369 56.52 369.383 ;
     RECT  61.8 369.369 61.92 369.383 ;
     RECT  67.2 369.369 67.32 369.383 ;
     RECT  72.6 369.369 72.72 369.383 ;
     RECT  78 369.369 78.12 369.383 ;
     RECT  83.4 369.369 83.52 369.383 ;
     RECT  88.8 369.369 88.92 369.383 ;
     RECT  94.2 369.369 94.32 369.383 ;
     RECT  99.6 369.369 99.72 369.383 ;
     RECT  105 369.369 105.12 369.383 ;
     RECT  110.4 369.369 110.52 369.383 ;
     RECT  115.8 369.369 115.92 369.383 ;
     RECT  121.2 369.369 121.32 369.383 ;
     RECT  126.6 369.369 126.72 369.383 ;
     RECT  132 369.369 132.12 369.383 ;
     RECT  137.4 369.369 137.52 369.383 ;
     RECT  142.8 369.369 142.92 369.383 ;
     RECT  148.2 369.369 148.32 369.383 ;
     RECT  153.6 369.369 153.72 369.383 ;
     RECT  159 369.369 159.12 369.383 ;
     RECT  164.4 369.369 164.52 369.383 ;
     RECT  168.72 369.369 169.92 369.383 ;
     RECT  175.2 369.369 175.32 369.383 ;
     RECT  180.6 369.369 180.72 369.383 ;
     RECT  186 369.369 186.12 369.383 ;
     RECT  191.4 369.369 191.52 369.383 ;
     RECT  196.8 369.369 196.92 369.383 ;
     RECT  202.2 369.369 202.32 369.383 ;
     RECT  207.6 369.369 207.72 369.383 ;
     RECT  213 369.369 213.12 369.383 ;
     RECT  218.4 369.369 218.52 369.383 ;
     RECT  223.8 369.369 223.92 369.383 ;
     RECT  229.2 369.369 229.32 369.383 ;
     RECT  234.6 369.369 234.72 369.383 ;
     RECT  240 369.369 240.12 369.383 ;
     RECT  245.4 369.369 245.52 369.383 ;
     RECT  250.8 369.369 250.92 369.383 ;
     RECT  256.2 369.369 256.32 369.383 ;
     RECT  261.6 369.369 261.72 369.383 ;
     RECT  267 369.369 267.12 369.383 ;
     RECT  272.4 369.369 272.52 369.383 ;
     RECT  277.8 369.369 277.92 369.383 ;
     RECT  283.2 369.369 283.32 369.383 ;
     RECT  288.6 369.369 288.72 369.383 ;
     RECT  294 369.369 294.12 369.383 ;
     RECT  299.4 369.369 299.52 369.383 ;
     RECT  304.8 369.369 304.92 369.383 ;
     RECT  310.2 369.369 310.32 369.383 ;
     RECT  315.6 369.369 315.72 369.383 ;
     RECT  321 369.369 321.12 369.383 ;
     RECT  168.72 369.383 169.128 371.472 ;
  END
END ot_qwen_kvc_decode_pc
END LIBRARY
